VERSION 5.8 ;
BUSBITCHARS "[]" ;
DIVIDERCHAR "/" ;
UNITS
    DATABASE MICRONS 1000 ;
END UNITS

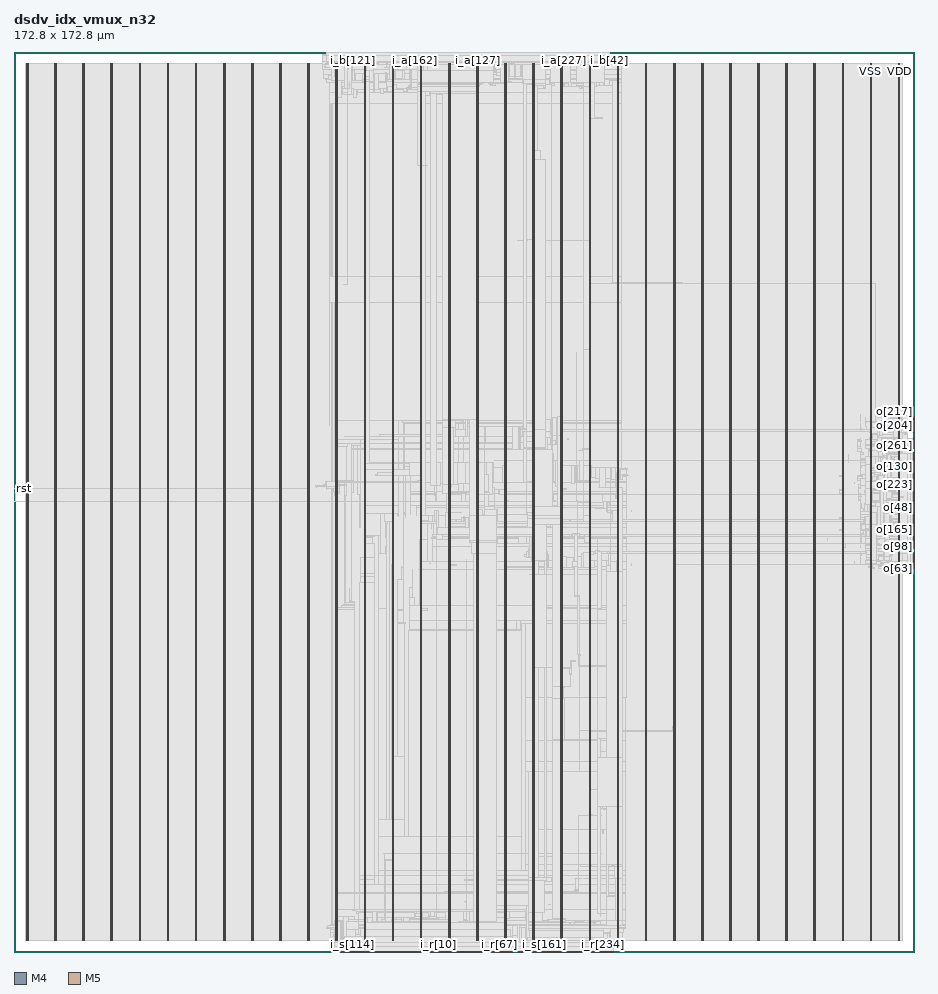
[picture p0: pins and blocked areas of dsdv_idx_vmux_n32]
MACRO dsdv_idx_vmux_n32
  FOREIGN dsdv_idx_vmux_n32 0 0 ;
  CLASS BLOCK ;
  SIZE 172.8 BY 172.8 ;
  PIN ck
    DIRECTION INPUT ;
    USE SIGNAL ;
    PORT
      LAYER M4 ;
        RECT  0 88.944 0.084 88.968 ;
    END
  END ck
  PIN fault
    DIRECTION OUTPUT ;
    USE SIGNAL ;
    PORT
      LAYER M4 ;
        RECT  172.716 86.736 172.8 86.76 ;
    END
  END fault
  PIN i_a[0]
    DIRECTION INPUT ;
    USE SIGNAL ;
    PORT
      LAYER M5 ;
        RECT  79.92 172.716 79.944 172.8 ;
    END
  END i_a[0]
  PIN i_a[100]
    DIRECTION INPUT ;
    USE SIGNAL ;
    PORT
      LAYER M5 ;
        RECT  86.448 172.716 86.472 172.8 ;
    END
  END i_a[100]
  PIN i_a[101]
    DIRECTION INPUT ;
    USE SIGNAL ;
    PORT
      LAYER M5 ;
        RECT  86.544 172.716 86.568 172.8 ;
    END
  END i_a[101]
  PIN i_a[102]
    DIRECTION INPUT ;
    USE SIGNAL ;
    PORT
      LAYER M5 ;
        RECT  86.64 172.716 86.664 172.8 ;
    END
  END i_a[102]
  PIN i_a[103]
    DIRECTION INPUT ;
    USE SIGNAL ;
    PORT
      LAYER M5 ;
        RECT  86.736 172.716 86.76 172.8 ;
    END
  END i_a[103]
  PIN i_a[104]
    DIRECTION INPUT ;
    USE SIGNAL ;
    PORT
      LAYER M5 ;
        RECT  86.832 172.716 86.856 172.8 ;
    END
  END i_a[104]
  PIN i_a[105]
    DIRECTION INPUT ;
    USE SIGNAL ;
    PORT
      LAYER M5 ;
        RECT  86.928 172.716 86.952 172.8 ;
    END
  END i_a[105]
  PIN i_a[106]
    DIRECTION INPUT ;
    USE SIGNAL ;
    PORT
      LAYER M5 ;
        RECT  87.024 172.716 87.048 172.8 ;
    END
  END i_a[106]
  PIN i_a[107]
    DIRECTION INPUT ;
    USE SIGNAL ;
    PORT
      LAYER M5 ;
        RECT  87.12 172.716 87.144 172.8 ;
    END
  END i_a[107]
  PIN i_a[108]
    DIRECTION INPUT ;
    USE SIGNAL ;
    PORT
      LAYER M5 ;
        RECT  87.216 172.716 87.24 172.8 ;
    END
  END i_a[108]
  PIN i_a[109]
    DIRECTION INPUT ;
    USE SIGNAL ;
    PORT
      LAYER M5 ;
        RECT  87.312 172.716 87.336 172.8 ;
    END
  END i_a[109]
  PIN i_a[10]
    DIRECTION INPUT ;
    USE SIGNAL ;
    PORT
      LAYER M5 ;
        RECT  80.88 172.716 80.904 172.8 ;
    END
  END i_a[10]
  PIN i_a[110]
    DIRECTION INPUT ;
    USE SIGNAL ;
    PORT
      LAYER M5 ;
        RECT  87.408 172.716 87.432 172.8 ;
    END
  END i_a[110]
  PIN i_a[111]
    DIRECTION INPUT ;
    USE SIGNAL ;
    PORT
      LAYER M5 ;
        RECT  87.504 172.716 87.528 172.8 ;
    END
  END i_a[111]
  PIN i_a[112]
    DIRECTION INPUT ;
    USE SIGNAL ;
    PORT
      LAYER M5 ;
        RECT  87.6 172.716 87.624 172.8 ;
    END
  END i_a[112]
  PIN i_a[113]
    DIRECTION INPUT ;
    USE SIGNAL ;
    PORT
      LAYER M5 ;
        RECT  87.696 172.716 87.72 172.8 ;
    END
  END i_a[113]
  PIN i_a[114]
    DIRECTION INPUT ;
    USE SIGNAL ;
    PORT
      LAYER M5 ;
        RECT  87.792 172.716 87.816 172.8 ;
    END
  END i_a[114]
  PIN i_a[115]
    DIRECTION INPUT ;
    USE SIGNAL ;
    PORT
      LAYER M5 ;
        RECT  87.888 172.716 87.912 172.8 ;
    END
  END i_a[115]
  PIN i_a[116]
    DIRECTION INPUT ;
    USE SIGNAL ;
    PORT
      LAYER M5 ;
        RECT  87.984 172.716 88.008 172.8 ;
    END
  END i_a[116]
  PIN i_a[117]
    DIRECTION INPUT ;
    USE SIGNAL ;
    PORT
      LAYER M5 ;
        RECT  88.08 172.716 88.104 172.8 ;
    END
  END i_a[117]
  PIN i_a[118]
    DIRECTION INPUT ;
    USE SIGNAL ;
    PORT
      LAYER M5 ;
        RECT  88.176 172.716 88.2 172.8 ;
    END
  END i_a[118]
  PIN i_a[119]
    DIRECTION INPUT ;
    USE SIGNAL ;
    PORT
      LAYER M5 ;
        RECT  88.272 172.716 88.296 172.8 ;
    END
  END i_a[119]
  PIN i_a[11]
    DIRECTION INPUT ;
    USE SIGNAL ;
    PORT
      LAYER M5 ;
        RECT  80.976 172.716 81 172.8 ;
    END
  END i_a[11]
  PIN i_a[120]
    DIRECTION INPUT ;
    USE SIGNAL ;
    PORT
      LAYER M5 ;
        RECT  88.368 172.716 88.392 172.8 ;
    END
  END i_a[120]
  PIN i_a[121]
    DIRECTION INPUT ;
    USE SIGNAL ;
    PORT
      LAYER M5 ;
        RECT  88.464 172.716 88.488 172.8 ;
    END
  END i_a[121]
  PIN i_a[122]
    DIRECTION INPUT ;
    USE SIGNAL ;
    PORT
      LAYER M5 ;
        RECT  88.56 172.716 88.584 172.8 ;
    END
  END i_a[122]
  PIN i_a[123]
    DIRECTION INPUT ;
    USE SIGNAL ;
    PORT
      LAYER M5 ;
        RECT  88.656 172.716 88.68 172.8 ;
    END
  END i_a[123]
  PIN i_a[124]
    DIRECTION INPUT ;
    USE SIGNAL ;
    PORT
      LAYER M5 ;
        RECT  88.752 172.716 88.776 172.8 ;
    END
  END i_a[124]
  PIN i_a[125]
    DIRECTION INPUT ;
    USE SIGNAL ;
    PORT
      LAYER M5 ;
        RECT  88.848 172.716 88.872 172.8 ;
    END
  END i_a[125]
  PIN i_a[126]
    DIRECTION INPUT ;
    USE SIGNAL ;
    PORT
      LAYER M5 ;
        RECT  88.944 172.716 88.968 172.8 ;
    END
  END i_a[126]
  PIN i_a[127]
    DIRECTION INPUT ;
    USE SIGNAL ;
    PORT
      LAYER M5 ;
        RECT  89.04 172.716 89.064 172.8 ;
    END
  END i_a[127]
  PIN i_a[128]
    DIRECTION INPUT ;
    USE SIGNAL ;
    PORT
      LAYER M5 ;
        RECT  89.136 172.716 89.16 172.8 ;
    END
  END i_a[128]
  PIN i_a[129]
    DIRECTION INPUT ;
    USE SIGNAL ;
    PORT
      LAYER M5 ;
        RECT  89.232 172.716 89.256 172.8 ;
    END
  END i_a[129]
  PIN i_a[12]
    DIRECTION INPUT ;
    USE SIGNAL ;
    PORT
      LAYER M5 ;
        RECT  81.072 172.716 81.096 172.8 ;
    END
  END i_a[12]
  PIN i_a[130]
    DIRECTION INPUT ;
    USE SIGNAL ;
    PORT
      LAYER M5 ;
        RECT  89.328 172.716 89.352 172.8 ;
    END
  END i_a[130]
  PIN i_a[131]
    DIRECTION INPUT ;
    USE SIGNAL ;
    PORT
      LAYER M5 ;
        RECT  89.424 172.716 89.448 172.8 ;
    END
  END i_a[131]
  PIN i_a[132]
    DIRECTION INPUT ;
    USE SIGNAL ;
    PORT
      LAYER M5 ;
        RECT  89.52 172.716 89.544 172.8 ;
    END
  END i_a[132]
  PIN i_a[133]
    DIRECTION INPUT ;
    USE SIGNAL ;
    PORT
      LAYER M5 ;
        RECT  89.616 172.716 89.64 172.8 ;
    END
  END i_a[133]
  PIN i_a[134]
    DIRECTION INPUT ;
    USE SIGNAL ;
    PORT
      LAYER M5 ;
        RECT  89.712 172.716 89.736 172.8 ;
    END
  END i_a[134]
  PIN i_a[135]
    DIRECTION INPUT ;
    USE SIGNAL ;
    PORT
      LAYER M5 ;
        RECT  89.808 172.716 89.832 172.8 ;
    END
  END i_a[135]
  PIN i_a[136]
    DIRECTION INPUT ;
    USE SIGNAL ;
    PORT
      LAYER M5 ;
        RECT  89.904 172.716 89.928 172.8 ;
    END
  END i_a[136]
  PIN i_a[137]
    DIRECTION INPUT ;
    USE SIGNAL ;
    PORT
      LAYER M5 ;
        RECT  90 172.716 90.024 172.8 ;
    END
  END i_a[137]
  PIN i_a[138]
    DIRECTION INPUT ;
    USE SIGNAL ;
    PORT
      LAYER M5 ;
        RECT  90.096 172.716 90.12 172.8 ;
    END
  END i_a[138]
  PIN i_a[139]
    DIRECTION INPUT ;
    USE SIGNAL ;
    PORT
      LAYER M5 ;
        RECT  90.192 172.716 90.216 172.8 ;
    END
  END i_a[139]
  PIN i_a[13]
    DIRECTION INPUT ;
    USE SIGNAL ;
    PORT
      LAYER M5 ;
        RECT  81.168 172.716 81.192 172.8 ;
    END
  END i_a[13]
  PIN i_a[140]
    DIRECTION INPUT ;
    USE SIGNAL ;
    PORT
      LAYER M5 ;
        RECT  90.288 172.716 90.312 172.8 ;
    END
  END i_a[140]
  PIN i_a[141]
    DIRECTION INPUT ;
    USE SIGNAL ;
    PORT
      LAYER M5 ;
        RECT  90.384 172.716 90.408 172.8 ;
    END
  END i_a[141]
  PIN i_a[142]
    DIRECTION INPUT ;
    USE SIGNAL ;
    PORT
      LAYER M5 ;
        RECT  90.48 172.716 90.504 172.8 ;
    END
  END i_a[142]
  PIN i_a[143]
    DIRECTION INPUT ;
    USE SIGNAL ;
    PORT
      LAYER M5 ;
        RECT  90.576 172.716 90.6 172.8 ;
    END
  END i_a[143]
  PIN i_a[144]
    DIRECTION INPUT ;
    USE SIGNAL ;
    PORT
      LAYER M5 ;
        RECT  90.672 172.716 90.696 172.8 ;
    END
  END i_a[144]
  PIN i_a[145]
    DIRECTION INPUT ;
    USE SIGNAL ;
    PORT
      LAYER M5 ;
        RECT  90.768 172.716 90.792 172.8 ;
    END
  END i_a[145]
  PIN i_a[146]
    DIRECTION INPUT ;
    USE SIGNAL ;
    PORT
      LAYER M5 ;
        RECT  90.864 172.716 90.888 172.8 ;
    END
  END i_a[146]
  PIN i_a[147]
    DIRECTION INPUT ;
    USE SIGNAL ;
    PORT
      LAYER M5 ;
        RECT  90.96 172.716 90.984 172.8 ;
    END
  END i_a[147]
  PIN i_a[148]
    DIRECTION INPUT ;
    USE SIGNAL ;
    PORT
      LAYER M5 ;
        RECT  91.056 172.716 91.08 172.8 ;
    END
  END i_a[148]
  PIN i_a[149]
    DIRECTION INPUT ;
    USE SIGNAL ;
    PORT
      LAYER M5 ;
        RECT  91.152 172.716 91.176 172.8 ;
    END
  END i_a[149]
  PIN i_a[14]
    DIRECTION INPUT ;
    USE SIGNAL ;
    PORT
      LAYER M5 ;
        RECT  81.264 172.716 81.288 172.8 ;
    END
  END i_a[14]
  PIN i_a[150]
    DIRECTION INPUT ;
    USE SIGNAL ;
    PORT
      LAYER M5 ;
        RECT  91.248 172.716 91.272 172.8 ;
    END
  END i_a[150]
  PIN i_a[151]
    DIRECTION INPUT ;
    USE SIGNAL ;
    PORT
      LAYER M5 ;
        RECT  91.344 172.716 91.368 172.8 ;
    END
  END i_a[151]
  PIN i_a[152]
    DIRECTION INPUT ;
    USE SIGNAL ;
    PORT
      LAYER M5 ;
        RECT  91.44 172.716 91.464 172.8 ;
    END
  END i_a[152]
  PIN i_a[153]
    DIRECTION INPUT ;
    USE SIGNAL ;
    PORT
      LAYER M5 ;
        RECT  91.536 172.716 91.56 172.8 ;
    END
  END i_a[153]
  PIN i_a[154]
    DIRECTION INPUT ;
    USE SIGNAL ;
    PORT
      LAYER M5 ;
        RECT  91.632 172.716 91.656 172.8 ;
    END
  END i_a[154]
  PIN i_a[155]
    DIRECTION INPUT ;
    USE SIGNAL ;
    PORT
      LAYER M5 ;
        RECT  91.728 172.716 91.752 172.8 ;
    END
  END i_a[155]
  PIN i_a[156]
    DIRECTION INPUT ;
    USE SIGNAL ;
    PORT
      LAYER M5 ;
        RECT  91.824 172.716 91.848 172.8 ;
    END
  END i_a[156]
  PIN i_a[157]
    DIRECTION INPUT ;
    USE SIGNAL ;
    PORT
      LAYER M5 ;
        RECT  91.92 172.716 91.944 172.8 ;
    END
  END i_a[157]
  PIN i_a[158]
    DIRECTION INPUT ;
    USE SIGNAL ;
    PORT
      LAYER M5 ;
        RECT  92.016 172.716 92.04 172.8 ;
    END
  END i_a[158]
  PIN i_a[159]
    DIRECTION INPUT ;
    USE SIGNAL ;
    PORT
      LAYER M5 ;
        RECT  92.112 172.716 92.136 172.8 ;
    END
  END i_a[159]
  PIN i_a[15]
    DIRECTION INPUT ;
    USE SIGNAL ;
    PORT
      LAYER M5 ;
        RECT  81.36 172.716 81.384 172.8 ;
    END
  END i_a[15]
  PIN i_a[160]
    DIRECTION INPUT ;
    USE SIGNAL ;
    PORT
      LAYER M5 ;
        RECT  76.848 172.716 76.872 172.8 ;
    END
  END i_a[160]
  PIN i_a[161]
    DIRECTION INPUT ;
    USE SIGNAL ;
    PORT
      LAYER M5 ;
        RECT  76.944 172.716 76.968 172.8 ;
    END
  END i_a[161]
  PIN i_a[162]
    DIRECTION INPUT ;
    USE SIGNAL ;
    PORT
      LAYER M5 ;
        RECT  77.04 172.716 77.064 172.8 ;
    END
  END i_a[162]
  PIN i_a[163]
    DIRECTION INPUT ;
    USE SIGNAL ;
    PORT
      LAYER M5 ;
        RECT  77.136 172.716 77.16 172.8 ;
    END
  END i_a[163]
  PIN i_a[164]
    DIRECTION INPUT ;
    USE SIGNAL ;
    PORT
      LAYER M5 ;
        RECT  77.232 172.716 77.256 172.8 ;
    END
  END i_a[164]
  PIN i_a[165]
    DIRECTION INPUT ;
    USE SIGNAL ;
    PORT
      LAYER M5 ;
        RECT  77.328 172.716 77.352 172.8 ;
    END
  END i_a[165]
  PIN i_a[166]
    DIRECTION INPUT ;
    USE SIGNAL ;
    PORT
      LAYER M5 ;
        RECT  77.424 172.716 77.448 172.8 ;
    END
  END i_a[166]
  PIN i_a[167]
    DIRECTION INPUT ;
    USE SIGNAL ;
    PORT
      LAYER M5 ;
        RECT  77.52 172.716 77.544 172.8 ;
    END
  END i_a[167]
  PIN i_a[168]
    DIRECTION INPUT ;
    USE SIGNAL ;
    PORT
      LAYER M5 ;
        RECT  77.616 172.716 77.64 172.8 ;
    END
  END i_a[168]
  PIN i_a[169]
    DIRECTION INPUT ;
    USE SIGNAL ;
    PORT
      LAYER M5 ;
        RECT  77.712 172.716 77.736 172.8 ;
    END
  END i_a[169]
  PIN i_a[16]
    DIRECTION INPUT ;
    USE SIGNAL ;
    PORT
      LAYER M5 ;
        RECT  81.456 172.716 81.48 172.8 ;
    END
  END i_a[16]
  PIN i_a[170]
    DIRECTION INPUT ;
    USE SIGNAL ;
    PORT
      LAYER M5 ;
        RECT  77.808 172.716 77.832 172.8 ;
    END
  END i_a[170]
  PIN i_a[171]
    DIRECTION INPUT ;
    USE SIGNAL ;
    PORT
      LAYER M5 ;
        RECT  77.904 172.716 77.928 172.8 ;
    END
  END i_a[171]
  PIN i_a[172]
    DIRECTION INPUT ;
    USE SIGNAL ;
    PORT
      LAYER M5 ;
        RECT  78 172.716 78.024 172.8 ;
    END
  END i_a[172]
  PIN i_a[173]
    DIRECTION INPUT ;
    USE SIGNAL ;
    PORT
      LAYER M5 ;
        RECT  78.096 172.716 78.12 172.8 ;
    END
  END i_a[173]
  PIN i_a[174]
    DIRECTION INPUT ;
    USE SIGNAL ;
    PORT
      LAYER M5 ;
        RECT  78.192 172.716 78.216 172.8 ;
    END
  END i_a[174]
  PIN i_a[175]
    DIRECTION INPUT ;
    USE SIGNAL ;
    PORT
      LAYER M5 ;
        RECT  78.288 172.716 78.312 172.8 ;
    END
  END i_a[175]
  PIN i_a[176]
    DIRECTION INPUT ;
    USE SIGNAL ;
    PORT
      LAYER M5 ;
        RECT  78.384 172.716 78.408 172.8 ;
    END
  END i_a[176]
  PIN i_a[177]
    DIRECTION INPUT ;
    USE SIGNAL ;
    PORT
      LAYER M5 ;
        RECT  78.48 172.716 78.504 172.8 ;
    END
  END i_a[177]
  PIN i_a[178]
    DIRECTION INPUT ;
    USE SIGNAL ;
    PORT
      LAYER M5 ;
        RECT  78.576 172.716 78.6 172.8 ;
    END
  END i_a[178]
  PIN i_a[179]
    DIRECTION INPUT ;
    USE SIGNAL ;
    PORT
      LAYER M5 ;
        RECT  78.672 172.716 78.696 172.8 ;
    END
  END i_a[179]
  PIN i_a[17]
    DIRECTION INPUT ;
    USE SIGNAL ;
    PORT
      LAYER M5 ;
        RECT  81.552 172.716 81.576 172.8 ;
    END
  END i_a[17]
  PIN i_a[180]
    DIRECTION INPUT ;
    USE SIGNAL ;
    PORT
      LAYER M5 ;
        RECT  78.768 172.716 78.792 172.8 ;
    END
  END i_a[180]
  PIN i_a[181]
    DIRECTION INPUT ;
    USE SIGNAL ;
    PORT
      LAYER M5 ;
        RECT  78.864 172.716 78.888 172.8 ;
    END
  END i_a[181]
  PIN i_a[182]
    DIRECTION INPUT ;
    USE SIGNAL ;
    PORT
      LAYER M5 ;
        RECT  78.96 172.716 78.984 172.8 ;
    END
  END i_a[182]
  PIN i_a[183]
    DIRECTION INPUT ;
    USE SIGNAL ;
    PORT
      LAYER M5 ;
        RECT  79.056 172.716 79.08 172.8 ;
    END
  END i_a[183]
  PIN i_a[184]
    DIRECTION INPUT ;
    USE SIGNAL ;
    PORT
      LAYER M5 ;
        RECT  79.152 172.716 79.176 172.8 ;
    END
  END i_a[184]
  PIN i_a[185]
    DIRECTION INPUT ;
    USE SIGNAL ;
    PORT
      LAYER M5 ;
        RECT  79.248 172.716 79.272 172.8 ;
    END
  END i_a[185]
  PIN i_a[186]
    DIRECTION INPUT ;
    USE SIGNAL ;
    PORT
      LAYER M5 ;
        RECT  79.344 172.716 79.368 172.8 ;
    END
  END i_a[186]
  PIN i_a[187]
    DIRECTION INPUT ;
    USE SIGNAL ;
    PORT
      LAYER M5 ;
        RECT  79.44 172.716 79.464 172.8 ;
    END
  END i_a[187]
  PIN i_a[188]
    DIRECTION INPUT ;
    USE SIGNAL ;
    PORT
      LAYER M5 ;
        RECT  79.536 172.716 79.56 172.8 ;
    END
  END i_a[188]
  PIN i_a[189]
    DIRECTION INPUT ;
    USE SIGNAL ;
    PORT
      LAYER M5 ;
        RECT  79.632 172.716 79.656 172.8 ;
    END
  END i_a[189]
  PIN i_a[18]
    DIRECTION INPUT ;
    USE SIGNAL ;
    PORT
      LAYER M5 ;
        RECT  81.648 172.716 81.672 172.8 ;
    END
  END i_a[18]
  PIN i_a[190]
    DIRECTION INPUT ;
    USE SIGNAL ;
    PORT
      LAYER M5 ;
        RECT  79.728 172.716 79.752 172.8 ;
    END
  END i_a[190]
  PIN i_a[191]
    DIRECTION INPUT ;
    USE SIGNAL ;
    PORT
      LAYER M5 ;
        RECT  79.824 172.716 79.848 172.8 ;
    END
  END i_a[191]
  PIN i_a[192]
    DIRECTION INPUT ;
    USE SIGNAL ;
    PORT
      LAYER M5 ;
        RECT  82.992 172.716 83.016 172.8 ;
    END
  END i_a[192]
  PIN i_a[193]
    DIRECTION INPUT ;
    USE SIGNAL ;
    PORT
      LAYER M5 ;
        RECT  83.088 172.716 83.112 172.8 ;
    END
  END i_a[193]
  PIN i_a[194]
    DIRECTION INPUT ;
    USE SIGNAL ;
    PORT
      LAYER M5 ;
        RECT  83.184 172.716 83.208 172.8 ;
    END
  END i_a[194]
  PIN i_a[195]
    DIRECTION INPUT ;
    USE SIGNAL ;
    PORT
      LAYER M5 ;
        RECT  83.28 172.716 83.304 172.8 ;
    END
  END i_a[195]
  PIN i_a[196]
    DIRECTION INPUT ;
    USE SIGNAL ;
    PORT
      LAYER M5 ;
        RECT  83.376 172.716 83.4 172.8 ;
    END
  END i_a[196]
  PIN i_a[197]
    DIRECTION INPUT ;
    USE SIGNAL ;
    PORT
      LAYER M5 ;
        RECT  83.472 172.716 83.496 172.8 ;
    END
  END i_a[197]
  PIN i_a[198]
    DIRECTION INPUT ;
    USE SIGNAL ;
    PORT
      LAYER M5 ;
        RECT  83.568 172.716 83.592 172.8 ;
    END
  END i_a[198]
  PIN i_a[199]
    DIRECTION INPUT ;
    USE SIGNAL ;
    PORT
      LAYER M5 ;
        RECT  83.664 172.716 83.688 172.8 ;
    END
  END i_a[199]
  PIN i_a[19]
    DIRECTION INPUT ;
    USE SIGNAL ;
    PORT
      LAYER M5 ;
        RECT  81.744 172.716 81.768 172.8 ;
    END
  END i_a[19]
  PIN i_a[1]
    DIRECTION INPUT ;
    USE SIGNAL ;
    PORT
      LAYER M5 ;
        RECT  80.016 172.716 80.04 172.8 ;
    END
  END i_a[1]
  PIN i_a[200]
    DIRECTION INPUT ;
    USE SIGNAL ;
    PORT
      LAYER M5 ;
        RECT  83.76 172.716 83.784 172.8 ;
    END
  END i_a[200]
  PIN i_a[201]
    DIRECTION INPUT ;
    USE SIGNAL ;
    PORT
      LAYER M5 ;
        RECT  83.856 172.716 83.88 172.8 ;
    END
  END i_a[201]
  PIN i_a[202]
    DIRECTION INPUT ;
    USE SIGNAL ;
    PORT
      LAYER M5 ;
        RECT  83.952 172.716 83.976 172.8 ;
    END
  END i_a[202]
  PIN i_a[203]
    DIRECTION INPUT ;
    USE SIGNAL ;
    PORT
      LAYER M5 ;
        RECT  84.048 172.716 84.072 172.8 ;
    END
  END i_a[203]
  PIN i_a[204]
    DIRECTION INPUT ;
    USE SIGNAL ;
    PORT
      LAYER M5 ;
        RECT  84.144 172.716 84.168 172.8 ;
    END
  END i_a[204]
  PIN i_a[205]
    DIRECTION INPUT ;
    USE SIGNAL ;
    PORT
      LAYER M5 ;
        RECT  84.24 172.716 84.264 172.8 ;
    END
  END i_a[205]
  PIN i_a[206]
    DIRECTION INPUT ;
    USE SIGNAL ;
    PORT
      LAYER M5 ;
        RECT  84.336 172.716 84.36 172.8 ;
    END
  END i_a[206]
  PIN i_a[207]
    DIRECTION INPUT ;
    USE SIGNAL ;
    PORT
      LAYER M5 ;
        RECT  84.432 172.716 84.456 172.8 ;
    END
  END i_a[207]
  PIN i_a[208]
    DIRECTION INPUT ;
    USE SIGNAL ;
    PORT
      LAYER M5 ;
        RECT  84.528 172.716 84.552 172.8 ;
    END
  END i_a[208]
  PIN i_a[209]
    DIRECTION INPUT ;
    USE SIGNAL ;
    PORT
      LAYER M5 ;
        RECT  84.624 172.716 84.648 172.8 ;
    END
  END i_a[209]
  PIN i_a[20]
    DIRECTION INPUT ;
    USE SIGNAL ;
    PORT
      LAYER M5 ;
        RECT  81.84 172.716 81.864 172.8 ;
    END
  END i_a[20]
  PIN i_a[210]
    DIRECTION INPUT ;
    USE SIGNAL ;
    PORT
      LAYER M5 ;
        RECT  84.72 172.716 84.744 172.8 ;
    END
  END i_a[210]
  PIN i_a[211]
    DIRECTION INPUT ;
    USE SIGNAL ;
    PORT
      LAYER M5 ;
        RECT  84.816 172.716 84.84 172.8 ;
    END
  END i_a[211]
  PIN i_a[212]
    DIRECTION INPUT ;
    USE SIGNAL ;
    PORT
      LAYER M5 ;
        RECT  84.912 172.716 84.936 172.8 ;
    END
  END i_a[212]
  PIN i_a[213]
    DIRECTION INPUT ;
    USE SIGNAL ;
    PORT
      LAYER M5 ;
        RECT  85.008 172.716 85.032 172.8 ;
    END
  END i_a[213]
  PIN i_a[214]
    DIRECTION INPUT ;
    USE SIGNAL ;
    PORT
      LAYER M5 ;
        RECT  85.104 172.716 85.128 172.8 ;
    END
  END i_a[214]
  PIN i_a[215]
    DIRECTION INPUT ;
    USE SIGNAL ;
    PORT
      LAYER M5 ;
        RECT  85.2 172.716 85.224 172.8 ;
    END
  END i_a[215]
  PIN i_a[216]
    DIRECTION INPUT ;
    USE SIGNAL ;
    PORT
      LAYER M5 ;
        RECT  85.296 172.716 85.32 172.8 ;
    END
  END i_a[216]
  PIN i_a[217]
    DIRECTION INPUT ;
    USE SIGNAL ;
    PORT
      LAYER M5 ;
        RECT  85.392 172.716 85.416 172.8 ;
    END
  END i_a[217]
  PIN i_a[218]
    DIRECTION INPUT ;
    USE SIGNAL ;
    PORT
      LAYER M5 ;
        RECT  85.488 172.716 85.512 172.8 ;
    END
  END i_a[218]
  PIN i_a[219]
    DIRECTION INPUT ;
    USE SIGNAL ;
    PORT
      LAYER M5 ;
        RECT  85.584 172.716 85.608 172.8 ;
    END
  END i_a[219]
  PIN i_a[21]
    DIRECTION INPUT ;
    USE SIGNAL ;
    PORT
      LAYER M5 ;
        RECT  81.936 172.716 81.96 172.8 ;
    END
  END i_a[21]
  PIN i_a[220]
    DIRECTION INPUT ;
    USE SIGNAL ;
    PORT
      LAYER M5 ;
        RECT  85.68 172.716 85.704 172.8 ;
    END
  END i_a[220]
  PIN i_a[221]
    DIRECTION INPUT ;
    USE SIGNAL ;
    PORT
      LAYER M5 ;
        RECT  85.776 172.716 85.8 172.8 ;
    END
  END i_a[221]
  PIN i_a[222]
    DIRECTION INPUT ;
    USE SIGNAL ;
    PORT
      LAYER M5 ;
        RECT  85.872 172.716 85.896 172.8 ;
    END
  END i_a[222]
  PIN i_a[223]
    DIRECTION INPUT ;
    USE SIGNAL ;
    PORT
      LAYER M5 ;
        RECT  85.968 172.716 85.992 172.8 ;
    END
  END i_a[223]
  PIN i_a[224]
    DIRECTION INPUT ;
    USE SIGNAL ;
    PORT
      LAYER M5 ;
        RECT  105.264 172.716 105.288 172.8 ;
    END
  END i_a[224]
  PIN i_a[225]
    DIRECTION INPUT ;
    USE SIGNAL ;
    PORT
      LAYER M5 ;
        RECT  105.36 172.716 105.384 172.8 ;
    END
  END i_a[225]
  PIN i_a[226]
    DIRECTION INPUT ;
    USE SIGNAL ;
    PORT
      LAYER M5 ;
        RECT  105.456 172.716 105.48 172.8 ;
    END
  END i_a[226]
  PIN i_a[227]
    DIRECTION INPUT ;
    USE SIGNAL ;
    PORT
      LAYER M5 ;
        RECT  105.552 172.716 105.576 172.8 ;
    END
  END i_a[227]
  PIN i_a[228]
    DIRECTION INPUT ;
    USE SIGNAL ;
    PORT
      LAYER M5 ;
        RECT  105.648 172.716 105.672 172.8 ;
    END
  END i_a[228]
  PIN i_a[229]
    DIRECTION INPUT ;
    USE SIGNAL ;
    PORT
      LAYER M5 ;
        RECT  105.744 172.716 105.768 172.8 ;
    END
  END i_a[229]
  PIN i_a[22]
    DIRECTION INPUT ;
    USE SIGNAL ;
    PORT
      LAYER M5 ;
        RECT  82.032 172.716 82.056 172.8 ;
    END
  END i_a[22]
  PIN i_a[230]
    DIRECTION INPUT ;
    USE SIGNAL ;
    PORT
      LAYER M5 ;
        RECT  105.84 172.716 105.864 172.8 ;
    END
  END i_a[230]
  PIN i_a[231]
    DIRECTION INPUT ;
    USE SIGNAL ;
    PORT
      LAYER M5 ;
        RECT  105.936 172.716 105.96 172.8 ;
    END
  END i_a[231]
  PIN i_a[232]
    DIRECTION INPUT ;
    USE SIGNAL ;
    PORT
      LAYER M5 ;
        RECT  106.032 172.716 106.056 172.8 ;
    END
  END i_a[232]
  PIN i_a[233]
    DIRECTION INPUT ;
    USE SIGNAL ;
    PORT
      LAYER M5 ;
        RECT  106.128 172.716 106.152 172.8 ;
    END
  END i_a[233]
  PIN i_a[234]
    DIRECTION INPUT ;
    USE SIGNAL ;
    PORT
      LAYER M5 ;
        RECT  106.224 172.716 106.248 172.8 ;
    END
  END i_a[234]
  PIN i_a[235]
    DIRECTION INPUT ;
    USE SIGNAL ;
    PORT
      LAYER M5 ;
        RECT  106.32 172.716 106.344 172.8 ;
    END
  END i_a[235]
  PIN i_a[236]
    DIRECTION INPUT ;
    USE SIGNAL ;
    PORT
      LAYER M5 ;
        RECT  106.416 172.716 106.44 172.8 ;
    END
  END i_a[236]
  PIN i_a[237]
    DIRECTION INPUT ;
    USE SIGNAL ;
    PORT
      LAYER M5 ;
        RECT  106.512 172.716 106.536 172.8 ;
    END
  END i_a[237]
  PIN i_a[238]
    DIRECTION INPUT ;
    USE SIGNAL ;
    PORT
      LAYER M5 ;
        RECT  106.608 172.716 106.632 172.8 ;
    END
  END i_a[238]
  PIN i_a[239]
    DIRECTION INPUT ;
    USE SIGNAL ;
    PORT
      LAYER M5 ;
        RECT  106.704 172.716 106.728 172.8 ;
    END
  END i_a[239]
  PIN i_a[23]
    DIRECTION INPUT ;
    USE SIGNAL ;
    PORT
      LAYER M5 ;
        RECT  82.128 172.716 82.152 172.8 ;
    END
  END i_a[23]
  PIN i_a[240]
    DIRECTION INPUT ;
    USE SIGNAL ;
    PORT
      LAYER M5 ;
        RECT  106.8 172.716 106.824 172.8 ;
    END
  END i_a[240]
  PIN i_a[241]
    DIRECTION INPUT ;
    USE SIGNAL ;
    PORT
      LAYER M5 ;
        RECT  106.896 172.716 106.92 172.8 ;
    END
  END i_a[241]
  PIN i_a[242]
    DIRECTION INPUT ;
    USE SIGNAL ;
    PORT
      LAYER M5 ;
        RECT  106.992 172.716 107.016 172.8 ;
    END
  END i_a[242]
  PIN i_a[243]
    DIRECTION INPUT ;
    USE SIGNAL ;
    PORT
      LAYER M5 ;
        RECT  107.088 172.716 107.112 172.8 ;
    END
  END i_a[243]
  PIN i_a[244]
    DIRECTION INPUT ;
    USE SIGNAL ;
    PORT
      LAYER M5 ;
        RECT  107.184 172.716 107.208 172.8 ;
    END
  END i_a[244]
  PIN i_a[245]
    DIRECTION INPUT ;
    USE SIGNAL ;
    PORT
      LAYER M5 ;
        RECT  107.28 172.716 107.304 172.8 ;
    END
  END i_a[245]
  PIN i_a[246]
    DIRECTION INPUT ;
    USE SIGNAL ;
    PORT
      LAYER M5 ;
        RECT  107.376 172.716 107.4 172.8 ;
    END
  END i_a[246]
  PIN i_a[247]
    DIRECTION INPUT ;
    USE SIGNAL ;
    PORT
      LAYER M5 ;
        RECT  107.472 172.716 107.496 172.8 ;
    END
  END i_a[247]
  PIN i_a[248]
    DIRECTION INPUT ;
    USE SIGNAL ;
    PORT
      LAYER M5 ;
        RECT  107.568 172.716 107.592 172.8 ;
    END
  END i_a[248]
  PIN i_a[249]
    DIRECTION INPUT ;
    USE SIGNAL ;
    PORT
      LAYER M5 ;
        RECT  107.664 172.716 107.688 172.8 ;
    END
  END i_a[249]
  PIN i_a[24]
    DIRECTION INPUT ;
    USE SIGNAL ;
    PORT
      LAYER M5 ;
        RECT  82.224 172.716 82.248 172.8 ;
    END
  END i_a[24]
  PIN i_a[250]
    DIRECTION INPUT ;
    USE SIGNAL ;
    PORT
      LAYER M5 ;
        RECT  107.76 172.716 107.784 172.8 ;
    END
  END i_a[250]
  PIN i_a[251]
    DIRECTION INPUT ;
    USE SIGNAL ;
    PORT
      LAYER M5 ;
        RECT  107.856 172.716 107.88 172.8 ;
    END
  END i_a[251]
  PIN i_a[252]
    DIRECTION INPUT ;
    USE SIGNAL ;
    PORT
      LAYER M5 ;
        RECT  107.952 172.716 107.976 172.8 ;
    END
  END i_a[252]
  PIN i_a[253]
    DIRECTION INPUT ;
    USE SIGNAL ;
    PORT
      LAYER M5 ;
        RECT  108.048 172.716 108.072 172.8 ;
    END
  END i_a[253]
  PIN i_a[254]
    DIRECTION INPUT ;
    USE SIGNAL ;
    PORT
      LAYER M5 ;
        RECT  108.144 172.716 108.168 172.8 ;
    END
  END i_a[254]
  PIN i_a[255]
    DIRECTION INPUT ;
    USE SIGNAL ;
    PORT
      LAYER M5 ;
        RECT  108.24 172.716 108.264 172.8 ;
    END
  END i_a[255]
  PIN i_a[256]
    DIRECTION INPUT ;
    USE SIGNAL ;
    PORT
      LAYER M5 ;
        RECT  60.72 172.716 60.744 172.8 ;
    END
  END i_a[256]
  PIN i_a[257]
    DIRECTION INPUT ;
    USE SIGNAL ;
    PORT
      LAYER M5 ;
        RECT  60.816 172.716 60.84 172.8 ;
    END
  END i_a[257]
  PIN i_a[258]
    DIRECTION INPUT ;
    USE SIGNAL ;
    PORT
      LAYER M5 ;
        RECT  60.912 172.716 60.936 172.8 ;
    END
  END i_a[258]
  PIN i_a[259]
    DIRECTION INPUT ;
    USE SIGNAL ;
    PORT
      LAYER M5 ;
        RECT  61.008 172.716 61.032 172.8 ;
    END
  END i_a[259]
  PIN i_a[25]
    DIRECTION INPUT ;
    USE SIGNAL ;
    PORT
      LAYER M5 ;
        RECT  82.32 172.716 82.344 172.8 ;
    END
  END i_a[25]
  PIN i_a[260]
    DIRECTION INPUT ;
    USE SIGNAL ;
    PORT
      LAYER M5 ;
        RECT  61.104 172.716 61.128 172.8 ;
    END
  END i_a[260]
  PIN i_a[261]
    DIRECTION INPUT ;
    USE SIGNAL ;
    PORT
      LAYER M5 ;
        RECT  61.2 172.716 61.224 172.8 ;
    END
  END i_a[261]
  PIN i_a[262]
    DIRECTION INPUT ;
    USE SIGNAL ;
    PORT
      LAYER M5 ;
        RECT  61.296 172.716 61.32 172.8 ;
    END
  END i_a[262]
  PIN i_a[263]
    DIRECTION INPUT ;
    USE SIGNAL ;
    PORT
      LAYER M5 ;
        RECT  61.392 172.716 61.416 172.8 ;
    END
  END i_a[263]
  PIN i_a[264]
    DIRECTION INPUT ;
    USE SIGNAL ;
    PORT
      LAYER M5 ;
        RECT  61.488 172.716 61.512 172.8 ;
    END
  END i_a[264]
  PIN i_a[265]
    DIRECTION INPUT ;
    USE SIGNAL ;
    PORT
      LAYER M5 ;
        RECT  61.584 172.716 61.608 172.8 ;
    END
  END i_a[265]
  PIN i_a[266]
    DIRECTION INPUT ;
    USE SIGNAL ;
    PORT
      LAYER M5 ;
        RECT  61.68 172.716 61.704 172.8 ;
    END
  END i_a[266]
  PIN i_a[267]
    DIRECTION INPUT ;
    USE SIGNAL ;
    PORT
      LAYER M5 ;
        RECT  61.776 172.716 61.8 172.8 ;
    END
  END i_a[267]
  PIN i_a[268]
    DIRECTION INPUT ;
    USE SIGNAL ;
    PORT
      LAYER M5 ;
        RECT  61.872 172.716 61.896 172.8 ;
    END
  END i_a[268]
  PIN i_a[269]
    DIRECTION INPUT ;
    USE SIGNAL ;
    PORT
      LAYER M5 ;
        RECT  61.968 172.716 61.992 172.8 ;
    END
  END i_a[269]
  PIN i_a[26]
    DIRECTION INPUT ;
    USE SIGNAL ;
    PORT
      LAYER M5 ;
        RECT  82.416 172.716 82.44 172.8 ;
    END
  END i_a[26]
  PIN i_a[270]
    DIRECTION INPUT ;
    USE SIGNAL ;
    PORT
      LAYER M5 ;
        RECT  62.064 172.716 62.088 172.8 ;
    END
  END i_a[270]
  PIN i_a[271]
    DIRECTION INPUT ;
    USE SIGNAL ;
    PORT
      LAYER M5 ;
        RECT  62.16 172.716 62.184 172.8 ;
    END
  END i_a[271]
  PIN i_a[272]
    DIRECTION INPUT ;
    USE SIGNAL ;
    PORT
      LAYER M5 ;
        RECT  62.256 172.716 62.28 172.8 ;
    END
  END i_a[272]
  PIN i_a[273]
    DIRECTION INPUT ;
    USE SIGNAL ;
    PORT
      LAYER M5 ;
        RECT  62.352 172.716 62.376 172.8 ;
    END
  END i_a[273]
  PIN i_a[274]
    DIRECTION INPUT ;
    USE SIGNAL ;
    PORT
      LAYER M5 ;
        RECT  62.448 172.716 62.472 172.8 ;
    END
  END i_a[274]
  PIN i_a[275]
    DIRECTION INPUT ;
    USE SIGNAL ;
    PORT
      LAYER M5 ;
        RECT  62.544 172.716 62.568 172.8 ;
    END
  END i_a[275]
  PIN i_a[27]
    DIRECTION INPUT ;
    USE SIGNAL ;
    PORT
      LAYER M5 ;
        RECT  82.512 172.716 82.536 172.8 ;
    END
  END i_a[27]
  PIN i_a[28]
    DIRECTION INPUT ;
    USE SIGNAL ;
    PORT
      LAYER M5 ;
        RECT  82.608 172.716 82.632 172.8 ;
    END
  END i_a[28]
  PIN i_a[29]
    DIRECTION INPUT ;
    USE SIGNAL ;
    PORT
      LAYER M5 ;
        RECT  82.704 172.716 82.728 172.8 ;
    END
  END i_a[29]
  PIN i_a[2]
    DIRECTION INPUT ;
    USE SIGNAL ;
    PORT
      LAYER M5 ;
        RECT  80.112 172.716 80.136 172.8 ;
    END
  END i_a[2]
  PIN i_a[30]
    DIRECTION INPUT ;
    USE SIGNAL ;
    PORT
      LAYER M5 ;
        RECT  82.8 172.716 82.824 172.8 ;
    END
  END i_a[30]
  PIN i_a[31]
    DIRECTION INPUT ;
    USE SIGNAL ;
    PORT
      LAYER M5 ;
        RECT  82.896 172.716 82.92 172.8 ;
    END
  END i_a[31]
  PIN i_a[32]
    DIRECTION INPUT ;
    USE SIGNAL ;
    PORT
      LAYER M5 ;
        RECT  108.336 172.716 108.36 172.8 ;
    END
  END i_a[32]
  PIN i_a[33]
    DIRECTION INPUT ;
    USE SIGNAL ;
    PORT
      LAYER M5 ;
        RECT  108.432 172.716 108.456 172.8 ;
    END
  END i_a[33]
  PIN i_a[34]
    DIRECTION INPUT ;
    USE SIGNAL ;
    PORT
      LAYER M5 ;
        RECT  108.528 172.716 108.552 172.8 ;
    END
  END i_a[34]
  PIN i_a[35]
    DIRECTION INPUT ;
    USE SIGNAL ;
    PORT
      LAYER M5 ;
        RECT  108.624 172.716 108.648 172.8 ;
    END
  END i_a[35]
  PIN i_a[36]
    DIRECTION INPUT ;
    USE SIGNAL ;
    PORT
      LAYER M5 ;
        RECT  108.72 172.716 108.744 172.8 ;
    END
  END i_a[36]
  PIN i_a[37]
    DIRECTION INPUT ;
    USE SIGNAL ;
    PORT
      LAYER M5 ;
        RECT  108.816 172.716 108.84 172.8 ;
    END
  END i_a[37]
  PIN i_a[38]
    DIRECTION INPUT ;
    USE SIGNAL ;
    PORT
      LAYER M5 ;
        RECT  108.912 172.716 108.936 172.8 ;
    END
  END i_a[38]
  PIN i_a[39]
    DIRECTION INPUT ;
    USE SIGNAL ;
    PORT
      LAYER M5 ;
        RECT  109.008 172.716 109.032 172.8 ;
    END
  END i_a[39]
  PIN i_a[3]
    DIRECTION INPUT ;
    USE SIGNAL ;
    PORT
      LAYER M5 ;
        RECT  80.208 172.716 80.232 172.8 ;
    END
  END i_a[3]
  PIN i_a[40]
    DIRECTION INPUT ;
    USE SIGNAL ;
    PORT
      LAYER M5 ;
        RECT  109.104 172.716 109.128 172.8 ;
    END
  END i_a[40]
  PIN i_a[41]
    DIRECTION INPUT ;
    USE SIGNAL ;
    PORT
      LAYER M5 ;
        RECT  109.2 172.716 109.224 172.8 ;
    END
  END i_a[41]
  PIN i_a[42]
    DIRECTION INPUT ;
    USE SIGNAL ;
    PORT
      LAYER M5 ;
        RECT  109.296 172.716 109.32 172.8 ;
    END
  END i_a[42]
  PIN i_a[43]
    DIRECTION INPUT ;
    USE SIGNAL ;
    PORT
      LAYER M5 ;
        RECT  109.392 172.716 109.416 172.8 ;
    END
  END i_a[43]
  PIN i_a[44]
    DIRECTION INPUT ;
    USE SIGNAL ;
    PORT
      LAYER M5 ;
        RECT  109.488 172.716 109.512 172.8 ;
    END
  END i_a[44]
  PIN i_a[45]
    DIRECTION INPUT ;
    USE SIGNAL ;
    PORT
      LAYER M5 ;
        RECT  109.584 172.716 109.608 172.8 ;
    END
  END i_a[45]
  PIN i_a[46]
    DIRECTION INPUT ;
    USE SIGNAL ;
    PORT
      LAYER M5 ;
        RECT  109.68 172.716 109.704 172.8 ;
    END
  END i_a[46]
  PIN i_a[47]
    DIRECTION INPUT ;
    USE SIGNAL ;
    PORT
      LAYER M5 ;
        RECT  109.776 172.716 109.8 172.8 ;
    END
  END i_a[47]
  PIN i_a[48]
    DIRECTION INPUT ;
    USE SIGNAL ;
    PORT
      LAYER M5 ;
        RECT  109.872 172.716 109.896 172.8 ;
    END
  END i_a[48]
  PIN i_a[49]
    DIRECTION INPUT ;
    USE SIGNAL ;
    PORT
      LAYER M5 ;
        RECT  109.968 172.716 109.992 172.8 ;
    END
  END i_a[49]
  PIN i_a[4]
    DIRECTION INPUT ;
    USE SIGNAL ;
    PORT
      LAYER M5 ;
        RECT  80.304 172.716 80.328 172.8 ;
    END
  END i_a[4]
  PIN i_a[50]
    DIRECTION INPUT ;
    USE SIGNAL ;
    PORT
      LAYER M5 ;
        RECT  110.064 172.716 110.088 172.8 ;
    END
  END i_a[50]
  PIN i_a[51]
    DIRECTION INPUT ;
    USE SIGNAL ;
    PORT
      LAYER M5 ;
        RECT  110.16 172.716 110.184 172.8 ;
    END
  END i_a[51]
  PIN i_a[52]
    DIRECTION INPUT ;
    USE SIGNAL ;
    PORT
      LAYER M5 ;
        RECT  110.256 172.716 110.28 172.8 ;
    END
  END i_a[52]
  PIN i_a[53]
    DIRECTION INPUT ;
    USE SIGNAL ;
    PORT
      LAYER M5 ;
        RECT  110.352 172.716 110.376 172.8 ;
    END
  END i_a[53]
  PIN i_a[54]
    DIRECTION INPUT ;
    USE SIGNAL ;
    PORT
      LAYER M5 ;
        RECT  110.448 172.716 110.472 172.8 ;
    END
  END i_a[54]
  PIN i_a[55]
    DIRECTION INPUT ;
    USE SIGNAL ;
    PORT
      LAYER M5 ;
        RECT  110.544 172.716 110.568 172.8 ;
    END
  END i_a[55]
  PIN i_a[56]
    DIRECTION INPUT ;
    USE SIGNAL ;
    PORT
      LAYER M5 ;
        RECT  110.64 172.716 110.664 172.8 ;
    END
  END i_a[56]
  PIN i_a[57]
    DIRECTION INPUT ;
    USE SIGNAL ;
    PORT
      LAYER M5 ;
        RECT  110.736 172.716 110.76 172.8 ;
    END
  END i_a[57]
  PIN i_a[58]
    DIRECTION INPUT ;
    USE SIGNAL ;
    PORT
      LAYER M5 ;
        RECT  110.832 172.716 110.856 172.8 ;
    END
  END i_a[58]
  PIN i_a[59]
    DIRECTION INPUT ;
    USE SIGNAL ;
    PORT
      LAYER M5 ;
        RECT  110.928 172.716 110.952 172.8 ;
    END
  END i_a[59]
  PIN i_a[5]
    DIRECTION INPUT ;
    USE SIGNAL ;
    PORT
      LAYER M5 ;
        RECT  80.4 172.716 80.424 172.8 ;
    END
  END i_a[5]
  PIN i_a[60]
    DIRECTION INPUT ;
    USE SIGNAL ;
    PORT
      LAYER M5 ;
        RECT  111.024 172.716 111.048 172.8 ;
    END
  END i_a[60]
  PIN i_a[61]
    DIRECTION INPUT ;
    USE SIGNAL ;
    PORT
      LAYER M5 ;
        RECT  111.12 172.716 111.144 172.8 ;
    END
  END i_a[61]
  PIN i_a[62]
    DIRECTION INPUT ;
    USE SIGNAL ;
    PORT
      LAYER M5 ;
        RECT  111.216 172.716 111.24 172.8 ;
    END
  END i_a[62]
  PIN i_a[63]
    DIRECTION INPUT ;
    USE SIGNAL ;
    PORT
      LAYER M5 ;
        RECT  111.312 172.716 111.336 172.8 ;
    END
  END i_a[63]
  PIN i_a[64]
    DIRECTION INPUT ;
    USE SIGNAL ;
    PORT
      LAYER M5 ;
        RECT  92.208 172.716 92.232 172.8 ;
    END
  END i_a[64]
  PIN i_a[65]
    DIRECTION INPUT ;
    USE SIGNAL ;
    PORT
      LAYER M5 ;
        RECT  92.304 172.716 92.328 172.8 ;
    END
  END i_a[65]
  PIN i_a[66]
    DIRECTION INPUT ;
    USE SIGNAL ;
    PORT
      LAYER M5 ;
        RECT  92.4 172.716 92.424 172.8 ;
    END
  END i_a[66]
  PIN i_a[67]
    DIRECTION INPUT ;
    USE SIGNAL ;
    PORT
      LAYER M5 ;
        RECT  92.496 172.716 92.52 172.8 ;
    END
  END i_a[67]
  PIN i_a[68]
    DIRECTION INPUT ;
    USE SIGNAL ;
    PORT
      LAYER M5 ;
        RECT  92.592 172.716 92.616 172.8 ;
    END
  END i_a[68]
  PIN i_a[69]
    DIRECTION INPUT ;
    USE SIGNAL ;
    PORT
      LAYER M5 ;
        RECT  92.688 172.716 92.712 172.8 ;
    END
  END i_a[69]
  PIN i_a[6]
    DIRECTION INPUT ;
    USE SIGNAL ;
    PORT
      LAYER M5 ;
        RECT  80.496 172.716 80.52 172.8 ;
    END
  END i_a[6]
  PIN i_a[70]
    DIRECTION INPUT ;
    USE SIGNAL ;
    PORT
      LAYER M5 ;
        RECT  92.784 172.716 92.808 172.8 ;
    END
  END i_a[70]
  PIN i_a[71]
    DIRECTION INPUT ;
    USE SIGNAL ;
    PORT
      LAYER M5 ;
        RECT  92.88 172.716 92.904 172.8 ;
    END
  END i_a[71]
  PIN i_a[72]
    DIRECTION INPUT ;
    USE SIGNAL ;
    PORT
      LAYER M5 ;
        RECT  92.976 172.716 93 172.8 ;
    END
  END i_a[72]
  PIN i_a[73]
    DIRECTION INPUT ;
    USE SIGNAL ;
    PORT
      LAYER M5 ;
        RECT  93.072 172.716 93.096 172.8 ;
    END
  END i_a[73]
  PIN i_a[74]
    DIRECTION INPUT ;
    USE SIGNAL ;
    PORT
      LAYER M5 ;
        RECT  93.168 172.716 93.192 172.8 ;
    END
  END i_a[74]
  PIN i_a[75]
    DIRECTION INPUT ;
    USE SIGNAL ;
    PORT
      LAYER M5 ;
        RECT  93.264 172.716 93.288 172.8 ;
    END
  END i_a[75]
  PIN i_a[76]
    DIRECTION INPUT ;
    USE SIGNAL ;
    PORT
      LAYER M5 ;
        RECT  93.36 172.716 93.384 172.8 ;
    END
  END i_a[76]
  PIN i_a[77]
    DIRECTION INPUT ;
    USE SIGNAL ;
    PORT
      LAYER M5 ;
        RECT  93.456 172.716 93.48 172.8 ;
    END
  END i_a[77]
  PIN i_a[78]
    DIRECTION INPUT ;
    USE SIGNAL ;
    PORT
      LAYER M5 ;
        RECT  93.552 172.716 93.576 172.8 ;
    END
  END i_a[78]
  PIN i_a[79]
    DIRECTION INPUT ;
    USE SIGNAL ;
    PORT
      LAYER M5 ;
        RECT  93.648 172.716 93.672 172.8 ;
    END
  END i_a[79]
  PIN i_a[7]
    DIRECTION INPUT ;
    USE SIGNAL ;
    PORT
      LAYER M5 ;
        RECT  80.592 172.716 80.616 172.8 ;
    END
  END i_a[7]
  PIN i_a[80]
    DIRECTION INPUT ;
    USE SIGNAL ;
    PORT
      LAYER M5 ;
        RECT  93.744 172.716 93.768 172.8 ;
    END
  END i_a[80]
  PIN i_a[81]
    DIRECTION INPUT ;
    USE SIGNAL ;
    PORT
      LAYER M5 ;
        RECT  93.84 172.716 93.864 172.8 ;
    END
  END i_a[81]
  PIN i_a[82]
    DIRECTION INPUT ;
    USE SIGNAL ;
    PORT
      LAYER M5 ;
        RECT  93.936 172.716 93.96 172.8 ;
    END
  END i_a[82]
  PIN i_a[83]
    DIRECTION INPUT ;
    USE SIGNAL ;
    PORT
      LAYER M5 ;
        RECT  94.032 172.716 94.056 172.8 ;
    END
  END i_a[83]
  PIN i_a[84]
    DIRECTION INPUT ;
    USE SIGNAL ;
    PORT
      LAYER M5 ;
        RECT  94.128 172.716 94.152 172.8 ;
    END
  END i_a[84]
  PIN i_a[85]
    DIRECTION INPUT ;
    USE SIGNAL ;
    PORT
      LAYER M5 ;
        RECT  94.224 172.716 94.248 172.8 ;
    END
  END i_a[85]
  PIN i_a[86]
    DIRECTION INPUT ;
    USE SIGNAL ;
    PORT
      LAYER M5 ;
        RECT  94.32 172.716 94.344 172.8 ;
    END
  END i_a[86]
  PIN i_a[87]
    DIRECTION INPUT ;
    USE SIGNAL ;
    PORT
      LAYER M5 ;
        RECT  94.416 172.716 94.44 172.8 ;
    END
  END i_a[87]
  PIN i_a[88]
    DIRECTION INPUT ;
    USE SIGNAL ;
    PORT
      LAYER M5 ;
        RECT  94.512 172.716 94.536 172.8 ;
    END
  END i_a[88]
  PIN i_a[89]
    DIRECTION INPUT ;
    USE SIGNAL ;
    PORT
      LAYER M5 ;
        RECT  94.608 172.716 94.632 172.8 ;
    END
  END i_a[89]
  PIN i_a[8]
    DIRECTION INPUT ;
    USE SIGNAL ;
    PORT
      LAYER M5 ;
        RECT  80.688 172.716 80.712 172.8 ;
    END
  END i_a[8]
  PIN i_a[90]
    DIRECTION INPUT ;
    USE SIGNAL ;
    PORT
      LAYER M5 ;
        RECT  94.704 172.716 94.728 172.8 ;
    END
  END i_a[90]
  PIN i_a[91]
    DIRECTION INPUT ;
    USE SIGNAL ;
    PORT
      LAYER M5 ;
        RECT  94.8 172.716 94.824 172.8 ;
    END
  END i_a[91]
  PIN i_a[92]
    DIRECTION INPUT ;
    USE SIGNAL ;
    PORT
      LAYER M5 ;
        RECT  94.896 172.716 94.92 172.8 ;
    END
  END i_a[92]
  PIN i_a[93]
    DIRECTION INPUT ;
    USE SIGNAL ;
    PORT
      LAYER M5 ;
        RECT  94.992 172.716 95.016 172.8 ;
    END
  END i_a[93]
  PIN i_a[94]
    DIRECTION INPUT ;
    USE SIGNAL ;
    PORT
      LAYER M5 ;
        RECT  95.088 172.716 95.112 172.8 ;
    END
  END i_a[94]
  PIN i_a[95]
    DIRECTION INPUT ;
    USE SIGNAL ;
    PORT
      LAYER M5 ;
        RECT  95.184 172.716 95.208 172.8 ;
    END
  END i_a[95]
  PIN i_a[96]
    DIRECTION INPUT ;
    USE SIGNAL ;
    PORT
      LAYER M5 ;
        RECT  86.064 172.716 86.088 172.8 ;
    END
  END i_a[96]
  PIN i_a[97]
    DIRECTION INPUT ;
    USE SIGNAL ;
    PORT
      LAYER M5 ;
        RECT  86.16 172.716 86.184 172.8 ;
    END
  END i_a[97]
  PIN i_a[98]
    DIRECTION INPUT ;
    USE SIGNAL ;
    PORT
      LAYER M5 ;
        RECT  86.256 172.716 86.28 172.8 ;
    END
  END i_a[98]
  PIN i_a[99]
    DIRECTION INPUT ;
    USE SIGNAL ;
    PORT
      LAYER M5 ;
        RECT  86.352 172.716 86.376 172.8 ;
    END
  END i_a[99]
  PIN i_a[9]
    DIRECTION INPUT ;
    USE SIGNAL ;
    PORT
      LAYER M5 ;
        RECT  80.784 172.716 80.808 172.8 ;
    END
  END i_a[9]
  PIN i_b[0]
    DIRECTION INPUT ;
    USE SIGNAL ;
    PORT
      LAYER M5 ;
        RECT  62.64 172.716 62.664 172.8 ;
    END
  END i_b[0]
  PIN i_b[100]
    DIRECTION INPUT ;
    USE SIGNAL ;
    PORT
      LAYER M5 ;
        RECT  98.352 172.716 98.376 172.8 ;
    END
  END i_b[100]
  PIN i_b[101]
    DIRECTION INPUT ;
    USE SIGNAL ;
    PORT
      LAYER M5 ;
        RECT  98.448 172.716 98.472 172.8 ;
    END
  END i_b[101]
  PIN i_b[102]
    DIRECTION INPUT ;
    USE SIGNAL ;
    PORT
      LAYER M5 ;
        RECT  98.544 172.716 98.568 172.8 ;
    END
  END i_b[102]
  PIN i_b[103]
    DIRECTION INPUT ;
    USE SIGNAL ;
    PORT
      LAYER M5 ;
        RECT  98.64 172.716 98.664 172.8 ;
    END
  END i_b[103]
  PIN i_b[104]
    DIRECTION INPUT ;
    USE SIGNAL ;
    PORT
      LAYER M5 ;
        RECT  98.736 172.716 98.76 172.8 ;
    END
  END i_b[104]
  PIN i_b[105]
    DIRECTION INPUT ;
    USE SIGNAL ;
    PORT
      LAYER M5 ;
        RECT  98.832 172.716 98.856 172.8 ;
    END
  END i_b[105]
  PIN i_b[106]
    DIRECTION INPUT ;
    USE SIGNAL ;
    PORT
      LAYER M5 ;
        RECT  98.928 172.716 98.952 172.8 ;
    END
  END i_b[106]
  PIN i_b[107]
    DIRECTION INPUT ;
    USE SIGNAL ;
    PORT
      LAYER M5 ;
        RECT  99.024 172.716 99.048 172.8 ;
    END
  END i_b[107]
  PIN i_b[108]
    DIRECTION INPUT ;
    USE SIGNAL ;
    PORT
      LAYER M5 ;
        RECT  63.792 172.716 63.816 172.8 ;
    END
  END i_b[108]
  PIN i_b[109]
    DIRECTION INPUT ;
    USE SIGNAL ;
    PORT
      LAYER M5 ;
        RECT  63.888 172.716 63.912 172.8 ;
    END
  END i_b[109]
  PIN i_b[10]
    DIRECTION INPUT ;
    USE SIGNAL ;
    PORT
      LAYER M5 ;
        RECT  63.6 172.716 63.624 172.8 ;
    END
  END i_b[10]
  PIN i_b[110]
    DIRECTION INPUT ;
    USE SIGNAL ;
    PORT
      LAYER M5 ;
        RECT  63.984 172.716 64.008 172.8 ;
    END
  END i_b[110]
  PIN i_b[111]
    DIRECTION INPUT ;
    USE SIGNAL ;
    PORT
      LAYER M5 ;
        RECT  64.08 172.716 64.104 172.8 ;
    END
  END i_b[111]
  PIN i_b[112]
    DIRECTION INPUT ;
    USE SIGNAL ;
    PORT
      LAYER M5 ;
        RECT  64.176 172.716 64.2 172.8 ;
    END
  END i_b[112]
  PIN i_b[113]
    DIRECTION INPUT ;
    USE SIGNAL ;
    PORT
      LAYER M5 ;
        RECT  64.272 172.716 64.296 172.8 ;
    END
  END i_b[113]
  PIN i_b[114]
    DIRECTION INPUT ;
    USE SIGNAL ;
    PORT
      LAYER M5 ;
        RECT  64.368 172.716 64.392 172.8 ;
    END
  END i_b[114]
  PIN i_b[115]
    DIRECTION INPUT ;
    USE SIGNAL ;
    PORT
      LAYER M5 ;
        RECT  64.464 172.716 64.488 172.8 ;
    END
  END i_b[115]
  PIN i_b[116]
    DIRECTION INPUT ;
    USE SIGNAL ;
    PORT
      LAYER M5 ;
        RECT  64.56 172.716 64.584 172.8 ;
    END
  END i_b[116]
  PIN i_b[117]
    DIRECTION INPUT ;
    USE SIGNAL ;
    PORT
      LAYER M5 ;
        RECT  64.656 172.716 64.68 172.8 ;
    END
  END i_b[117]
  PIN i_b[118]
    DIRECTION INPUT ;
    USE SIGNAL ;
    PORT
      LAYER M5 ;
        RECT  64.752 172.716 64.776 172.8 ;
    END
  END i_b[118]
  PIN i_b[119]
    DIRECTION INPUT ;
    USE SIGNAL ;
    PORT
      LAYER M5 ;
        RECT  64.848 172.716 64.872 172.8 ;
    END
  END i_b[119]
  PIN i_b[11]
    DIRECTION INPUT ;
    USE SIGNAL ;
    PORT
      LAYER M5 ;
        RECT  63.696 172.716 63.72 172.8 ;
    END
  END i_b[11]
  PIN i_b[120]
    DIRECTION INPUT ;
    USE SIGNAL ;
    PORT
      LAYER M5 ;
        RECT  64.944 172.716 64.968 172.8 ;
    END
  END i_b[120]
  PIN i_b[121]
    DIRECTION INPUT ;
    USE SIGNAL ;
    PORT
      LAYER M5 ;
        RECT  65.04 172.716 65.064 172.8 ;
    END
  END i_b[121]
  PIN i_b[122]
    DIRECTION INPUT ;
    USE SIGNAL ;
    PORT
      LAYER M5 ;
        RECT  65.136 172.716 65.16 172.8 ;
    END
  END i_b[122]
  PIN i_b[123]
    DIRECTION INPUT ;
    USE SIGNAL ;
    PORT
      LAYER M5 ;
        RECT  65.232 172.716 65.256 172.8 ;
    END
  END i_b[123]
  PIN i_b[124]
    DIRECTION INPUT ;
    USE SIGNAL ;
    PORT
      LAYER M5 ;
        RECT  65.328 172.716 65.352 172.8 ;
    END
  END i_b[124]
  PIN i_b[125]
    DIRECTION INPUT ;
    USE SIGNAL ;
    PORT
      LAYER M5 ;
        RECT  65.424 172.716 65.448 172.8 ;
    END
  END i_b[125]
  PIN i_b[126]
    DIRECTION INPUT ;
    USE SIGNAL ;
    PORT
      LAYER M5 ;
        RECT  65.52 172.716 65.544 172.8 ;
    END
  END i_b[126]
  PIN i_b[127]
    DIRECTION INPUT ;
    USE SIGNAL ;
    PORT
      LAYER M5 ;
        RECT  65.616 172.716 65.64 172.8 ;
    END
  END i_b[127]
  PIN i_b[128]
    DIRECTION INPUT ;
    USE SIGNAL ;
    PORT
      LAYER M5 ;
        RECT  65.712 172.716 65.736 172.8 ;
    END
  END i_b[128]
  PIN i_b[129]
    DIRECTION INPUT ;
    USE SIGNAL ;
    PORT
      LAYER M5 ;
        RECT  65.808 172.716 65.832 172.8 ;
    END
  END i_b[129]
  PIN i_b[12]
    DIRECTION INPUT ;
    USE SIGNAL ;
    PORT
      LAYER M5 ;
        RECT  111.408 172.716 111.432 172.8 ;
    END
  END i_b[12]
  PIN i_b[130]
    DIRECTION INPUT ;
    USE SIGNAL ;
    PORT
      LAYER M5 ;
        RECT  65.904 172.716 65.928 172.8 ;
    END
  END i_b[130]
  PIN i_b[131]
    DIRECTION INPUT ;
    USE SIGNAL ;
    PORT
      LAYER M5 ;
        RECT  66 172.716 66.024 172.8 ;
    END
  END i_b[131]
  PIN i_b[132]
    DIRECTION INPUT ;
    USE SIGNAL ;
    PORT
      LAYER M5 ;
        RECT  66.096 172.716 66.12 172.8 ;
    END
  END i_b[132]
  PIN i_b[133]
    DIRECTION INPUT ;
    USE SIGNAL ;
    PORT
      LAYER M5 ;
        RECT  66.192 172.716 66.216 172.8 ;
    END
  END i_b[133]
  PIN i_b[134]
    DIRECTION INPUT ;
    USE SIGNAL ;
    PORT
      LAYER M5 ;
        RECT  66.288 172.716 66.312 172.8 ;
    END
  END i_b[134]
  PIN i_b[135]
    DIRECTION INPUT ;
    USE SIGNAL ;
    PORT
      LAYER M5 ;
        RECT  66.384 172.716 66.408 172.8 ;
    END
  END i_b[135]
  PIN i_b[136]
    DIRECTION INPUT ;
    USE SIGNAL ;
    PORT
      LAYER M5 ;
        RECT  66.48 172.716 66.504 172.8 ;
    END
  END i_b[136]
  PIN i_b[137]
    DIRECTION INPUT ;
    USE SIGNAL ;
    PORT
      LAYER M5 ;
        RECT  66.576 172.716 66.6 172.8 ;
    END
  END i_b[137]
  PIN i_b[138]
    DIRECTION INPUT ;
    USE SIGNAL ;
    PORT
      LAYER M5 ;
        RECT  66.672 172.716 66.696 172.8 ;
    END
  END i_b[138]
  PIN i_b[139]
    DIRECTION INPUT ;
    USE SIGNAL ;
    PORT
      LAYER M5 ;
        RECT  66.768 172.716 66.792 172.8 ;
    END
  END i_b[139]
  PIN i_b[13]
    DIRECTION INPUT ;
    USE SIGNAL ;
    PORT
      LAYER M5 ;
        RECT  111.504 172.716 111.528 172.8 ;
    END
  END i_b[13]
  PIN i_b[140]
    DIRECTION INPUT ;
    USE SIGNAL ;
    PORT
      LAYER M5 ;
        RECT  99.12 172.716 99.144 172.8 ;
    END
  END i_b[140]
  PIN i_b[141]
    DIRECTION INPUT ;
    USE SIGNAL ;
    PORT
      LAYER M5 ;
        RECT  99.216 172.716 99.24 172.8 ;
    END
  END i_b[141]
  PIN i_b[142]
    DIRECTION INPUT ;
    USE SIGNAL ;
    PORT
      LAYER M5 ;
        RECT  99.312 172.716 99.336 172.8 ;
    END
  END i_b[142]
  PIN i_b[143]
    DIRECTION INPUT ;
    USE SIGNAL ;
    PORT
      LAYER M5 ;
        RECT  99.408 172.716 99.432 172.8 ;
    END
  END i_b[143]
  PIN i_b[144]
    DIRECTION INPUT ;
    USE SIGNAL ;
    PORT
      LAYER M5 ;
        RECT  99.504 172.716 99.528 172.8 ;
    END
  END i_b[144]
  PIN i_b[145]
    DIRECTION INPUT ;
    USE SIGNAL ;
    PORT
      LAYER M5 ;
        RECT  99.6 172.716 99.624 172.8 ;
    END
  END i_b[145]
  PIN i_b[146]
    DIRECTION INPUT ;
    USE SIGNAL ;
    PORT
      LAYER M5 ;
        RECT  99.696 172.716 99.72 172.8 ;
    END
  END i_b[146]
  PIN i_b[147]
    DIRECTION INPUT ;
    USE SIGNAL ;
    PORT
      LAYER M5 ;
        RECT  99.792 172.716 99.816 172.8 ;
    END
  END i_b[147]
  PIN i_b[148]
    DIRECTION INPUT ;
    USE SIGNAL ;
    PORT
      LAYER M5 ;
        RECT  99.888 172.716 99.912 172.8 ;
    END
  END i_b[148]
  PIN i_b[149]
    DIRECTION INPUT ;
    USE SIGNAL ;
    PORT
      LAYER M5 ;
        RECT  99.984 172.716 100.008 172.8 ;
    END
  END i_b[149]
  PIN i_b[14]
    DIRECTION INPUT ;
    USE SIGNAL ;
    PORT
      LAYER M5 ;
        RECT  111.6 172.716 111.624 172.8 ;
    END
  END i_b[14]
  PIN i_b[150]
    DIRECTION INPUT ;
    USE SIGNAL ;
    PORT
      LAYER M5 ;
        RECT  100.08 172.716 100.104 172.8 ;
    END
  END i_b[150]
  PIN i_b[151]
    DIRECTION INPUT ;
    USE SIGNAL ;
    PORT
      LAYER M5 ;
        RECT  100.176 172.716 100.2 172.8 ;
    END
  END i_b[151]
  PIN i_b[152]
    DIRECTION INPUT ;
    USE SIGNAL ;
    PORT
      LAYER M5 ;
        RECT  100.272 172.716 100.296 172.8 ;
    END
  END i_b[152]
  PIN i_b[153]
    DIRECTION INPUT ;
    USE SIGNAL ;
    PORT
      LAYER M5 ;
        RECT  100.368 172.716 100.392 172.8 ;
    END
  END i_b[153]
  PIN i_b[154]
    DIRECTION INPUT ;
    USE SIGNAL ;
    PORT
      LAYER M5 ;
        RECT  100.464 172.716 100.488 172.8 ;
    END
  END i_b[154]
  PIN i_b[155]
    DIRECTION INPUT ;
    USE SIGNAL ;
    PORT
      LAYER M5 ;
        RECT  100.56 172.716 100.584 172.8 ;
    END
  END i_b[155]
  PIN i_b[156]
    DIRECTION INPUT ;
    USE SIGNAL ;
    PORT
      LAYER M5 ;
        RECT  100.656 172.716 100.68 172.8 ;
    END
  END i_b[156]
  PIN i_b[157]
    DIRECTION INPUT ;
    USE SIGNAL ;
    PORT
      LAYER M5 ;
        RECT  100.752 172.716 100.776 172.8 ;
    END
  END i_b[157]
  PIN i_b[158]
    DIRECTION INPUT ;
    USE SIGNAL ;
    PORT
      LAYER M5 ;
        RECT  100.848 172.716 100.872 172.8 ;
    END
  END i_b[158]
  PIN i_b[159]
    DIRECTION INPUT ;
    USE SIGNAL ;
    PORT
      LAYER M5 ;
        RECT  100.944 172.716 100.968 172.8 ;
    END
  END i_b[159]
  PIN i_b[15]
    DIRECTION INPUT ;
    USE SIGNAL ;
    PORT
      LAYER M5 ;
        RECT  111.696 172.716 111.72 172.8 ;
    END
  END i_b[15]
  PIN i_b[160]
    DIRECTION INPUT ;
    USE SIGNAL ;
    PORT
      LAYER M5 ;
        RECT  101.04 172.716 101.064 172.8 ;
    END
  END i_b[160]
  PIN i_b[161]
    DIRECTION INPUT ;
    USE SIGNAL ;
    PORT
      LAYER M5 ;
        RECT  101.136 172.716 101.16 172.8 ;
    END
  END i_b[161]
  PIN i_b[162]
    DIRECTION INPUT ;
    USE SIGNAL ;
    PORT
      LAYER M5 ;
        RECT  101.232 172.716 101.256 172.8 ;
    END
  END i_b[162]
  PIN i_b[163]
    DIRECTION INPUT ;
    USE SIGNAL ;
    PORT
      LAYER M5 ;
        RECT  101.328 172.716 101.352 172.8 ;
    END
  END i_b[163]
  PIN i_b[164]
    DIRECTION INPUT ;
    USE SIGNAL ;
    PORT
      LAYER M5 ;
        RECT  101.424 172.716 101.448 172.8 ;
    END
  END i_b[164]
  PIN i_b[165]
    DIRECTION INPUT ;
    USE SIGNAL ;
    PORT
      LAYER M5 ;
        RECT  101.52 172.716 101.544 172.8 ;
    END
  END i_b[165]
  PIN i_b[166]
    DIRECTION INPUT ;
    USE SIGNAL ;
    PORT
      LAYER M5 ;
        RECT  101.616 172.716 101.64 172.8 ;
    END
  END i_b[166]
  PIN i_b[167]
    DIRECTION INPUT ;
    USE SIGNAL ;
    PORT
      LAYER M5 ;
        RECT  101.712 172.716 101.736 172.8 ;
    END
  END i_b[167]
  PIN i_b[168]
    DIRECTION INPUT ;
    USE SIGNAL ;
    PORT
      LAYER M5 ;
        RECT  101.808 172.716 101.832 172.8 ;
    END
  END i_b[168]
  PIN i_b[169]
    DIRECTION INPUT ;
    USE SIGNAL ;
    PORT
      LAYER M5 ;
        RECT  101.904 172.716 101.928 172.8 ;
    END
  END i_b[169]
  PIN i_b[16]
    DIRECTION INPUT ;
    USE SIGNAL ;
    PORT
      LAYER M5 ;
        RECT  111.792 172.716 111.816 172.8 ;
    END
  END i_b[16]
  PIN i_b[170]
    DIRECTION INPUT ;
    USE SIGNAL ;
    PORT
      LAYER M5 ;
        RECT  102 172.716 102.024 172.8 ;
    END
  END i_b[170]
  PIN i_b[171]
    DIRECTION INPUT ;
    USE SIGNAL ;
    PORT
      LAYER M5 ;
        RECT  102.096 172.716 102.12 172.8 ;
    END
  END i_b[171]
  PIN i_b[172]
    DIRECTION INPUT ;
    USE SIGNAL ;
    PORT
      LAYER M5 ;
        RECT  69.936 172.716 69.96 172.8 ;
    END
  END i_b[172]
  PIN i_b[173]
    DIRECTION INPUT ;
    USE SIGNAL ;
    PORT
      LAYER M5 ;
        RECT  70.032 172.716 70.056 172.8 ;
    END
  END i_b[173]
  PIN i_b[174]
    DIRECTION INPUT ;
    USE SIGNAL ;
    PORT
      LAYER M5 ;
        RECT  70.128 172.716 70.152 172.8 ;
    END
  END i_b[174]
  PIN i_b[175]
    DIRECTION INPUT ;
    USE SIGNAL ;
    PORT
      LAYER M5 ;
        RECT  70.224 172.716 70.248 172.8 ;
    END
  END i_b[175]
  PIN i_b[176]
    DIRECTION INPUT ;
    USE SIGNAL ;
    PORT
      LAYER M5 ;
        RECT  70.32 172.716 70.344 172.8 ;
    END
  END i_b[176]
  PIN i_b[177]
    DIRECTION INPUT ;
    USE SIGNAL ;
    PORT
      LAYER M5 ;
        RECT  70.416 172.716 70.44 172.8 ;
    END
  END i_b[177]
  PIN i_b[178]
    DIRECTION INPUT ;
    USE SIGNAL ;
    PORT
      LAYER M5 ;
        RECT  70.512 172.716 70.536 172.8 ;
    END
  END i_b[178]
  PIN i_b[179]
    DIRECTION INPUT ;
    USE SIGNAL ;
    PORT
      LAYER M5 ;
        RECT  70.608 172.716 70.632 172.8 ;
    END
  END i_b[179]
  PIN i_b[17]
    DIRECTION INPUT ;
    USE SIGNAL ;
    PORT
      LAYER M5 ;
        RECT  111.888 172.716 111.912 172.8 ;
    END
  END i_b[17]
  PIN i_b[180]
    DIRECTION INPUT ;
    USE SIGNAL ;
    PORT
      LAYER M5 ;
        RECT  70.704 172.716 70.728 172.8 ;
    END
  END i_b[180]
  PIN i_b[181]
    DIRECTION INPUT ;
    USE SIGNAL ;
    PORT
      LAYER M5 ;
        RECT  70.8 172.716 70.824 172.8 ;
    END
  END i_b[181]
  PIN i_b[182]
    DIRECTION INPUT ;
    USE SIGNAL ;
    PORT
      LAYER M5 ;
        RECT  70.896 172.716 70.92 172.8 ;
    END
  END i_b[182]
  PIN i_b[183]
    DIRECTION INPUT ;
    USE SIGNAL ;
    PORT
      LAYER M5 ;
        RECT  70.992 172.716 71.016 172.8 ;
    END
  END i_b[183]
  PIN i_b[184]
    DIRECTION INPUT ;
    USE SIGNAL ;
    PORT
      LAYER M5 ;
        RECT  71.088 172.716 71.112 172.8 ;
    END
  END i_b[184]
  PIN i_b[185]
    DIRECTION INPUT ;
    USE SIGNAL ;
    PORT
      LAYER M5 ;
        RECT  71.184 172.716 71.208 172.8 ;
    END
  END i_b[185]
  PIN i_b[186]
    DIRECTION INPUT ;
    USE SIGNAL ;
    PORT
      LAYER M5 ;
        RECT  71.28 172.716 71.304 172.8 ;
    END
  END i_b[186]
  PIN i_b[187]
    DIRECTION INPUT ;
    USE SIGNAL ;
    PORT
      LAYER M5 ;
        RECT  71.376 172.716 71.4 172.8 ;
    END
  END i_b[187]
  PIN i_b[188]
    DIRECTION INPUT ;
    USE SIGNAL ;
    PORT
      LAYER M5 ;
        RECT  71.472 172.716 71.496 172.8 ;
    END
  END i_b[188]
  PIN i_b[189]
    DIRECTION INPUT ;
    USE SIGNAL ;
    PORT
      LAYER M5 ;
        RECT  71.568 172.716 71.592 172.8 ;
    END
  END i_b[189]
  PIN i_b[18]
    DIRECTION INPUT ;
    USE SIGNAL ;
    PORT
      LAYER M5 ;
        RECT  111.984 172.716 112.008 172.8 ;
    END
  END i_b[18]
  PIN i_b[190]
    DIRECTION INPUT ;
    USE SIGNAL ;
    PORT
      LAYER M5 ;
        RECT  71.664 172.716 71.688 172.8 ;
    END
  END i_b[190]
  PIN i_b[191]
    DIRECTION INPUT ;
    USE SIGNAL ;
    PORT
      LAYER M5 ;
        RECT  71.76 172.716 71.784 172.8 ;
    END
  END i_b[191]
  PIN i_b[192]
    DIRECTION INPUT ;
    USE SIGNAL ;
    PORT
      LAYER M5 ;
        RECT  71.856 172.716 71.88 172.8 ;
    END
  END i_b[192]
  PIN i_b[193]
    DIRECTION INPUT ;
    USE SIGNAL ;
    PORT
      LAYER M5 ;
        RECT  71.952 172.716 71.976 172.8 ;
    END
  END i_b[193]
  PIN i_b[194]
    DIRECTION INPUT ;
    USE SIGNAL ;
    PORT
      LAYER M5 ;
        RECT  72.048 172.716 72.072 172.8 ;
    END
  END i_b[194]
  PIN i_b[195]
    DIRECTION INPUT ;
    USE SIGNAL ;
    PORT
      LAYER M5 ;
        RECT  72.144 172.716 72.168 172.8 ;
    END
  END i_b[195]
  PIN i_b[196]
    DIRECTION INPUT ;
    USE SIGNAL ;
    PORT
      LAYER M5 ;
        RECT  72.24 172.716 72.264 172.8 ;
    END
  END i_b[196]
  PIN i_b[197]
    DIRECTION INPUT ;
    USE SIGNAL ;
    PORT
      LAYER M5 ;
        RECT  72.336 172.716 72.36 172.8 ;
    END
  END i_b[197]
  PIN i_b[198]
    DIRECTION INPUT ;
    USE SIGNAL ;
    PORT
      LAYER M5 ;
        RECT  72.432 172.716 72.456 172.8 ;
    END
  END i_b[198]
  PIN i_b[199]
    DIRECTION INPUT ;
    USE SIGNAL ;
    PORT
      LAYER M5 ;
        RECT  72.528 172.716 72.552 172.8 ;
    END
  END i_b[199]
  PIN i_b[19]
    DIRECTION INPUT ;
    USE SIGNAL ;
    PORT
      LAYER M5 ;
        RECT  112.08 172.716 112.104 172.8 ;
    END
  END i_b[19]
  PIN i_b[1]
    DIRECTION INPUT ;
    USE SIGNAL ;
    PORT
      LAYER M5 ;
        RECT  62.736 172.716 62.76 172.8 ;
    END
  END i_b[1]
  PIN i_b[200]
    DIRECTION INPUT ;
    USE SIGNAL ;
    PORT
      LAYER M5 ;
        RECT  72.624 172.716 72.648 172.8 ;
    END
  END i_b[200]
  PIN i_b[201]
    DIRECTION INPUT ;
    USE SIGNAL ;
    PORT
      LAYER M5 ;
        RECT  72.72 172.716 72.744 172.8 ;
    END
  END i_b[201]
  PIN i_b[202]
    DIRECTION INPUT ;
    USE SIGNAL ;
    PORT
      LAYER M5 ;
        RECT  72.816 172.716 72.84 172.8 ;
    END
  END i_b[202]
  PIN i_b[203]
    DIRECTION INPUT ;
    USE SIGNAL ;
    PORT
      LAYER M5 ;
        RECT  72.912 172.716 72.936 172.8 ;
    END
  END i_b[203]
  PIN i_b[204]
    DIRECTION INPUT ;
    USE SIGNAL ;
    PORT
      LAYER M5 ;
        RECT  73.008 172.716 73.032 172.8 ;
    END
  END i_b[204]
  PIN i_b[205]
    DIRECTION INPUT ;
    USE SIGNAL ;
    PORT
      LAYER M5 ;
        RECT  73.104 172.716 73.128 172.8 ;
    END
  END i_b[205]
  PIN i_b[206]
    DIRECTION INPUT ;
    USE SIGNAL ;
    PORT
      LAYER M5 ;
        RECT  73.2 172.716 73.224 172.8 ;
    END
  END i_b[206]
  PIN i_b[207]
    DIRECTION INPUT ;
    USE SIGNAL ;
    PORT
      LAYER M5 ;
        RECT  73.296 172.716 73.32 172.8 ;
    END
  END i_b[207]
  PIN i_b[208]
    DIRECTION INPUT ;
    USE SIGNAL ;
    PORT
      LAYER M5 ;
        RECT  73.392 172.716 73.416 172.8 ;
    END
  END i_b[208]
  PIN i_b[209]
    DIRECTION INPUT ;
    USE SIGNAL ;
    PORT
      LAYER M5 ;
        RECT  73.488 172.716 73.512 172.8 ;
    END
  END i_b[209]
  PIN i_b[20]
    DIRECTION INPUT ;
    USE SIGNAL ;
    PORT
      LAYER M5 ;
        RECT  112.176 172.716 112.2 172.8 ;
    END
  END i_b[20]
  PIN i_b[210]
    DIRECTION INPUT ;
    USE SIGNAL ;
    PORT
      LAYER M5 ;
        RECT  73.584 172.716 73.608 172.8 ;
    END
  END i_b[210]
  PIN i_b[211]
    DIRECTION INPUT ;
    USE SIGNAL ;
    PORT
      LAYER M5 ;
        RECT  73.68 172.716 73.704 172.8 ;
    END
  END i_b[211]
  PIN i_b[212]
    DIRECTION INPUT ;
    USE SIGNAL ;
    PORT
      LAYER M5 ;
        RECT  73.776 172.716 73.8 172.8 ;
    END
  END i_b[212]
  PIN i_b[213]
    DIRECTION INPUT ;
    USE SIGNAL ;
    PORT
      LAYER M5 ;
        RECT  73.872 172.716 73.896 172.8 ;
    END
  END i_b[213]
  PIN i_b[214]
    DIRECTION INPUT ;
    USE SIGNAL ;
    PORT
      LAYER M5 ;
        RECT  73.968 172.716 73.992 172.8 ;
    END
  END i_b[214]
  PIN i_b[215]
    DIRECTION INPUT ;
    USE SIGNAL ;
    PORT
      LAYER M5 ;
        RECT  74.064 172.716 74.088 172.8 ;
    END
  END i_b[215]
  PIN i_b[216]
    DIRECTION INPUT ;
    USE SIGNAL ;
    PORT
      LAYER M5 ;
        RECT  74.16 172.716 74.184 172.8 ;
    END
  END i_b[216]
  PIN i_b[217]
    DIRECTION INPUT ;
    USE SIGNAL ;
    PORT
      LAYER M5 ;
        RECT  74.256 172.716 74.28 172.8 ;
    END
  END i_b[217]
  PIN i_b[218]
    DIRECTION INPUT ;
    USE SIGNAL ;
    PORT
      LAYER M5 ;
        RECT  74.352 172.716 74.376 172.8 ;
    END
  END i_b[218]
  PIN i_b[219]
    DIRECTION INPUT ;
    USE SIGNAL ;
    PORT
      LAYER M5 ;
        RECT  74.448 172.716 74.472 172.8 ;
    END
  END i_b[219]
  PIN i_b[21]
    DIRECTION INPUT ;
    USE SIGNAL ;
    PORT
      LAYER M5 ;
        RECT  112.272 172.716 112.296 172.8 ;
    END
  END i_b[21]
  PIN i_b[220]
    DIRECTION INPUT ;
    USE SIGNAL ;
    PORT
      LAYER M5 ;
        RECT  74.544 172.716 74.568 172.8 ;
    END
  END i_b[220]
  PIN i_b[221]
    DIRECTION INPUT ;
    USE SIGNAL ;
    PORT
      LAYER M5 ;
        RECT  74.64 172.716 74.664 172.8 ;
    END
  END i_b[221]
  PIN i_b[222]
    DIRECTION INPUT ;
    USE SIGNAL ;
    PORT
      LAYER M5 ;
        RECT  74.736 172.716 74.76 172.8 ;
    END
  END i_b[222]
  PIN i_b[223]
    DIRECTION INPUT ;
    USE SIGNAL ;
    PORT
      LAYER M5 ;
        RECT  74.832 172.716 74.856 172.8 ;
    END
  END i_b[223]
  PIN i_b[224]
    DIRECTION INPUT ;
    USE SIGNAL ;
    PORT
      LAYER M5 ;
        RECT  74.928 172.716 74.952 172.8 ;
    END
  END i_b[224]
  PIN i_b[225]
    DIRECTION INPUT ;
    USE SIGNAL ;
    PORT
      LAYER M5 ;
        RECT  75.024 172.716 75.048 172.8 ;
    END
  END i_b[225]
  PIN i_b[226]
    DIRECTION INPUT ;
    USE SIGNAL ;
    PORT
      LAYER M5 ;
        RECT  75.12 172.716 75.144 172.8 ;
    END
  END i_b[226]
  PIN i_b[227]
    DIRECTION INPUT ;
    USE SIGNAL ;
    PORT
      LAYER M5 ;
        RECT  75.216 172.716 75.24 172.8 ;
    END
  END i_b[227]
  PIN i_b[228]
    DIRECTION INPUT ;
    USE SIGNAL ;
    PORT
      LAYER M5 ;
        RECT  75.312 172.716 75.336 172.8 ;
    END
  END i_b[228]
  PIN i_b[229]
    DIRECTION INPUT ;
    USE SIGNAL ;
    PORT
      LAYER M5 ;
        RECT  75.408 172.716 75.432 172.8 ;
    END
  END i_b[229]
  PIN i_b[22]
    DIRECTION INPUT ;
    USE SIGNAL ;
    PORT
      LAYER M5 ;
        RECT  112.368 172.716 112.392 172.8 ;
    END
  END i_b[22]
  PIN i_b[230]
    DIRECTION INPUT ;
    USE SIGNAL ;
    PORT
      LAYER M5 ;
        RECT  75.504 172.716 75.528 172.8 ;
    END
  END i_b[230]
  PIN i_b[231]
    DIRECTION INPUT ;
    USE SIGNAL ;
    PORT
      LAYER M5 ;
        RECT  75.6 172.716 75.624 172.8 ;
    END
  END i_b[231]
  PIN i_b[232]
    DIRECTION INPUT ;
    USE SIGNAL ;
    PORT
      LAYER M5 ;
        RECT  75.696 172.716 75.72 172.8 ;
    END
  END i_b[232]
  PIN i_b[233]
    DIRECTION INPUT ;
    USE SIGNAL ;
    PORT
      LAYER M5 ;
        RECT  75.792 172.716 75.816 172.8 ;
    END
  END i_b[233]
  PIN i_b[234]
    DIRECTION INPUT ;
    USE SIGNAL ;
    PORT
      LAYER M5 ;
        RECT  75.888 172.716 75.912 172.8 ;
    END
  END i_b[234]
  PIN i_b[235]
    DIRECTION INPUT ;
    USE SIGNAL ;
    PORT
      LAYER M5 ;
        RECT  75.984 172.716 76.008 172.8 ;
    END
  END i_b[235]
  PIN i_b[236]
    DIRECTION INPUT ;
    USE SIGNAL ;
    PORT
      LAYER M5 ;
        RECT  66.864 172.716 66.888 172.8 ;
    END
  END i_b[236]
  PIN i_b[237]
    DIRECTION INPUT ;
    USE SIGNAL ;
    PORT
      LAYER M5 ;
        RECT  66.96 172.716 66.984 172.8 ;
    END
  END i_b[237]
  PIN i_b[238]
    DIRECTION INPUT ;
    USE SIGNAL ;
    PORT
      LAYER M5 ;
        RECT  67.056 172.716 67.08 172.8 ;
    END
  END i_b[238]
  PIN i_b[239]
    DIRECTION INPUT ;
    USE SIGNAL ;
    PORT
      LAYER M5 ;
        RECT  67.152 172.716 67.176 172.8 ;
    END
  END i_b[239]
  PIN i_b[23]
    DIRECTION INPUT ;
    USE SIGNAL ;
    PORT
      LAYER M5 ;
        RECT  112.464 172.716 112.488 172.8 ;
    END
  END i_b[23]
  PIN i_b[240]
    DIRECTION INPUT ;
    USE SIGNAL ;
    PORT
      LAYER M5 ;
        RECT  67.248 172.716 67.272 172.8 ;
    END
  END i_b[240]
  PIN i_b[241]
    DIRECTION INPUT ;
    USE SIGNAL ;
    PORT
      LAYER M5 ;
        RECT  67.344 172.716 67.368 172.8 ;
    END
  END i_b[241]
  PIN i_b[242]
    DIRECTION INPUT ;
    USE SIGNAL ;
    PORT
      LAYER M5 ;
        RECT  67.44 172.716 67.464 172.8 ;
    END
  END i_b[242]
  PIN i_b[243]
    DIRECTION INPUT ;
    USE SIGNAL ;
    PORT
      LAYER M5 ;
        RECT  67.536 172.716 67.56 172.8 ;
    END
  END i_b[243]
  PIN i_b[244]
    DIRECTION INPUT ;
    USE SIGNAL ;
    PORT
      LAYER M5 ;
        RECT  67.632 172.716 67.656 172.8 ;
    END
  END i_b[244]
  PIN i_b[245]
    DIRECTION INPUT ;
    USE SIGNAL ;
    PORT
      LAYER M5 ;
        RECT  67.728 172.716 67.752 172.8 ;
    END
  END i_b[245]
  PIN i_b[246]
    DIRECTION INPUT ;
    USE SIGNAL ;
    PORT
      LAYER M5 ;
        RECT  67.824 172.716 67.848 172.8 ;
    END
  END i_b[246]
  PIN i_b[247]
    DIRECTION INPUT ;
    USE SIGNAL ;
    PORT
      LAYER M5 ;
        RECT  67.92 172.716 67.944 172.8 ;
    END
  END i_b[247]
  PIN i_b[248]
    DIRECTION INPUT ;
    USE SIGNAL ;
    PORT
      LAYER M5 ;
        RECT  68.016 172.716 68.04 172.8 ;
    END
  END i_b[248]
  PIN i_b[249]
    DIRECTION INPUT ;
    USE SIGNAL ;
    PORT
      LAYER M5 ;
        RECT  68.112 172.716 68.136 172.8 ;
    END
  END i_b[249]
  PIN i_b[24]
    DIRECTION INPUT ;
    USE SIGNAL ;
    PORT
      LAYER M5 ;
        RECT  112.56 172.716 112.584 172.8 ;
    END
  END i_b[24]
  PIN i_b[250]
    DIRECTION INPUT ;
    USE SIGNAL ;
    PORT
      LAYER M5 ;
        RECT  68.208 172.716 68.232 172.8 ;
    END
  END i_b[250]
  PIN i_b[251]
    DIRECTION INPUT ;
    USE SIGNAL ;
    PORT
      LAYER M5 ;
        RECT  68.304 172.716 68.328 172.8 ;
    END
  END i_b[251]
  PIN i_b[252]
    DIRECTION INPUT ;
    USE SIGNAL ;
    PORT
      LAYER M5 ;
        RECT  68.4 172.716 68.424 172.8 ;
    END
  END i_b[252]
  PIN i_b[253]
    DIRECTION INPUT ;
    USE SIGNAL ;
    PORT
      LAYER M5 ;
        RECT  68.496 172.716 68.52 172.8 ;
    END
  END i_b[253]
  PIN i_b[254]
    DIRECTION INPUT ;
    USE SIGNAL ;
    PORT
      LAYER M5 ;
        RECT  68.592 172.716 68.616 172.8 ;
    END
  END i_b[254]
  PIN i_b[255]
    DIRECTION INPUT ;
    USE SIGNAL ;
    PORT
      LAYER M5 ;
        RECT  68.688 172.716 68.712 172.8 ;
    END
  END i_b[255]
  PIN i_b[256]
    DIRECTION INPUT ;
    USE SIGNAL ;
    PORT
      LAYER M5 ;
        RECT  68.784 172.716 68.808 172.8 ;
    END
  END i_b[256]
  PIN i_b[257]
    DIRECTION INPUT ;
    USE SIGNAL ;
    PORT
      LAYER M5 ;
        RECT  68.88 172.716 68.904 172.8 ;
    END
  END i_b[257]
  PIN i_b[258]
    DIRECTION INPUT ;
    USE SIGNAL ;
    PORT
      LAYER M5 ;
        RECT  68.976 172.716 69 172.8 ;
    END
  END i_b[258]
  PIN i_b[259]
    DIRECTION INPUT ;
    USE SIGNAL ;
    PORT
      LAYER M5 ;
        RECT  69.072 172.716 69.096 172.8 ;
    END
  END i_b[259]
  PIN i_b[25]
    DIRECTION INPUT ;
    USE SIGNAL ;
    PORT
      LAYER M5 ;
        RECT  112.656 172.716 112.68 172.8 ;
    END
  END i_b[25]
  PIN i_b[260]
    DIRECTION INPUT ;
    USE SIGNAL ;
    PORT
      LAYER M5 ;
        RECT  69.168 172.716 69.192 172.8 ;
    END
  END i_b[260]
  PIN i_b[261]
    DIRECTION INPUT ;
    USE SIGNAL ;
    PORT
      LAYER M5 ;
        RECT  69.264 172.716 69.288 172.8 ;
    END
  END i_b[261]
  PIN i_b[262]
    DIRECTION INPUT ;
    USE SIGNAL ;
    PORT
      LAYER M5 ;
        RECT  69.36 172.716 69.384 172.8 ;
    END
  END i_b[262]
  PIN i_b[263]
    DIRECTION INPUT ;
    USE SIGNAL ;
    PORT
      LAYER M5 ;
        RECT  69.456 172.716 69.48 172.8 ;
    END
  END i_b[263]
  PIN i_b[264]
    DIRECTION INPUT ;
    USE SIGNAL ;
    PORT
      LAYER M5 ;
        RECT  69.552 172.716 69.576 172.8 ;
    END
  END i_b[264]
  PIN i_b[265]
    DIRECTION INPUT ;
    USE SIGNAL ;
    PORT
      LAYER M5 ;
        RECT  69.648 172.716 69.672 172.8 ;
    END
  END i_b[265]
  PIN i_b[266]
    DIRECTION INPUT ;
    USE SIGNAL ;
    PORT
      LAYER M5 ;
        RECT  69.744 172.716 69.768 172.8 ;
    END
  END i_b[266]
  PIN i_b[267]
    DIRECTION INPUT ;
    USE SIGNAL ;
    PORT
      LAYER M5 ;
        RECT  69.84 172.716 69.864 172.8 ;
    END
  END i_b[267]
  PIN i_b[268]
    DIRECTION INPUT ;
    USE SIGNAL ;
    PORT
      LAYER M5 ;
        RECT  59.952 172.716 59.976 172.8 ;
    END
  END i_b[268]
  PIN i_b[269]
    DIRECTION INPUT ;
    USE SIGNAL ;
    PORT
      LAYER M5 ;
        RECT  60.048 172.716 60.072 172.8 ;
    END
  END i_b[269]
  PIN i_b[26]
    DIRECTION INPUT ;
    USE SIGNAL ;
    PORT
      LAYER M5 ;
        RECT  112.752 172.716 112.776 172.8 ;
    END
  END i_b[26]
  PIN i_b[270]
    DIRECTION INPUT ;
    USE SIGNAL ;
    PORT
      LAYER M5 ;
        RECT  60.144 172.716 60.168 172.8 ;
    END
  END i_b[270]
  PIN i_b[271]
    DIRECTION INPUT ;
    USE SIGNAL ;
    PORT
      LAYER M5 ;
        RECT  60.24 172.716 60.264 172.8 ;
    END
  END i_b[271]
  PIN i_b[272]
    DIRECTION INPUT ;
    USE SIGNAL ;
    PORT
      LAYER M5 ;
        RECT  60.336 172.716 60.36 172.8 ;
    END
  END i_b[272]
  PIN i_b[273]
    DIRECTION INPUT ;
    USE SIGNAL ;
    PORT
      LAYER M5 ;
        RECT  60.432 172.716 60.456 172.8 ;
    END
  END i_b[273]
  PIN i_b[274]
    DIRECTION INPUT ;
    USE SIGNAL ;
    PORT
      LAYER M5 ;
        RECT  60.528 172.716 60.552 172.8 ;
    END
  END i_b[274]
  PIN i_b[275]
    DIRECTION INPUT ;
    USE SIGNAL ;
    PORT
      LAYER M5 ;
        RECT  60.624 172.716 60.648 172.8 ;
    END
  END i_b[275]
  PIN i_b[27]
    DIRECTION INPUT ;
    USE SIGNAL ;
    PORT
      LAYER M5 ;
        RECT  112.848 172.716 112.872 172.8 ;
    END
  END i_b[27]
  PIN i_b[28]
    DIRECTION INPUT ;
    USE SIGNAL ;
    PORT
      LAYER M5 ;
        RECT  112.944 172.716 112.968 172.8 ;
    END
  END i_b[28]
  PIN i_b[29]
    DIRECTION INPUT ;
    USE SIGNAL ;
    PORT
      LAYER M5 ;
        RECT  113.04 172.716 113.064 172.8 ;
    END
  END i_b[29]
  PIN i_b[2]
    DIRECTION INPUT ;
    USE SIGNAL ;
    PORT
      LAYER M5 ;
        RECT  62.832 172.716 62.856 172.8 ;
    END
  END i_b[2]
  PIN i_b[30]
    DIRECTION INPUT ;
    USE SIGNAL ;
    PORT
      LAYER M5 ;
        RECT  113.136 172.716 113.16 172.8 ;
    END
  END i_b[30]
  PIN i_b[31]
    DIRECTION INPUT ;
    USE SIGNAL ;
    PORT
      LAYER M5 ;
        RECT  113.232 172.716 113.256 172.8 ;
    END
  END i_b[31]
  PIN i_b[32]
    DIRECTION INPUT ;
    USE SIGNAL ;
    PORT
      LAYER M5 ;
        RECT  113.328 172.716 113.352 172.8 ;
    END
  END i_b[32]
  PIN i_b[33]
    DIRECTION INPUT ;
    USE SIGNAL ;
    PORT
      LAYER M5 ;
        RECT  113.424 172.716 113.448 172.8 ;
    END
  END i_b[33]
  PIN i_b[34]
    DIRECTION INPUT ;
    USE SIGNAL ;
    PORT
      LAYER M5 ;
        RECT  113.52 172.716 113.544 172.8 ;
    END
  END i_b[34]
  PIN i_b[35]
    DIRECTION INPUT ;
    USE SIGNAL ;
    PORT
      LAYER M5 ;
        RECT  113.616 172.716 113.64 172.8 ;
    END
  END i_b[35]
  PIN i_b[36]
    DIRECTION INPUT ;
    USE SIGNAL ;
    PORT
      LAYER M5 ;
        RECT  113.712 172.716 113.736 172.8 ;
    END
  END i_b[36]
  PIN i_b[37]
    DIRECTION INPUT ;
    USE SIGNAL ;
    PORT
      LAYER M5 ;
        RECT  113.808 172.716 113.832 172.8 ;
    END
  END i_b[37]
  PIN i_b[38]
    DIRECTION INPUT ;
    USE SIGNAL ;
    PORT
      LAYER M5 ;
        RECT  113.904 172.716 113.928 172.8 ;
    END
  END i_b[38]
  PIN i_b[39]
    DIRECTION INPUT ;
    USE SIGNAL ;
    PORT
      LAYER M5 ;
        RECT  114 172.716 114.024 172.8 ;
    END
  END i_b[39]
  PIN i_b[3]
    DIRECTION INPUT ;
    USE SIGNAL ;
    PORT
      LAYER M5 ;
        RECT  62.928 172.716 62.952 172.8 ;
    END
  END i_b[3]
  PIN i_b[40]
    DIRECTION INPUT ;
    USE SIGNAL ;
    PORT
      LAYER M5 ;
        RECT  114.096 172.716 114.12 172.8 ;
    END
  END i_b[40]
  PIN i_b[41]
    DIRECTION INPUT ;
    USE SIGNAL ;
    PORT
      LAYER M5 ;
        RECT  114.192 172.716 114.216 172.8 ;
    END
  END i_b[41]
  PIN i_b[42]
    DIRECTION INPUT ;
    USE SIGNAL ;
    PORT
      LAYER M5 ;
        RECT  114.288 172.716 114.312 172.8 ;
    END
  END i_b[42]
  PIN i_b[43]
    DIRECTION INPUT ;
    USE SIGNAL ;
    PORT
      LAYER M5 ;
        RECT  114.384 172.716 114.408 172.8 ;
    END
  END i_b[43]
  PIN i_b[44]
    DIRECTION INPUT ;
    USE SIGNAL ;
    PORT
      LAYER M5 ;
        RECT  102.192 172.716 102.216 172.8 ;
    END
  END i_b[44]
  PIN i_b[45]
    DIRECTION INPUT ;
    USE SIGNAL ;
    PORT
      LAYER M5 ;
        RECT  102.288 172.716 102.312 172.8 ;
    END
  END i_b[45]
  PIN i_b[46]
    DIRECTION INPUT ;
    USE SIGNAL ;
    PORT
      LAYER M5 ;
        RECT  102.384 172.716 102.408 172.8 ;
    END
  END i_b[46]
  PIN i_b[47]
    DIRECTION INPUT ;
    USE SIGNAL ;
    PORT
      LAYER M5 ;
        RECT  102.48 172.716 102.504 172.8 ;
    END
  END i_b[47]
  PIN i_b[48]
    DIRECTION INPUT ;
    USE SIGNAL ;
    PORT
      LAYER M5 ;
        RECT  102.576 172.716 102.6 172.8 ;
    END
  END i_b[48]
  PIN i_b[49]
    DIRECTION INPUT ;
    USE SIGNAL ;
    PORT
      LAYER M5 ;
        RECT  102.672 172.716 102.696 172.8 ;
    END
  END i_b[49]
  PIN i_b[4]
    DIRECTION INPUT ;
    USE SIGNAL ;
    PORT
      LAYER M5 ;
        RECT  63.024 172.716 63.048 172.8 ;
    END
  END i_b[4]
  PIN i_b[50]
    DIRECTION INPUT ;
    USE SIGNAL ;
    PORT
      LAYER M5 ;
        RECT  102.768 172.716 102.792 172.8 ;
    END
  END i_b[50]
  PIN i_b[51]
    DIRECTION INPUT ;
    USE SIGNAL ;
    PORT
      LAYER M5 ;
        RECT  102.864 172.716 102.888 172.8 ;
    END
  END i_b[51]
  PIN i_b[52]
    DIRECTION INPUT ;
    USE SIGNAL ;
    PORT
      LAYER M5 ;
        RECT  102.96 172.716 102.984 172.8 ;
    END
  END i_b[52]
  PIN i_b[53]
    DIRECTION INPUT ;
    USE SIGNAL ;
    PORT
      LAYER M5 ;
        RECT  103.056 172.716 103.08 172.8 ;
    END
  END i_b[53]
  PIN i_b[54]
    DIRECTION INPUT ;
    USE SIGNAL ;
    PORT
      LAYER M5 ;
        RECT  103.152 172.716 103.176 172.8 ;
    END
  END i_b[54]
  PIN i_b[55]
    DIRECTION INPUT ;
    USE SIGNAL ;
    PORT
      LAYER M5 ;
        RECT  103.248 172.716 103.272 172.8 ;
    END
  END i_b[55]
  PIN i_b[56]
    DIRECTION INPUT ;
    USE SIGNAL ;
    PORT
      LAYER M5 ;
        RECT  103.344 172.716 103.368 172.8 ;
    END
  END i_b[56]
  PIN i_b[57]
    DIRECTION INPUT ;
    USE SIGNAL ;
    PORT
      LAYER M5 ;
        RECT  103.44 172.716 103.464 172.8 ;
    END
  END i_b[57]
  PIN i_b[58]
    DIRECTION INPUT ;
    USE SIGNAL ;
    PORT
      LAYER M5 ;
        RECT  103.536 172.716 103.56 172.8 ;
    END
  END i_b[58]
  PIN i_b[59]
    DIRECTION INPUT ;
    USE SIGNAL ;
    PORT
      LAYER M5 ;
        RECT  103.632 172.716 103.656 172.8 ;
    END
  END i_b[59]
  PIN i_b[5]
    DIRECTION INPUT ;
    USE SIGNAL ;
    PORT
      LAYER M5 ;
        RECT  63.12 172.716 63.144 172.8 ;
    END
  END i_b[5]
  PIN i_b[60]
    DIRECTION INPUT ;
    USE SIGNAL ;
    PORT
      LAYER M5 ;
        RECT  103.728 172.716 103.752 172.8 ;
    END
  END i_b[60]
  PIN i_b[61]
    DIRECTION INPUT ;
    USE SIGNAL ;
    PORT
      LAYER M5 ;
        RECT  103.824 172.716 103.848 172.8 ;
    END
  END i_b[61]
  PIN i_b[62]
    DIRECTION INPUT ;
    USE SIGNAL ;
    PORT
      LAYER M5 ;
        RECT  103.92 172.716 103.944 172.8 ;
    END
  END i_b[62]
  PIN i_b[63]
    DIRECTION INPUT ;
    USE SIGNAL ;
    PORT
      LAYER M5 ;
        RECT  104.016 172.716 104.04 172.8 ;
    END
  END i_b[63]
  PIN i_b[64]
    DIRECTION INPUT ;
    USE SIGNAL ;
    PORT
      LAYER M5 ;
        RECT  104.112 172.716 104.136 172.8 ;
    END
  END i_b[64]
  PIN i_b[65]
    DIRECTION INPUT ;
    USE SIGNAL ;
    PORT
      LAYER M5 ;
        RECT  104.208 172.716 104.232 172.8 ;
    END
  END i_b[65]
  PIN i_b[66]
    DIRECTION INPUT ;
    USE SIGNAL ;
    PORT
      LAYER M5 ;
        RECT  104.304 172.716 104.328 172.8 ;
    END
  END i_b[66]
  PIN i_b[67]
    DIRECTION INPUT ;
    USE SIGNAL ;
    PORT
      LAYER M5 ;
        RECT  104.4 172.716 104.424 172.8 ;
    END
  END i_b[67]
  PIN i_b[68]
    DIRECTION INPUT ;
    USE SIGNAL ;
    PORT
      LAYER M5 ;
        RECT  104.496 172.716 104.52 172.8 ;
    END
  END i_b[68]
  PIN i_b[69]
    DIRECTION INPUT ;
    USE SIGNAL ;
    PORT
      LAYER M5 ;
        RECT  104.592 172.716 104.616 172.8 ;
    END
  END i_b[69]
  PIN i_b[6]
    DIRECTION INPUT ;
    USE SIGNAL ;
    PORT
      LAYER M5 ;
        RECT  63.216 172.716 63.24 172.8 ;
    END
  END i_b[6]
  PIN i_b[70]
    DIRECTION INPUT ;
    USE SIGNAL ;
    PORT
      LAYER M5 ;
        RECT  104.688 172.716 104.712 172.8 ;
    END
  END i_b[70]
  PIN i_b[71]
    DIRECTION INPUT ;
    USE SIGNAL ;
    PORT
      LAYER M5 ;
        RECT  104.784 172.716 104.808 172.8 ;
    END
  END i_b[71]
  PIN i_b[72]
    DIRECTION INPUT ;
    USE SIGNAL ;
    PORT
      LAYER M5 ;
        RECT  104.88 172.716 104.904 172.8 ;
    END
  END i_b[72]
  PIN i_b[73]
    DIRECTION INPUT ;
    USE SIGNAL ;
    PORT
      LAYER M5 ;
        RECT  104.976 172.716 105 172.8 ;
    END
  END i_b[73]
  PIN i_b[74]
    DIRECTION INPUT ;
    USE SIGNAL ;
    PORT
      LAYER M5 ;
        RECT  105.072 172.716 105.096 172.8 ;
    END
  END i_b[74]
  PIN i_b[75]
    DIRECTION INPUT ;
    USE SIGNAL ;
    PORT
      LAYER M5 ;
        RECT  105.168 172.716 105.192 172.8 ;
    END
  END i_b[75]
  PIN i_b[76]
    DIRECTION INPUT ;
    USE SIGNAL ;
    PORT
      LAYER M5 ;
        RECT  96.048 172.716 96.072 172.8 ;
    END
  END i_b[76]
  PIN i_b[77]
    DIRECTION INPUT ;
    USE SIGNAL ;
    PORT
      LAYER M5 ;
        RECT  96.144 172.716 96.168 172.8 ;
    END
  END i_b[77]
  PIN i_b[78]
    DIRECTION INPUT ;
    USE SIGNAL ;
    PORT
      LAYER M5 ;
        RECT  96.24 172.716 96.264 172.8 ;
    END
  END i_b[78]
  PIN i_b[79]
    DIRECTION INPUT ;
    USE SIGNAL ;
    PORT
      LAYER M5 ;
        RECT  96.336 172.716 96.36 172.8 ;
    END
  END i_b[79]
  PIN i_b[7]
    DIRECTION INPUT ;
    USE SIGNAL ;
    PORT
      LAYER M5 ;
        RECT  63.312 172.716 63.336 172.8 ;
    END
  END i_b[7]
  PIN i_b[80]
    DIRECTION INPUT ;
    USE SIGNAL ;
    PORT
      LAYER M5 ;
        RECT  96.432 172.716 96.456 172.8 ;
    END
  END i_b[80]
  PIN i_b[81]
    DIRECTION INPUT ;
    USE SIGNAL ;
    PORT
      LAYER M5 ;
        RECT  96.528 172.716 96.552 172.8 ;
    END
  END i_b[81]
  PIN i_b[82]
    DIRECTION INPUT ;
    USE SIGNAL ;
    PORT
      LAYER M5 ;
        RECT  96.624 172.716 96.648 172.8 ;
    END
  END i_b[82]
  PIN i_b[83]
    DIRECTION INPUT ;
    USE SIGNAL ;
    PORT
      LAYER M5 ;
        RECT  96.72 172.716 96.744 172.8 ;
    END
  END i_b[83]
  PIN i_b[84]
    DIRECTION INPUT ;
    USE SIGNAL ;
    PORT
      LAYER M5 ;
        RECT  96.816 172.716 96.84 172.8 ;
    END
  END i_b[84]
  PIN i_b[85]
    DIRECTION INPUT ;
    USE SIGNAL ;
    PORT
      LAYER M5 ;
        RECT  96.912 172.716 96.936 172.8 ;
    END
  END i_b[85]
  PIN i_b[86]
    DIRECTION INPUT ;
    USE SIGNAL ;
    PORT
      LAYER M5 ;
        RECT  97.008 172.716 97.032 172.8 ;
    END
  END i_b[86]
  PIN i_b[87]
    DIRECTION INPUT ;
    USE SIGNAL ;
    PORT
      LAYER M5 ;
        RECT  97.104 172.716 97.128 172.8 ;
    END
  END i_b[87]
  PIN i_b[88]
    DIRECTION INPUT ;
    USE SIGNAL ;
    PORT
      LAYER M5 ;
        RECT  97.2 172.716 97.224 172.8 ;
    END
  END i_b[88]
  PIN i_b[89]
    DIRECTION INPUT ;
    USE SIGNAL ;
    PORT
      LAYER M5 ;
        RECT  97.296 172.716 97.32 172.8 ;
    END
  END i_b[89]
  PIN i_b[8]
    DIRECTION INPUT ;
    USE SIGNAL ;
    PORT
      LAYER M5 ;
        RECT  63.408 172.716 63.432 172.8 ;
    END
  END i_b[8]
  PIN i_b[90]
    DIRECTION INPUT ;
    USE SIGNAL ;
    PORT
      LAYER M5 ;
        RECT  97.392 172.716 97.416 172.8 ;
    END
  END i_b[90]
  PIN i_b[91]
    DIRECTION INPUT ;
    USE SIGNAL ;
    PORT
      LAYER M5 ;
        RECT  97.488 172.716 97.512 172.8 ;
    END
  END i_b[91]
  PIN i_b[92]
    DIRECTION INPUT ;
    USE SIGNAL ;
    PORT
      LAYER M5 ;
        RECT  97.584 172.716 97.608 172.8 ;
    END
  END i_b[92]
  PIN i_b[93]
    DIRECTION INPUT ;
    USE SIGNAL ;
    PORT
      LAYER M5 ;
        RECT  97.68 172.716 97.704 172.8 ;
    END
  END i_b[93]
  PIN i_b[94]
    DIRECTION INPUT ;
    USE SIGNAL ;
    PORT
      LAYER M5 ;
        RECT  97.776 172.716 97.8 172.8 ;
    END
  END i_b[94]
  PIN i_b[95]
    DIRECTION INPUT ;
    USE SIGNAL ;
    PORT
      LAYER M5 ;
        RECT  97.872 172.716 97.896 172.8 ;
    END
  END i_b[95]
  PIN i_b[96]
    DIRECTION INPUT ;
    USE SIGNAL ;
    PORT
      LAYER M5 ;
        RECT  97.968 172.716 97.992 172.8 ;
    END
  END i_b[96]
  PIN i_b[97]
    DIRECTION INPUT ;
    USE SIGNAL ;
    PORT
      LAYER M5 ;
        RECT  98.064 172.716 98.088 172.8 ;
    END
  END i_b[97]
  PIN i_b[98]
    DIRECTION INPUT ;
    USE SIGNAL ;
    PORT
      LAYER M5 ;
        RECT  98.16 172.716 98.184 172.8 ;
    END
  END i_b[98]
  PIN i_b[99]
    DIRECTION INPUT ;
    USE SIGNAL ;
    PORT
      LAYER M5 ;
        RECT  98.256 172.716 98.28 172.8 ;
    END
  END i_b[99]
  PIN i_b[9]
    DIRECTION INPUT ;
    USE SIGNAL ;
    PORT
      LAYER M5 ;
        RECT  63.504 172.716 63.528 172.8 ;
    END
  END i_b[9]
  PIN i_r[0]
    DIRECTION INPUT ;
    USE SIGNAL ;
    PORT
      LAYER M5 ;
        RECT  80.592 0 80.616 0.084 ;
    END
  END i_r[0]
  PIN i_r[100]
    DIRECTION INPUT ;
    USE SIGNAL ;
    PORT
      LAYER M5 ;
        RECT  84.048 0 84.072 0.084 ;
    END
  END i_r[100]
  PIN i_r[101]
    DIRECTION INPUT ;
    USE SIGNAL ;
    PORT
      LAYER M5 ;
        RECT  84.144 0 84.168 0.084 ;
    END
  END i_r[101]
  PIN i_r[102]
    DIRECTION INPUT ;
    USE SIGNAL ;
    PORT
      LAYER M5 ;
        RECT  84.24 0 84.264 0.084 ;
    END
  END i_r[102]
  PIN i_r[103]
    DIRECTION INPUT ;
    USE SIGNAL ;
    PORT
      LAYER M5 ;
        RECT  84.336 0 84.36 0.084 ;
    END
  END i_r[103]
  PIN i_r[104]
    DIRECTION INPUT ;
    USE SIGNAL ;
    PORT
      LAYER M5 ;
        RECT  84.432 0 84.456 0.084 ;
    END
  END i_r[104]
  PIN i_r[105]
    DIRECTION INPUT ;
    USE SIGNAL ;
    PORT
      LAYER M5 ;
        RECT  84.528 0 84.552 0.084 ;
    END
  END i_r[105]
  PIN i_r[106]
    DIRECTION INPUT ;
    USE SIGNAL ;
    PORT
      LAYER M5 ;
        RECT  84.624 0 84.648 0.084 ;
    END
  END i_r[106]
  PIN i_r[107]
    DIRECTION INPUT ;
    USE SIGNAL ;
    PORT
      LAYER M5 ;
        RECT  84.72 0 84.744 0.084 ;
    END
  END i_r[107]
  PIN i_r[108]
    DIRECTION INPUT ;
    USE SIGNAL ;
    PORT
      LAYER M5 ;
        RECT  84.816 0 84.84 0.084 ;
    END
  END i_r[108]
  PIN i_r[109]
    DIRECTION INPUT ;
    USE SIGNAL ;
    PORT
      LAYER M5 ;
        RECT  84.912 0 84.936 0.084 ;
    END
  END i_r[109]
  PIN i_r[10]
    DIRECTION INPUT ;
    USE SIGNAL ;
    PORT
      LAYER M5 ;
        RECT  81.552 0 81.576 0.084 ;
    END
  END i_r[10]
  PIN i_r[110]
    DIRECTION INPUT ;
    USE SIGNAL ;
    PORT
      LAYER M5 ;
        RECT  85.008 0 85.032 0.084 ;
    END
  END i_r[110]
  PIN i_r[111]
    DIRECTION INPUT ;
    USE SIGNAL ;
    PORT
      LAYER M5 ;
        RECT  85.104 0 85.128 0.084 ;
    END
  END i_r[111]
  PIN i_r[112]
    DIRECTION INPUT ;
    USE SIGNAL ;
    PORT
      LAYER M5 ;
        RECT  85.2 0 85.224 0.084 ;
    END
  END i_r[112]
  PIN i_r[113]
    DIRECTION INPUT ;
    USE SIGNAL ;
    PORT
      LAYER M5 ;
        RECT  85.296 0 85.32 0.084 ;
    END
  END i_r[113]
  PIN i_r[114]
    DIRECTION INPUT ;
    USE SIGNAL ;
    PORT
      LAYER M5 ;
        RECT  85.392 0 85.416 0.084 ;
    END
  END i_r[114]
  PIN i_r[115]
    DIRECTION INPUT ;
    USE SIGNAL ;
    PORT
      LAYER M5 ;
        RECT  85.488 0 85.512 0.084 ;
    END
  END i_r[115]
  PIN i_r[116]
    DIRECTION INPUT ;
    USE SIGNAL ;
    PORT
      LAYER M5 ;
        RECT  85.584 0 85.608 0.084 ;
    END
  END i_r[116]
  PIN i_r[117]
    DIRECTION INPUT ;
    USE SIGNAL ;
    PORT
      LAYER M5 ;
        RECT  85.68 0 85.704 0.084 ;
    END
  END i_r[117]
  PIN i_r[118]
    DIRECTION INPUT ;
    USE SIGNAL ;
    PORT
      LAYER M5 ;
        RECT  85.776 0 85.8 0.084 ;
    END
  END i_r[118]
  PIN i_r[119]
    DIRECTION INPUT ;
    USE SIGNAL ;
    PORT
      LAYER M5 ;
        RECT  85.872 0 85.896 0.084 ;
    END
  END i_r[119]
  PIN i_r[11]
    DIRECTION INPUT ;
    USE SIGNAL ;
    PORT
      LAYER M5 ;
        RECT  81.648 0 81.672 0.084 ;
    END
  END i_r[11]
  PIN i_r[120]
    DIRECTION INPUT ;
    USE SIGNAL ;
    PORT
      LAYER M5 ;
        RECT  85.968 0 85.992 0.084 ;
    END
  END i_r[120]
  PIN i_r[121]
    DIRECTION INPUT ;
    USE SIGNAL ;
    PORT
      LAYER M5 ;
        RECT  86.064 0 86.088 0.084 ;
    END
  END i_r[121]
  PIN i_r[122]
    DIRECTION INPUT ;
    USE SIGNAL ;
    PORT
      LAYER M5 ;
        RECT  86.16 0 86.184 0.084 ;
    END
  END i_r[122]
  PIN i_r[123]
    DIRECTION INPUT ;
    USE SIGNAL ;
    PORT
      LAYER M5 ;
        RECT  86.256 0 86.28 0.084 ;
    END
  END i_r[123]
  PIN i_r[124]
    DIRECTION INPUT ;
    USE SIGNAL ;
    PORT
      LAYER M5 ;
        RECT  86.352 0 86.376 0.084 ;
    END
  END i_r[124]
  PIN i_r[125]
    DIRECTION INPUT ;
    USE SIGNAL ;
    PORT
      LAYER M5 ;
        RECT  86.448 0 86.472 0.084 ;
    END
  END i_r[125]
  PIN i_r[126]
    DIRECTION INPUT ;
    USE SIGNAL ;
    PORT
      LAYER M5 ;
        RECT  86.544 0 86.568 0.084 ;
    END
  END i_r[126]
  PIN i_r[127]
    DIRECTION INPUT ;
    USE SIGNAL ;
    PORT
      LAYER M5 ;
        RECT  86.64 0 86.664 0.084 ;
    END
  END i_r[127]
  PIN i_r[128]
    DIRECTION INPUT ;
    USE SIGNAL ;
    PORT
      LAYER M5 ;
        RECT  89.808 0 89.832 0.084 ;
    END
  END i_r[128]
  PIN i_r[129]
    DIRECTION INPUT ;
    USE SIGNAL ;
    PORT
      LAYER M5 ;
        RECT  89.904 0 89.928 0.084 ;
    END
  END i_r[129]
  PIN i_r[12]
    DIRECTION INPUT ;
    USE SIGNAL ;
    PORT
      LAYER M5 ;
        RECT  81.744 0 81.768 0.084 ;
    END
  END i_r[12]
  PIN i_r[130]
    DIRECTION INPUT ;
    USE SIGNAL ;
    PORT
      LAYER M5 ;
        RECT  90 0 90.024 0.084 ;
    END
  END i_r[130]
  PIN i_r[131]
    DIRECTION INPUT ;
    USE SIGNAL ;
    PORT
      LAYER M5 ;
        RECT  90.096 0 90.12 0.084 ;
    END
  END i_r[131]
  PIN i_r[132]
    DIRECTION INPUT ;
    USE SIGNAL ;
    PORT
      LAYER M5 ;
        RECT  90.192 0 90.216 0.084 ;
    END
  END i_r[132]
  PIN i_r[133]
    DIRECTION INPUT ;
    USE SIGNAL ;
    PORT
      LAYER M5 ;
        RECT  90.288 0 90.312 0.084 ;
    END
  END i_r[133]
  PIN i_r[134]
    DIRECTION INPUT ;
    USE SIGNAL ;
    PORT
      LAYER M5 ;
        RECT  90.384 0 90.408 0.084 ;
    END
  END i_r[134]
  PIN i_r[135]
    DIRECTION INPUT ;
    USE SIGNAL ;
    PORT
      LAYER M5 ;
        RECT  90.48 0 90.504 0.084 ;
    END
  END i_r[135]
  PIN i_r[136]
    DIRECTION INPUT ;
    USE SIGNAL ;
    PORT
      LAYER M5 ;
        RECT  90.576 0 90.6 0.084 ;
    END
  END i_r[136]
  PIN i_r[137]
    DIRECTION INPUT ;
    USE SIGNAL ;
    PORT
      LAYER M5 ;
        RECT  90.672 0 90.696 0.084 ;
    END
  END i_r[137]
  PIN i_r[138]
    DIRECTION INPUT ;
    USE SIGNAL ;
    PORT
      LAYER M5 ;
        RECT  90.768 0 90.792 0.084 ;
    END
  END i_r[138]
  PIN i_r[139]
    DIRECTION INPUT ;
    USE SIGNAL ;
    PORT
      LAYER M5 ;
        RECT  90.864 0 90.888 0.084 ;
    END
  END i_r[139]
  PIN i_r[13]
    DIRECTION INPUT ;
    USE SIGNAL ;
    PORT
      LAYER M5 ;
        RECT  81.84 0 81.864 0.084 ;
    END
  END i_r[13]
  PIN i_r[140]
    DIRECTION INPUT ;
    USE SIGNAL ;
    PORT
      LAYER M5 ;
        RECT  90.96 0 90.984 0.084 ;
    END
  END i_r[140]
  PIN i_r[141]
    DIRECTION INPUT ;
    USE SIGNAL ;
    PORT
      LAYER M5 ;
        RECT  91.056 0 91.08 0.084 ;
    END
  END i_r[141]
  PIN i_r[142]
    DIRECTION INPUT ;
    USE SIGNAL ;
    PORT
      LAYER M5 ;
        RECT  91.152 0 91.176 0.084 ;
    END
  END i_r[142]
  PIN i_r[143]
    DIRECTION INPUT ;
    USE SIGNAL ;
    PORT
      LAYER M5 ;
        RECT  91.248 0 91.272 0.084 ;
    END
  END i_r[143]
  PIN i_r[144]
    DIRECTION INPUT ;
    USE SIGNAL ;
    PORT
      LAYER M5 ;
        RECT  91.344 0 91.368 0.084 ;
    END
  END i_r[144]
  PIN i_r[145]
    DIRECTION INPUT ;
    USE SIGNAL ;
    PORT
      LAYER M5 ;
        RECT  91.44 0 91.464 0.084 ;
    END
  END i_r[145]
  PIN i_r[146]
    DIRECTION INPUT ;
    USE SIGNAL ;
    PORT
      LAYER M5 ;
        RECT  91.536 0 91.56 0.084 ;
    END
  END i_r[146]
  PIN i_r[147]
    DIRECTION INPUT ;
    USE SIGNAL ;
    PORT
      LAYER M5 ;
        RECT  91.632 0 91.656 0.084 ;
    END
  END i_r[147]
  PIN i_r[148]
    DIRECTION INPUT ;
    USE SIGNAL ;
    PORT
      LAYER M5 ;
        RECT  91.728 0 91.752 0.084 ;
    END
  END i_r[148]
  PIN i_r[149]
    DIRECTION INPUT ;
    USE SIGNAL ;
    PORT
      LAYER M5 ;
        RECT  91.824 0 91.848 0.084 ;
    END
  END i_r[149]
  PIN i_r[14]
    DIRECTION INPUT ;
    USE SIGNAL ;
    PORT
      LAYER M5 ;
        RECT  81.936 0 81.96 0.084 ;
    END
  END i_r[14]
  PIN i_r[150]
    DIRECTION INPUT ;
    USE SIGNAL ;
    PORT
      LAYER M5 ;
        RECT  91.92 0 91.944 0.084 ;
    END
  END i_r[150]
  PIN i_r[151]
    DIRECTION INPUT ;
    USE SIGNAL ;
    PORT
      LAYER M5 ;
        RECT  92.016 0 92.04 0.084 ;
    END
  END i_r[151]
  PIN i_r[152]
    DIRECTION INPUT ;
    USE SIGNAL ;
    PORT
      LAYER M5 ;
        RECT  92.112 0 92.136 0.084 ;
    END
  END i_r[152]
  PIN i_r[153]
    DIRECTION INPUT ;
    USE SIGNAL ;
    PORT
      LAYER M5 ;
        RECT  92.208 0 92.232 0.084 ;
    END
  END i_r[153]
  PIN i_r[154]
    DIRECTION INPUT ;
    USE SIGNAL ;
    PORT
      LAYER M5 ;
        RECT  92.304 0 92.328 0.084 ;
    END
  END i_r[154]
  PIN i_r[155]
    DIRECTION INPUT ;
    USE SIGNAL ;
    PORT
      LAYER M5 ;
        RECT  92.4 0 92.424 0.084 ;
    END
  END i_r[155]
  PIN i_r[156]
    DIRECTION INPUT ;
    USE SIGNAL ;
    PORT
      LAYER M5 ;
        RECT  92.496 0 92.52 0.084 ;
    END
  END i_r[156]
  PIN i_r[157]
    DIRECTION INPUT ;
    USE SIGNAL ;
    PORT
      LAYER M5 ;
        RECT  92.592 0 92.616 0.084 ;
    END
  END i_r[157]
  PIN i_r[158]
    DIRECTION INPUT ;
    USE SIGNAL ;
    PORT
      LAYER M5 ;
        RECT  92.688 0 92.712 0.084 ;
    END
  END i_r[158]
  PIN i_r[159]
    DIRECTION INPUT ;
    USE SIGNAL ;
    PORT
      LAYER M5 ;
        RECT  92.784 0 92.808 0.084 ;
    END
  END i_r[159]
  PIN i_r[15]
    DIRECTION INPUT ;
    USE SIGNAL ;
    PORT
      LAYER M5 ;
        RECT  82.032 0 82.056 0.084 ;
    END
  END i_r[15]
  PIN i_r[160]
    DIRECTION INPUT ;
    USE SIGNAL ;
    PORT
      LAYER M5 ;
        RECT  77.52 0 77.544 0.084 ;
    END
  END i_r[160]
  PIN i_r[161]
    DIRECTION INPUT ;
    USE SIGNAL ;
    PORT
      LAYER M5 ;
        RECT  77.616 0 77.64 0.084 ;
    END
  END i_r[161]
  PIN i_r[162]
    DIRECTION INPUT ;
    USE SIGNAL ;
    PORT
      LAYER M5 ;
        RECT  77.712 0 77.736 0.084 ;
    END
  END i_r[162]
  PIN i_r[163]
    DIRECTION INPUT ;
    USE SIGNAL ;
    PORT
      LAYER M5 ;
        RECT  77.808 0 77.832 0.084 ;
    END
  END i_r[163]
  PIN i_r[164]
    DIRECTION INPUT ;
    USE SIGNAL ;
    PORT
      LAYER M5 ;
        RECT  77.904 0 77.928 0.084 ;
    END
  END i_r[164]
  PIN i_r[165]
    DIRECTION INPUT ;
    USE SIGNAL ;
    PORT
      LAYER M5 ;
        RECT  78 0 78.024 0.084 ;
    END
  END i_r[165]
  PIN i_r[166]
    DIRECTION INPUT ;
    USE SIGNAL ;
    PORT
      LAYER M5 ;
        RECT  78.096 0 78.12 0.084 ;
    END
  END i_r[166]
  PIN i_r[167]
    DIRECTION INPUT ;
    USE SIGNAL ;
    PORT
      LAYER M5 ;
        RECT  78.192 0 78.216 0.084 ;
    END
  END i_r[167]
  PIN i_r[168]
    DIRECTION INPUT ;
    USE SIGNAL ;
    PORT
      LAYER M5 ;
        RECT  78.288 0 78.312 0.084 ;
    END
  END i_r[168]
  PIN i_r[169]
    DIRECTION INPUT ;
    USE SIGNAL ;
    PORT
      LAYER M5 ;
        RECT  78.384 0 78.408 0.084 ;
    END
  END i_r[169]
  PIN i_r[16]
    DIRECTION INPUT ;
    USE SIGNAL ;
    PORT
      LAYER M5 ;
        RECT  82.128 0 82.152 0.084 ;
    END
  END i_r[16]
  PIN i_r[170]
    DIRECTION INPUT ;
    USE SIGNAL ;
    PORT
      LAYER M5 ;
        RECT  78.48 0 78.504 0.084 ;
    END
  END i_r[170]
  PIN i_r[171]
    DIRECTION INPUT ;
    USE SIGNAL ;
    PORT
      LAYER M5 ;
        RECT  78.576 0 78.6 0.084 ;
    END
  END i_r[171]
  PIN i_r[172]
    DIRECTION INPUT ;
    USE SIGNAL ;
    PORT
      LAYER M5 ;
        RECT  78.672 0 78.696 0.084 ;
    END
  END i_r[172]
  PIN i_r[173]
    DIRECTION INPUT ;
    USE SIGNAL ;
    PORT
      LAYER M5 ;
        RECT  78.768 0 78.792 0.084 ;
    END
  END i_r[173]
  PIN i_r[174]
    DIRECTION INPUT ;
    USE SIGNAL ;
    PORT
      LAYER M5 ;
        RECT  78.864 0 78.888 0.084 ;
    END
  END i_r[174]
  PIN i_r[175]
    DIRECTION INPUT ;
    USE SIGNAL ;
    PORT
      LAYER M5 ;
        RECT  78.96 0 78.984 0.084 ;
    END
  END i_r[175]
  PIN i_r[176]
    DIRECTION INPUT ;
    USE SIGNAL ;
    PORT
      LAYER M5 ;
        RECT  79.056 0 79.08 0.084 ;
    END
  END i_r[176]
  PIN i_r[177]
    DIRECTION INPUT ;
    USE SIGNAL ;
    PORT
      LAYER M5 ;
        RECT  79.152 0 79.176 0.084 ;
    END
  END i_r[177]
  PIN i_r[178]
    DIRECTION INPUT ;
    USE SIGNAL ;
    PORT
      LAYER M5 ;
        RECT  79.248 0 79.272 0.084 ;
    END
  END i_r[178]
  PIN i_r[179]
    DIRECTION INPUT ;
    USE SIGNAL ;
    PORT
      LAYER M5 ;
        RECT  79.344 0 79.368 0.084 ;
    END
  END i_r[179]
  PIN i_r[17]
    DIRECTION INPUT ;
    USE SIGNAL ;
    PORT
      LAYER M5 ;
        RECT  82.224 0 82.248 0.084 ;
    END
  END i_r[17]
  PIN i_r[180]
    DIRECTION INPUT ;
    USE SIGNAL ;
    PORT
      LAYER M5 ;
        RECT  79.44 0 79.464 0.084 ;
    END
  END i_r[180]
  PIN i_r[181]
    DIRECTION INPUT ;
    USE SIGNAL ;
    PORT
      LAYER M5 ;
        RECT  79.536 0 79.56 0.084 ;
    END
  END i_r[181]
  PIN i_r[182]
    DIRECTION INPUT ;
    USE SIGNAL ;
    PORT
      LAYER M5 ;
        RECT  79.632 0 79.656 0.084 ;
    END
  END i_r[182]
  PIN i_r[183]
    DIRECTION INPUT ;
    USE SIGNAL ;
    PORT
      LAYER M5 ;
        RECT  79.728 0 79.752 0.084 ;
    END
  END i_r[183]
  PIN i_r[184]
    DIRECTION INPUT ;
    USE SIGNAL ;
    PORT
      LAYER M5 ;
        RECT  79.824 0 79.848 0.084 ;
    END
  END i_r[184]
  PIN i_r[185]
    DIRECTION INPUT ;
    USE SIGNAL ;
    PORT
      LAYER M5 ;
        RECT  79.92 0 79.944 0.084 ;
    END
  END i_r[185]
  PIN i_r[186]
    DIRECTION INPUT ;
    USE SIGNAL ;
    PORT
      LAYER M5 ;
        RECT  80.016 0 80.04 0.084 ;
    END
  END i_r[186]
  PIN i_r[187]
    DIRECTION INPUT ;
    USE SIGNAL ;
    PORT
      LAYER M5 ;
        RECT  80.112 0 80.136 0.084 ;
    END
  END i_r[187]
  PIN i_r[188]
    DIRECTION INPUT ;
    USE SIGNAL ;
    PORT
      LAYER M5 ;
        RECT  80.208 0 80.232 0.084 ;
    END
  END i_r[188]
  PIN i_r[189]
    DIRECTION INPUT ;
    USE SIGNAL ;
    PORT
      LAYER M5 ;
        RECT  80.304 0 80.328 0.084 ;
    END
  END i_r[189]
  PIN i_r[18]
    DIRECTION INPUT ;
    USE SIGNAL ;
    PORT
      LAYER M5 ;
        RECT  82.32 0 82.344 0.084 ;
    END
  END i_r[18]
  PIN i_r[190]
    DIRECTION INPUT ;
    USE SIGNAL ;
    PORT
      LAYER M5 ;
        RECT  80.4 0 80.424 0.084 ;
    END
  END i_r[190]
  PIN i_r[191]
    DIRECTION INPUT ;
    USE SIGNAL ;
    PORT
      LAYER M5 ;
        RECT  80.496 0 80.52 0.084 ;
    END
  END i_r[191]
  PIN i_r[192]
    DIRECTION INPUT ;
    USE SIGNAL ;
    PORT
      LAYER M5 ;
        RECT  86.736 0 86.76 0.084 ;
    END
  END i_r[192]
  PIN i_r[193]
    DIRECTION INPUT ;
    USE SIGNAL ;
    PORT
      LAYER M5 ;
        RECT  86.832 0 86.856 0.084 ;
    END
  END i_r[193]
  PIN i_r[194]
    DIRECTION INPUT ;
    USE SIGNAL ;
    PORT
      LAYER M5 ;
        RECT  86.928 0 86.952 0.084 ;
    END
  END i_r[194]
  PIN i_r[195]
    DIRECTION INPUT ;
    USE SIGNAL ;
    PORT
      LAYER M5 ;
        RECT  87.024 0 87.048 0.084 ;
    END
  END i_r[195]
  PIN i_r[196]
    DIRECTION INPUT ;
    USE SIGNAL ;
    PORT
      LAYER M5 ;
        RECT  87.12 0 87.144 0.084 ;
    END
  END i_r[196]
  PIN i_r[197]
    DIRECTION INPUT ;
    USE SIGNAL ;
    PORT
      LAYER M5 ;
        RECT  87.216 0 87.24 0.084 ;
    END
  END i_r[197]
  PIN i_r[198]
    DIRECTION INPUT ;
    USE SIGNAL ;
    PORT
      LAYER M5 ;
        RECT  87.312 0 87.336 0.084 ;
    END
  END i_r[198]
  PIN i_r[199]
    DIRECTION INPUT ;
    USE SIGNAL ;
    PORT
      LAYER M5 ;
        RECT  87.408 0 87.432 0.084 ;
    END
  END i_r[199]
  PIN i_r[19]
    DIRECTION INPUT ;
    USE SIGNAL ;
    PORT
      LAYER M5 ;
        RECT  82.416 0 82.44 0.084 ;
    END
  END i_r[19]
  PIN i_r[1]
    DIRECTION INPUT ;
    USE SIGNAL ;
    PORT
      LAYER M5 ;
        RECT  80.688 0 80.712 0.084 ;
    END
  END i_r[1]
  PIN i_r[200]
    DIRECTION INPUT ;
    USE SIGNAL ;
    PORT
      LAYER M5 ;
        RECT  87.504 0 87.528 0.084 ;
    END
  END i_r[200]
  PIN i_r[201]
    DIRECTION INPUT ;
    USE SIGNAL ;
    PORT
      LAYER M5 ;
        RECT  87.6 0 87.624 0.084 ;
    END
  END i_r[201]
  PIN i_r[202]
    DIRECTION INPUT ;
    USE SIGNAL ;
    PORT
      LAYER M5 ;
        RECT  87.696 0 87.72 0.084 ;
    END
  END i_r[202]
  PIN i_r[203]
    DIRECTION INPUT ;
    USE SIGNAL ;
    PORT
      LAYER M5 ;
        RECT  87.792 0 87.816 0.084 ;
    END
  END i_r[203]
  PIN i_r[204]
    DIRECTION INPUT ;
    USE SIGNAL ;
    PORT
      LAYER M5 ;
        RECT  87.888 0 87.912 0.084 ;
    END
  END i_r[204]
  PIN i_r[205]
    DIRECTION INPUT ;
    USE SIGNAL ;
    PORT
      LAYER M5 ;
        RECT  87.984 0 88.008 0.084 ;
    END
  END i_r[205]
  PIN i_r[206]
    DIRECTION INPUT ;
    USE SIGNAL ;
    PORT
      LAYER M5 ;
        RECT  88.08 0 88.104 0.084 ;
    END
  END i_r[206]
  PIN i_r[207]
    DIRECTION INPUT ;
    USE SIGNAL ;
    PORT
      LAYER M5 ;
        RECT  88.176 0 88.2 0.084 ;
    END
  END i_r[207]
  PIN i_r[208]
    DIRECTION INPUT ;
    USE SIGNAL ;
    PORT
      LAYER M5 ;
        RECT  88.272 0 88.296 0.084 ;
    END
  END i_r[208]
  PIN i_r[209]
    DIRECTION INPUT ;
    USE SIGNAL ;
    PORT
      LAYER M5 ;
        RECT  88.368 0 88.392 0.084 ;
    END
  END i_r[209]
  PIN i_r[20]
    DIRECTION INPUT ;
    USE SIGNAL ;
    PORT
      LAYER M5 ;
        RECT  82.512 0 82.536 0.084 ;
    END
  END i_r[20]
  PIN i_r[210]
    DIRECTION INPUT ;
    USE SIGNAL ;
    PORT
      LAYER M5 ;
        RECT  88.464 0 88.488 0.084 ;
    END
  END i_r[210]
  PIN i_r[211]
    DIRECTION INPUT ;
    USE SIGNAL ;
    PORT
      LAYER M5 ;
        RECT  88.56 0 88.584 0.084 ;
    END
  END i_r[211]
  PIN i_r[212]
    DIRECTION INPUT ;
    USE SIGNAL ;
    PORT
      LAYER M5 ;
        RECT  88.656 0 88.68 0.084 ;
    END
  END i_r[212]
  PIN i_r[213]
    DIRECTION INPUT ;
    USE SIGNAL ;
    PORT
      LAYER M5 ;
        RECT  88.752 0 88.776 0.084 ;
    END
  END i_r[213]
  PIN i_r[214]
    DIRECTION INPUT ;
    USE SIGNAL ;
    PORT
      LAYER M5 ;
        RECT  88.848 0 88.872 0.084 ;
    END
  END i_r[214]
  PIN i_r[215]
    DIRECTION INPUT ;
    USE SIGNAL ;
    PORT
      LAYER M5 ;
        RECT  88.944 0 88.968 0.084 ;
    END
  END i_r[215]
  PIN i_r[216]
    DIRECTION INPUT ;
    USE SIGNAL ;
    PORT
      LAYER M5 ;
        RECT  89.04 0 89.064 0.084 ;
    END
  END i_r[216]
  PIN i_r[217]
    DIRECTION INPUT ;
    USE SIGNAL ;
    PORT
      LAYER M5 ;
        RECT  89.136 0 89.16 0.084 ;
    END
  END i_r[217]
  PIN i_r[218]
    DIRECTION INPUT ;
    USE SIGNAL ;
    PORT
      LAYER M5 ;
        RECT  89.232 0 89.256 0.084 ;
    END
  END i_r[218]
  PIN i_r[219]
    DIRECTION INPUT ;
    USE SIGNAL ;
    PORT
      LAYER M5 ;
        RECT  89.328 0 89.352 0.084 ;
    END
  END i_r[219]
  PIN i_r[21]
    DIRECTION INPUT ;
    USE SIGNAL ;
    PORT
      LAYER M5 ;
        RECT  82.608 0 82.632 0.084 ;
    END
  END i_r[21]
  PIN i_r[220]
    DIRECTION INPUT ;
    USE SIGNAL ;
    PORT
      LAYER M5 ;
        RECT  89.424 0 89.448 0.084 ;
    END
  END i_r[220]
  PIN i_r[221]
    DIRECTION INPUT ;
    USE SIGNAL ;
    PORT
      LAYER M5 ;
        RECT  89.52 0 89.544 0.084 ;
    END
  END i_r[221]
  PIN i_r[222]
    DIRECTION INPUT ;
    USE SIGNAL ;
    PORT
      LAYER M5 ;
        RECT  89.616 0 89.64 0.084 ;
    END
  END i_r[222]
  PIN i_r[223]
    DIRECTION INPUT ;
    USE SIGNAL ;
    PORT
      LAYER M5 ;
        RECT  89.712 0 89.736 0.084 ;
    END
  END i_r[223]
  PIN i_r[224]
    DIRECTION INPUT ;
    USE SIGNAL ;
    PORT
      LAYER M5 ;
        RECT  112.08 0 112.104 0.084 ;
    END
  END i_r[224]
  PIN i_r[225]
    DIRECTION INPUT ;
    USE SIGNAL ;
    PORT
      LAYER M5 ;
        RECT  112.176 0 112.2 0.084 ;
    END
  END i_r[225]
  PIN i_r[226]
    DIRECTION INPUT ;
    USE SIGNAL ;
    PORT
      LAYER M5 ;
        RECT  112.272 0 112.296 0.084 ;
    END
  END i_r[226]
  PIN i_r[227]
    DIRECTION INPUT ;
    USE SIGNAL ;
    PORT
      LAYER M5 ;
        RECT  112.368 0 112.392 0.084 ;
    END
  END i_r[227]
  PIN i_r[228]
    DIRECTION INPUT ;
    USE SIGNAL ;
    PORT
      LAYER M5 ;
        RECT  112.464 0 112.488 0.084 ;
    END
  END i_r[228]
  PIN i_r[229]
    DIRECTION INPUT ;
    USE SIGNAL ;
    PORT
      LAYER M5 ;
        RECT  112.56 0 112.584 0.084 ;
    END
  END i_r[229]
  PIN i_r[22]
    DIRECTION INPUT ;
    USE SIGNAL ;
    PORT
      LAYER M5 ;
        RECT  82.704 0 82.728 0.084 ;
    END
  END i_r[22]
  PIN i_r[230]
    DIRECTION INPUT ;
    USE SIGNAL ;
    PORT
      LAYER M5 ;
        RECT  112.656 0 112.68 0.084 ;
    END
  END i_r[230]
  PIN i_r[231]
    DIRECTION INPUT ;
    USE SIGNAL ;
    PORT
      LAYER M5 ;
        RECT  112.752 0 112.776 0.084 ;
    END
  END i_r[231]
  PIN i_r[232]
    DIRECTION INPUT ;
    USE SIGNAL ;
    PORT
      LAYER M5 ;
        RECT  112.848 0 112.872 0.084 ;
    END
  END i_r[232]
  PIN i_r[233]
    DIRECTION INPUT ;
    USE SIGNAL ;
    PORT
      LAYER M5 ;
        RECT  112.944 0 112.968 0.084 ;
    END
  END i_r[233]
  PIN i_r[234]
    DIRECTION INPUT ;
    USE SIGNAL ;
    PORT
      LAYER M5 ;
        RECT  113.04 0 113.064 0.084 ;
    END
  END i_r[234]
  PIN i_r[235]
    DIRECTION INPUT ;
    USE SIGNAL ;
    PORT
      LAYER M5 ;
        RECT  113.136 0 113.16 0.084 ;
    END
  END i_r[235]
  PIN i_r[236]
    DIRECTION INPUT ;
    USE SIGNAL ;
    PORT
      LAYER M5 ;
        RECT  113.232 0 113.256 0.084 ;
    END
  END i_r[236]
  PIN i_r[237]
    DIRECTION INPUT ;
    USE SIGNAL ;
    PORT
      LAYER M5 ;
        RECT  113.328 0 113.352 0.084 ;
    END
  END i_r[237]
  PIN i_r[238]
    DIRECTION INPUT ;
    USE SIGNAL ;
    PORT
      LAYER M5 ;
        RECT  113.424 0 113.448 0.084 ;
    END
  END i_r[238]
  PIN i_r[239]
    DIRECTION INPUT ;
    USE SIGNAL ;
    PORT
      LAYER M5 ;
        RECT  113.52 0 113.544 0.084 ;
    END
  END i_r[239]
  PIN i_r[23]
    DIRECTION INPUT ;
    USE SIGNAL ;
    PORT
      LAYER M5 ;
        RECT  82.8 0 82.824 0.084 ;
    END
  END i_r[23]
  PIN i_r[240]
    DIRECTION INPUT ;
    USE SIGNAL ;
    PORT
      LAYER M5 ;
        RECT  113.616 0 113.64 0.084 ;
    END
  END i_r[240]
  PIN i_r[241]
    DIRECTION INPUT ;
    USE SIGNAL ;
    PORT
      LAYER M5 ;
        RECT  113.712 0 113.736 0.084 ;
    END
  END i_r[241]
  PIN i_r[242]
    DIRECTION INPUT ;
    USE SIGNAL ;
    PORT
      LAYER M5 ;
        RECT  113.808 0 113.832 0.084 ;
    END
  END i_r[242]
  PIN i_r[243]
    DIRECTION INPUT ;
    USE SIGNAL ;
    PORT
      LAYER M5 ;
        RECT  113.904 0 113.928 0.084 ;
    END
  END i_r[243]
  PIN i_r[244]
    DIRECTION INPUT ;
    USE SIGNAL ;
    PORT
      LAYER M5 ;
        RECT  114 0 114.024 0.084 ;
    END
  END i_r[244]
  PIN i_r[245]
    DIRECTION INPUT ;
    USE SIGNAL ;
    PORT
      LAYER M5 ;
        RECT  114.096 0 114.12 0.084 ;
    END
  END i_r[245]
  PIN i_r[246]
    DIRECTION INPUT ;
    USE SIGNAL ;
    PORT
      LAYER M5 ;
        RECT  114.192 0 114.216 0.084 ;
    END
  END i_r[246]
  PIN i_r[247]
    DIRECTION INPUT ;
    USE SIGNAL ;
    PORT
      LAYER M5 ;
        RECT  114.288 0 114.312 0.084 ;
    END
  END i_r[247]
  PIN i_r[248]
    DIRECTION INPUT ;
    USE SIGNAL ;
    PORT
      LAYER M5 ;
        RECT  114.384 0 114.408 0.084 ;
    END
  END i_r[248]
  PIN i_r[249]
    DIRECTION INPUT ;
    USE SIGNAL ;
    PORT
      LAYER M5 ;
        RECT  114.48 0 114.504 0.084 ;
    END
  END i_r[249]
  PIN i_r[24]
    DIRECTION INPUT ;
    USE SIGNAL ;
    PORT
      LAYER M5 ;
        RECT  82.896 0 82.92 0.084 ;
    END
  END i_r[24]
  PIN i_r[250]
    DIRECTION INPUT ;
    USE SIGNAL ;
    PORT
      LAYER M5 ;
        RECT  114.576 0 114.6 0.084 ;
    END
  END i_r[250]
  PIN i_r[251]
    DIRECTION INPUT ;
    USE SIGNAL ;
    PORT
      LAYER M5 ;
        RECT  114.672 0 114.696 0.084 ;
    END
  END i_r[251]
  PIN i_r[252]
    DIRECTION INPUT ;
    USE SIGNAL ;
    PORT
      LAYER M5 ;
        RECT  114.768 0 114.792 0.084 ;
    END
  END i_r[252]
  PIN i_r[253]
    DIRECTION INPUT ;
    USE SIGNAL ;
    PORT
      LAYER M5 ;
        RECT  114.864 0 114.888 0.084 ;
    END
  END i_r[253]
  PIN i_r[254]
    DIRECTION INPUT ;
    USE SIGNAL ;
    PORT
      LAYER M5 ;
        RECT  114.96 0 114.984 0.084 ;
    END
  END i_r[254]
  PIN i_r[255]
    DIRECTION INPUT ;
    USE SIGNAL ;
    PORT
      LAYER M5 ;
        RECT  115.056 0 115.08 0.084 ;
    END
  END i_r[255]
  PIN i_r[256]
    DIRECTION INPUT ;
    USE SIGNAL ;
    PORT
      LAYER M5 ;
        RECT  61.392 0 61.416 0.084 ;
    END
  END i_r[256]
  PIN i_r[257]
    DIRECTION INPUT ;
    USE SIGNAL ;
    PORT
      LAYER M5 ;
        RECT  61.488 0 61.512 0.084 ;
    END
  END i_r[257]
  PIN i_r[258]
    DIRECTION INPUT ;
    USE SIGNAL ;
    PORT
      LAYER M5 ;
        RECT  61.584 0 61.608 0.084 ;
    END
  END i_r[258]
  PIN i_r[259]
    DIRECTION INPUT ;
    USE SIGNAL ;
    PORT
      LAYER M5 ;
        RECT  61.68 0 61.704 0.084 ;
    END
  END i_r[259]
  PIN i_r[25]
    DIRECTION INPUT ;
    USE SIGNAL ;
    PORT
      LAYER M5 ;
        RECT  82.992 0 83.016 0.084 ;
    END
  END i_r[25]
  PIN i_r[260]
    DIRECTION INPUT ;
    USE SIGNAL ;
    PORT
      LAYER M5 ;
        RECT  61.776 0 61.8 0.084 ;
    END
  END i_r[260]
  PIN i_r[261]
    DIRECTION INPUT ;
    USE SIGNAL ;
    PORT
      LAYER M5 ;
        RECT  61.872 0 61.896 0.084 ;
    END
  END i_r[261]
  PIN i_r[262]
    DIRECTION INPUT ;
    USE SIGNAL ;
    PORT
      LAYER M5 ;
        RECT  61.968 0 61.992 0.084 ;
    END
  END i_r[262]
  PIN i_r[263]
    DIRECTION INPUT ;
    USE SIGNAL ;
    PORT
      LAYER M5 ;
        RECT  62.064 0 62.088 0.084 ;
    END
  END i_r[263]
  PIN i_r[264]
    DIRECTION INPUT ;
    USE SIGNAL ;
    PORT
      LAYER M5 ;
        RECT  62.16 0 62.184 0.084 ;
    END
  END i_r[264]
  PIN i_r[265]
    DIRECTION INPUT ;
    USE SIGNAL ;
    PORT
      LAYER M5 ;
        RECT  62.256 0 62.28 0.084 ;
    END
  END i_r[265]
  PIN i_r[266]
    DIRECTION INPUT ;
    USE SIGNAL ;
    PORT
      LAYER M5 ;
        RECT  62.352 0 62.376 0.084 ;
    END
  END i_r[266]
  PIN i_r[267]
    DIRECTION INPUT ;
    USE SIGNAL ;
    PORT
      LAYER M5 ;
        RECT  62.448 0 62.472 0.084 ;
    END
  END i_r[267]
  PIN i_r[268]
    DIRECTION INPUT ;
    USE SIGNAL ;
    PORT
      LAYER M5 ;
        RECT  62.544 0 62.568 0.084 ;
    END
  END i_r[268]
  PIN i_r[269]
    DIRECTION INPUT ;
    USE SIGNAL ;
    PORT
      LAYER M5 ;
        RECT  62.64 0 62.664 0.084 ;
    END
  END i_r[269]
  PIN i_r[26]
    DIRECTION INPUT ;
    USE SIGNAL ;
    PORT
      LAYER M5 ;
        RECT  83.088 0 83.112 0.084 ;
    END
  END i_r[26]
  PIN i_r[270]
    DIRECTION INPUT ;
    USE SIGNAL ;
    PORT
      LAYER M5 ;
        RECT  62.736 0 62.76 0.084 ;
    END
  END i_r[270]
  PIN i_r[271]
    DIRECTION INPUT ;
    USE SIGNAL ;
    PORT
      LAYER M5 ;
        RECT  62.832 0 62.856 0.084 ;
    END
  END i_r[271]
  PIN i_r[272]
    DIRECTION INPUT ;
    USE SIGNAL ;
    PORT
      LAYER M5 ;
        RECT  62.928 0 62.952 0.084 ;
    END
  END i_r[272]
  PIN i_r[273]
    DIRECTION INPUT ;
    USE SIGNAL ;
    PORT
      LAYER M5 ;
        RECT  63.024 0 63.048 0.084 ;
    END
  END i_r[273]
  PIN i_r[274]
    DIRECTION INPUT ;
    USE SIGNAL ;
    PORT
      LAYER M5 ;
        RECT  63.12 0 63.144 0.084 ;
    END
  END i_r[274]
  PIN i_r[275]
    DIRECTION INPUT ;
    USE SIGNAL ;
    PORT
      LAYER M5 ;
        RECT  63.216 0 63.24 0.084 ;
    END
  END i_r[275]
  PIN i_r[27]
    DIRECTION INPUT ;
    USE SIGNAL ;
    PORT
      LAYER M5 ;
        RECT  83.184 0 83.208 0.084 ;
    END
  END i_r[27]
  PIN i_r[28]
    DIRECTION INPUT ;
    USE SIGNAL ;
    PORT
      LAYER M5 ;
        RECT  83.28 0 83.304 0.084 ;
    END
  END i_r[28]
  PIN i_r[29]
    DIRECTION INPUT ;
    USE SIGNAL ;
    PORT
      LAYER M5 ;
        RECT  83.376 0 83.4 0.084 ;
    END
  END i_r[29]
  PIN i_r[2]
    DIRECTION INPUT ;
    USE SIGNAL ;
    PORT
      LAYER M5 ;
        RECT  80.784 0 80.808 0.084 ;
    END
  END i_r[2]
  PIN i_r[30]
    DIRECTION INPUT ;
    USE SIGNAL ;
    PORT
      LAYER M5 ;
        RECT  83.472 0 83.496 0.084 ;
    END
  END i_r[30]
  PIN i_r[31]
    DIRECTION INPUT ;
    USE SIGNAL ;
    PORT
      LAYER M5 ;
        RECT  83.568 0 83.592 0.084 ;
    END
  END i_r[31]
  PIN i_r[32]
    DIRECTION INPUT ;
    USE SIGNAL ;
    PORT
      LAYER M5 ;
        RECT  109.008 0 109.032 0.084 ;
    END
  END i_r[32]
  PIN i_r[33]
    DIRECTION INPUT ;
    USE SIGNAL ;
    PORT
      LAYER M5 ;
        RECT  109.104 0 109.128 0.084 ;
    END
  END i_r[33]
  PIN i_r[34]
    DIRECTION INPUT ;
    USE SIGNAL ;
    PORT
      LAYER M5 ;
        RECT  109.2 0 109.224 0.084 ;
    END
  END i_r[34]
  PIN i_r[35]
    DIRECTION INPUT ;
    USE SIGNAL ;
    PORT
      LAYER M5 ;
        RECT  109.296 0 109.32 0.084 ;
    END
  END i_r[35]
  PIN i_r[36]
    DIRECTION INPUT ;
    USE SIGNAL ;
    PORT
      LAYER M5 ;
        RECT  109.392 0 109.416 0.084 ;
    END
  END i_r[36]
  PIN i_r[37]
    DIRECTION INPUT ;
    USE SIGNAL ;
    PORT
      LAYER M5 ;
        RECT  109.488 0 109.512 0.084 ;
    END
  END i_r[37]
  PIN i_r[38]
    DIRECTION INPUT ;
    USE SIGNAL ;
    PORT
      LAYER M5 ;
        RECT  109.584 0 109.608 0.084 ;
    END
  END i_r[38]
  PIN i_r[39]
    DIRECTION INPUT ;
    USE SIGNAL ;
    PORT
      LAYER M5 ;
        RECT  109.68 0 109.704 0.084 ;
    END
  END i_r[39]
  PIN i_r[3]
    DIRECTION INPUT ;
    USE SIGNAL ;
    PORT
      LAYER M5 ;
        RECT  80.88 0 80.904 0.084 ;
    END
  END i_r[3]
  PIN i_r[40]
    DIRECTION INPUT ;
    USE SIGNAL ;
    PORT
      LAYER M5 ;
        RECT  109.776 0 109.8 0.084 ;
    END
  END i_r[40]
  PIN i_r[41]
    DIRECTION INPUT ;
    USE SIGNAL ;
    PORT
      LAYER M5 ;
        RECT  109.872 0 109.896 0.084 ;
    END
  END i_r[41]
  PIN i_r[42]
    DIRECTION INPUT ;
    USE SIGNAL ;
    PORT
      LAYER M5 ;
        RECT  109.968 0 109.992 0.084 ;
    END
  END i_r[42]
  PIN i_r[43]
    DIRECTION INPUT ;
    USE SIGNAL ;
    PORT
      LAYER M5 ;
        RECT  110.064 0 110.088 0.084 ;
    END
  END i_r[43]
  PIN i_r[44]
    DIRECTION INPUT ;
    USE SIGNAL ;
    PORT
      LAYER M5 ;
        RECT  110.16 0 110.184 0.084 ;
    END
  END i_r[44]
  PIN i_r[45]
    DIRECTION INPUT ;
    USE SIGNAL ;
    PORT
      LAYER M5 ;
        RECT  110.256 0 110.28 0.084 ;
    END
  END i_r[45]
  PIN i_r[46]
    DIRECTION INPUT ;
    USE SIGNAL ;
    PORT
      LAYER M5 ;
        RECT  110.352 0 110.376 0.084 ;
    END
  END i_r[46]
  PIN i_r[47]
    DIRECTION INPUT ;
    USE SIGNAL ;
    PORT
      LAYER M5 ;
        RECT  110.448 0 110.472 0.084 ;
    END
  END i_r[47]
  PIN i_r[48]
    DIRECTION INPUT ;
    USE SIGNAL ;
    PORT
      LAYER M5 ;
        RECT  110.544 0 110.568 0.084 ;
    END
  END i_r[48]
  PIN i_r[49]
    DIRECTION INPUT ;
    USE SIGNAL ;
    PORT
      LAYER M5 ;
        RECT  110.64 0 110.664 0.084 ;
    END
  END i_r[49]
  PIN i_r[4]
    DIRECTION INPUT ;
    USE SIGNAL ;
    PORT
      LAYER M5 ;
        RECT  80.976 0 81 0.084 ;
    END
  END i_r[4]
  PIN i_r[50]
    DIRECTION INPUT ;
    USE SIGNAL ;
    PORT
      LAYER M5 ;
        RECT  110.736 0 110.76 0.084 ;
    END
  END i_r[50]
  PIN i_r[51]
    DIRECTION INPUT ;
    USE SIGNAL ;
    PORT
      LAYER M5 ;
        RECT  110.832 0 110.856 0.084 ;
    END
  END i_r[51]
  PIN i_r[52]
    DIRECTION INPUT ;
    USE SIGNAL ;
    PORT
      LAYER M5 ;
        RECT  110.928 0 110.952 0.084 ;
    END
  END i_r[52]
  PIN i_r[53]
    DIRECTION INPUT ;
    USE SIGNAL ;
    PORT
      LAYER M5 ;
        RECT  111.024 0 111.048 0.084 ;
    END
  END i_r[53]
  PIN i_r[54]
    DIRECTION INPUT ;
    USE SIGNAL ;
    PORT
      LAYER M5 ;
        RECT  111.12 0 111.144 0.084 ;
    END
  END i_r[54]
  PIN i_r[55]
    DIRECTION INPUT ;
    USE SIGNAL ;
    PORT
      LAYER M5 ;
        RECT  111.216 0 111.24 0.084 ;
    END
  END i_r[55]
  PIN i_r[56]
    DIRECTION INPUT ;
    USE SIGNAL ;
    PORT
      LAYER M5 ;
        RECT  111.312 0 111.336 0.084 ;
    END
  END i_r[56]
  PIN i_r[57]
    DIRECTION INPUT ;
    USE SIGNAL ;
    PORT
      LAYER M5 ;
        RECT  111.408 0 111.432 0.084 ;
    END
  END i_r[57]
  PIN i_r[58]
    DIRECTION INPUT ;
    USE SIGNAL ;
    PORT
      LAYER M5 ;
        RECT  111.504 0 111.528 0.084 ;
    END
  END i_r[58]
  PIN i_r[59]
    DIRECTION INPUT ;
    USE SIGNAL ;
    PORT
      LAYER M5 ;
        RECT  111.6 0 111.624 0.084 ;
    END
  END i_r[59]
  PIN i_r[5]
    DIRECTION INPUT ;
    USE SIGNAL ;
    PORT
      LAYER M5 ;
        RECT  81.072 0 81.096 0.084 ;
    END
  END i_r[5]
  PIN i_r[60]
    DIRECTION INPUT ;
    USE SIGNAL ;
    PORT
      LAYER M5 ;
        RECT  111.696 0 111.72 0.084 ;
    END
  END i_r[60]
  PIN i_r[61]
    DIRECTION INPUT ;
    USE SIGNAL ;
    PORT
      LAYER M5 ;
        RECT  111.792 0 111.816 0.084 ;
    END
  END i_r[61]
  PIN i_r[62]
    DIRECTION INPUT ;
    USE SIGNAL ;
    PORT
      LAYER M5 ;
        RECT  111.888 0 111.912 0.084 ;
    END
  END i_r[62]
  PIN i_r[63]
    DIRECTION INPUT ;
    USE SIGNAL ;
    PORT
      LAYER M5 ;
        RECT  111.984 0 112.008 0.084 ;
    END
  END i_r[63]
  PIN i_r[64]
    DIRECTION INPUT ;
    USE SIGNAL ;
    PORT
      LAYER M5 ;
        RECT  92.88 0 92.904 0.084 ;
    END
  END i_r[64]
  PIN i_r[65]
    DIRECTION INPUT ;
    USE SIGNAL ;
    PORT
      LAYER M5 ;
        RECT  92.976 0 93 0.084 ;
    END
  END i_r[65]
  PIN i_r[66]
    DIRECTION INPUT ;
    USE SIGNAL ;
    PORT
      LAYER M5 ;
        RECT  93.072 0 93.096 0.084 ;
    END
  END i_r[66]
  PIN i_r[67]
    DIRECTION INPUT ;
    USE SIGNAL ;
    PORT
      LAYER M5 ;
        RECT  93.168 0 93.192 0.084 ;
    END
  END i_r[67]
  PIN i_r[68]
    DIRECTION INPUT ;
    USE SIGNAL ;
    PORT
      LAYER M5 ;
        RECT  93.264 0 93.288 0.084 ;
    END
  END i_r[68]
  PIN i_r[69]
    DIRECTION INPUT ;
    USE SIGNAL ;
    PORT
      LAYER M5 ;
        RECT  93.36 0 93.384 0.084 ;
    END
  END i_r[69]
  PIN i_r[6]
    DIRECTION INPUT ;
    USE SIGNAL ;
    PORT
      LAYER M5 ;
        RECT  81.168 0 81.192 0.084 ;
    END
  END i_r[6]
  PIN i_r[70]
    DIRECTION INPUT ;
    USE SIGNAL ;
    PORT
      LAYER M5 ;
        RECT  93.456 0 93.48 0.084 ;
    END
  END i_r[70]
  PIN i_r[71]
    DIRECTION INPUT ;
    USE SIGNAL ;
    PORT
      LAYER M5 ;
        RECT  93.552 0 93.576 0.084 ;
    END
  END i_r[71]
  PIN i_r[72]
    DIRECTION INPUT ;
    USE SIGNAL ;
    PORT
      LAYER M5 ;
        RECT  93.648 0 93.672 0.084 ;
    END
  END i_r[72]
  PIN i_r[73]
    DIRECTION INPUT ;
    USE SIGNAL ;
    PORT
      LAYER M5 ;
        RECT  93.744 0 93.768 0.084 ;
    END
  END i_r[73]
  PIN i_r[74]
    DIRECTION INPUT ;
    USE SIGNAL ;
    PORT
      LAYER M5 ;
        RECT  93.84 0 93.864 0.084 ;
    END
  END i_r[74]
  PIN i_r[75]
    DIRECTION INPUT ;
    USE SIGNAL ;
    PORT
      LAYER M5 ;
        RECT  93.936 0 93.96 0.084 ;
    END
  END i_r[75]
  PIN i_r[76]
    DIRECTION INPUT ;
    USE SIGNAL ;
    PORT
      LAYER M5 ;
        RECT  94.032 0 94.056 0.084 ;
    END
  END i_r[76]
  PIN i_r[77]
    DIRECTION INPUT ;
    USE SIGNAL ;
    PORT
      LAYER M5 ;
        RECT  94.128 0 94.152 0.084 ;
    END
  END i_r[77]
  PIN i_r[78]
    DIRECTION INPUT ;
    USE SIGNAL ;
    PORT
      LAYER M5 ;
        RECT  94.224 0 94.248 0.084 ;
    END
  END i_r[78]
  PIN i_r[79]
    DIRECTION INPUT ;
    USE SIGNAL ;
    PORT
      LAYER M5 ;
        RECT  94.32 0 94.344 0.084 ;
    END
  END i_r[79]
  PIN i_r[7]
    DIRECTION INPUT ;
    USE SIGNAL ;
    PORT
      LAYER M5 ;
        RECT  81.264 0 81.288 0.084 ;
    END
  END i_r[7]
  PIN i_r[80]
    DIRECTION INPUT ;
    USE SIGNAL ;
    PORT
      LAYER M5 ;
        RECT  94.416 0 94.44 0.084 ;
    END
  END i_r[80]
  PIN i_r[81]
    DIRECTION INPUT ;
    USE SIGNAL ;
    PORT
      LAYER M5 ;
        RECT  94.512 0 94.536 0.084 ;
    END
  END i_r[81]
  PIN i_r[82]
    DIRECTION INPUT ;
    USE SIGNAL ;
    PORT
      LAYER M5 ;
        RECT  94.608 0 94.632 0.084 ;
    END
  END i_r[82]
  PIN i_r[83]
    DIRECTION INPUT ;
    USE SIGNAL ;
    PORT
      LAYER M5 ;
        RECT  94.704 0 94.728 0.084 ;
    END
  END i_r[83]
  PIN i_r[84]
    DIRECTION INPUT ;
    USE SIGNAL ;
    PORT
      LAYER M5 ;
        RECT  94.8 0 94.824 0.084 ;
    END
  END i_r[84]
  PIN i_r[85]
    DIRECTION INPUT ;
    USE SIGNAL ;
    PORT
      LAYER M5 ;
        RECT  94.896 0 94.92 0.084 ;
    END
  END i_r[85]
  PIN i_r[86]
    DIRECTION INPUT ;
    USE SIGNAL ;
    PORT
      LAYER M5 ;
        RECT  94.992 0 95.016 0.084 ;
    END
  END i_r[86]
  PIN i_r[87]
    DIRECTION INPUT ;
    USE SIGNAL ;
    PORT
      LAYER M5 ;
        RECT  95.088 0 95.112 0.084 ;
    END
  END i_r[87]
  PIN i_r[88]
    DIRECTION INPUT ;
    USE SIGNAL ;
    PORT
      LAYER M5 ;
        RECT  95.184 0 95.208 0.084 ;
    END
  END i_r[88]
  PIN i_r[89]
    DIRECTION INPUT ;
    USE SIGNAL ;
    PORT
      LAYER M5 ;
        RECT  95.28 0 95.304 0.084 ;
    END
  END i_r[89]
  PIN i_r[8]
    DIRECTION INPUT ;
    USE SIGNAL ;
    PORT
      LAYER M5 ;
        RECT  81.36 0 81.384 0.084 ;
    END
  END i_r[8]
  PIN i_r[90]
    DIRECTION INPUT ;
    USE SIGNAL ;
    PORT
      LAYER M5 ;
        RECT  95.376 0 95.4 0.084 ;
    END
  END i_r[90]
  PIN i_r[91]
    DIRECTION INPUT ;
    USE SIGNAL ;
    PORT
      LAYER M5 ;
        RECT  95.472 0 95.496 0.084 ;
    END
  END i_r[91]
  PIN i_r[92]
    DIRECTION INPUT ;
    USE SIGNAL ;
    PORT
      LAYER M5 ;
        RECT  95.568 0 95.592 0.084 ;
    END
  END i_r[92]
  PIN i_r[93]
    DIRECTION INPUT ;
    USE SIGNAL ;
    PORT
      LAYER M5 ;
        RECT  95.664 0 95.688 0.084 ;
    END
  END i_r[93]
  PIN i_r[94]
    DIRECTION INPUT ;
    USE SIGNAL ;
    PORT
      LAYER M5 ;
        RECT  95.76 0 95.784 0.084 ;
    END
  END i_r[94]
  PIN i_r[95]
    DIRECTION INPUT ;
    USE SIGNAL ;
    PORT
      LAYER M5 ;
        RECT  95.856 0 95.88 0.084 ;
    END
  END i_r[95]
  PIN i_r[96]
    DIRECTION INPUT ;
    USE SIGNAL ;
    PORT
      LAYER M5 ;
        RECT  83.664 0 83.688 0.084 ;
    END
  END i_r[96]
  PIN i_r[97]
    DIRECTION INPUT ;
    USE SIGNAL ;
    PORT
      LAYER M5 ;
        RECT  83.76 0 83.784 0.084 ;
    END
  END i_r[97]
  PIN i_r[98]
    DIRECTION INPUT ;
    USE SIGNAL ;
    PORT
      LAYER M5 ;
        RECT  83.856 0 83.88 0.084 ;
    END
  END i_r[98]
  PIN i_r[99]
    DIRECTION INPUT ;
    USE SIGNAL ;
    PORT
      LAYER M5 ;
        RECT  83.952 0 83.976 0.084 ;
    END
  END i_r[99]
  PIN i_r[9]
    DIRECTION INPUT ;
    USE SIGNAL ;
    PORT
      LAYER M5 ;
        RECT  81.456 0 81.48 0.084 ;
    END
  END i_r[9]
  PIN i_s[0]
    DIRECTION INPUT ;
    USE SIGNAL ;
    PORT
      LAYER M5 ;
        RECT  63.312 0 63.336 0.084 ;
    END
  END i_s[0]
  PIN i_s[100]
    DIRECTION INPUT ;
    USE SIGNAL ;
    PORT
      LAYER M5 ;
        RECT  99.024 0 99.048 0.084 ;
    END
  END i_s[100]
  PIN i_s[101]
    DIRECTION INPUT ;
    USE SIGNAL ;
    PORT
      LAYER M5 ;
        RECT  99.12 0 99.144 0.084 ;
    END
  END i_s[101]
  PIN i_s[102]
    DIRECTION INPUT ;
    USE SIGNAL ;
    PORT
      LAYER M5 ;
        RECT  99.216 0 99.24 0.084 ;
    END
  END i_s[102]
  PIN i_s[103]
    DIRECTION INPUT ;
    USE SIGNAL ;
    PORT
      LAYER M5 ;
        RECT  99.312 0 99.336 0.084 ;
    END
  END i_s[103]
  PIN i_s[104]
    DIRECTION INPUT ;
    USE SIGNAL ;
    PORT
      LAYER M5 ;
        RECT  99.408 0 99.432 0.084 ;
    END
  END i_s[104]
  PIN i_s[105]
    DIRECTION INPUT ;
    USE SIGNAL ;
    PORT
      LAYER M5 ;
        RECT  99.504 0 99.528 0.084 ;
    END
  END i_s[105]
  PIN i_s[106]
    DIRECTION INPUT ;
    USE SIGNAL ;
    PORT
      LAYER M5 ;
        RECT  99.6 0 99.624 0.084 ;
    END
  END i_s[106]
  PIN i_s[107]
    DIRECTION INPUT ;
    USE SIGNAL ;
    PORT
      LAYER M5 ;
        RECT  99.696 0 99.72 0.084 ;
    END
  END i_s[107]
  PIN i_s[108]
    DIRECTION INPUT ;
    USE SIGNAL ;
    PORT
      LAYER M5 ;
        RECT  64.464 0 64.488 0.084 ;
    END
  END i_s[108]
  PIN i_s[109]
    DIRECTION INPUT ;
    USE SIGNAL ;
    PORT
      LAYER M5 ;
        RECT  64.56 0 64.584 0.084 ;
    END
  END i_s[109]
  PIN i_s[10]
    DIRECTION INPUT ;
    USE SIGNAL ;
    PORT
      LAYER M5 ;
        RECT  64.272 0 64.296 0.084 ;
    END
  END i_s[10]
  PIN i_s[110]
    DIRECTION INPUT ;
    USE SIGNAL ;
    PORT
      LAYER M5 ;
        RECT  64.656 0 64.68 0.084 ;
    END
  END i_s[110]
  PIN i_s[111]
    DIRECTION INPUT ;
    USE SIGNAL ;
    PORT
      LAYER M5 ;
        RECT  64.752 0 64.776 0.084 ;
    END
  END i_s[111]
  PIN i_s[112]
    DIRECTION INPUT ;
    USE SIGNAL ;
    PORT
      LAYER M5 ;
        RECT  64.848 0 64.872 0.084 ;
    END
  END i_s[112]
  PIN i_s[113]
    DIRECTION INPUT ;
    USE SIGNAL ;
    PORT
      LAYER M5 ;
        RECT  64.944 0 64.968 0.084 ;
    END
  END i_s[113]
  PIN i_s[114]
    DIRECTION INPUT ;
    USE SIGNAL ;
    PORT
      LAYER M5 ;
        RECT  65.04 0 65.064 0.084 ;
    END
  END i_s[114]
  PIN i_s[115]
    DIRECTION INPUT ;
    USE SIGNAL ;
    PORT
      LAYER M5 ;
        RECT  65.136 0 65.16 0.084 ;
    END
  END i_s[115]
  PIN i_s[116]
    DIRECTION INPUT ;
    USE SIGNAL ;
    PORT
      LAYER M5 ;
        RECT  65.232 0 65.256 0.084 ;
    END
  END i_s[116]
  PIN i_s[117]
    DIRECTION INPUT ;
    USE SIGNAL ;
    PORT
      LAYER M5 ;
        RECT  65.328 0 65.352 0.084 ;
    END
  END i_s[117]
  PIN i_s[118]
    DIRECTION INPUT ;
    USE SIGNAL ;
    PORT
      LAYER M5 ;
        RECT  65.424 0 65.448 0.084 ;
    END
  END i_s[118]
  PIN i_s[119]
    DIRECTION INPUT ;
    USE SIGNAL ;
    PORT
      LAYER M5 ;
        RECT  65.52 0 65.544 0.084 ;
    END
  END i_s[119]
  PIN i_s[11]
    DIRECTION INPUT ;
    USE SIGNAL ;
    PORT
      LAYER M5 ;
        RECT  64.368 0 64.392 0.084 ;
    END
  END i_s[11]
  PIN i_s[120]
    DIRECTION INPUT ;
    USE SIGNAL ;
    PORT
      LAYER M5 ;
        RECT  65.616 0 65.64 0.084 ;
    END
  END i_s[120]
  PIN i_s[121]
    DIRECTION INPUT ;
    USE SIGNAL ;
    PORT
      LAYER M5 ;
        RECT  65.712 0 65.736 0.084 ;
    END
  END i_s[121]
  PIN i_s[122]
    DIRECTION INPUT ;
    USE SIGNAL ;
    PORT
      LAYER M5 ;
        RECT  65.808 0 65.832 0.084 ;
    END
  END i_s[122]
  PIN i_s[123]
    DIRECTION INPUT ;
    USE SIGNAL ;
    PORT
      LAYER M5 ;
        RECT  65.904 0 65.928 0.084 ;
    END
  END i_s[123]
  PIN i_s[124]
    DIRECTION INPUT ;
    USE SIGNAL ;
    PORT
      LAYER M5 ;
        RECT  66 0 66.024 0.084 ;
    END
  END i_s[124]
  PIN i_s[125]
    DIRECTION INPUT ;
    USE SIGNAL ;
    PORT
      LAYER M5 ;
        RECT  66.096 0 66.12 0.084 ;
    END
  END i_s[125]
  PIN i_s[126]
    DIRECTION INPUT ;
    USE SIGNAL ;
    PORT
      LAYER M5 ;
        RECT  66.192 0 66.216 0.084 ;
    END
  END i_s[126]
  PIN i_s[127]
    DIRECTION INPUT ;
    USE SIGNAL ;
    PORT
      LAYER M5 ;
        RECT  66.288 0 66.312 0.084 ;
    END
  END i_s[127]
  PIN i_s[128]
    DIRECTION INPUT ;
    USE SIGNAL ;
    PORT
      LAYER M5 ;
        RECT  66.384 0 66.408 0.084 ;
    END
  END i_s[128]
  PIN i_s[129]
    DIRECTION INPUT ;
    USE SIGNAL ;
    PORT
      LAYER M5 ;
        RECT  66.48 0 66.504 0.084 ;
    END
  END i_s[129]
  PIN i_s[12]
    DIRECTION INPUT ;
    USE SIGNAL ;
    PORT
      LAYER M5 ;
        RECT  67.536 0 67.56 0.084 ;
    END
  END i_s[12]
  PIN i_s[130]
    DIRECTION INPUT ;
    USE SIGNAL ;
    PORT
      LAYER M5 ;
        RECT  66.576 0 66.6 0.084 ;
    END
  END i_s[130]
  PIN i_s[131]
    DIRECTION INPUT ;
    USE SIGNAL ;
    PORT
      LAYER M5 ;
        RECT  66.672 0 66.696 0.084 ;
    END
  END i_s[131]
  PIN i_s[132]
    DIRECTION INPUT ;
    USE SIGNAL ;
    PORT
      LAYER M5 ;
        RECT  66.768 0 66.792 0.084 ;
    END
  END i_s[132]
  PIN i_s[133]
    DIRECTION INPUT ;
    USE SIGNAL ;
    PORT
      LAYER M5 ;
        RECT  66.864 0 66.888 0.084 ;
    END
  END i_s[133]
  PIN i_s[134]
    DIRECTION INPUT ;
    USE SIGNAL ;
    PORT
      LAYER M5 ;
        RECT  66.96 0 66.984 0.084 ;
    END
  END i_s[134]
  PIN i_s[135]
    DIRECTION INPUT ;
    USE SIGNAL ;
    PORT
      LAYER M5 ;
        RECT  67.056 0 67.08 0.084 ;
    END
  END i_s[135]
  PIN i_s[136]
    DIRECTION INPUT ;
    USE SIGNAL ;
    PORT
      LAYER M5 ;
        RECT  67.152 0 67.176 0.084 ;
    END
  END i_s[136]
  PIN i_s[137]
    DIRECTION INPUT ;
    USE SIGNAL ;
    PORT
      LAYER M5 ;
        RECT  67.248 0 67.272 0.084 ;
    END
  END i_s[137]
  PIN i_s[138]
    DIRECTION INPUT ;
    USE SIGNAL ;
    PORT
      LAYER M5 ;
        RECT  67.344 0 67.368 0.084 ;
    END
  END i_s[138]
  PIN i_s[139]
    DIRECTION INPUT ;
    USE SIGNAL ;
    PORT
      LAYER M5 ;
        RECT  67.44 0 67.464 0.084 ;
    END
  END i_s[139]
  PIN i_s[13]
    DIRECTION INPUT ;
    USE SIGNAL ;
    PORT
      LAYER M5 ;
        RECT  67.632 0 67.656 0.084 ;
    END
  END i_s[13]
  PIN i_s[140]
    DIRECTION INPUT ;
    USE SIGNAL ;
    PORT
      LAYER M5 ;
        RECT  99.792 0 99.816 0.084 ;
    END
  END i_s[140]
  PIN i_s[141]
    DIRECTION INPUT ;
    USE SIGNAL ;
    PORT
      LAYER M5 ;
        RECT  99.888 0 99.912 0.084 ;
    END
  END i_s[141]
  PIN i_s[142]
    DIRECTION INPUT ;
    USE SIGNAL ;
    PORT
      LAYER M5 ;
        RECT  99.984 0 100.008 0.084 ;
    END
  END i_s[142]
  PIN i_s[143]
    DIRECTION INPUT ;
    USE SIGNAL ;
    PORT
      LAYER M5 ;
        RECT  100.08 0 100.104 0.084 ;
    END
  END i_s[143]
  PIN i_s[144]
    DIRECTION INPUT ;
    USE SIGNAL ;
    PORT
      LAYER M5 ;
        RECT  100.176 0 100.2 0.084 ;
    END
  END i_s[144]
  PIN i_s[145]
    DIRECTION INPUT ;
    USE SIGNAL ;
    PORT
      LAYER M5 ;
        RECT  100.272 0 100.296 0.084 ;
    END
  END i_s[145]
  PIN i_s[146]
    DIRECTION INPUT ;
    USE SIGNAL ;
    PORT
      LAYER M5 ;
        RECT  100.368 0 100.392 0.084 ;
    END
  END i_s[146]
  PIN i_s[147]
    DIRECTION INPUT ;
    USE SIGNAL ;
    PORT
      LAYER M5 ;
        RECT  100.464 0 100.488 0.084 ;
    END
  END i_s[147]
  PIN i_s[148]
    DIRECTION INPUT ;
    USE SIGNAL ;
    PORT
      LAYER M5 ;
        RECT  100.56 0 100.584 0.084 ;
    END
  END i_s[148]
  PIN i_s[149]
    DIRECTION INPUT ;
    USE SIGNAL ;
    PORT
      LAYER M5 ;
        RECT  100.656 0 100.68 0.084 ;
    END
  END i_s[149]
  PIN i_s[14]
    DIRECTION INPUT ;
    USE SIGNAL ;
    PORT
      LAYER M5 ;
        RECT  67.728 0 67.752 0.084 ;
    END
  END i_s[14]
  PIN i_s[150]
    DIRECTION INPUT ;
    USE SIGNAL ;
    PORT
      LAYER M5 ;
        RECT  100.752 0 100.776 0.084 ;
    END
  END i_s[150]
  PIN i_s[151]
    DIRECTION INPUT ;
    USE SIGNAL ;
    PORT
      LAYER M5 ;
        RECT  100.848 0 100.872 0.084 ;
    END
  END i_s[151]
  PIN i_s[152]
    DIRECTION INPUT ;
    USE SIGNAL ;
    PORT
      LAYER M5 ;
        RECT  100.944 0 100.968 0.084 ;
    END
  END i_s[152]
  PIN i_s[153]
    DIRECTION INPUT ;
    USE SIGNAL ;
    PORT
      LAYER M5 ;
        RECT  101.04 0 101.064 0.084 ;
    END
  END i_s[153]
  PIN i_s[154]
    DIRECTION INPUT ;
    USE SIGNAL ;
    PORT
      LAYER M5 ;
        RECT  101.136 0 101.16 0.084 ;
    END
  END i_s[154]
  PIN i_s[155]
    DIRECTION INPUT ;
    USE SIGNAL ;
    PORT
      LAYER M5 ;
        RECT  101.232 0 101.256 0.084 ;
    END
  END i_s[155]
  PIN i_s[156]
    DIRECTION INPUT ;
    USE SIGNAL ;
    PORT
      LAYER M5 ;
        RECT  101.328 0 101.352 0.084 ;
    END
  END i_s[156]
  PIN i_s[157]
    DIRECTION INPUT ;
    USE SIGNAL ;
    PORT
      LAYER M5 ;
        RECT  101.424 0 101.448 0.084 ;
    END
  END i_s[157]
  PIN i_s[158]
    DIRECTION INPUT ;
    USE SIGNAL ;
    PORT
      LAYER M5 ;
        RECT  101.52 0 101.544 0.084 ;
    END
  END i_s[158]
  PIN i_s[159]
    DIRECTION INPUT ;
    USE SIGNAL ;
    PORT
      LAYER M5 ;
        RECT  101.616 0 101.64 0.084 ;
    END
  END i_s[159]
  PIN i_s[15]
    DIRECTION INPUT ;
    USE SIGNAL ;
    PORT
      LAYER M5 ;
        RECT  67.824 0 67.848 0.084 ;
    END
  END i_s[15]
  PIN i_s[160]
    DIRECTION INPUT ;
    USE SIGNAL ;
    PORT
      LAYER M5 ;
        RECT  101.712 0 101.736 0.084 ;
    END
  END i_s[160]
  PIN i_s[161]
    DIRECTION INPUT ;
    USE SIGNAL ;
    PORT
      LAYER M5 ;
        RECT  101.808 0 101.832 0.084 ;
    END
  END i_s[161]
  PIN i_s[162]
    DIRECTION INPUT ;
    USE SIGNAL ;
    PORT
      LAYER M5 ;
        RECT  101.904 0 101.928 0.084 ;
    END
  END i_s[162]
  PIN i_s[163]
    DIRECTION INPUT ;
    USE SIGNAL ;
    PORT
      LAYER M5 ;
        RECT  102 0 102.024 0.084 ;
    END
  END i_s[163]
  PIN i_s[164]
    DIRECTION INPUT ;
    USE SIGNAL ;
    PORT
      LAYER M5 ;
        RECT  102.096 0 102.12 0.084 ;
    END
  END i_s[164]
  PIN i_s[165]
    DIRECTION INPUT ;
    USE SIGNAL ;
    PORT
      LAYER M5 ;
        RECT  102.192 0 102.216 0.084 ;
    END
  END i_s[165]
  PIN i_s[166]
    DIRECTION INPUT ;
    USE SIGNAL ;
    PORT
      LAYER M5 ;
        RECT  102.288 0 102.312 0.084 ;
    END
  END i_s[166]
  PIN i_s[167]
    DIRECTION INPUT ;
    USE SIGNAL ;
    PORT
      LAYER M5 ;
        RECT  102.384 0 102.408 0.084 ;
    END
  END i_s[167]
  PIN i_s[168]
    DIRECTION INPUT ;
    USE SIGNAL ;
    PORT
      LAYER M5 ;
        RECT  102.48 0 102.504 0.084 ;
    END
  END i_s[168]
  PIN i_s[169]
    DIRECTION INPUT ;
    USE SIGNAL ;
    PORT
      LAYER M5 ;
        RECT  102.576 0 102.6 0.084 ;
    END
  END i_s[169]
  PIN i_s[16]
    DIRECTION INPUT ;
    USE SIGNAL ;
    PORT
      LAYER M5 ;
        RECT  67.92 0 67.944 0.084 ;
    END
  END i_s[16]
  PIN i_s[170]
    DIRECTION INPUT ;
    USE SIGNAL ;
    PORT
      LAYER M5 ;
        RECT  102.672 0 102.696 0.084 ;
    END
  END i_s[170]
  PIN i_s[171]
    DIRECTION INPUT ;
    USE SIGNAL ;
    PORT
      LAYER M5 ;
        RECT  102.768 0 102.792 0.084 ;
    END
  END i_s[171]
  PIN i_s[172]
    DIRECTION INPUT ;
    USE SIGNAL ;
    PORT
      LAYER M5 ;
        RECT  70.608 0 70.632 0.084 ;
    END
  END i_s[172]
  PIN i_s[173]
    DIRECTION INPUT ;
    USE SIGNAL ;
    PORT
      LAYER M5 ;
        RECT  70.704 0 70.728 0.084 ;
    END
  END i_s[173]
  PIN i_s[174]
    DIRECTION INPUT ;
    USE SIGNAL ;
    PORT
      LAYER M5 ;
        RECT  70.8 0 70.824 0.084 ;
    END
  END i_s[174]
  PIN i_s[175]
    DIRECTION INPUT ;
    USE SIGNAL ;
    PORT
      LAYER M5 ;
        RECT  70.896 0 70.92 0.084 ;
    END
  END i_s[175]
  PIN i_s[176]
    DIRECTION INPUT ;
    USE SIGNAL ;
    PORT
      LAYER M5 ;
        RECT  70.992 0 71.016 0.084 ;
    END
  END i_s[176]
  PIN i_s[177]
    DIRECTION INPUT ;
    USE SIGNAL ;
    PORT
      LAYER M5 ;
        RECT  71.088 0 71.112 0.084 ;
    END
  END i_s[177]
  PIN i_s[178]
    DIRECTION INPUT ;
    USE SIGNAL ;
    PORT
      LAYER M5 ;
        RECT  71.184 0 71.208 0.084 ;
    END
  END i_s[178]
  PIN i_s[179]
    DIRECTION INPUT ;
    USE SIGNAL ;
    PORT
      LAYER M5 ;
        RECT  71.28 0 71.304 0.084 ;
    END
  END i_s[179]
  PIN i_s[17]
    DIRECTION INPUT ;
    USE SIGNAL ;
    PORT
      LAYER M5 ;
        RECT  68.016 0 68.04 0.084 ;
    END
  END i_s[17]
  PIN i_s[180]
    DIRECTION INPUT ;
    USE SIGNAL ;
    PORT
      LAYER M5 ;
        RECT  71.376 0 71.4 0.084 ;
    END
  END i_s[180]
  PIN i_s[181]
    DIRECTION INPUT ;
    USE SIGNAL ;
    PORT
      LAYER M5 ;
        RECT  71.472 0 71.496 0.084 ;
    END
  END i_s[181]
  PIN i_s[182]
    DIRECTION INPUT ;
    USE SIGNAL ;
    PORT
      LAYER M5 ;
        RECT  71.568 0 71.592 0.084 ;
    END
  END i_s[182]
  PIN i_s[183]
    DIRECTION INPUT ;
    USE SIGNAL ;
    PORT
      LAYER M5 ;
        RECT  71.664 0 71.688 0.084 ;
    END
  END i_s[183]
  PIN i_s[184]
    DIRECTION INPUT ;
    USE SIGNAL ;
    PORT
      LAYER M5 ;
        RECT  71.76 0 71.784 0.084 ;
    END
  END i_s[184]
  PIN i_s[185]
    DIRECTION INPUT ;
    USE SIGNAL ;
    PORT
      LAYER M5 ;
        RECT  71.856 0 71.88 0.084 ;
    END
  END i_s[185]
  PIN i_s[186]
    DIRECTION INPUT ;
    USE SIGNAL ;
    PORT
      LAYER M5 ;
        RECT  71.952 0 71.976 0.084 ;
    END
  END i_s[186]
  PIN i_s[187]
    DIRECTION INPUT ;
    USE SIGNAL ;
    PORT
      LAYER M5 ;
        RECT  72.048 0 72.072 0.084 ;
    END
  END i_s[187]
  PIN i_s[188]
    DIRECTION INPUT ;
    USE SIGNAL ;
    PORT
      LAYER M5 ;
        RECT  72.144 0 72.168 0.084 ;
    END
  END i_s[188]
  PIN i_s[189]
    DIRECTION INPUT ;
    USE SIGNAL ;
    PORT
      LAYER M5 ;
        RECT  72.24 0 72.264 0.084 ;
    END
  END i_s[189]
  PIN i_s[18]
    DIRECTION INPUT ;
    USE SIGNAL ;
    PORT
      LAYER M5 ;
        RECT  68.112 0 68.136 0.084 ;
    END
  END i_s[18]
  PIN i_s[190]
    DIRECTION INPUT ;
    USE SIGNAL ;
    PORT
      LAYER M5 ;
        RECT  72.336 0 72.36 0.084 ;
    END
  END i_s[190]
  PIN i_s[191]
    DIRECTION INPUT ;
    USE SIGNAL ;
    PORT
      LAYER M5 ;
        RECT  72.432 0 72.456 0.084 ;
    END
  END i_s[191]
  PIN i_s[192]
    DIRECTION INPUT ;
    USE SIGNAL ;
    PORT
      LAYER M5 ;
        RECT  72.528 0 72.552 0.084 ;
    END
  END i_s[192]
  PIN i_s[193]
    DIRECTION INPUT ;
    USE SIGNAL ;
    PORT
      LAYER M5 ;
        RECT  72.624 0 72.648 0.084 ;
    END
  END i_s[193]
  PIN i_s[194]
    DIRECTION INPUT ;
    USE SIGNAL ;
    PORT
      LAYER M5 ;
        RECT  72.72 0 72.744 0.084 ;
    END
  END i_s[194]
  PIN i_s[195]
    DIRECTION INPUT ;
    USE SIGNAL ;
    PORT
      LAYER M5 ;
        RECT  72.816 0 72.84 0.084 ;
    END
  END i_s[195]
  PIN i_s[196]
    DIRECTION INPUT ;
    USE SIGNAL ;
    PORT
      LAYER M5 ;
        RECT  72.912 0 72.936 0.084 ;
    END
  END i_s[196]
  PIN i_s[197]
    DIRECTION INPUT ;
    USE SIGNAL ;
    PORT
      LAYER M5 ;
        RECT  73.008 0 73.032 0.084 ;
    END
  END i_s[197]
  PIN i_s[198]
    DIRECTION INPUT ;
    USE SIGNAL ;
    PORT
      LAYER M5 ;
        RECT  73.104 0 73.128 0.084 ;
    END
  END i_s[198]
  PIN i_s[199]
    DIRECTION INPUT ;
    USE SIGNAL ;
    PORT
      LAYER M5 ;
        RECT  73.2 0 73.224 0.084 ;
    END
  END i_s[199]
  PIN i_s[19]
    DIRECTION INPUT ;
    USE SIGNAL ;
    PORT
      LAYER M5 ;
        RECT  68.208 0 68.232 0.084 ;
    END
  END i_s[19]
  PIN i_s[1]
    DIRECTION INPUT ;
    USE SIGNAL ;
    PORT
      LAYER M5 ;
        RECT  63.408 0 63.432 0.084 ;
    END
  END i_s[1]
  PIN i_s[200]
    DIRECTION INPUT ;
    USE SIGNAL ;
    PORT
      LAYER M5 ;
        RECT  73.296 0 73.32 0.084 ;
    END
  END i_s[200]
  PIN i_s[201]
    DIRECTION INPUT ;
    USE SIGNAL ;
    PORT
      LAYER M5 ;
        RECT  73.392 0 73.416 0.084 ;
    END
  END i_s[201]
  PIN i_s[202]
    DIRECTION INPUT ;
    USE SIGNAL ;
    PORT
      LAYER M5 ;
        RECT  73.488 0 73.512 0.084 ;
    END
  END i_s[202]
  PIN i_s[203]
    DIRECTION INPUT ;
    USE SIGNAL ;
    PORT
      LAYER M5 ;
        RECT  73.584 0 73.608 0.084 ;
    END
  END i_s[203]
  PIN i_s[204]
    DIRECTION INPUT ;
    USE SIGNAL ;
    PORT
      LAYER M5 ;
        RECT  102.864 0 102.888 0.084 ;
    END
  END i_s[204]
  PIN i_s[205]
    DIRECTION INPUT ;
    USE SIGNAL ;
    PORT
      LAYER M5 ;
        RECT  102.96 0 102.984 0.084 ;
    END
  END i_s[205]
  PIN i_s[206]
    DIRECTION INPUT ;
    USE SIGNAL ;
    PORT
      LAYER M5 ;
        RECT  103.056 0 103.08 0.084 ;
    END
  END i_s[206]
  PIN i_s[207]
    DIRECTION INPUT ;
    USE SIGNAL ;
    PORT
      LAYER M5 ;
        RECT  103.152 0 103.176 0.084 ;
    END
  END i_s[207]
  PIN i_s[208]
    DIRECTION INPUT ;
    USE SIGNAL ;
    PORT
      LAYER M5 ;
        RECT  103.248 0 103.272 0.084 ;
    END
  END i_s[208]
  PIN i_s[209]
    DIRECTION INPUT ;
    USE SIGNAL ;
    PORT
      LAYER M5 ;
        RECT  103.344 0 103.368 0.084 ;
    END
  END i_s[209]
  PIN i_s[20]
    DIRECTION INPUT ;
    USE SIGNAL ;
    PORT
      LAYER M5 ;
        RECT  68.304 0 68.328 0.084 ;
    END
  END i_s[20]
  PIN i_s[210]
    DIRECTION INPUT ;
    USE SIGNAL ;
    PORT
      LAYER M5 ;
        RECT  103.44 0 103.464 0.084 ;
    END
  END i_s[210]
  PIN i_s[211]
    DIRECTION INPUT ;
    USE SIGNAL ;
    PORT
      LAYER M5 ;
        RECT  103.536 0 103.56 0.084 ;
    END
  END i_s[211]
  PIN i_s[212]
    DIRECTION INPUT ;
    USE SIGNAL ;
    PORT
      LAYER M5 ;
        RECT  103.632 0 103.656 0.084 ;
    END
  END i_s[212]
  PIN i_s[213]
    DIRECTION INPUT ;
    USE SIGNAL ;
    PORT
      LAYER M5 ;
        RECT  103.728 0 103.752 0.084 ;
    END
  END i_s[213]
  PIN i_s[214]
    DIRECTION INPUT ;
    USE SIGNAL ;
    PORT
      LAYER M5 ;
        RECT  103.824 0 103.848 0.084 ;
    END
  END i_s[214]
  PIN i_s[215]
    DIRECTION INPUT ;
    USE SIGNAL ;
    PORT
      LAYER M5 ;
        RECT  103.92 0 103.944 0.084 ;
    END
  END i_s[215]
  PIN i_s[216]
    DIRECTION INPUT ;
    USE SIGNAL ;
    PORT
      LAYER M5 ;
        RECT  104.016 0 104.04 0.084 ;
    END
  END i_s[216]
  PIN i_s[217]
    DIRECTION INPUT ;
    USE SIGNAL ;
    PORT
      LAYER M5 ;
        RECT  104.112 0 104.136 0.084 ;
    END
  END i_s[217]
  PIN i_s[218]
    DIRECTION INPUT ;
    USE SIGNAL ;
    PORT
      LAYER M5 ;
        RECT  104.208 0 104.232 0.084 ;
    END
  END i_s[218]
  PIN i_s[219]
    DIRECTION INPUT ;
    USE SIGNAL ;
    PORT
      LAYER M5 ;
        RECT  104.304 0 104.328 0.084 ;
    END
  END i_s[219]
  PIN i_s[21]
    DIRECTION INPUT ;
    USE SIGNAL ;
    PORT
      LAYER M5 ;
        RECT  68.4 0 68.424 0.084 ;
    END
  END i_s[21]
  PIN i_s[220]
    DIRECTION INPUT ;
    USE SIGNAL ;
    PORT
      LAYER M5 ;
        RECT  104.4 0 104.424 0.084 ;
    END
  END i_s[220]
  PIN i_s[221]
    DIRECTION INPUT ;
    USE SIGNAL ;
    PORT
      LAYER M5 ;
        RECT  104.496 0 104.52 0.084 ;
    END
  END i_s[221]
  PIN i_s[222]
    DIRECTION INPUT ;
    USE SIGNAL ;
    PORT
      LAYER M5 ;
        RECT  104.592 0 104.616 0.084 ;
    END
  END i_s[222]
  PIN i_s[223]
    DIRECTION INPUT ;
    USE SIGNAL ;
    PORT
      LAYER M5 ;
        RECT  104.688 0 104.712 0.084 ;
    END
  END i_s[223]
  PIN i_s[224]
    DIRECTION INPUT ;
    USE SIGNAL ;
    PORT
      LAYER M5 ;
        RECT  104.784 0 104.808 0.084 ;
    END
  END i_s[224]
  PIN i_s[225]
    DIRECTION INPUT ;
    USE SIGNAL ;
    PORT
      LAYER M5 ;
        RECT  104.88 0 104.904 0.084 ;
    END
  END i_s[225]
  PIN i_s[226]
    DIRECTION INPUT ;
    USE SIGNAL ;
    PORT
      LAYER M5 ;
        RECT  104.976 0 105 0.084 ;
    END
  END i_s[226]
  PIN i_s[227]
    DIRECTION INPUT ;
    USE SIGNAL ;
    PORT
      LAYER M5 ;
        RECT  105.072 0 105.096 0.084 ;
    END
  END i_s[227]
  PIN i_s[228]
    DIRECTION INPUT ;
    USE SIGNAL ;
    PORT
      LAYER M5 ;
        RECT  105.168 0 105.192 0.084 ;
    END
  END i_s[228]
  PIN i_s[229]
    DIRECTION INPUT ;
    USE SIGNAL ;
    PORT
      LAYER M5 ;
        RECT  105.264 0 105.288 0.084 ;
    END
  END i_s[229]
  PIN i_s[22]
    DIRECTION INPUT ;
    USE SIGNAL ;
    PORT
      LAYER M5 ;
        RECT  68.496 0 68.52 0.084 ;
    END
  END i_s[22]
  PIN i_s[230]
    DIRECTION INPUT ;
    USE SIGNAL ;
    PORT
      LAYER M5 ;
        RECT  105.36 0 105.384 0.084 ;
    END
  END i_s[230]
  PIN i_s[231]
    DIRECTION INPUT ;
    USE SIGNAL ;
    PORT
      LAYER M5 ;
        RECT  105.456 0 105.48 0.084 ;
    END
  END i_s[231]
  PIN i_s[232]
    DIRECTION INPUT ;
    USE SIGNAL ;
    PORT
      LAYER M5 ;
        RECT  105.552 0 105.576 0.084 ;
    END
  END i_s[232]
  PIN i_s[233]
    DIRECTION INPUT ;
    USE SIGNAL ;
    PORT
      LAYER M5 ;
        RECT  105.648 0 105.672 0.084 ;
    END
  END i_s[233]
  PIN i_s[234]
    DIRECTION INPUT ;
    USE SIGNAL ;
    PORT
      LAYER M5 ;
        RECT  105.744 0 105.768 0.084 ;
    END
  END i_s[234]
  PIN i_s[235]
    DIRECTION INPUT ;
    USE SIGNAL ;
    PORT
      LAYER M5 ;
        RECT  105.84 0 105.864 0.084 ;
    END
  END i_s[235]
  PIN i_s[236]
    DIRECTION INPUT ;
    USE SIGNAL ;
    PORT
      LAYER M5 ;
        RECT  73.68 0 73.704 0.084 ;
    END
  END i_s[236]
  PIN i_s[237]
    DIRECTION INPUT ;
    USE SIGNAL ;
    PORT
      LAYER M5 ;
        RECT  73.776 0 73.8 0.084 ;
    END
  END i_s[237]
  PIN i_s[238]
    DIRECTION INPUT ;
    USE SIGNAL ;
    PORT
      LAYER M5 ;
        RECT  73.872 0 73.896 0.084 ;
    END
  END i_s[238]
  PIN i_s[239]
    DIRECTION INPUT ;
    USE SIGNAL ;
    PORT
      LAYER M5 ;
        RECT  73.968 0 73.992 0.084 ;
    END
  END i_s[239]
  PIN i_s[23]
    DIRECTION INPUT ;
    USE SIGNAL ;
    PORT
      LAYER M5 ;
        RECT  68.592 0 68.616 0.084 ;
    END
  END i_s[23]
  PIN i_s[240]
    DIRECTION INPUT ;
    USE SIGNAL ;
    PORT
      LAYER M5 ;
        RECT  74.064 0 74.088 0.084 ;
    END
  END i_s[240]
  PIN i_s[241]
    DIRECTION INPUT ;
    USE SIGNAL ;
    PORT
      LAYER M5 ;
        RECT  74.16 0 74.184 0.084 ;
    END
  END i_s[241]
  PIN i_s[242]
    DIRECTION INPUT ;
    USE SIGNAL ;
    PORT
      LAYER M5 ;
        RECT  74.256 0 74.28 0.084 ;
    END
  END i_s[242]
  PIN i_s[243]
    DIRECTION INPUT ;
    USE SIGNAL ;
    PORT
      LAYER M5 ;
        RECT  74.352 0 74.376 0.084 ;
    END
  END i_s[243]
  PIN i_s[244]
    DIRECTION INPUT ;
    USE SIGNAL ;
    PORT
      LAYER M5 ;
        RECT  74.448 0 74.472 0.084 ;
    END
  END i_s[244]
  PIN i_s[245]
    DIRECTION INPUT ;
    USE SIGNAL ;
    PORT
      LAYER M5 ;
        RECT  74.544 0 74.568 0.084 ;
    END
  END i_s[245]
  PIN i_s[246]
    DIRECTION INPUT ;
    USE SIGNAL ;
    PORT
      LAYER M5 ;
        RECT  74.64 0 74.664 0.084 ;
    END
  END i_s[246]
  PIN i_s[247]
    DIRECTION INPUT ;
    USE SIGNAL ;
    PORT
      LAYER M5 ;
        RECT  74.736 0 74.76 0.084 ;
    END
  END i_s[247]
  PIN i_s[248]
    DIRECTION INPUT ;
    USE SIGNAL ;
    PORT
      LAYER M5 ;
        RECT  74.832 0 74.856 0.084 ;
    END
  END i_s[248]
  PIN i_s[249]
    DIRECTION INPUT ;
    USE SIGNAL ;
    PORT
      LAYER M5 ;
        RECT  74.928 0 74.952 0.084 ;
    END
  END i_s[249]
  PIN i_s[24]
    DIRECTION INPUT ;
    USE SIGNAL ;
    PORT
      LAYER M5 ;
        RECT  68.688 0 68.712 0.084 ;
    END
  END i_s[24]
  PIN i_s[250]
    DIRECTION INPUT ;
    USE SIGNAL ;
    PORT
      LAYER M5 ;
        RECT  75.024 0 75.048 0.084 ;
    END
  END i_s[250]
  PIN i_s[251]
    DIRECTION INPUT ;
    USE SIGNAL ;
    PORT
      LAYER M5 ;
        RECT  75.12 0 75.144 0.084 ;
    END
  END i_s[251]
  PIN i_s[252]
    DIRECTION INPUT ;
    USE SIGNAL ;
    PORT
      LAYER M5 ;
        RECT  75.216 0 75.24 0.084 ;
    END
  END i_s[252]
  PIN i_s[253]
    DIRECTION INPUT ;
    USE SIGNAL ;
    PORT
      LAYER M5 ;
        RECT  75.312 0 75.336 0.084 ;
    END
  END i_s[253]
  PIN i_s[254]
    DIRECTION INPUT ;
    USE SIGNAL ;
    PORT
      LAYER M5 ;
        RECT  75.408 0 75.432 0.084 ;
    END
  END i_s[254]
  PIN i_s[255]
    DIRECTION INPUT ;
    USE SIGNAL ;
    PORT
      LAYER M5 ;
        RECT  75.504 0 75.528 0.084 ;
    END
  END i_s[255]
  PIN i_s[256]
    DIRECTION INPUT ;
    USE SIGNAL ;
    PORT
      LAYER M5 ;
        RECT  75.6 0 75.624 0.084 ;
    END
  END i_s[256]
  PIN i_s[257]
    DIRECTION INPUT ;
    USE SIGNAL ;
    PORT
      LAYER M5 ;
        RECT  75.696 0 75.72 0.084 ;
    END
  END i_s[257]
  PIN i_s[258]
    DIRECTION INPUT ;
    USE SIGNAL ;
    PORT
      LAYER M5 ;
        RECT  75.792 0 75.816 0.084 ;
    END
  END i_s[258]
  PIN i_s[259]
    DIRECTION INPUT ;
    USE SIGNAL ;
    PORT
      LAYER M5 ;
        RECT  75.888 0 75.912 0.084 ;
    END
  END i_s[259]
  PIN i_s[25]
    DIRECTION INPUT ;
    USE SIGNAL ;
    PORT
      LAYER M5 ;
        RECT  68.784 0 68.808 0.084 ;
    END
  END i_s[25]
  PIN i_s[260]
    DIRECTION INPUT ;
    USE SIGNAL ;
    PORT
      LAYER M5 ;
        RECT  75.984 0 76.008 0.084 ;
    END
  END i_s[260]
  PIN i_s[261]
    DIRECTION INPUT ;
    USE SIGNAL ;
    PORT
      LAYER M5 ;
        RECT  76.08 0 76.104 0.084 ;
    END
  END i_s[261]
  PIN i_s[262]
    DIRECTION INPUT ;
    USE SIGNAL ;
    PORT
      LAYER M5 ;
        RECT  76.176 0 76.2 0.084 ;
    END
  END i_s[262]
  PIN i_s[263]
    DIRECTION INPUT ;
    USE SIGNAL ;
    PORT
      LAYER M5 ;
        RECT  76.272 0 76.296 0.084 ;
    END
  END i_s[263]
  PIN i_s[264]
    DIRECTION INPUT ;
    USE SIGNAL ;
    PORT
      LAYER M5 ;
        RECT  76.368 0 76.392 0.084 ;
    END
  END i_s[264]
  PIN i_s[265]
    DIRECTION INPUT ;
    USE SIGNAL ;
    PORT
      LAYER M5 ;
        RECT  76.464 0 76.488 0.084 ;
    END
  END i_s[265]
  PIN i_s[266]
    DIRECTION INPUT ;
    USE SIGNAL ;
    PORT
      LAYER M5 ;
        RECT  76.56 0 76.584 0.084 ;
    END
  END i_s[266]
  PIN i_s[267]
    DIRECTION INPUT ;
    USE SIGNAL ;
    PORT
      LAYER M5 ;
        RECT  76.656 0 76.68 0.084 ;
    END
  END i_s[267]
  PIN i_s[268]
    DIRECTION INPUT ;
    USE SIGNAL ;
    PORT
      LAYER M5 ;
        RECT  76.752 0 76.776 0.084 ;
    END
  END i_s[268]
  PIN i_s[269]
    DIRECTION INPUT ;
    USE SIGNAL ;
    PORT
      LAYER M5 ;
        RECT  76.848 0 76.872 0.084 ;
    END
  END i_s[269]
  PIN i_s[26]
    DIRECTION INPUT ;
    USE SIGNAL ;
    PORT
      LAYER M5 ;
        RECT  68.88 0 68.904 0.084 ;
    END
  END i_s[26]
  PIN i_s[270]
    DIRECTION INPUT ;
    USE SIGNAL ;
    PORT
      LAYER M5 ;
        RECT  76.944 0 76.968 0.084 ;
    END
  END i_s[270]
  PIN i_s[271]
    DIRECTION INPUT ;
    USE SIGNAL ;
    PORT
      LAYER M5 ;
        RECT  77.04 0 77.064 0.084 ;
    END
  END i_s[271]
  PIN i_s[272]
    DIRECTION INPUT ;
    USE SIGNAL ;
    PORT
      LAYER M5 ;
        RECT  77.136 0 77.16 0.084 ;
    END
  END i_s[272]
  PIN i_s[273]
    DIRECTION INPUT ;
    USE SIGNAL ;
    PORT
      LAYER M5 ;
        RECT  77.232 0 77.256 0.084 ;
    END
  END i_s[273]
  PIN i_s[274]
    DIRECTION INPUT ;
    USE SIGNAL ;
    PORT
      LAYER M5 ;
        RECT  77.328 0 77.352 0.084 ;
    END
  END i_s[274]
  PIN i_s[275]
    DIRECTION INPUT ;
    USE SIGNAL ;
    PORT
      LAYER M5 ;
        RECT  77.424 0 77.448 0.084 ;
    END
  END i_s[275]
  PIN i_s[27]
    DIRECTION INPUT ;
    USE SIGNAL ;
    PORT
      LAYER M5 ;
        RECT  68.976 0 69 0.084 ;
    END
  END i_s[27]
  PIN i_s[28]
    DIRECTION INPUT ;
    USE SIGNAL ;
    PORT
      LAYER M5 ;
        RECT  69.072 0 69.096 0.084 ;
    END
  END i_s[28]
  PIN i_s[29]
    DIRECTION INPUT ;
    USE SIGNAL ;
    PORT
      LAYER M5 ;
        RECT  69.168 0 69.192 0.084 ;
    END
  END i_s[29]
  PIN i_s[2]
    DIRECTION INPUT ;
    USE SIGNAL ;
    PORT
      LAYER M5 ;
        RECT  63.504 0 63.528 0.084 ;
    END
  END i_s[2]
  PIN i_s[30]
    DIRECTION INPUT ;
    USE SIGNAL ;
    PORT
      LAYER M5 ;
        RECT  69.264 0 69.288 0.084 ;
    END
  END i_s[30]
  PIN i_s[31]
    DIRECTION INPUT ;
    USE SIGNAL ;
    PORT
      LAYER M5 ;
        RECT  69.36 0 69.384 0.084 ;
    END
  END i_s[31]
  PIN i_s[32]
    DIRECTION INPUT ;
    USE SIGNAL ;
    PORT
      LAYER M5 ;
        RECT  69.456 0 69.48 0.084 ;
    END
  END i_s[32]
  PIN i_s[33]
    DIRECTION INPUT ;
    USE SIGNAL ;
    PORT
      LAYER M5 ;
        RECT  69.552 0 69.576 0.084 ;
    END
  END i_s[33]
  PIN i_s[34]
    DIRECTION INPUT ;
    USE SIGNAL ;
    PORT
      LAYER M5 ;
        RECT  69.648 0 69.672 0.084 ;
    END
  END i_s[34]
  PIN i_s[35]
    DIRECTION INPUT ;
    USE SIGNAL ;
    PORT
      LAYER M5 ;
        RECT  69.744 0 69.768 0.084 ;
    END
  END i_s[35]
  PIN i_s[36]
    DIRECTION INPUT ;
    USE SIGNAL ;
    PORT
      LAYER M5 ;
        RECT  69.84 0 69.864 0.084 ;
    END
  END i_s[36]
  PIN i_s[37]
    DIRECTION INPUT ;
    USE SIGNAL ;
    PORT
      LAYER M5 ;
        RECT  69.936 0 69.96 0.084 ;
    END
  END i_s[37]
  PIN i_s[38]
    DIRECTION INPUT ;
    USE SIGNAL ;
    PORT
      LAYER M5 ;
        RECT  70.032 0 70.056 0.084 ;
    END
  END i_s[38]
  PIN i_s[39]
    DIRECTION INPUT ;
    USE SIGNAL ;
    PORT
      LAYER M5 ;
        RECT  70.128 0 70.152 0.084 ;
    END
  END i_s[39]
  PIN i_s[3]
    DIRECTION INPUT ;
    USE SIGNAL ;
    PORT
      LAYER M5 ;
        RECT  63.6 0 63.624 0.084 ;
    END
  END i_s[3]
  PIN i_s[40]
    DIRECTION INPUT ;
    USE SIGNAL ;
    PORT
      LAYER M5 ;
        RECT  70.224 0 70.248 0.084 ;
    END
  END i_s[40]
  PIN i_s[41]
    DIRECTION INPUT ;
    USE SIGNAL ;
    PORT
      LAYER M5 ;
        RECT  70.32 0 70.344 0.084 ;
    END
  END i_s[41]
  PIN i_s[42]
    DIRECTION INPUT ;
    USE SIGNAL ;
    PORT
      LAYER M5 ;
        RECT  70.416 0 70.44 0.084 ;
    END
  END i_s[42]
  PIN i_s[43]
    DIRECTION INPUT ;
    USE SIGNAL ;
    PORT
      LAYER M5 ;
        RECT  70.512 0 70.536 0.084 ;
    END
  END i_s[43]
  PIN i_s[44]
    DIRECTION INPUT ;
    USE SIGNAL ;
    PORT
      LAYER M5 ;
        RECT  105.936 0 105.96 0.084 ;
    END
  END i_s[44]
  PIN i_s[45]
    DIRECTION INPUT ;
    USE SIGNAL ;
    PORT
      LAYER M5 ;
        RECT  106.032 0 106.056 0.084 ;
    END
  END i_s[45]
  PIN i_s[46]
    DIRECTION INPUT ;
    USE SIGNAL ;
    PORT
      LAYER M5 ;
        RECT  106.128 0 106.152 0.084 ;
    END
  END i_s[46]
  PIN i_s[47]
    DIRECTION INPUT ;
    USE SIGNAL ;
    PORT
      LAYER M5 ;
        RECT  106.224 0 106.248 0.084 ;
    END
  END i_s[47]
  PIN i_s[48]
    DIRECTION INPUT ;
    USE SIGNAL ;
    PORT
      LAYER M5 ;
        RECT  106.32 0 106.344 0.084 ;
    END
  END i_s[48]
  PIN i_s[49]
    DIRECTION INPUT ;
    USE SIGNAL ;
    PORT
      LAYER M5 ;
        RECT  106.416 0 106.44 0.084 ;
    END
  END i_s[49]
  PIN i_s[4]
    DIRECTION INPUT ;
    USE SIGNAL ;
    PORT
      LAYER M5 ;
        RECT  63.696 0 63.72 0.084 ;
    END
  END i_s[4]
  PIN i_s[50]
    DIRECTION INPUT ;
    USE SIGNAL ;
    PORT
      LAYER M5 ;
        RECT  106.512 0 106.536 0.084 ;
    END
  END i_s[50]
  PIN i_s[51]
    DIRECTION INPUT ;
    USE SIGNAL ;
    PORT
      LAYER M5 ;
        RECT  106.608 0 106.632 0.084 ;
    END
  END i_s[51]
  PIN i_s[52]
    DIRECTION INPUT ;
    USE SIGNAL ;
    PORT
      LAYER M5 ;
        RECT  106.704 0 106.728 0.084 ;
    END
  END i_s[52]
  PIN i_s[53]
    DIRECTION INPUT ;
    USE SIGNAL ;
    PORT
      LAYER M5 ;
        RECT  106.8 0 106.824 0.084 ;
    END
  END i_s[53]
  PIN i_s[54]
    DIRECTION INPUT ;
    USE SIGNAL ;
    PORT
      LAYER M5 ;
        RECT  106.896 0 106.92 0.084 ;
    END
  END i_s[54]
  PIN i_s[55]
    DIRECTION INPUT ;
    USE SIGNAL ;
    PORT
      LAYER M5 ;
        RECT  106.992 0 107.016 0.084 ;
    END
  END i_s[55]
  PIN i_s[56]
    DIRECTION INPUT ;
    USE SIGNAL ;
    PORT
      LAYER M5 ;
        RECT  107.088 0 107.112 0.084 ;
    END
  END i_s[56]
  PIN i_s[57]
    DIRECTION INPUT ;
    USE SIGNAL ;
    PORT
      LAYER M5 ;
        RECT  107.184 0 107.208 0.084 ;
    END
  END i_s[57]
  PIN i_s[58]
    DIRECTION INPUT ;
    USE SIGNAL ;
    PORT
      LAYER M5 ;
        RECT  107.28 0 107.304 0.084 ;
    END
  END i_s[58]
  PIN i_s[59]
    DIRECTION INPUT ;
    USE SIGNAL ;
    PORT
      LAYER M5 ;
        RECT  107.376 0 107.4 0.084 ;
    END
  END i_s[59]
  PIN i_s[5]
    DIRECTION INPUT ;
    USE SIGNAL ;
    PORT
      LAYER M5 ;
        RECT  63.792 0 63.816 0.084 ;
    END
  END i_s[5]
  PIN i_s[60]
    DIRECTION INPUT ;
    USE SIGNAL ;
    PORT
      LAYER M5 ;
        RECT  107.472 0 107.496 0.084 ;
    END
  END i_s[60]
  PIN i_s[61]
    DIRECTION INPUT ;
    USE SIGNAL ;
    PORT
      LAYER M5 ;
        RECT  107.568 0 107.592 0.084 ;
    END
  END i_s[61]
  PIN i_s[62]
    DIRECTION INPUT ;
    USE SIGNAL ;
    PORT
      LAYER M5 ;
        RECT  107.664 0 107.688 0.084 ;
    END
  END i_s[62]
  PIN i_s[63]
    DIRECTION INPUT ;
    USE SIGNAL ;
    PORT
      LAYER M5 ;
        RECT  107.76 0 107.784 0.084 ;
    END
  END i_s[63]
  PIN i_s[64]
    DIRECTION INPUT ;
    USE SIGNAL ;
    PORT
      LAYER M5 ;
        RECT  107.856 0 107.88 0.084 ;
    END
  END i_s[64]
  PIN i_s[65]
    DIRECTION INPUT ;
    USE SIGNAL ;
    PORT
      LAYER M5 ;
        RECT  107.952 0 107.976 0.084 ;
    END
  END i_s[65]
  PIN i_s[66]
    DIRECTION INPUT ;
    USE SIGNAL ;
    PORT
      LAYER M5 ;
        RECT  108.048 0 108.072 0.084 ;
    END
  END i_s[66]
  PIN i_s[67]
    DIRECTION INPUT ;
    USE SIGNAL ;
    PORT
      LAYER M5 ;
        RECT  108.144 0 108.168 0.084 ;
    END
  END i_s[67]
  PIN i_s[68]
    DIRECTION INPUT ;
    USE SIGNAL ;
    PORT
      LAYER M5 ;
        RECT  108.24 0 108.264 0.084 ;
    END
  END i_s[68]
  PIN i_s[69]
    DIRECTION INPUT ;
    USE SIGNAL ;
    PORT
      LAYER M5 ;
        RECT  108.336 0 108.36 0.084 ;
    END
  END i_s[69]
  PIN i_s[6]
    DIRECTION INPUT ;
    USE SIGNAL ;
    PORT
      LAYER M5 ;
        RECT  63.888 0 63.912 0.084 ;
    END
  END i_s[6]
  PIN i_s[70]
    DIRECTION INPUT ;
    USE SIGNAL ;
    PORT
      LAYER M5 ;
        RECT  108.432 0 108.456 0.084 ;
    END
  END i_s[70]
  PIN i_s[71]
    DIRECTION INPUT ;
    USE SIGNAL ;
    PORT
      LAYER M5 ;
        RECT  108.528 0 108.552 0.084 ;
    END
  END i_s[71]
  PIN i_s[72]
    DIRECTION INPUT ;
    USE SIGNAL ;
    PORT
      LAYER M5 ;
        RECT  108.624 0 108.648 0.084 ;
    END
  END i_s[72]
  PIN i_s[73]
    DIRECTION INPUT ;
    USE SIGNAL ;
    PORT
      LAYER M5 ;
        RECT  108.72 0 108.744 0.084 ;
    END
  END i_s[73]
  PIN i_s[74]
    DIRECTION INPUT ;
    USE SIGNAL ;
    PORT
      LAYER M5 ;
        RECT  108.816 0 108.84 0.084 ;
    END
  END i_s[74]
  PIN i_s[75]
    DIRECTION INPUT ;
    USE SIGNAL ;
    PORT
      LAYER M5 ;
        RECT  108.912 0 108.936 0.084 ;
    END
  END i_s[75]
  PIN i_s[76]
    DIRECTION INPUT ;
    USE SIGNAL ;
    PORT
      LAYER M5 ;
        RECT  96.72 0 96.744 0.084 ;
    END
  END i_s[76]
  PIN i_s[77]
    DIRECTION INPUT ;
    USE SIGNAL ;
    PORT
      LAYER M5 ;
        RECT  96.816 0 96.84 0.084 ;
    END
  END i_s[77]
  PIN i_s[78]
    DIRECTION INPUT ;
    USE SIGNAL ;
    PORT
      LAYER M5 ;
        RECT  96.912 0 96.936 0.084 ;
    END
  END i_s[78]
  PIN i_s[79]
    DIRECTION INPUT ;
    USE SIGNAL ;
    PORT
      LAYER M5 ;
        RECT  97.008 0 97.032 0.084 ;
    END
  END i_s[79]
  PIN i_s[7]
    DIRECTION INPUT ;
    USE SIGNAL ;
    PORT
      LAYER M5 ;
        RECT  63.984 0 64.008 0.084 ;
    END
  END i_s[7]
  PIN i_s[80]
    DIRECTION INPUT ;
    USE SIGNAL ;
    PORT
      LAYER M5 ;
        RECT  97.104 0 97.128 0.084 ;
    END
  END i_s[80]
  PIN i_s[81]
    DIRECTION INPUT ;
    USE SIGNAL ;
    PORT
      LAYER M5 ;
        RECT  97.2 0 97.224 0.084 ;
    END
  END i_s[81]
  PIN i_s[82]
    DIRECTION INPUT ;
    USE SIGNAL ;
    PORT
      LAYER M5 ;
        RECT  97.296 0 97.32 0.084 ;
    END
  END i_s[82]
  PIN i_s[83]
    DIRECTION INPUT ;
    USE SIGNAL ;
    PORT
      LAYER M5 ;
        RECT  97.392 0 97.416 0.084 ;
    END
  END i_s[83]
  PIN i_s[84]
    DIRECTION INPUT ;
    USE SIGNAL ;
    PORT
      LAYER M5 ;
        RECT  97.488 0 97.512 0.084 ;
    END
  END i_s[84]
  PIN i_s[85]
    DIRECTION INPUT ;
    USE SIGNAL ;
    PORT
      LAYER M5 ;
        RECT  97.584 0 97.608 0.084 ;
    END
  END i_s[85]
  PIN i_s[86]
    DIRECTION INPUT ;
    USE SIGNAL ;
    PORT
      LAYER M5 ;
        RECT  97.68 0 97.704 0.084 ;
    END
  END i_s[86]
  PIN i_s[87]
    DIRECTION INPUT ;
    USE SIGNAL ;
    PORT
      LAYER M5 ;
        RECT  97.776 0 97.8 0.084 ;
    END
  END i_s[87]
  PIN i_s[88]
    DIRECTION INPUT ;
    USE SIGNAL ;
    PORT
      LAYER M5 ;
        RECT  97.872 0 97.896 0.084 ;
    END
  END i_s[88]
  PIN i_s[89]
    DIRECTION INPUT ;
    USE SIGNAL ;
    PORT
      LAYER M5 ;
        RECT  97.968 0 97.992 0.084 ;
    END
  END i_s[89]
  PIN i_s[8]
    DIRECTION INPUT ;
    USE SIGNAL ;
    PORT
      LAYER M5 ;
        RECT  64.08 0 64.104 0.084 ;
    END
  END i_s[8]
  PIN i_s[90]
    DIRECTION INPUT ;
    USE SIGNAL ;
    PORT
      LAYER M5 ;
        RECT  98.064 0 98.088 0.084 ;
    END
  END i_s[90]
  PIN i_s[91]
    DIRECTION INPUT ;
    USE SIGNAL ;
    PORT
      LAYER M5 ;
        RECT  98.16 0 98.184 0.084 ;
    END
  END i_s[91]
  PIN i_s[92]
    DIRECTION INPUT ;
    USE SIGNAL ;
    PORT
      LAYER M5 ;
        RECT  98.256 0 98.28 0.084 ;
    END
  END i_s[92]
  PIN i_s[93]
    DIRECTION INPUT ;
    USE SIGNAL ;
    PORT
      LAYER M5 ;
        RECT  98.352 0 98.376 0.084 ;
    END
  END i_s[93]
  PIN i_s[94]
    DIRECTION INPUT ;
    USE SIGNAL ;
    PORT
      LAYER M5 ;
        RECT  98.448 0 98.472 0.084 ;
    END
  END i_s[94]
  PIN i_s[95]
    DIRECTION INPUT ;
    USE SIGNAL ;
    PORT
      LAYER M5 ;
        RECT  98.544 0 98.568 0.084 ;
    END
  END i_s[95]
  PIN i_s[96]
    DIRECTION INPUT ;
    USE SIGNAL ;
    PORT
      LAYER M5 ;
        RECT  98.64 0 98.664 0.084 ;
    END
  END i_s[96]
  PIN i_s[97]
    DIRECTION INPUT ;
    USE SIGNAL ;
    PORT
      LAYER M5 ;
        RECT  98.736 0 98.76 0.084 ;
    END
  END i_s[97]
  PIN i_s[98]
    DIRECTION INPUT ;
    USE SIGNAL ;
    PORT
      LAYER M5 ;
        RECT  98.832 0 98.856 0.084 ;
    END
  END i_s[98]
  PIN i_s[99]
    DIRECTION INPUT ;
    USE SIGNAL ;
    PORT
      LAYER M5 ;
        RECT  98.928 0 98.952 0.084 ;
    END
  END i_s[99]
  PIN i_s[9]
    DIRECTION INPUT ;
    USE SIGNAL ;
    PORT
      LAYER M5 ;
        RECT  64.176 0 64.2 0.084 ;
    END
  END i_s[9]
  PIN o[0]
    DIRECTION OUTPUT ;
    USE SIGNAL ;
    PORT
      LAYER M4 ;
        RECT  172.716 86.832 172.8 86.856 ;
    END
  END o[0]
  PIN o[100]
    DIRECTION OUTPUT ;
    USE SIGNAL ;
    PORT
      LAYER M4 ;
        RECT  172.716 78 172.8 78.024 ;
    END
  END o[100]
  PIN o[101]
    DIRECTION OUTPUT ;
    USE SIGNAL ;
    PORT
      LAYER M4 ;
        RECT  172.716 78.096 172.8 78.12 ;
    END
  END o[101]
  PIN o[102]
    DIRECTION OUTPUT ;
    USE SIGNAL ;
    PORT
      LAYER M4 ;
        RECT  172.716 78.192 172.8 78.216 ;
    END
  END o[102]
  PIN o[103]
    DIRECTION OUTPUT ;
    USE SIGNAL ;
    PORT
      LAYER M4 ;
        RECT  172.716 78.288 172.8 78.312 ;
    END
  END o[103]
  PIN o[104]
    DIRECTION OUTPUT ;
    USE SIGNAL ;
    PORT
      LAYER M4 ;
        RECT  172.716 78.384 172.8 78.408 ;
    END
  END o[104]
  PIN o[105]
    DIRECTION OUTPUT ;
    USE SIGNAL ;
    PORT
      LAYER M4 ;
        RECT  172.716 78.48 172.8 78.504 ;
    END
  END o[105]
  PIN o[106]
    DIRECTION OUTPUT ;
    USE SIGNAL ;
    PORT
      LAYER M4 ;
        RECT  172.716 78.576 172.8 78.6 ;
    END
  END o[106]
  PIN o[107]
    DIRECTION OUTPUT ;
    USE SIGNAL ;
    PORT
      LAYER M4 ;
        RECT  172.716 78.672 172.8 78.696 ;
    END
  END o[107]
  PIN o[108]
    DIRECTION OUTPUT ;
    USE SIGNAL ;
    PORT
      LAYER M4 ;
        RECT  172.716 78.768 172.8 78.792 ;
    END
  END o[108]
  PIN o[109]
    DIRECTION OUTPUT ;
    USE SIGNAL ;
    PORT
      LAYER M4 ;
        RECT  172.716 78.864 172.8 78.888 ;
    END
  END o[109]
  PIN o[10]
    DIRECTION OUTPUT ;
    USE SIGNAL ;
    PORT
      LAYER M4 ;
        RECT  172.716 87.792 172.8 87.816 ;
    END
  END o[10]
  PIN o[110]
    DIRECTION OUTPUT ;
    USE SIGNAL ;
    PORT
      LAYER M4 ;
        RECT  172.716 78.96 172.8 78.984 ;
    END
  END o[110]
  PIN o[111]
    DIRECTION OUTPUT ;
    USE SIGNAL ;
    PORT
      LAYER M4 ;
        RECT  172.716 79.056 172.8 79.08 ;
    END
  END o[111]
  PIN o[112]
    DIRECTION OUTPUT ;
    USE SIGNAL ;
    PORT
      LAYER M4 ;
        RECT  172.716 79.152 172.8 79.176 ;
    END
  END o[112]
  PIN o[113]
    DIRECTION OUTPUT ;
    USE SIGNAL ;
    PORT
      LAYER M4 ;
        RECT  172.716 79.248 172.8 79.272 ;
    END
  END o[113]
  PIN o[114]
    DIRECTION OUTPUT ;
    USE SIGNAL ;
    PORT
      LAYER M4 ;
        RECT  172.716 79.344 172.8 79.368 ;
    END
  END o[114]
  PIN o[115]
    DIRECTION OUTPUT ;
    USE SIGNAL ;
    PORT
      LAYER M4 ;
        RECT  172.716 79.44 172.8 79.464 ;
    END
  END o[115]
  PIN o[116]
    DIRECTION OUTPUT ;
    USE SIGNAL ;
    PORT
      LAYER M4 ;
        RECT  172.716 79.536 172.8 79.56 ;
    END
  END o[116]
  PIN o[117]
    DIRECTION OUTPUT ;
    USE SIGNAL ;
    PORT
      LAYER M4 ;
        RECT  172.716 79.632 172.8 79.656 ;
    END
  END o[117]
  PIN o[118]
    DIRECTION OUTPUT ;
    USE SIGNAL ;
    PORT
      LAYER M4 ;
        RECT  172.716 79.728 172.8 79.752 ;
    END
  END o[118]
  PIN o[119]
    DIRECTION OUTPUT ;
    USE SIGNAL ;
    PORT
      LAYER M4 ;
        RECT  172.716 79.824 172.8 79.848 ;
    END
  END o[119]
  PIN o[11]
    DIRECTION OUTPUT ;
    USE SIGNAL ;
    PORT
      LAYER M4 ;
        RECT  172.716 87.888 172.8 87.912 ;
    END
  END o[11]
  PIN o[120]
    DIRECTION OUTPUT ;
    USE SIGNAL ;
    PORT
      LAYER M4 ;
        RECT  172.716 79.92 172.8 79.944 ;
    END
  END o[120]
  PIN o[121]
    DIRECTION OUTPUT ;
    USE SIGNAL ;
    PORT
      LAYER M4 ;
        RECT  172.716 80.016 172.8 80.04 ;
    END
  END o[121]
  PIN o[122]
    DIRECTION OUTPUT ;
    USE SIGNAL ;
    PORT
      LAYER M4 ;
        RECT  172.716 80.112 172.8 80.136 ;
    END
  END o[122]
  PIN o[123]
    DIRECTION OUTPUT ;
    USE SIGNAL ;
    PORT
      LAYER M4 ;
        RECT  172.716 80.208 172.8 80.232 ;
    END
  END o[123]
  PIN o[124]
    DIRECTION OUTPUT ;
    USE SIGNAL ;
    PORT
      LAYER M4 ;
        RECT  172.716 80.304 172.8 80.328 ;
    END
  END o[124]
  PIN o[125]
    DIRECTION OUTPUT ;
    USE SIGNAL ;
    PORT
      LAYER M4 ;
        RECT  172.716 80.4 172.8 80.424 ;
    END
  END o[125]
  PIN o[126]
    DIRECTION OUTPUT ;
    USE SIGNAL ;
    PORT
      LAYER M4 ;
        RECT  172.716 80.496 172.8 80.52 ;
    END
  END o[126]
  PIN o[127]
    DIRECTION OUTPUT ;
    USE SIGNAL ;
    PORT
      LAYER M4 ;
        RECT  172.716 92.88 172.8 92.904 ;
    END
  END o[127]
  PIN o[128]
    DIRECTION OUTPUT ;
    USE SIGNAL ;
    PORT
      LAYER M4 ;
        RECT  172.716 92.976 172.8 93 ;
    END
  END o[128]
  PIN o[129]
    DIRECTION OUTPUT ;
    USE SIGNAL ;
    PORT
      LAYER M4 ;
        RECT  172.716 93.072 172.8 93.096 ;
    END
  END o[129]
  PIN o[12]
    DIRECTION OUTPUT ;
    USE SIGNAL ;
    PORT
      LAYER M4 ;
        RECT  172.716 87.984 172.8 88.008 ;
    END
  END o[12]
  PIN o[130]
    DIRECTION OUTPUT ;
    USE SIGNAL ;
    PORT
      LAYER M4 ;
        RECT  172.716 93.168 172.8 93.192 ;
    END
  END o[130]
  PIN o[131]
    DIRECTION OUTPUT ;
    USE SIGNAL ;
    PORT
      LAYER M4 ;
        RECT  172.716 93.264 172.8 93.288 ;
    END
  END o[131]
  PIN o[132]
    DIRECTION OUTPUT ;
    USE SIGNAL ;
    PORT
      LAYER M4 ;
        RECT  172.716 93.36 172.8 93.384 ;
    END
  END o[132]
  PIN o[133]
    DIRECTION OUTPUT ;
    USE SIGNAL ;
    PORT
      LAYER M4 ;
        RECT  172.716 93.456 172.8 93.48 ;
    END
  END o[133]
  PIN o[134]
    DIRECTION OUTPUT ;
    USE SIGNAL ;
    PORT
      LAYER M4 ;
        RECT  172.716 93.552 172.8 93.576 ;
    END
  END o[134]
  PIN o[135]
    DIRECTION OUTPUT ;
    USE SIGNAL ;
    PORT
      LAYER M4 ;
        RECT  172.716 93.648 172.8 93.672 ;
    END
  END o[135]
  PIN o[136]
    DIRECTION OUTPUT ;
    USE SIGNAL ;
    PORT
      LAYER M4 ;
        RECT  172.716 93.744 172.8 93.768 ;
    END
  END o[136]
  PIN o[137]
    DIRECTION OUTPUT ;
    USE SIGNAL ;
    PORT
      LAYER M4 ;
        RECT  172.716 93.84 172.8 93.864 ;
    END
  END o[137]
  PIN o[138]
    DIRECTION OUTPUT ;
    USE SIGNAL ;
    PORT
      LAYER M4 ;
        RECT  172.716 93.936 172.8 93.96 ;
    END
  END o[138]
  PIN o[139]
    DIRECTION OUTPUT ;
    USE SIGNAL ;
    PORT
      LAYER M4 ;
        RECT  172.716 94.032 172.8 94.056 ;
    END
  END o[139]
  PIN o[13]
    DIRECTION OUTPUT ;
    USE SIGNAL ;
    PORT
      LAYER M4 ;
        RECT  172.716 88.08 172.8 88.104 ;
    END
  END o[13]
  PIN o[140]
    DIRECTION OUTPUT ;
    USE SIGNAL ;
    PORT
      LAYER M4 ;
        RECT  172.716 94.128 172.8 94.152 ;
    END
  END o[140]
  PIN o[141]
    DIRECTION OUTPUT ;
    USE SIGNAL ;
    PORT
      LAYER M4 ;
        RECT  172.716 94.224 172.8 94.248 ;
    END
  END o[141]
  PIN o[142]
    DIRECTION OUTPUT ;
    USE SIGNAL ;
    PORT
      LAYER M4 ;
        RECT  172.716 94.32 172.8 94.344 ;
    END
  END o[142]
  PIN o[143]
    DIRECTION OUTPUT ;
    USE SIGNAL ;
    PORT
      LAYER M4 ;
        RECT  172.716 94.416 172.8 94.44 ;
    END
  END o[143]
  PIN o[144]
    DIRECTION OUTPUT ;
    USE SIGNAL ;
    PORT
      LAYER M4 ;
        RECT  172.716 94.512 172.8 94.536 ;
    END
  END o[144]
  PIN o[145]
    DIRECTION OUTPUT ;
    USE SIGNAL ;
    PORT
      LAYER M4 ;
        RECT  172.716 94.608 172.8 94.632 ;
    END
  END o[145]
  PIN o[146]
    DIRECTION OUTPUT ;
    USE SIGNAL ;
    PORT
      LAYER M4 ;
        RECT  172.716 94.704 172.8 94.728 ;
    END
  END o[146]
  PIN o[147]
    DIRECTION OUTPUT ;
    USE SIGNAL ;
    PORT
      LAYER M4 ;
        RECT  172.716 94.8 172.8 94.824 ;
    END
  END o[147]
  PIN o[148]
    DIRECTION OUTPUT ;
    USE SIGNAL ;
    PORT
      LAYER M4 ;
        RECT  172.716 94.896 172.8 94.92 ;
    END
  END o[148]
  PIN o[149]
    DIRECTION OUTPUT ;
    USE SIGNAL ;
    PORT
      LAYER M4 ;
        RECT  172.716 94.992 172.8 95.016 ;
    END
  END o[149]
  PIN o[14]
    DIRECTION OUTPUT ;
    USE SIGNAL ;
    PORT
      LAYER M4 ;
        RECT  172.716 88.176 172.8 88.2 ;
    END
  END o[14]
  PIN o[150]
    DIRECTION OUTPUT ;
    USE SIGNAL ;
    PORT
      LAYER M4 ;
        RECT  172.716 95.088 172.8 95.112 ;
    END
  END o[150]
  PIN o[151]
    DIRECTION OUTPUT ;
    USE SIGNAL ;
    PORT
      LAYER M4 ;
        RECT  172.716 95.184 172.8 95.208 ;
    END
  END o[151]
  PIN o[152]
    DIRECTION OUTPUT ;
    USE SIGNAL ;
    PORT
      LAYER M4 ;
        RECT  172.716 95.28 172.8 95.304 ;
    END
  END o[152]
  PIN o[153]
    DIRECTION OUTPUT ;
    USE SIGNAL ;
    PORT
      LAYER M4 ;
        RECT  172.716 95.376 172.8 95.4 ;
    END
  END o[153]
  PIN o[154]
    DIRECTION OUTPUT ;
    USE SIGNAL ;
    PORT
      LAYER M4 ;
        RECT  172.716 95.472 172.8 95.496 ;
    END
  END o[154]
  PIN o[155]
    DIRECTION OUTPUT ;
    USE SIGNAL ;
    PORT
      LAYER M4 ;
        RECT  172.716 95.568 172.8 95.592 ;
    END
  END o[155]
  PIN o[156]
    DIRECTION OUTPUT ;
    USE SIGNAL ;
    PORT
      LAYER M4 ;
        RECT  172.716 95.664 172.8 95.688 ;
    END
  END o[156]
  PIN o[157]
    DIRECTION OUTPUT ;
    USE SIGNAL ;
    PORT
      LAYER M4 ;
        RECT  172.716 95.76 172.8 95.784 ;
    END
  END o[157]
  PIN o[158]
    DIRECTION OUTPUT ;
    USE SIGNAL ;
    PORT
      LAYER M4 ;
        RECT  172.716 95.856 172.8 95.88 ;
    END
  END o[158]
  PIN o[159]
    DIRECTION OUTPUT ;
    USE SIGNAL ;
    PORT
      LAYER M4 ;
        RECT  172.716 80.592 172.8 80.616 ;
    END
  END o[159]
  PIN o[15]
    DIRECTION OUTPUT ;
    USE SIGNAL ;
    PORT
      LAYER M4 ;
        RECT  172.716 88.272 172.8 88.296 ;
    END
  END o[15]
  PIN o[160]
    DIRECTION OUTPUT ;
    USE SIGNAL ;
    PORT
      LAYER M4 ;
        RECT  172.716 80.688 172.8 80.712 ;
    END
  END o[160]
  PIN o[161]
    DIRECTION OUTPUT ;
    USE SIGNAL ;
    PORT
      LAYER M4 ;
        RECT  172.716 80.784 172.8 80.808 ;
    END
  END o[161]
  PIN o[162]
    DIRECTION OUTPUT ;
    USE SIGNAL ;
    PORT
      LAYER M4 ;
        RECT  172.716 80.88 172.8 80.904 ;
    END
  END o[162]
  PIN o[163]
    DIRECTION OUTPUT ;
    USE SIGNAL ;
    PORT
      LAYER M4 ;
        RECT  172.716 80.976 172.8 81 ;
    END
  END o[163]
  PIN o[164]
    DIRECTION OUTPUT ;
    USE SIGNAL ;
    PORT
      LAYER M4 ;
        RECT  172.716 81.072 172.8 81.096 ;
    END
  END o[164]
  PIN o[165]
    DIRECTION OUTPUT ;
    USE SIGNAL ;
    PORT
      LAYER M4 ;
        RECT  172.716 81.168 172.8 81.192 ;
    END
  END o[165]
  PIN o[166]
    DIRECTION OUTPUT ;
    USE SIGNAL ;
    PORT
      LAYER M4 ;
        RECT  172.716 81.264 172.8 81.288 ;
    END
  END o[166]
  PIN o[167]
    DIRECTION OUTPUT ;
    USE SIGNAL ;
    PORT
      LAYER M4 ;
        RECT  172.716 81.36 172.8 81.384 ;
    END
  END o[167]
  PIN o[168]
    DIRECTION OUTPUT ;
    USE SIGNAL ;
    PORT
      LAYER M4 ;
        RECT  172.716 81.456 172.8 81.48 ;
    END
  END o[168]
  PIN o[169]
    DIRECTION OUTPUT ;
    USE SIGNAL ;
    PORT
      LAYER M4 ;
        RECT  172.716 81.552 172.8 81.576 ;
    END
  END o[169]
  PIN o[16]
    DIRECTION OUTPUT ;
    USE SIGNAL ;
    PORT
      LAYER M4 ;
        RECT  172.716 88.368 172.8 88.392 ;
    END
  END o[16]
  PIN o[170]
    DIRECTION OUTPUT ;
    USE SIGNAL ;
    PORT
      LAYER M4 ;
        RECT  172.716 81.648 172.8 81.672 ;
    END
  END o[170]
  PIN o[171]
    DIRECTION OUTPUT ;
    USE SIGNAL ;
    PORT
      LAYER M4 ;
        RECT  172.716 81.744 172.8 81.768 ;
    END
  END o[171]
  PIN o[172]
    DIRECTION OUTPUT ;
    USE SIGNAL ;
    PORT
      LAYER M4 ;
        RECT  172.716 81.84 172.8 81.864 ;
    END
  END o[172]
  PIN o[173]
    DIRECTION OUTPUT ;
    USE SIGNAL ;
    PORT
      LAYER M4 ;
        RECT  172.716 81.936 172.8 81.96 ;
    END
  END o[173]
  PIN o[174]
    DIRECTION OUTPUT ;
    USE SIGNAL ;
    PORT
      LAYER M4 ;
        RECT  172.716 82.032 172.8 82.056 ;
    END
  END o[174]
  PIN o[175]
    DIRECTION OUTPUT ;
    USE SIGNAL ;
    PORT
      LAYER M4 ;
        RECT  172.716 82.128 172.8 82.152 ;
    END
  END o[175]
  PIN o[176]
    DIRECTION OUTPUT ;
    USE SIGNAL ;
    PORT
      LAYER M4 ;
        RECT  172.716 82.224 172.8 82.248 ;
    END
  END o[176]
  PIN o[177]
    DIRECTION OUTPUT ;
    USE SIGNAL ;
    PORT
      LAYER M4 ;
        RECT  172.716 82.32 172.8 82.344 ;
    END
  END o[177]
  PIN o[178]
    DIRECTION OUTPUT ;
    USE SIGNAL ;
    PORT
      LAYER M4 ;
        RECT  172.716 82.416 172.8 82.44 ;
    END
  END o[178]
  PIN o[179]
    DIRECTION OUTPUT ;
    USE SIGNAL ;
    PORT
      LAYER M4 ;
        RECT  172.716 82.512 172.8 82.536 ;
    END
  END o[179]
  PIN o[17]
    DIRECTION OUTPUT ;
    USE SIGNAL ;
    PORT
      LAYER M4 ;
        RECT  172.716 88.464 172.8 88.488 ;
    END
  END o[17]
  PIN o[180]
    DIRECTION OUTPUT ;
    USE SIGNAL ;
    PORT
      LAYER M4 ;
        RECT  172.716 82.608 172.8 82.632 ;
    END
  END o[180]
  PIN o[181]
    DIRECTION OUTPUT ;
    USE SIGNAL ;
    PORT
      LAYER M4 ;
        RECT  172.716 82.704 172.8 82.728 ;
    END
  END o[181]
  PIN o[182]
    DIRECTION OUTPUT ;
    USE SIGNAL ;
    PORT
      LAYER M4 ;
        RECT  172.716 82.8 172.8 82.824 ;
    END
  END o[182]
  PIN o[183]
    DIRECTION OUTPUT ;
    USE SIGNAL ;
    PORT
      LAYER M4 ;
        RECT  172.716 82.896 172.8 82.92 ;
    END
  END o[183]
  PIN o[184]
    DIRECTION OUTPUT ;
    USE SIGNAL ;
    PORT
      LAYER M4 ;
        RECT  172.716 82.992 172.8 83.016 ;
    END
  END o[184]
  PIN o[185]
    DIRECTION OUTPUT ;
    USE SIGNAL ;
    PORT
      LAYER M4 ;
        RECT  172.716 83.088 172.8 83.112 ;
    END
  END o[185]
  PIN o[186]
    DIRECTION OUTPUT ;
    USE SIGNAL ;
    PORT
      LAYER M4 ;
        RECT  172.716 83.184 172.8 83.208 ;
    END
  END o[186]
  PIN o[187]
    DIRECTION OUTPUT ;
    USE SIGNAL ;
    PORT
      LAYER M4 ;
        RECT  172.716 83.28 172.8 83.304 ;
    END
  END o[187]
  PIN o[188]
    DIRECTION OUTPUT ;
    USE SIGNAL ;
    PORT
      LAYER M4 ;
        RECT  172.716 83.376 172.8 83.4 ;
    END
  END o[188]
  PIN o[189]
    DIRECTION OUTPUT ;
    USE SIGNAL ;
    PORT
      LAYER M4 ;
        RECT  172.716 83.472 172.8 83.496 ;
    END
  END o[189]
  PIN o[18]
    DIRECTION OUTPUT ;
    USE SIGNAL ;
    PORT
      LAYER M4 ;
        RECT  172.716 88.56 172.8 88.584 ;
    END
  END o[18]
  PIN o[190]
    DIRECTION OUTPUT ;
    USE SIGNAL ;
    PORT
      LAYER M4 ;
        RECT  172.716 83.568 172.8 83.592 ;
    END
  END o[190]
  PIN o[191]
    DIRECTION OUTPUT ;
    USE SIGNAL ;
    PORT
      LAYER M4 ;
        RECT  172.716 99.792 172.8 99.816 ;
    END
  END o[191]
  PIN o[192]
    DIRECTION OUTPUT ;
    USE SIGNAL ;
    PORT
      LAYER M4 ;
        RECT  172.716 99.888 172.8 99.912 ;
    END
  END o[192]
  PIN o[193]
    DIRECTION OUTPUT ;
    USE SIGNAL ;
    PORT
      LAYER M4 ;
        RECT  172.716 99.984 172.8 100.008 ;
    END
  END o[193]
  PIN o[194]
    DIRECTION OUTPUT ;
    USE SIGNAL ;
    PORT
      LAYER M4 ;
        RECT  172.716 100.08 172.8 100.104 ;
    END
  END o[194]
  PIN o[195]
    DIRECTION OUTPUT ;
    USE SIGNAL ;
    PORT
      LAYER M4 ;
        RECT  172.716 100.176 172.8 100.2 ;
    END
  END o[195]
  PIN o[196]
    DIRECTION OUTPUT ;
    USE SIGNAL ;
    PORT
      LAYER M4 ;
        RECT  172.716 100.272 172.8 100.296 ;
    END
  END o[196]
  PIN o[197]
    DIRECTION OUTPUT ;
    USE SIGNAL ;
    PORT
      LAYER M4 ;
        RECT  172.716 100.368 172.8 100.392 ;
    END
  END o[197]
  PIN o[198]
    DIRECTION OUTPUT ;
    USE SIGNAL ;
    PORT
      LAYER M4 ;
        RECT  172.716 100.464 172.8 100.488 ;
    END
  END o[198]
  PIN o[199]
    DIRECTION OUTPUT ;
    USE SIGNAL ;
    PORT
      LAYER M4 ;
        RECT  172.716 100.56 172.8 100.584 ;
    END
  END o[199]
  PIN o[19]
    DIRECTION OUTPUT ;
    USE SIGNAL ;
    PORT
      LAYER M4 ;
        RECT  172.716 88.656 172.8 88.68 ;
    END
  END o[19]
  PIN o[1]
    DIRECTION OUTPUT ;
    USE SIGNAL ;
    PORT
      LAYER M4 ;
        RECT  172.716 86.928 172.8 86.952 ;
    END
  END o[1]
  PIN o[200]
    DIRECTION OUTPUT ;
    USE SIGNAL ;
    PORT
      LAYER M4 ;
        RECT  172.716 100.656 172.8 100.68 ;
    END
  END o[200]
  PIN o[201]
    DIRECTION OUTPUT ;
    USE SIGNAL ;
    PORT
      LAYER M4 ;
        RECT  172.716 100.752 172.8 100.776 ;
    END
  END o[201]
  PIN o[202]
    DIRECTION OUTPUT ;
    USE SIGNAL ;
    PORT
      LAYER M4 ;
        RECT  172.716 100.848 172.8 100.872 ;
    END
  END o[202]
  PIN o[203]
    DIRECTION OUTPUT ;
    USE SIGNAL ;
    PORT
      LAYER M4 ;
        RECT  172.716 100.944 172.8 100.968 ;
    END
  END o[203]
  PIN o[204]
    DIRECTION OUTPUT ;
    USE SIGNAL ;
    PORT
      LAYER M4 ;
        RECT  172.716 101.04 172.8 101.064 ;
    END
  END o[204]
  PIN o[205]
    DIRECTION OUTPUT ;
    USE SIGNAL ;
    PORT
      LAYER M4 ;
        RECT  172.716 101.136 172.8 101.16 ;
    END
  END o[205]
  PIN o[206]
    DIRECTION OUTPUT ;
    USE SIGNAL ;
    PORT
      LAYER M4 ;
        RECT  172.716 101.232 172.8 101.256 ;
    END
  END o[206]
  PIN o[207]
    DIRECTION OUTPUT ;
    USE SIGNAL ;
    PORT
      LAYER M4 ;
        RECT  172.716 101.328 172.8 101.352 ;
    END
  END o[207]
  PIN o[208]
    DIRECTION OUTPUT ;
    USE SIGNAL ;
    PORT
      LAYER M4 ;
        RECT  172.716 101.424 172.8 101.448 ;
    END
  END o[208]
  PIN o[209]
    DIRECTION OUTPUT ;
    USE SIGNAL ;
    PORT
      LAYER M4 ;
        RECT  172.716 101.52 172.8 101.544 ;
    END
  END o[209]
  PIN o[20]
    DIRECTION OUTPUT ;
    USE SIGNAL ;
    PORT
      LAYER M4 ;
        RECT  172.716 88.752 172.8 88.776 ;
    END
  END o[20]
  PIN o[210]
    DIRECTION OUTPUT ;
    USE SIGNAL ;
    PORT
      LAYER M4 ;
        RECT  172.716 101.616 172.8 101.64 ;
    END
  END o[210]
  PIN o[211]
    DIRECTION OUTPUT ;
    USE SIGNAL ;
    PORT
      LAYER M4 ;
        RECT  172.716 101.712 172.8 101.736 ;
    END
  END o[211]
  PIN o[212]
    DIRECTION OUTPUT ;
    USE SIGNAL ;
    PORT
      LAYER M4 ;
        RECT  172.716 101.808 172.8 101.832 ;
    END
  END o[212]
  PIN o[213]
    DIRECTION OUTPUT ;
    USE SIGNAL ;
    PORT
      LAYER M4 ;
        RECT  172.716 101.904 172.8 101.928 ;
    END
  END o[213]
  PIN o[214]
    DIRECTION OUTPUT ;
    USE SIGNAL ;
    PORT
      LAYER M4 ;
        RECT  172.716 102 172.8 102.024 ;
    END
  END o[214]
  PIN o[215]
    DIRECTION OUTPUT ;
    USE SIGNAL ;
    PORT
      LAYER M4 ;
        RECT  172.716 102.096 172.8 102.12 ;
    END
  END o[215]
  PIN o[216]
    DIRECTION OUTPUT ;
    USE SIGNAL ;
    PORT
      LAYER M4 ;
        RECT  172.716 102.192 172.8 102.216 ;
    END
  END o[216]
  PIN o[217]
    DIRECTION OUTPUT ;
    USE SIGNAL ;
    PORT
      LAYER M4 ;
        RECT  172.716 102.288 172.8 102.312 ;
    END
  END o[217]
  PIN o[218]
    DIRECTION OUTPUT ;
    USE SIGNAL ;
    PORT
      LAYER M4 ;
        RECT  172.716 102.384 172.8 102.408 ;
    END
  END o[218]
  PIN o[219]
    DIRECTION OUTPUT ;
    USE SIGNAL ;
    PORT
      LAYER M4 ;
        RECT  172.716 102.48 172.8 102.504 ;
    END
  END o[219]
  PIN o[21]
    DIRECTION OUTPUT ;
    USE SIGNAL ;
    PORT
      LAYER M4 ;
        RECT  172.716 88.848 172.8 88.872 ;
    END
  END o[21]
  PIN o[220]
    DIRECTION OUTPUT ;
    USE SIGNAL ;
    PORT
      LAYER M4 ;
        RECT  172.716 102.576 172.8 102.6 ;
    END
  END o[220]
  PIN o[221]
    DIRECTION OUTPUT ;
    USE SIGNAL ;
    PORT
      LAYER M4 ;
        RECT  172.716 102.672 172.8 102.696 ;
    END
  END o[221]
  PIN o[222]
    DIRECTION OUTPUT ;
    USE SIGNAL ;
    PORT
      LAYER M4 ;
        RECT  172.716 102.768 172.8 102.792 ;
    END
  END o[222]
  PIN o[223]
    DIRECTION OUTPUT ;
    USE SIGNAL ;
    PORT
      LAYER M4 ;
        RECT  172.716 89.808 172.8 89.832 ;
    END
  END o[223]
  PIN o[224]
    DIRECTION OUTPUT ;
    USE SIGNAL ;
    PORT
      LAYER M4 ;
        RECT  172.716 89.904 172.8 89.928 ;
    END
  END o[224]
  PIN o[225]
    DIRECTION OUTPUT ;
    USE SIGNAL ;
    PORT
      LAYER M4 ;
        RECT  172.716 90 172.8 90.024 ;
    END
  END o[225]
  PIN o[226]
    DIRECTION OUTPUT ;
    USE SIGNAL ;
    PORT
      LAYER M4 ;
        RECT  172.716 90.096 172.8 90.12 ;
    END
  END o[226]
  PIN o[227]
    DIRECTION OUTPUT ;
    USE SIGNAL ;
    PORT
      LAYER M4 ;
        RECT  172.716 90.192 172.8 90.216 ;
    END
  END o[227]
  PIN o[228]
    DIRECTION OUTPUT ;
    USE SIGNAL ;
    PORT
      LAYER M4 ;
        RECT  172.716 90.288 172.8 90.312 ;
    END
  END o[228]
  PIN o[229]
    DIRECTION OUTPUT ;
    USE SIGNAL ;
    PORT
      LAYER M4 ;
        RECT  172.716 90.384 172.8 90.408 ;
    END
  END o[229]
  PIN o[22]
    DIRECTION OUTPUT ;
    USE SIGNAL ;
    PORT
      LAYER M4 ;
        RECT  172.716 88.944 172.8 88.968 ;
    END
  END o[22]
  PIN o[230]
    DIRECTION OUTPUT ;
    USE SIGNAL ;
    PORT
      LAYER M4 ;
        RECT  172.716 90.48 172.8 90.504 ;
    END
  END o[230]
  PIN o[231]
    DIRECTION OUTPUT ;
    USE SIGNAL ;
    PORT
      LAYER M4 ;
        RECT  172.716 90.576 172.8 90.6 ;
    END
  END o[231]
  PIN o[232]
    DIRECTION OUTPUT ;
    USE SIGNAL ;
    PORT
      LAYER M4 ;
        RECT  172.716 90.672 172.8 90.696 ;
    END
  END o[232]
  PIN o[233]
    DIRECTION OUTPUT ;
    USE SIGNAL ;
    PORT
      LAYER M4 ;
        RECT  172.716 90.768 172.8 90.792 ;
    END
  END o[233]
  PIN o[234]
    DIRECTION OUTPUT ;
    USE SIGNAL ;
    PORT
      LAYER M4 ;
        RECT  172.716 90.864 172.8 90.888 ;
    END
  END o[234]
  PIN o[235]
    DIRECTION OUTPUT ;
    USE SIGNAL ;
    PORT
      LAYER M4 ;
        RECT  172.716 90.96 172.8 90.984 ;
    END
  END o[235]
  PIN o[236]
    DIRECTION OUTPUT ;
    USE SIGNAL ;
    PORT
      LAYER M4 ;
        RECT  172.716 91.056 172.8 91.08 ;
    END
  END o[236]
  PIN o[237]
    DIRECTION OUTPUT ;
    USE SIGNAL ;
    PORT
      LAYER M4 ;
        RECT  172.716 91.152 172.8 91.176 ;
    END
  END o[237]
  PIN o[238]
    DIRECTION OUTPUT ;
    USE SIGNAL ;
    PORT
      LAYER M4 ;
        RECT  172.716 91.248 172.8 91.272 ;
    END
  END o[238]
  PIN o[239]
    DIRECTION OUTPUT ;
    USE SIGNAL ;
    PORT
      LAYER M4 ;
        RECT  172.716 91.344 172.8 91.368 ;
    END
  END o[239]
  PIN o[23]
    DIRECTION OUTPUT ;
    USE SIGNAL ;
    PORT
      LAYER M4 ;
        RECT  172.716 89.04 172.8 89.064 ;
    END
  END o[23]
  PIN o[240]
    DIRECTION OUTPUT ;
    USE SIGNAL ;
    PORT
      LAYER M4 ;
        RECT  172.716 91.44 172.8 91.464 ;
    END
  END o[240]
  PIN o[241]
    DIRECTION OUTPUT ;
    USE SIGNAL ;
    PORT
      LAYER M4 ;
        RECT  172.716 91.536 172.8 91.56 ;
    END
  END o[241]
  PIN o[242]
    DIRECTION OUTPUT ;
    USE SIGNAL ;
    PORT
      LAYER M4 ;
        RECT  172.716 91.632 172.8 91.656 ;
    END
  END o[242]
  PIN o[243]
    DIRECTION OUTPUT ;
    USE SIGNAL ;
    PORT
      LAYER M4 ;
        RECT  172.716 91.728 172.8 91.752 ;
    END
  END o[243]
  PIN o[244]
    DIRECTION OUTPUT ;
    USE SIGNAL ;
    PORT
      LAYER M4 ;
        RECT  172.716 91.824 172.8 91.848 ;
    END
  END o[244]
  PIN o[245]
    DIRECTION OUTPUT ;
    USE SIGNAL ;
    PORT
      LAYER M4 ;
        RECT  172.716 91.92 172.8 91.944 ;
    END
  END o[245]
  PIN o[246]
    DIRECTION OUTPUT ;
    USE SIGNAL ;
    PORT
      LAYER M4 ;
        RECT  172.716 92.016 172.8 92.04 ;
    END
  END o[246]
  PIN o[247]
    DIRECTION OUTPUT ;
    USE SIGNAL ;
    PORT
      LAYER M4 ;
        RECT  172.716 92.112 172.8 92.136 ;
    END
  END o[247]
  PIN o[248]
    DIRECTION OUTPUT ;
    USE SIGNAL ;
    PORT
      LAYER M4 ;
        RECT  172.716 92.208 172.8 92.232 ;
    END
  END o[248]
  PIN o[249]
    DIRECTION OUTPUT ;
    USE SIGNAL ;
    PORT
      LAYER M4 ;
        RECT  172.716 92.304 172.8 92.328 ;
    END
  END o[249]
  PIN o[24]
    DIRECTION OUTPUT ;
    USE SIGNAL ;
    PORT
      LAYER M4 ;
        RECT  172.716 89.136 172.8 89.16 ;
    END
  END o[24]
  PIN o[250]
    DIRECTION OUTPUT ;
    USE SIGNAL ;
    PORT
      LAYER M4 ;
        RECT  172.716 92.4 172.8 92.424 ;
    END
  END o[250]
  PIN o[251]
    DIRECTION OUTPUT ;
    USE SIGNAL ;
    PORT
      LAYER M4 ;
        RECT  172.716 92.496 172.8 92.52 ;
    END
  END o[251]
  PIN o[252]
    DIRECTION OUTPUT ;
    USE SIGNAL ;
    PORT
      LAYER M4 ;
        RECT  172.716 92.592 172.8 92.616 ;
    END
  END o[252]
  PIN o[253]
    DIRECTION OUTPUT ;
    USE SIGNAL ;
    PORT
      LAYER M4 ;
        RECT  172.716 92.688 172.8 92.712 ;
    END
  END o[253]
  PIN o[254]
    DIRECTION OUTPUT ;
    USE SIGNAL ;
    PORT
      LAYER M4 ;
        RECT  172.716 92.784 172.8 92.808 ;
    END
  END o[254]
  PIN o[255]
    DIRECTION OUTPUT ;
    USE SIGNAL ;
    PORT
      LAYER M4 ;
        RECT  172.716 96.72 172.8 96.744 ;
    END
  END o[255]
  PIN o[256]
    DIRECTION OUTPUT ;
    USE SIGNAL ;
    PORT
      LAYER M4 ;
        RECT  172.716 96.816 172.8 96.84 ;
    END
  END o[256]
  PIN o[257]
    DIRECTION OUTPUT ;
    USE SIGNAL ;
    PORT
      LAYER M4 ;
        RECT  172.716 96.912 172.8 96.936 ;
    END
  END o[257]
  PIN o[258]
    DIRECTION OUTPUT ;
    USE SIGNAL ;
    PORT
      LAYER M4 ;
        RECT  172.716 97.008 172.8 97.032 ;
    END
  END o[258]
  PIN o[259]
    DIRECTION OUTPUT ;
    USE SIGNAL ;
    PORT
      LAYER M4 ;
        RECT  172.716 97.104 172.8 97.128 ;
    END
  END o[259]
  PIN o[25]
    DIRECTION OUTPUT ;
    USE SIGNAL ;
    PORT
      LAYER M4 ;
        RECT  172.716 89.232 172.8 89.256 ;
    END
  END o[25]
  PIN o[260]
    DIRECTION OUTPUT ;
    USE SIGNAL ;
    PORT
      LAYER M4 ;
        RECT  172.716 97.2 172.8 97.224 ;
    END
  END o[260]
  PIN o[261]
    DIRECTION OUTPUT ;
    USE SIGNAL ;
    PORT
      LAYER M4 ;
        RECT  172.716 97.296 172.8 97.32 ;
    END
  END o[261]
  PIN o[262]
    DIRECTION OUTPUT ;
    USE SIGNAL ;
    PORT
      LAYER M4 ;
        RECT  172.716 97.392 172.8 97.416 ;
    END
  END o[262]
  PIN o[263]
    DIRECTION OUTPUT ;
    USE SIGNAL ;
    PORT
      LAYER M4 ;
        RECT  172.716 97.488 172.8 97.512 ;
    END
  END o[263]
  PIN o[264]
    DIRECTION OUTPUT ;
    USE SIGNAL ;
    PORT
      LAYER M4 ;
        RECT  172.716 97.584 172.8 97.608 ;
    END
  END o[264]
  PIN o[265]
    DIRECTION OUTPUT ;
    USE SIGNAL ;
    PORT
      LAYER M4 ;
        RECT  172.716 97.68 172.8 97.704 ;
    END
  END o[265]
  PIN o[266]
    DIRECTION OUTPUT ;
    USE SIGNAL ;
    PORT
      LAYER M4 ;
        RECT  172.716 97.776 172.8 97.8 ;
    END
  END o[266]
  PIN o[267]
    DIRECTION OUTPUT ;
    USE SIGNAL ;
    PORT
      LAYER M4 ;
        RECT  172.716 97.872 172.8 97.896 ;
    END
  END o[267]
  PIN o[268]
    DIRECTION OUTPUT ;
    USE SIGNAL ;
    PORT
      LAYER M4 ;
        RECT  172.716 97.968 172.8 97.992 ;
    END
  END o[268]
  PIN o[269]
    DIRECTION OUTPUT ;
    USE SIGNAL ;
    PORT
      LAYER M4 ;
        RECT  172.716 98.064 172.8 98.088 ;
    END
  END o[269]
  PIN o[26]
    DIRECTION OUTPUT ;
    USE SIGNAL ;
    PORT
      LAYER M4 ;
        RECT  172.716 89.328 172.8 89.352 ;
    END
  END o[26]
  PIN o[270]
    DIRECTION OUTPUT ;
    USE SIGNAL ;
    PORT
      LAYER M4 ;
        RECT  172.716 98.16 172.8 98.184 ;
    END
  END o[270]
  PIN o[271]
    DIRECTION OUTPUT ;
    USE SIGNAL ;
    PORT
      LAYER M4 ;
        RECT  172.716 98.256 172.8 98.28 ;
    END
  END o[271]
  PIN o[272]
    DIRECTION OUTPUT ;
    USE SIGNAL ;
    PORT
      LAYER M4 ;
        RECT  172.716 98.352 172.8 98.376 ;
    END
  END o[272]
  PIN o[273]
    DIRECTION OUTPUT ;
    USE SIGNAL ;
    PORT
      LAYER M4 ;
        RECT  172.716 98.448 172.8 98.472 ;
    END
  END o[273]
  PIN o[274]
    DIRECTION OUTPUT ;
    USE SIGNAL ;
    PORT
      LAYER M4 ;
        RECT  172.716 98.544 172.8 98.568 ;
    END
  END o[274]
  PIN o[275]
    DIRECTION OUTPUT ;
    USE SIGNAL ;
    PORT
      LAYER M4 ;
        RECT  172.716 98.64 172.8 98.664 ;
    END
  END o[275]
  PIN o[27]
    DIRECTION OUTPUT ;
    USE SIGNAL ;
    PORT
      LAYER M4 ;
        RECT  172.716 89.424 172.8 89.448 ;
    END
  END o[27]
  PIN o[28]
    DIRECTION OUTPUT ;
    USE SIGNAL ;
    PORT
      LAYER M4 ;
        RECT  172.716 89.52 172.8 89.544 ;
    END
  END o[28]
  PIN o[29]
    DIRECTION OUTPUT ;
    USE SIGNAL ;
    PORT
      LAYER M4 ;
        RECT  172.716 89.616 172.8 89.64 ;
    END
  END o[29]
  PIN o[2]
    DIRECTION OUTPUT ;
    USE SIGNAL ;
    PORT
      LAYER M4 ;
        RECT  172.716 87.024 172.8 87.048 ;
    END
  END o[2]
  PIN o[30]
    DIRECTION OUTPUT ;
    USE SIGNAL ;
    PORT
      LAYER M4 ;
        RECT  172.716 89.712 172.8 89.736 ;
    END
  END o[30]
  PIN o[31]
    DIRECTION OUTPUT ;
    USE SIGNAL ;
    PORT
      LAYER M4 ;
        RECT  172.716 83.664 172.8 83.688 ;
    END
  END o[31]
  PIN o[32]
    DIRECTION OUTPUT ;
    USE SIGNAL ;
    PORT
      LAYER M4 ;
        RECT  172.716 83.76 172.8 83.784 ;
    END
  END o[32]
  PIN o[33]
    DIRECTION OUTPUT ;
    USE SIGNAL ;
    PORT
      LAYER M4 ;
        RECT  172.716 83.856 172.8 83.88 ;
    END
  END o[33]
  PIN o[34]
    DIRECTION OUTPUT ;
    USE SIGNAL ;
    PORT
      LAYER M4 ;
        RECT  172.716 83.952 172.8 83.976 ;
    END
  END o[34]
  PIN o[35]
    DIRECTION OUTPUT ;
    USE SIGNAL ;
    PORT
      LAYER M4 ;
        RECT  172.716 84.048 172.8 84.072 ;
    END
  END o[35]
  PIN o[36]
    DIRECTION OUTPUT ;
    USE SIGNAL ;
    PORT
      LAYER M4 ;
        RECT  172.716 84.144 172.8 84.168 ;
    END
  END o[36]
  PIN o[37]
    DIRECTION OUTPUT ;
    USE SIGNAL ;
    PORT
      LAYER M4 ;
        RECT  172.716 84.24 172.8 84.264 ;
    END
  END o[37]
  PIN o[38]
    DIRECTION OUTPUT ;
    USE SIGNAL ;
    PORT
      LAYER M4 ;
        RECT  172.716 84.336 172.8 84.36 ;
    END
  END o[38]
  PIN o[39]
    DIRECTION OUTPUT ;
    USE SIGNAL ;
    PORT
      LAYER M4 ;
        RECT  172.716 84.432 172.8 84.456 ;
    END
  END o[39]
  PIN o[3]
    DIRECTION OUTPUT ;
    USE SIGNAL ;
    PORT
      LAYER M4 ;
        RECT  172.716 87.12 172.8 87.144 ;
    END
  END o[3]
  PIN o[40]
    DIRECTION OUTPUT ;
    USE SIGNAL ;
    PORT
      LAYER M4 ;
        RECT  172.716 84.528 172.8 84.552 ;
    END
  END o[40]
  PIN o[41]
    DIRECTION OUTPUT ;
    USE SIGNAL ;
    PORT
      LAYER M4 ;
        RECT  172.716 84.624 172.8 84.648 ;
    END
  END o[41]
  PIN o[42]
    DIRECTION OUTPUT ;
    USE SIGNAL ;
    PORT
      LAYER M4 ;
        RECT  172.716 84.72 172.8 84.744 ;
    END
  END o[42]
  PIN o[43]
    DIRECTION OUTPUT ;
    USE SIGNAL ;
    PORT
      LAYER M4 ;
        RECT  172.716 84.816 172.8 84.84 ;
    END
  END o[43]
  PIN o[44]
    DIRECTION OUTPUT ;
    USE SIGNAL ;
    PORT
      LAYER M4 ;
        RECT  172.716 84.912 172.8 84.936 ;
    END
  END o[44]
  PIN o[45]
    DIRECTION OUTPUT ;
    USE SIGNAL ;
    PORT
      LAYER M4 ;
        RECT  172.716 85.008 172.8 85.032 ;
    END
  END o[45]
  PIN o[46]
    DIRECTION OUTPUT ;
    USE SIGNAL ;
    PORT
      LAYER M4 ;
        RECT  172.716 85.104 172.8 85.128 ;
    END
  END o[46]
  PIN o[47]
    DIRECTION OUTPUT ;
    USE SIGNAL ;
    PORT
      LAYER M4 ;
        RECT  172.716 85.2 172.8 85.224 ;
    END
  END o[47]
  PIN o[48]
    DIRECTION OUTPUT ;
    USE SIGNAL ;
    PORT
      LAYER M4 ;
        RECT  172.716 85.296 172.8 85.32 ;
    END
  END o[48]
  PIN o[49]
    DIRECTION OUTPUT ;
    USE SIGNAL ;
    PORT
      LAYER M4 ;
        RECT  172.716 85.392 172.8 85.416 ;
    END
  END o[49]
  PIN o[4]
    DIRECTION OUTPUT ;
    USE SIGNAL ;
    PORT
      LAYER M4 ;
        RECT  172.716 87.216 172.8 87.24 ;
    END
  END o[4]
  PIN o[50]
    DIRECTION OUTPUT ;
    USE SIGNAL ;
    PORT
      LAYER M4 ;
        RECT  172.716 85.488 172.8 85.512 ;
    END
  END o[50]
  PIN o[51]
    DIRECTION OUTPUT ;
    USE SIGNAL ;
    PORT
      LAYER M4 ;
        RECT  172.716 85.584 172.8 85.608 ;
    END
  END o[51]
  PIN o[52]
    DIRECTION OUTPUT ;
    USE SIGNAL ;
    PORT
      LAYER M4 ;
        RECT  172.716 85.68 172.8 85.704 ;
    END
  END o[52]
  PIN o[53]
    DIRECTION OUTPUT ;
    USE SIGNAL ;
    PORT
      LAYER M4 ;
        RECT  172.716 85.776 172.8 85.8 ;
    END
  END o[53]
  PIN o[54]
    DIRECTION OUTPUT ;
    USE SIGNAL ;
    PORT
      LAYER M4 ;
        RECT  172.716 85.872 172.8 85.896 ;
    END
  END o[54]
  PIN o[55]
    DIRECTION OUTPUT ;
    USE SIGNAL ;
    PORT
      LAYER M4 ;
        RECT  172.716 85.968 172.8 85.992 ;
    END
  END o[55]
  PIN o[56]
    DIRECTION OUTPUT ;
    USE SIGNAL ;
    PORT
      LAYER M4 ;
        RECT  172.716 86.064 172.8 86.088 ;
    END
  END o[56]
  PIN o[57]
    DIRECTION OUTPUT ;
    USE SIGNAL ;
    PORT
      LAYER M4 ;
        RECT  172.716 86.16 172.8 86.184 ;
    END
  END o[57]
  PIN o[58]
    DIRECTION OUTPUT ;
    USE SIGNAL ;
    PORT
      LAYER M4 ;
        RECT  172.716 86.256 172.8 86.28 ;
    END
  END o[58]
  PIN o[59]
    DIRECTION OUTPUT ;
    USE SIGNAL ;
    PORT
      LAYER M4 ;
        RECT  172.716 86.352 172.8 86.376 ;
    END
  END o[59]
  PIN o[5]
    DIRECTION OUTPUT ;
    USE SIGNAL ;
    PORT
      LAYER M4 ;
        RECT  172.716 87.312 172.8 87.336 ;
    END
  END o[5]
  PIN o[60]
    DIRECTION OUTPUT ;
    USE SIGNAL ;
    PORT
      LAYER M4 ;
        RECT  172.716 86.448 172.8 86.472 ;
    END
  END o[60]
  PIN o[61]
    DIRECTION OUTPUT ;
    USE SIGNAL ;
    PORT
      LAYER M4 ;
        RECT  172.716 86.544 172.8 86.568 ;
    END
  END o[61]
  PIN o[62]
    DIRECTION OUTPUT ;
    USE SIGNAL ;
    PORT
      LAYER M4 ;
        RECT  172.716 86.64 172.8 86.664 ;
    END
  END o[62]
  PIN o[63]
    DIRECTION OUTPUT ;
    USE SIGNAL ;
    PORT
      LAYER M4 ;
        RECT  172.716 73.68 172.8 73.704 ;
    END
  END o[63]
  PIN o[64]
    DIRECTION OUTPUT ;
    USE SIGNAL ;
    PORT
      LAYER M4 ;
        RECT  172.716 73.776 172.8 73.8 ;
    END
  END o[64]
  PIN o[65]
    DIRECTION OUTPUT ;
    USE SIGNAL ;
    PORT
      LAYER M4 ;
        RECT  172.716 73.872 172.8 73.896 ;
    END
  END o[65]
  PIN o[66]
    DIRECTION OUTPUT ;
    USE SIGNAL ;
    PORT
      LAYER M4 ;
        RECT  172.716 73.968 172.8 73.992 ;
    END
  END o[66]
  PIN o[67]
    DIRECTION OUTPUT ;
    USE SIGNAL ;
    PORT
      LAYER M4 ;
        RECT  172.716 74.064 172.8 74.088 ;
    END
  END o[67]
  PIN o[68]
    DIRECTION OUTPUT ;
    USE SIGNAL ;
    PORT
      LAYER M4 ;
        RECT  172.716 74.16 172.8 74.184 ;
    END
  END o[68]
  PIN o[69]
    DIRECTION OUTPUT ;
    USE SIGNAL ;
    PORT
      LAYER M4 ;
        RECT  172.716 74.256 172.8 74.28 ;
    END
  END o[69]
  PIN o[6]
    DIRECTION OUTPUT ;
    USE SIGNAL ;
    PORT
      LAYER M4 ;
        RECT  172.716 87.408 172.8 87.432 ;
    END
  END o[6]
  PIN o[70]
    DIRECTION OUTPUT ;
    USE SIGNAL ;
    PORT
      LAYER M4 ;
        RECT  172.716 74.352 172.8 74.376 ;
    END
  END o[70]
  PIN o[71]
    DIRECTION OUTPUT ;
    USE SIGNAL ;
    PORT
      LAYER M4 ;
        RECT  172.716 74.448 172.8 74.472 ;
    END
  END o[71]
  PIN o[72]
    DIRECTION OUTPUT ;
    USE SIGNAL ;
    PORT
      LAYER M4 ;
        RECT  172.716 74.544 172.8 74.568 ;
    END
  END o[72]
  PIN o[73]
    DIRECTION OUTPUT ;
    USE SIGNAL ;
    PORT
      LAYER M4 ;
        RECT  172.716 74.64 172.8 74.664 ;
    END
  END o[73]
  PIN o[74]
    DIRECTION OUTPUT ;
    USE SIGNAL ;
    PORT
      LAYER M4 ;
        RECT  172.716 74.736 172.8 74.76 ;
    END
  END o[74]
  PIN o[75]
    DIRECTION OUTPUT ;
    USE SIGNAL ;
    PORT
      LAYER M4 ;
        RECT  172.716 74.832 172.8 74.856 ;
    END
  END o[75]
  PIN o[76]
    DIRECTION OUTPUT ;
    USE SIGNAL ;
    PORT
      LAYER M4 ;
        RECT  172.716 74.928 172.8 74.952 ;
    END
  END o[76]
  PIN o[77]
    DIRECTION OUTPUT ;
    USE SIGNAL ;
    PORT
      LAYER M4 ;
        RECT  172.716 75.024 172.8 75.048 ;
    END
  END o[77]
  PIN o[78]
    DIRECTION OUTPUT ;
    USE SIGNAL ;
    PORT
      LAYER M4 ;
        RECT  172.716 75.12 172.8 75.144 ;
    END
  END o[78]
  PIN o[79]
    DIRECTION OUTPUT ;
    USE SIGNAL ;
    PORT
      LAYER M4 ;
        RECT  172.716 75.216 172.8 75.24 ;
    END
  END o[79]
  PIN o[7]
    DIRECTION OUTPUT ;
    USE SIGNAL ;
    PORT
      LAYER M4 ;
        RECT  172.716 87.504 172.8 87.528 ;
    END
  END o[7]
  PIN o[80]
    DIRECTION OUTPUT ;
    USE SIGNAL ;
    PORT
      LAYER M4 ;
        RECT  172.716 75.312 172.8 75.336 ;
    END
  END o[80]
  PIN o[81]
    DIRECTION OUTPUT ;
    USE SIGNAL ;
    PORT
      LAYER M4 ;
        RECT  172.716 75.408 172.8 75.432 ;
    END
  END o[81]
  PIN o[82]
    DIRECTION OUTPUT ;
    USE SIGNAL ;
    PORT
      LAYER M4 ;
        RECT  172.716 75.504 172.8 75.528 ;
    END
  END o[82]
  PIN o[83]
    DIRECTION OUTPUT ;
    USE SIGNAL ;
    PORT
      LAYER M4 ;
        RECT  172.716 75.6 172.8 75.624 ;
    END
  END o[83]
  PIN o[84]
    DIRECTION OUTPUT ;
    USE SIGNAL ;
    PORT
      LAYER M4 ;
        RECT  172.716 75.696 172.8 75.72 ;
    END
  END o[84]
  PIN o[85]
    DIRECTION OUTPUT ;
    USE SIGNAL ;
    PORT
      LAYER M4 ;
        RECT  172.716 75.792 172.8 75.816 ;
    END
  END o[85]
  PIN o[86]
    DIRECTION OUTPUT ;
    USE SIGNAL ;
    PORT
      LAYER M4 ;
        RECT  172.716 75.888 172.8 75.912 ;
    END
  END o[86]
  PIN o[87]
    DIRECTION OUTPUT ;
    USE SIGNAL ;
    PORT
      LAYER M4 ;
        RECT  172.716 75.984 172.8 76.008 ;
    END
  END o[87]
  PIN o[88]
    DIRECTION OUTPUT ;
    USE SIGNAL ;
    PORT
      LAYER M4 ;
        RECT  172.716 76.08 172.8 76.104 ;
    END
  END o[88]
  PIN o[89]
    DIRECTION OUTPUT ;
    USE SIGNAL ;
    PORT
      LAYER M4 ;
        RECT  172.716 76.176 172.8 76.2 ;
    END
  END o[89]
  PIN o[8]
    DIRECTION OUTPUT ;
    USE SIGNAL ;
    PORT
      LAYER M4 ;
        RECT  172.716 87.6 172.8 87.624 ;
    END
  END o[8]
  PIN o[90]
    DIRECTION OUTPUT ;
    USE SIGNAL ;
    PORT
      LAYER M4 ;
        RECT  172.716 76.272 172.8 76.296 ;
    END
  END o[90]
  PIN o[91]
    DIRECTION OUTPUT ;
    USE SIGNAL ;
    PORT
      LAYER M4 ;
        RECT  172.716 76.368 172.8 76.392 ;
    END
  END o[91]
  PIN o[92]
    DIRECTION OUTPUT ;
    USE SIGNAL ;
    PORT
      LAYER M4 ;
        RECT  172.716 76.464 172.8 76.488 ;
    END
  END o[92]
  PIN o[93]
    DIRECTION OUTPUT ;
    USE SIGNAL ;
    PORT
      LAYER M4 ;
        RECT  172.716 76.56 172.8 76.584 ;
    END
  END o[93]
  PIN o[94]
    DIRECTION OUTPUT ;
    USE SIGNAL ;
    PORT
      LAYER M4 ;
        RECT  172.716 76.656 172.8 76.68 ;
    END
  END o[94]
  PIN o[95]
    DIRECTION OUTPUT ;
    USE SIGNAL ;
    PORT
      LAYER M4 ;
        RECT  172.716 77.52 172.8 77.544 ;
    END
  END o[95]
  PIN o[96]
    DIRECTION OUTPUT ;
    USE SIGNAL ;
    PORT
      LAYER M4 ;
        RECT  172.716 77.616 172.8 77.64 ;
    END
  END o[96]
  PIN o[97]
    DIRECTION OUTPUT ;
    USE SIGNAL ;
    PORT
      LAYER M4 ;
        RECT  172.716 77.712 172.8 77.736 ;
    END
  END o[97]
  PIN o[98]
    DIRECTION OUTPUT ;
    USE SIGNAL ;
    PORT
      LAYER M4 ;
        RECT  172.716 77.808 172.8 77.832 ;
    END
  END o[98]
  PIN o[99]
    DIRECTION OUTPUT ;
    USE SIGNAL ;
    PORT
      LAYER M4 ;
        RECT  172.716 77.904 172.8 77.928 ;
    END
  END o[99]
  PIN o[9]
    DIRECTION OUTPUT ;
    USE SIGNAL ;
    PORT
      LAYER M4 ;
        RECT  172.716 87.696 172.8 87.72 ;
    END
  END o[9]
  PIN rst
    DIRECTION INPUT ;
    USE SIGNAL ;
    PORT
      LAYER M4 ;
        RECT  0 89.04 0.084 89.064 ;
    END
  END rst
  PIN VDD
    DIRECTION INOUT ;
    USE POWER ;
    PORT
      LAYER M5 ;
        RECT  169.992 2.151 170.112 170.649 ;
        RECT  164.592 2.151 164.712 170.649 ;
        RECT  159.192 2.151 159.312 170.649 ;
        RECT  153.792 2.151 153.912 170.649 ;
        RECT  148.392 2.151 148.512 170.649 ;
        RECT  142.992 2.151 143.112 170.649 ;
        RECT  137.592 2.151 137.712 170.649 ;
        RECT  132.192 2.151 132.312 170.649 ;
        RECT  126.792 2.151 126.912 170.649 ;
        RECT  121.392 2.151 121.512 170.649 ;
        RECT  115.992 2.151 116.112 170.649 ;
        RECT  110.592 2.151 110.712 170.649 ;
        RECT  105.192 2.151 105.312 170.649 ;
        RECT  99.792 2.151 99.912 170.649 ;
        RECT  94.392 2.151 94.512 170.649 ;
        RECT  88.992 2.151 89.112 170.649 ;
        RECT  83.592 2.151 83.712 170.649 ;
        RECT  78.192 2.151 78.312 170.649 ;
        RECT  72.792 2.151 72.912 170.649 ;
        RECT  67.392 2.151 67.512 170.649 ;
        RECT  61.992 2.151 62.112 170.649 ;
        RECT  56.592 2.151 56.712 170.649 ;
        RECT  51.192 2.151 51.312 170.649 ;
        RECT  45.792 2.151 45.912 170.649 ;
        RECT  40.392 2.151 40.512 170.649 ;
        RECT  34.992 2.151 35.112 170.649 ;
        RECT  29.592 2.151 29.712 170.649 ;
        RECT  24.192 2.151 24.312 170.649 ;
        RECT  18.792 2.151 18.912 170.649 ;
        RECT  13.392 2.151 13.512 170.649 ;
        RECT  7.992 2.151 8.112 170.649 ;
        RECT  2.592 2.151 2.712 170.649 ;
    END
  END VDD
  PIN VSS
    DIRECTION INOUT ;
    USE GROUND ;
    PORT
      LAYER M5 ;
        RECT  169.8 2.137 169.92 170.663 ;
        RECT  164.4 2.137 164.52 170.663 ;
        RECT  159 2.137 159.12 170.663 ;
        RECT  153.6 2.137 153.72 170.663 ;
        RECT  148.2 2.137 148.32 170.663 ;
        RECT  142.8 2.137 142.92 170.663 ;
        RECT  137.4 2.137 137.52 170.663 ;
        RECT  132 2.137 132.12 170.663 ;
        RECT  126.6 2.137 126.72 170.663 ;
        RECT  121.2 2.137 121.32 170.663 ;
        RECT  115.8 2.137 115.92 170.663 ;
        RECT  110.4 2.137 110.52 170.663 ;
        RECT  105 2.137 105.12 170.663 ;
        RECT  99.6 2.137 99.72 170.663 ;
        RECT  94.2 2.137 94.32 170.663 ;
        RECT  88.8 2.137 88.92 170.663 ;
        RECT  83.4 2.137 83.52 170.663 ;
        RECT  78 2.137 78.12 170.663 ;
        RECT  72.6 2.137 72.72 170.663 ;
        RECT  67.2 2.137 67.32 170.663 ;
        RECT  61.8 2.137 61.92 170.663 ;
        RECT  56.4 2.137 56.52 170.663 ;
        RECT  51 2.137 51.12 170.663 ;
        RECT  45.6 2.137 45.72 170.663 ;
        RECT  40.2 2.137 40.32 170.663 ;
        RECT  34.8 2.137 34.92 170.663 ;
        RECT  29.4 2.137 29.52 170.663 ;
        RECT  24 2.137 24.12 170.663 ;
        RECT  18.6 2.137 18.72 170.663 ;
        RECT  13.2 2.137 13.32 170.663 ;
        RECT  7.8 2.137 7.92 170.663 ;
        RECT  2.4 2.137 2.52 170.663 ;
    END
  END VSS
  OBS
    LAYER RVTN ;
     RECT  2.16 2.16 170.64 2.295 ;
     RECT  2.16 2.565 170.64 2.835 ;
     RECT  2.16 3.105 170.64 3.375 ;
     RECT  2.16 3.645 170.64 3.915 ;
     RECT  2.16 4.185 170.64 4.455 ;
     RECT  2.16 4.725 170.64 4.995 ;
     RECT  2.16 5.265 170.64 5.535 ;
     RECT  2.16 5.805 170.64 6.075 ;
     RECT  2.16 6.345 170.64 6.615 ;
     RECT  2.16 6.885 170.64 7.155 ;
     RECT  2.16 7.425 170.64 7.695 ;
     RECT  2.16 7.965 170.64 8.235 ;
     RECT  2.16 8.505 170.64 8.775 ;
     RECT  2.16 9.045 170.64 9.315 ;
     RECT  2.16 9.585 170.64 9.855 ;
     RECT  2.16 10.125 170.64 10.395 ;
     RECT  2.16 10.665 170.64 10.935 ;
     RECT  2.16 11.205 170.64 11.475 ;
     RECT  2.16 11.745 170.64 12.015 ;
     RECT  2.16 12.285 170.64 12.555 ;
     RECT  2.16 12.825 170.64 13.095 ;
     RECT  2.16 13.365 170.64 13.635 ;
     RECT  2.16 13.905 170.64 14.175 ;
     RECT  2.16 14.445 170.64 14.715 ;
     RECT  2.16 14.985 170.64 15.255 ;
     RECT  2.16 15.525 170.64 15.795 ;
     RECT  2.16 16.065 170.64 16.335 ;
     RECT  2.16 16.605 170.64 16.875 ;
     RECT  2.16 17.145 170.64 17.415 ;
     RECT  2.16 17.685 170.64 17.955 ;
     RECT  2.16 18.225 170.64 18.495 ;
     RECT  2.16 18.765 170.64 19.035 ;
     RECT  2.16 19.305 170.64 19.575 ;
     RECT  2.16 19.845 170.64 20.115 ;
     RECT  2.16 20.385 170.64 20.655 ;
     RECT  2.16 20.925 170.64 21.195 ;
     RECT  2.16 21.465 170.64 21.735 ;
     RECT  2.16 22.005 170.64 22.275 ;
     RECT  2.16 22.545 170.64 22.815 ;
     RECT  2.16 23.085 170.64 23.355 ;
     RECT  2.16 23.625 170.64 23.895 ;
     RECT  2.16 24.165 170.64 24.435 ;
     RECT  2.16 24.705 170.64 24.975 ;
     RECT  2.16 25.245 170.64 25.515 ;
     RECT  2.16 25.785 170.64 26.055 ;
     RECT  2.16 26.325 170.64 26.595 ;
     RECT  2.16 26.865 170.64 27.135 ;
     RECT  2.16 27.405 170.64 27.675 ;
     RECT  2.16 27.945 170.64 28.215 ;
     RECT  2.16 28.485 170.64 28.755 ;
     RECT  2.16 29.025 170.64 29.295 ;
     RECT  2.16 29.565 170.64 29.835 ;
     RECT  2.16 30.105 170.64 30.375 ;
     RECT  2.16 30.645 170.64 30.915 ;
     RECT  2.16 31.185 170.64 31.455 ;
     RECT  2.16 31.725 170.64 31.995 ;
     RECT  2.16 32.265 170.64 32.535 ;
     RECT  2.16 32.805 170.64 33.075 ;
     RECT  2.16 33.345 170.64 33.615 ;
     RECT  2.16 33.885 170.64 34.155 ;
     RECT  2.16 34.425 170.64 34.695 ;
     RECT  2.16 34.965 170.64 35.235 ;
     RECT  2.16 35.505 170.64 35.775 ;
     RECT  2.16 36.045 170.64 36.315 ;
     RECT  2.16 36.585 170.64 36.855 ;
     RECT  2.16 37.125 170.64 37.395 ;
     RECT  2.16 37.665 170.64 37.935 ;
     RECT  2.16 38.205 170.64 38.475 ;
     RECT  2.16 38.745 170.64 39.015 ;
     RECT  2.16 39.285 170.64 39.555 ;
     RECT  2.16 39.825 170.64 40.095 ;
     RECT  2.16 40.365 170.64 40.635 ;
     RECT  2.16 40.905 170.64 41.175 ;
     RECT  2.16 41.445 170.64 41.715 ;
     RECT  2.16 41.985 170.64 42.255 ;
     RECT  2.16 42.525 170.64 42.795 ;
     RECT  2.16 43.065 170.64 43.335 ;
     RECT  2.16 43.605 170.64 43.875 ;
     RECT  2.16 44.145 170.64 44.415 ;
     RECT  2.16 44.685 170.64 44.955 ;
     RECT  2.16 45.225 170.64 45.495 ;
     RECT  2.16 45.765 170.64 46.035 ;
     RECT  2.16 46.305 170.64 46.575 ;
     RECT  2.16 46.845 170.64 47.115 ;
     RECT  2.16 47.385 170.64 47.655 ;
     RECT  2.16 47.925 170.64 48.195 ;
     RECT  2.16 48.465 170.64 48.735 ;
     RECT  2.16 49.005 170.64 49.275 ;
     RECT  2.16 49.545 170.64 49.815 ;
     RECT  2.16 50.085 170.64 50.355 ;
     RECT  2.16 50.625 170.64 50.895 ;
     RECT  2.16 51.165 170.64 51.435 ;
     RECT  2.16 51.705 170.64 51.975 ;
     RECT  2.16 52.245 170.64 52.515 ;
     RECT  2.16 52.785 170.64 53.055 ;
     RECT  2.16 53.325 170.64 53.595 ;
     RECT  2.16 53.865 170.64 54.135 ;
     RECT  2.16 54.405 170.64 54.675 ;
     RECT  2.16 54.945 170.64 55.215 ;
     RECT  2.16 55.485 170.64 55.755 ;
     RECT  2.16 56.025 170.64 56.295 ;
     RECT  2.16 56.565 170.64 56.835 ;
     RECT  2.16 57.105 170.64 57.375 ;
     RECT  2.16 57.645 170.64 57.915 ;
     RECT  2.16 58.185 170.64 58.455 ;
     RECT  2.16 58.725 170.64 58.995 ;
     RECT  2.16 59.265 170.64 59.535 ;
     RECT  2.16 59.805 170.64 60.075 ;
     RECT  2.16 60.345 170.64 60.615 ;
     RECT  2.16 60.885 170.64 61.155 ;
     RECT  2.16 61.425 170.64 61.695 ;
     RECT  2.16 61.965 170.64 62.235 ;
     RECT  2.16 62.505 170.64 62.775 ;
     RECT  2.16 63.045 170.64 63.315 ;
     RECT  2.16 63.585 170.64 63.855 ;
     RECT  2.16 64.125 170.64 64.395 ;
     RECT  2.16 64.665 170.64 64.935 ;
     RECT  2.16 65.205 170.64 65.475 ;
     RECT  2.16 65.745 170.64 66.015 ;
     RECT  2.16 66.285 170.64 66.555 ;
     RECT  2.16 66.825 170.64 67.095 ;
     RECT  2.16 67.365 170.64 67.635 ;
     RECT  2.16 67.905 170.64 68.175 ;
     RECT  2.16 68.445 170.64 68.715 ;
     RECT  2.16 68.985 170.64 69.255 ;
     RECT  2.16 69.525 170.64 69.795 ;
     RECT  2.16 70.065 170.64 70.335 ;
     RECT  2.16 70.605 170.64 70.875 ;
     RECT  2.16 71.145 170.64 71.415 ;
     RECT  2.16 71.685 170.64 71.955 ;
     RECT  2.16 72.225 170.64 72.495 ;
     RECT  2.16 72.765 170.64 73.035 ;
     RECT  2.16 73.305 170.64 73.575 ;
     RECT  2.16 73.845 170.64 74.115 ;
     RECT  2.16 74.385 170.64 74.655 ;
     RECT  2.16 74.925 170.64 75.195 ;
     RECT  2.16 75.465 170.64 75.735 ;
     RECT  2.16 76.005 170.64 76.275 ;
     RECT  2.16 76.545 170.64 76.815 ;
     RECT  2.16 77.085 170.64 77.355 ;
     RECT  2.16 77.625 170.64 77.895 ;
     RECT  2.16 78.165 170.64 78.435 ;
     RECT  2.16 78.705 170.64 78.975 ;
     RECT  2.16 79.245 170.64 79.515 ;
     RECT  2.16 79.785 170.64 80.055 ;
     RECT  2.16 80.325 170.64 80.595 ;
     RECT  2.16 80.865 170.64 81.135 ;
     RECT  2.16 81.405 170.64 81.675 ;
     RECT  2.16 81.945 170.64 82.215 ;
     RECT  2.16 82.485 170.64 82.755 ;
     RECT  2.16 83.025 170.64 83.295 ;
     RECT  2.16 83.565 170.64 83.835 ;
     RECT  2.16 84.105 170.64 84.375 ;
     RECT  2.16 84.645 170.64 84.915 ;
     RECT  2.16 85.185 170.64 85.455 ;
     RECT  2.16 85.725 170.64 85.995 ;
     RECT  2.16 86.265 170.64 86.535 ;
     RECT  2.16 86.805 170.64 87.075 ;
     RECT  2.16 87.345 170.64 87.615 ;
     RECT  2.16 87.885 170.64 88.155 ;
     RECT  2.16 88.425 170.64 88.695 ;
     RECT  2.16 88.965 170.64 89.235 ;
     RECT  2.16 89.505 170.64 89.775 ;
     RECT  2.16 90.045 170.64 90.315 ;
     RECT  2.16 90.585 170.64 90.855 ;
     RECT  2.16 91.125 170.64 91.395 ;
     RECT  2.16 91.665 170.64 91.935 ;
     RECT  2.16 92.205 170.64 92.475 ;
     RECT  2.16 92.745 170.64 93.015 ;
     RECT  2.16 93.285 170.64 93.555 ;
     RECT  2.16 93.825 170.64 94.095 ;
     RECT  2.16 94.365 170.64 94.635 ;
     RECT  2.16 94.905 170.64 95.175 ;
     RECT  2.16 95.445 170.64 95.715 ;
     RECT  2.16 95.985 170.64 96.255 ;
     RECT  2.16 96.525 170.64 96.795 ;
     RECT  2.16 97.065 170.64 97.335 ;
     RECT  2.16 97.605 170.64 97.875 ;
     RECT  2.16 98.145 170.64 98.415 ;
     RECT  2.16 98.685 170.64 98.955 ;
     RECT  2.16 99.225 170.64 99.495 ;
     RECT  2.16 99.765 170.64 100.035 ;
     RECT  2.16 100.305 170.64 100.575 ;
     RECT  2.16 100.845 170.64 101.115 ;
     RECT  2.16 101.385 170.64 101.655 ;
     RECT  2.16 101.925 170.64 102.195 ;
     RECT  2.16 102.465 170.64 102.735 ;
     RECT  2.16 103.005 170.64 103.275 ;
     RECT  2.16 103.545 170.64 103.815 ;
     RECT  2.16 104.085 170.64 104.355 ;
     RECT  2.16 104.625 170.64 104.895 ;
     RECT  2.16 105.165 170.64 105.435 ;
     RECT  2.16 105.705 170.64 105.975 ;
     RECT  2.16 106.245 170.64 106.515 ;
     RECT  2.16 106.785 170.64 107.055 ;
     RECT  2.16 107.325 170.64 107.595 ;
     RECT  2.16 107.865 170.64 108.135 ;
     RECT  2.16 108.405 170.64 108.675 ;
     RECT  2.16 108.945 170.64 109.215 ;
     RECT  2.16 109.485 170.64 109.755 ;
     RECT  2.16 110.025 170.64 110.295 ;
     RECT  2.16 110.565 170.64 110.835 ;
     RECT  2.16 111.105 170.64 111.375 ;
     RECT  2.16 111.645 170.64 111.915 ;
     RECT  2.16 112.185 170.64 112.455 ;
     RECT  2.16 112.725 170.64 112.995 ;
     RECT  2.16 113.265 170.64 113.535 ;
     RECT  2.16 113.805 170.64 114.075 ;
     RECT  2.16 114.345 170.64 114.615 ;
     RECT  2.16 114.885 170.64 115.155 ;
     RECT  2.16 115.425 170.64 115.695 ;
     RECT  2.16 115.965 170.64 116.235 ;
     RECT  2.16 116.505 170.64 116.775 ;
     RECT  2.16 117.045 170.64 117.315 ;
     RECT  2.16 117.585 170.64 117.855 ;
     RECT  2.16 118.125 170.64 118.395 ;
     RECT  2.16 118.665 170.64 118.935 ;
     RECT  2.16 119.205 170.64 119.475 ;
     RECT  2.16 119.745 170.64 120.015 ;
     RECT  2.16 120.285 170.64 120.555 ;
     RECT  2.16 120.825 170.64 121.095 ;
     RECT  2.16 121.365 170.64 121.635 ;
     RECT  2.16 121.905 170.64 122.175 ;
     RECT  2.16 122.445 170.64 122.715 ;
     RECT  2.16 122.985 170.64 123.255 ;
     RECT  2.16 123.525 170.64 123.795 ;
     RECT  2.16 124.065 170.64 124.335 ;
     RECT  2.16 124.605 170.64 124.875 ;
     RECT  2.16 125.145 170.64 125.415 ;
     RECT  2.16 125.685 170.64 125.955 ;
     RECT  2.16 126.225 170.64 126.495 ;
     RECT  2.16 126.765 170.64 127.035 ;
     RECT  2.16 127.305 170.64 127.575 ;
     RECT  2.16 127.845 170.64 128.115 ;
     RECT  2.16 128.385 170.64 128.655 ;
     RECT  2.16 128.925 170.64 129.195 ;
     RECT  2.16 129.465 170.64 129.735 ;
     RECT  2.16 130.005 170.64 130.275 ;
     RECT  2.16 130.545 170.64 130.815 ;
     RECT  2.16 131.085 170.64 131.355 ;
     RECT  2.16 131.625 170.64 131.895 ;
     RECT  2.16 132.165 170.64 132.435 ;
     RECT  2.16 132.705 170.64 132.975 ;
     RECT  2.16 133.245 170.64 133.515 ;
     RECT  2.16 133.785 170.64 134.055 ;
     RECT  2.16 134.325 170.64 134.595 ;
     RECT  2.16 134.865 170.64 135.135 ;
     RECT  2.16 135.405 170.64 135.675 ;
     RECT  2.16 135.945 170.64 136.215 ;
     RECT  2.16 136.485 170.64 136.755 ;
     RECT  2.16 137.025 170.64 137.295 ;
     RECT  2.16 137.565 170.64 137.835 ;
     RECT  2.16 138.105 170.64 138.375 ;
     RECT  2.16 138.645 170.64 138.915 ;
     RECT  2.16 139.185 170.64 139.455 ;
     RECT  2.16 139.725 170.64 139.995 ;
     RECT  2.16 140.265 170.64 140.535 ;
     RECT  2.16 140.805 170.64 141.075 ;
     RECT  2.16 141.345 170.64 141.615 ;
     RECT  2.16 141.885 170.64 142.155 ;
     RECT  2.16 142.425 170.64 142.695 ;
     RECT  2.16 142.965 170.64 143.235 ;
     RECT  2.16 143.505 170.64 143.775 ;
     RECT  2.16 144.045 170.64 144.315 ;
     RECT  2.16 144.585 170.64 144.855 ;
     RECT  2.16 145.125 170.64 145.395 ;
     RECT  2.16 145.665 170.64 145.935 ;
     RECT  2.16 146.205 170.64 146.475 ;
     RECT  2.16 146.745 170.64 147.015 ;
     RECT  2.16 147.285 170.64 147.555 ;
     RECT  2.16 147.825 170.64 148.095 ;
     RECT  2.16 148.365 170.64 148.635 ;
     RECT  2.16 148.905 170.64 149.175 ;
     RECT  2.16 149.445 170.64 149.715 ;
     RECT  2.16 149.985 170.64 150.255 ;
     RECT  2.16 150.525 170.64 150.795 ;
     RECT  2.16 151.065 170.64 151.335 ;
     RECT  2.16 151.605 170.64 151.875 ;
     RECT  2.16 152.145 170.64 152.415 ;
     RECT  2.16 152.685 170.64 152.955 ;
     RECT  2.16 153.225 170.64 153.495 ;
     RECT  2.16 153.765 170.64 154.035 ;
     RECT  2.16 154.305 170.64 154.575 ;
     RECT  2.16 154.845 170.64 155.115 ;
     RECT  2.16 155.385 170.64 155.655 ;
     RECT  2.16 155.925 170.64 156.195 ;
     RECT  2.16 156.465 170.64 156.735 ;
     RECT  2.16 157.005 170.64 157.275 ;
     RECT  2.16 157.545 170.64 157.815 ;
     RECT  2.16 158.085 170.64 158.355 ;
     RECT  2.16 158.625 170.64 158.895 ;
     RECT  2.16 159.165 170.64 159.435 ;
     RECT  2.16 159.705 170.64 159.975 ;
     RECT  2.16 160.245 170.64 160.515 ;
     RECT  2.16 160.785 170.64 161.055 ;
     RECT  2.16 161.325 170.64 161.595 ;
     RECT  2.16 161.865 170.64 162.135 ;
     RECT  2.16 162.405 170.64 162.675 ;
     RECT  2.16 162.945 170.64 163.215 ;
     RECT  2.16 163.485 170.64 163.755 ;
     RECT  2.16 164.025 170.64 164.295 ;
     RECT  2.16 164.565 170.64 164.835 ;
     RECT  2.16 165.105 170.64 165.375 ;
     RECT  2.16 165.645 170.64 165.915 ;
     RECT  2.16 166.185 170.64 166.455 ;
     RECT  2.16 166.725 170.64 166.995 ;
     RECT  2.16 167.265 170.64 167.535 ;
     RECT  2.16 167.805 170.64 168.075 ;
     RECT  2.16 168.345 170.64 168.615 ;
     RECT  2.16 168.885 170.64 169.155 ;
     RECT  2.16 169.425 170.64 169.695 ;
     RECT  2.16 169.965 170.64 170.235 ;
     RECT  2.16 170.505 170.64 170.64 ;
    LAYER RVTP ;
     RECT  2.16 2.295 170.64 2.565 ;
     RECT  2.16 2.835 170.64 3.105 ;
     RECT  2.16 3.375 170.64 3.645 ;
     RECT  2.16 3.915 170.64 4.185 ;
     RECT  2.16 4.455 170.64 4.725 ;
     RECT  2.16 4.995 170.64 5.265 ;
     RECT  2.16 5.535 170.64 5.805 ;
     RECT  2.16 6.075 170.64 6.345 ;
     RECT  2.16 6.615 170.64 6.885 ;
     RECT  2.16 7.155 170.64 7.425 ;
     RECT  2.16 7.695 170.64 7.965 ;
     RECT  2.16 8.235 170.64 8.505 ;
     RECT  2.16 8.775 170.64 9.045 ;
     RECT  2.16 9.315 170.64 9.585 ;
     RECT  2.16 9.855 170.64 10.125 ;
     RECT  2.16 10.395 170.64 10.665 ;
     RECT  2.16 10.935 170.64 11.205 ;
     RECT  2.16 11.475 170.64 11.745 ;
     RECT  2.16 12.015 170.64 12.285 ;
     RECT  2.16 12.555 170.64 12.825 ;
     RECT  2.16 13.095 170.64 13.365 ;
     RECT  2.16 13.635 170.64 13.905 ;
     RECT  2.16 14.175 170.64 14.445 ;
     RECT  2.16 14.715 170.64 14.985 ;
     RECT  2.16 15.255 170.64 15.525 ;
     RECT  2.16 15.795 170.64 16.065 ;
     RECT  2.16 16.335 170.64 16.605 ;
     RECT  2.16 16.875 170.64 17.145 ;
     RECT  2.16 17.415 170.64 17.685 ;
     RECT  2.16 17.955 170.64 18.225 ;
     RECT  2.16 18.495 170.64 18.765 ;
     RECT  2.16 19.035 170.64 19.305 ;
     RECT  2.16 19.575 170.64 19.845 ;
     RECT  2.16 20.115 170.64 20.385 ;
     RECT  2.16 20.655 170.64 20.925 ;
     RECT  2.16 21.195 170.64 21.465 ;
     RECT  2.16 21.735 170.64 22.005 ;
     RECT  2.16 22.275 170.64 22.545 ;
     RECT  2.16 22.815 170.64 23.085 ;
     RECT  2.16 23.355 170.64 23.625 ;
     RECT  2.16 23.895 170.64 24.165 ;
     RECT  2.16 24.435 170.64 24.705 ;
     RECT  2.16 24.975 170.64 25.245 ;
     RECT  2.16 25.515 170.64 25.785 ;
     RECT  2.16 26.055 170.64 26.325 ;
     RECT  2.16 26.595 170.64 26.865 ;
     RECT  2.16 27.135 170.64 27.405 ;
     RECT  2.16 27.675 170.64 27.945 ;
     RECT  2.16 28.215 170.64 28.485 ;
     RECT  2.16 28.755 170.64 29.025 ;
     RECT  2.16 29.295 170.64 29.565 ;
     RECT  2.16 29.835 170.64 30.105 ;
     RECT  2.16 30.375 170.64 30.645 ;
     RECT  2.16 30.915 170.64 31.185 ;
     RECT  2.16 31.455 170.64 31.725 ;
     RECT  2.16 31.995 170.64 32.265 ;
     RECT  2.16 32.535 170.64 32.805 ;
     RECT  2.16 33.075 170.64 33.345 ;
     RECT  2.16 33.615 170.64 33.885 ;
     RECT  2.16 34.155 170.64 34.425 ;
     RECT  2.16 34.695 170.64 34.965 ;
     RECT  2.16 35.235 170.64 35.505 ;
     RECT  2.16 35.775 170.64 36.045 ;
     RECT  2.16 36.315 170.64 36.585 ;
     RECT  2.16 36.855 170.64 37.125 ;
     RECT  2.16 37.395 170.64 37.665 ;
     RECT  2.16 37.935 170.64 38.205 ;
     RECT  2.16 38.475 170.64 38.745 ;
     RECT  2.16 39.015 170.64 39.285 ;
     RECT  2.16 39.555 170.64 39.825 ;
     RECT  2.16 40.095 170.64 40.365 ;
     RECT  2.16 40.635 170.64 40.905 ;
     RECT  2.16 41.175 170.64 41.445 ;
     RECT  2.16 41.715 170.64 41.985 ;
     RECT  2.16 42.255 170.64 42.525 ;
     RECT  2.16 42.795 170.64 43.065 ;
     RECT  2.16 43.335 170.64 43.605 ;
     RECT  2.16 43.875 170.64 44.145 ;
     RECT  2.16 44.415 170.64 44.685 ;
     RECT  2.16 44.955 170.64 45.225 ;
     RECT  2.16 45.495 170.64 45.765 ;
     RECT  2.16 46.035 170.64 46.305 ;
     RECT  2.16 46.575 170.64 46.845 ;
     RECT  2.16 47.115 170.64 47.385 ;
     RECT  2.16 47.655 170.64 47.925 ;
     RECT  2.16 48.195 170.64 48.465 ;
     RECT  2.16 48.735 170.64 49.005 ;
     RECT  2.16 49.275 170.64 49.545 ;
     RECT  2.16 49.815 170.64 50.085 ;
     RECT  2.16 50.355 170.64 50.625 ;
     RECT  2.16 50.895 170.64 51.165 ;
     RECT  2.16 51.435 170.64 51.705 ;
     RECT  2.16 51.975 170.64 52.245 ;
     RECT  2.16 52.515 170.64 52.785 ;
     RECT  2.16 53.055 170.64 53.325 ;
     RECT  2.16 53.595 170.64 53.865 ;
     RECT  2.16 54.135 170.64 54.405 ;
     RECT  2.16 54.675 170.64 54.945 ;
     RECT  2.16 55.215 170.64 55.485 ;
     RECT  2.16 55.755 170.64 56.025 ;
     RECT  2.16 56.295 170.64 56.565 ;
     RECT  2.16 56.835 170.64 57.105 ;
     RECT  2.16 57.375 170.64 57.645 ;
     RECT  2.16 57.915 170.64 58.185 ;
     RECT  2.16 58.455 170.64 58.725 ;
     RECT  2.16 58.995 170.64 59.265 ;
     RECT  2.16 59.535 170.64 59.805 ;
     RECT  2.16 60.075 170.64 60.345 ;
     RECT  2.16 60.615 170.64 60.885 ;
     RECT  2.16 61.155 170.64 61.425 ;
     RECT  2.16 61.695 170.64 61.965 ;
     RECT  2.16 62.235 170.64 62.505 ;
     RECT  2.16 62.775 170.64 63.045 ;
     RECT  2.16 63.315 170.64 63.585 ;
     RECT  2.16 63.855 170.64 64.125 ;
     RECT  2.16 64.395 170.64 64.665 ;
     RECT  2.16 64.935 170.64 65.205 ;
     RECT  2.16 65.475 170.64 65.745 ;
     RECT  2.16 66.015 170.64 66.285 ;
     RECT  2.16 66.555 170.64 66.825 ;
     RECT  2.16 67.095 170.64 67.365 ;
     RECT  2.16 67.635 170.64 67.905 ;
     RECT  2.16 68.175 170.64 68.445 ;
     RECT  2.16 68.715 170.64 68.985 ;
     RECT  2.16 69.255 170.64 69.525 ;
     RECT  2.16 69.795 170.64 70.065 ;
     RECT  2.16 70.335 170.64 70.605 ;
     RECT  2.16 70.875 170.64 71.145 ;
     RECT  2.16 71.415 170.64 71.685 ;
     RECT  2.16 71.955 170.64 72.225 ;
     RECT  2.16 72.495 170.64 72.765 ;
     RECT  2.16 73.035 170.64 73.305 ;
     RECT  2.16 73.575 170.64 73.845 ;
     RECT  2.16 74.115 170.64 74.385 ;
     RECT  2.16 74.655 170.64 74.925 ;
     RECT  2.16 75.195 170.64 75.465 ;
     RECT  2.16 75.735 170.64 76.005 ;
     RECT  2.16 76.275 170.64 76.545 ;
     RECT  2.16 76.815 170.64 77.085 ;
     RECT  2.16 77.355 170.64 77.625 ;
     RECT  2.16 77.895 170.64 78.165 ;
     RECT  2.16 78.435 170.64 78.705 ;
     RECT  2.16 78.975 170.64 79.245 ;
     RECT  2.16 79.515 170.64 79.785 ;
     RECT  2.16 80.055 170.64 80.325 ;
     RECT  2.16 80.595 170.64 80.865 ;
     RECT  2.16 81.135 170.64 81.405 ;
     RECT  2.16 81.675 170.64 81.945 ;
     RECT  2.16 82.215 170.64 82.485 ;
     RECT  2.16 82.755 170.64 83.025 ;
     RECT  2.16 83.295 170.64 83.565 ;
     RECT  2.16 83.835 170.64 84.105 ;
     RECT  2.16 84.375 170.64 84.645 ;
     RECT  2.16 84.915 170.64 85.185 ;
     RECT  2.16 85.455 170.64 85.725 ;
     RECT  2.16 85.995 170.64 86.265 ;
     RECT  2.16 86.535 170.64 86.805 ;
     RECT  2.16 87.075 170.64 87.345 ;
     RECT  2.16 87.615 170.64 87.885 ;
     RECT  2.16 88.155 170.64 88.425 ;
     RECT  2.16 88.695 170.64 88.965 ;
     RECT  2.16 89.235 170.64 89.505 ;
     RECT  2.16 89.775 170.64 90.045 ;
     RECT  2.16 90.315 170.64 90.585 ;
     RECT  2.16 90.855 170.64 91.125 ;
     RECT  2.16 91.395 170.64 91.665 ;
     RECT  2.16 91.935 170.64 92.205 ;
     RECT  2.16 92.475 170.64 92.745 ;
     RECT  2.16 93.015 170.64 93.285 ;
     RECT  2.16 93.555 170.64 93.825 ;
     RECT  2.16 94.095 170.64 94.365 ;
     RECT  2.16 94.635 170.64 94.905 ;
     RECT  2.16 95.175 170.64 95.445 ;
     RECT  2.16 95.715 170.64 95.985 ;
     RECT  2.16 96.255 170.64 96.525 ;
     RECT  2.16 96.795 170.64 97.065 ;
     RECT  2.16 97.335 170.64 97.605 ;
     RECT  2.16 97.875 170.64 98.145 ;
     RECT  2.16 98.415 170.64 98.685 ;
     RECT  2.16 98.955 170.64 99.225 ;
     RECT  2.16 99.495 170.64 99.765 ;
     RECT  2.16 100.035 170.64 100.305 ;
     RECT  2.16 100.575 170.64 100.845 ;
     RECT  2.16 101.115 170.64 101.385 ;
     RECT  2.16 101.655 170.64 101.925 ;
     RECT  2.16 102.195 170.64 102.465 ;
     RECT  2.16 102.735 170.64 103.005 ;
     RECT  2.16 103.275 170.64 103.545 ;
     RECT  2.16 103.815 170.64 104.085 ;
     RECT  2.16 104.355 170.64 104.625 ;
     RECT  2.16 104.895 170.64 105.165 ;
     RECT  2.16 105.435 170.64 105.705 ;
     RECT  2.16 105.975 170.64 106.245 ;
     RECT  2.16 106.515 170.64 106.785 ;
     RECT  2.16 107.055 170.64 107.325 ;
     RECT  2.16 107.595 170.64 107.865 ;
     RECT  2.16 108.135 170.64 108.405 ;
     RECT  2.16 108.675 170.64 108.945 ;
     RECT  2.16 109.215 170.64 109.485 ;
     RECT  2.16 109.755 170.64 110.025 ;
     RECT  2.16 110.295 170.64 110.565 ;
     RECT  2.16 110.835 170.64 111.105 ;
     RECT  2.16 111.375 170.64 111.645 ;
     RECT  2.16 111.915 170.64 112.185 ;
     RECT  2.16 112.455 170.64 112.725 ;
     RECT  2.16 112.995 170.64 113.265 ;
     RECT  2.16 113.535 170.64 113.805 ;
     RECT  2.16 114.075 170.64 114.345 ;
     RECT  2.16 114.615 170.64 114.885 ;
     RECT  2.16 115.155 170.64 115.425 ;
     RECT  2.16 115.695 170.64 115.965 ;
     RECT  2.16 116.235 170.64 116.505 ;
     RECT  2.16 116.775 170.64 117.045 ;
     RECT  2.16 117.315 170.64 117.585 ;
     RECT  2.16 117.855 170.64 118.125 ;
     RECT  2.16 118.395 170.64 118.665 ;
     RECT  2.16 118.935 170.64 119.205 ;
     RECT  2.16 119.475 170.64 119.745 ;
     RECT  2.16 120.015 170.64 120.285 ;
     RECT  2.16 120.555 170.64 120.825 ;
     RECT  2.16 121.095 170.64 121.365 ;
     RECT  2.16 121.635 170.64 121.905 ;
     RECT  2.16 122.175 170.64 122.445 ;
     RECT  2.16 122.715 170.64 122.985 ;
     RECT  2.16 123.255 170.64 123.525 ;
     RECT  2.16 123.795 170.64 124.065 ;
     RECT  2.16 124.335 170.64 124.605 ;
     RECT  2.16 124.875 170.64 125.145 ;
     RECT  2.16 125.415 170.64 125.685 ;
     RECT  2.16 125.955 170.64 126.225 ;
     RECT  2.16 126.495 170.64 126.765 ;
     RECT  2.16 127.035 170.64 127.305 ;
     RECT  2.16 127.575 170.64 127.845 ;
     RECT  2.16 128.115 170.64 128.385 ;
     RECT  2.16 128.655 170.64 128.925 ;
     RECT  2.16 129.195 170.64 129.465 ;
     RECT  2.16 129.735 170.64 130.005 ;
     RECT  2.16 130.275 170.64 130.545 ;
     RECT  2.16 130.815 170.64 131.085 ;
     RECT  2.16 131.355 170.64 131.625 ;
     RECT  2.16 131.895 170.64 132.165 ;
     RECT  2.16 132.435 170.64 132.705 ;
     RECT  2.16 132.975 170.64 133.245 ;
     RECT  2.16 133.515 170.64 133.785 ;
     RECT  2.16 134.055 170.64 134.325 ;
     RECT  2.16 134.595 170.64 134.865 ;
     RECT  2.16 135.135 170.64 135.405 ;
     RECT  2.16 135.675 170.64 135.945 ;
     RECT  2.16 136.215 170.64 136.485 ;
     RECT  2.16 136.755 170.64 137.025 ;
     RECT  2.16 137.295 170.64 137.565 ;
     RECT  2.16 137.835 170.64 138.105 ;
     RECT  2.16 138.375 170.64 138.645 ;
     RECT  2.16 138.915 170.64 139.185 ;
     RECT  2.16 139.455 170.64 139.725 ;
     RECT  2.16 139.995 170.64 140.265 ;
     RECT  2.16 140.535 170.64 140.805 ;
     RECT  2.16 141.075 170.64 141.345 ;
     RECT  2.16 141.615 170.64 141.885 ;
     RECT  2.16 142.155 170.64 142.425 ;
     RECT  2.16 142.695 170.64 142.965 ;
     RECT  2.16 143.235 170.64 143.505 ;
     RECT  2.16 143.775 170.64 144.045 ;
     RECT  2.16 144.315 170.64 144.585 ;
     RECT  2.16 144.855 170.64 145.125 ;
     RECT  2.16 145.395 170.64 145.665 ;
     RECT  2.16 145.935 170.64 146.205 ;
     RECT  2.16 146.475 170.64 146.745 ;
     RECT  2.16 147.015 170.64 147.285 ;
     RECT  2.16 147.555 170.64 147.825 ;
     RECT  2.16 148.095 170.64 148.365 ;
     RECT  2.16 148.635 170.64 148.905 ;
     RECT  2.16 149.175 170.64 149.445 ;
     RECT  2.16 149.715 170.64 149.985 ;
     RECT  2.16 150.255 170.64 150.525 ;
     RECT  2.16 150.795 170.64 151.065 ;
     RECT  2.16 151.335 170.64 151.605 ;
     RECT  2.16 151.875 170.64 152.145 ;
     RECT  2.16 152.415 170.64 152.685 ;
     RECT  2.16 152.955 170.64 153.225 ;
     RECT  2.16 153.495 170.64 153.765 ;
     RECT  2.16 154.035 170.64 154.305 ;
     RECT  2.16 154.575 170.64 154.845 ;
     RECT  2.16 155.115 170.64 155.385 ;
     RECT  2.16 155.655 170.64 155.925 ;
     RECT  2.16 156.195 170.64 156.465 ;
     RECT  2.16 156.735 170.64 157.005 ;
     RECT  2.16 157.275 170.64 157.545 ;
     RECT  2.16 157.815 170.64 158.085 ;
     RECT  2.16 158.355 170.64 158.625 ;
     RECT  2.16 158.895 170.64 159.165 ;
     RECT  2.16 159.435 170.64 159.705 ;
     RECT  2.16 159.975 170.64 160.245 ;
     RECT  2.16 160.515 170.64 160.785 ;
     RECT  2.16 161.055 170.64 161.325 ;
     RECT  2.16 161.595 170.64 161.865 ;
     RECT  2.16 162.135 170.64 162.405 ;
     RECT  2.16 162.675 170.64 162.945 ;
     RECT  2.16 163.215 170.64 163.485 ;
     RECT  2.16 163.755 170.64 164.025 ;
     RECT  2.16 164.295 170.64 164.565 ;
     RECT  2.16 164.835 170.64 165.105 ;
     RECT  2.16 165.375 170.64 165.645 ;
     RECT  2.16 165.915 170.64 166.185 ;
     RECT  2.16 166.455 170.64 166.725 ;
     RECT  2.16 166.995 170.64 167.265 ;
     RECT  2.16 167.535 170.64 167.805 ;
     RECT  2.16 168.075 170.64 168.345 ;
     RECT  2.16 168.615 170.64 168.885 ;
     RECT  2.16 169.155 170.64 169.425 ;
     RECT  2.16 169.695 170.64 169.965 ;
     RECT  2.16 170.235 170.64 170.505 ;
    LAYER M1 ;
     RECT  2.16 2.151 170.64 170.649 ;
    LAYER M2 ;
     RECT  2.16 2.151 60.871 170.649 ;
     RECT  60.871 2.106 61.231 170.649 ;
     RECT  62.131 1.152 62.231 1.17 ;
     RECT  61.231 2.034 63.455 170.649 ;
     RECT  63.455 2.106 64.823 170.649 ;
     RECT  64.823 2.151 67.567 170.649 ;
     RECT  67.567 2.07 72.103 170.649 ;
     RECT  72.103 2.034 74.695 170.649 ;
     RECT  74.695 1.881 79.115 170.649 ;
     RECT  79.115 1.962 79.187 170.649 ;
     RECT  79.187 2.034 80.599 170.649 ;
     RECT  80.599 1.998 81.635 170.649 ;
     RECT  81.635 2.034 84.919 170.649 ;
     RECT  84.919 1.962 85.379 170.649 ;
     RECT  85.379 2.034 95.639 170.649 ;
     RECT  95.639 2.106 106.591 170.649 ;
     RECT  106.591 2.034 116.195 170.649 ;
     RECT  116.195 2.151 170.64 170.649 ;
     RECT  170.64 73.386 171.563 102.924 ;
     RECT  171.563 73.386 171.599 79.848 ;
     RECT  171.563 99.504 171.599 102.834 ;
     RECT  171.599 73.512 171.635 79.848 ;
     RECT  171.563 89.046 172.103 98.64 ;
     RECT  171.599 99.738 172.103 102.834 ;
     RECT  171.635 74.826 172.139 79.848 ;
     RECT  171.563 80.64 172.139 87.984 ;
     RECT  172.103 89.046 172.139 94.86 ;
     RECT  172.103 95.796 172.139 98.64 ;
     RECT  172.103 99.738 172.139 102.762 ;
     RECT  171.635 73.512 172.175 73.638 ;
     RECT  172.139 74.826 172.175 78.66 ;
     RECT  172.139 79.596 172.175 79.848 ;
     RECT  172.139 80.64 172.175 86.094 ;
     RECT  172.139 89.586 172.175 91.224 ;
     RECT  172.139 95.796 172.175 96.786 ;
     RECT  172.139 99.738 172.175 101.142 ;
     RECT  172.139 101.934 172.175 102.528 ;
     RECT  172.175 73.62 172.211 73.638 ;
     RECT  172.175 75.366 172.211 78.426 ;
     RECT  172.175 79.83 172.211 79.848 ;
     RECT  172.175 80.64 172.211 82.854 ;
     RECT  172.175 84.582 172.211 85.986 ;
     RECT  172.139 92.106 172.247 94.86 ;
     RECT  172.175 95.796 172.607 96.318 ;
     RECT  172.607 95.796 172.643 96.21 ;
     RECT  172.211 75.366 172.679 78.084 ;
     RECT  172.211 80.64 172.679 82.044 ;
     RECT  172.211 85.23 172.679 85.95 ;
     RECT  172.247 93.906 172.679 94.86 ;
     RECT  172.643 95.958 172.679 96.084 ;
     RECT  172.139 97.812 172.679 98.64 ;
     RECT  172.679 75.366 172.715 76.374 ;
     RECT  172.679 77.364 172.715 77.994 ;
     RECT  172.679 80.64 172.715 80.658 ;
     RECT  172.679 81.486 172.715 82.044 ;
     RECT  172.211 82.836 172.715 82.854 ;
     RECT  172.679 85.23 172.715 85.752 ;
     RECT  172.139 87.012 172.715 87.03 ;
     RECT  172.139 87.966 172.715 87.984 ;
     RECT  172.175 89.856 172.715 91.224 ;
     RECT  172.247 92.106 172.715 92.736 ;
     RECT  172.679 93.906 172.715 93.924 ;
     RECT  172.679 94.842 172.715 94.86 ;
     RECT  172.679 96.066 172.715 96.084 ;
     RECT  172.679 97.812 172.715 98.514 ;
     RECT  172.175 101.124 172.715 101.142 ;
     RECT  172.175 101.934 172.715 101.952 ;
    LAYER M3 ;
     RECT  61.488 0.091 61.506 0.139 ;
     RECT  86.58 0.091 86.598 0.139 ;
     RECT  89.172 0.091 89.37 0.221 ;
     RECT  94.788 0.091 94.806 0.317 ;
     RECT  61.2 0.139 61.506 0.571 ;
     RECT  83.268 0.427 83.286 0.571 ;
     RECT  83.268 0.571 83.862 0.605 ;
     RECT  62.604 0.091 62.622 0.667 ;
     RECT  61.2 0.571 61.578 1.003 ;
     RECT  62.46 0.667 62.622 1.003 ;
     RECT  61.2 1.003 62.622 1.099 ;
     RECT  107.316 0.523 107.334 1.099 ;
     RECT  98.136 0.571 98.154 1.147 ;
     RECT  60.84 1.099 62.622 1.723 ;
     RECT  63.576 1.099 63.594 1.723 ;
     RECT  68.328 0.523 68.346 1.723 ;
     RECT  69.588 0.091 69.606 1.723 ;
     RECT  74.736 1.675 74.754 1.723 ;
     RECT  75.6 0.091 75.618 1.723 ;
     RECT  77.292 1.099 77.31 1.723 ;
     RECT  78.696 0.523 78.714 1.723 ;
     RECT  83.844 0.605 83.862 1.723 ;
     RECT  86.58 0.139 86.814 1.723 ;
     RECT  90.468 1.675 90.486 1.723 ;
     RECT  92.52 1.099 92.538 1.723 ;
     RECT  97.452 1.147 98.154 1.723 ;
     RECT  106.128 1.099 106.146 1.723 ;
     RECT  107.316 1.099 107.73 1.723 ;
     RECT  108.792 1.099 108.81 1.723 ;
     RECT  110.304 1.675 110.322 1.723 ;
     RECT  60.84 1.723 75.618 1.771 ;
     RECT  76.5 1.723 78.714 1.771 ;
     RECT  80.532 1.723 80.694 1.771 ;
     RECT  87.696 1.723 88.506 1.771 ;
     RECT  89.46 1.723 95.346 1.771 ;
     RECT  96.264 1.723 100.458 1.771 ;
     RECT  101.664 1.723 103.014 1.771 ;
     RECT  104.076 1.723 104.634 1.771 ;
     RECT  105.372 1.723 114.138 1.771 ;
     RECT  115.524 1.723 115.542 1.771 ;
     RECT  80.28 1.771 80.694 1.819 ;
     RECT  104.076 1.771 114.462 1.819 ;
     RECT  115.524 1.771 116.082 1.819 ;
     RECT  101.304 1.771 103.014 1.867 ;
     RECT  60.84 1.771 78.714 1.876 ;
     RECT  79.56 1.819 80.694 1.876 ;
     RECT  81.972 1.723 82.782 1.963 ;
     RECT  83.556 1.723 83.862 1.963 ;
     RECT  81.972 1.963 83.862 1.993 ;
     RECT  81.612 1.993 83.862 2.011 ;
     RECT  84.636 1.723 86.814 2.011 ;
     RECT  104.076 1.819 116.082 2.029 ;
     RECT  87.696 1.771 100.458 2.101 ;
     RECT  87.624 2.101 100.458 2.191 ;
     RECT  101.268 1.867 103.014 2.191 ;
     RECT  104.076 2.029 116.19 2.191 ;
     RECT  81.612 2.011 86.814 2.251 ;
     RECT  87.624 2.191 116.19 2.251 ;
     RECT  60.84 1.876 80.694 2.299 ;
     RECT  81.504 2.251 116.19 2.299 ;
     RECT  60.84 2.299 116.19 2.371 ;
     RECT  2.415 2.143 2.505 2.413 ;
     RECT  7.815 2.143 7.905 2.413 ;
     RECT  13.215 2.143 13.305 2.413 ;
     RECT  18.615 2.143 18.705 2.413 ;
     RECT  24.015 2.143 24.105 2.413 ;
     RECT  29.415 2.143 29.505 2.413 ;
     RECT  34.815 2.143 34.905 2.413 ;
     RECT  40.215 2.143 40.305 2.413 ;
     RECT  45.615 2.143 45.705 2.413 ;
     RECT  51.015 2.143 51.105 2.413 ;
     RECT  56.415 2.143 56.505 2.413 ;
     RECT  121.215 2.143 121.305 2.413 ;
     RECT  126.615 2.143 126.705 2.413 ;
     RECT  132.015 2.143 132.105 2.413 ;
     RECT  137.415 2.143 137.505 2.413 ;
     RECT  142.815 2.143 142.905 2.413 ;
     RECT  148.215 2.143 148.305 2.413 ;
     RECT  153.615 2.143 153.705 2.413 ;
     RECT  159.015 2.143 159.105 2.413 ;
     RECT  164.415 2.143 164.505 2.413 ;
     RECT  169.815 2.143 169.905 2.413 ;
     RECT  60.84 2.371 116.406 2.461 ;
     RECT  60.696 2.461 116.406 2.641 ;
     RECT  60.696 2.641 116.838 3.721 ;
     RECT  60.696 3.721 116.946 4.531 ;
     RECT  60.696 4.531 117.414 4.555 ;
     RECT  59.976 4.555 117.414 4.685 ;
     RECT  60.12 4.685 117.414 5.099 ;
     RECT  60.804 5.099 117.414 5.189 ;
     RECT  61.452 5.189 117.414 5.369 ;
     RECT  61.56 5.369 117.414 5.999 ;
     RECT  61.815 5.999 117.414 8.159 ;
     RECT  61.815 8.159 65.358 11.245 ;
     RECT  66.276 8.159 117.414 11.245 ;
     RECT  61.815 11.245 117.414 11.399 ;
     RECT  66.276 11.399 117.414 13.055 ;
     RECT  66.276 13.055 69.282 14.009 ;
     RECT  66.312 14.009 69.282 14.611 ;
     RECT  70.056 13.055 117.414 14.611 ;
     RECT  66.312 14.611 117.414 14.711 ;
     RECT  70.056 14.711 117.414 15.719 ;
     RECT  70.056 15.719 97.398 22.235 ;
     RECT  70.056 22.235 74.97 25.349 ;
     RECT  98.244 15.719 117.414 34.591 ;
     RECT  98.208 34.591 117.414 34.637 ;
     RECT  98.244 34.637 117.414 36.581 ;
     RECT  72.54 25.349 74.97 37.625 ;
     RECT  98.244 36.581 116.658 40.603 ;
     RECT  117.396 36.581 117.414 40.603 ;
     RECT  126.615 2.413 126.897 42.421 ;
     RECT  126.324 42.421 126.897 42.461 ;
     RECT  126.396 42.461 126.897 43.169 ;
     RECT  126.504 43.169 126.897 43.325 ;
     RECT  98.244 40.603 117.414 48.811 ;
     RECT  75.708 22.235 97.398 61.727 ;
     RECT  75.924 61.727 97.398 61.889 ;
     RECT  97.236 61.889 97.398 62.041 ;
     RECT  97.236 62.041 97.506 62.977 ;
     RECT  98.244 48.811 117.558 62.977 ;
     RECT  73.656 37.625 74.97 63.085 ;
     RECT  73.656 63.085 75.186 63.239 ;
     RECT  75.924 61.889 96.426 63.661 ;
     RECT  97.236 62.977 117.558 63.661 ;
     RECT  73.656 63.239 74.79 65.563 ;
     RECT  73.656 65.563 74.826 65.669 ;
     RECT  61.815 11.399 65.358 65.821 ;
     RECT  70.056 25.349 71.514 65.983 ;
     RECT  61.815 65.821 65.466 66.119 ;
     RECT  61.815 66.119 65.358 66.209 ;
     RECT  62.856 66.209 65.358 66.479 ;
     RECT  75.924 63.661 117.558 66.479 ;
     RECT  63.18 66.479 65.358 66.749 ;
     RECT  63.396 66.749 65.358 67.019 ;
     RECT  64.476 67.019 65.358 67.289 ;
     RECT  64.476 67.289 64.998 67.361 ;
     RECT  64.476 67.361 64.566 67.559 ;
     RECT  75.924 66.479 76.806 68.099 ;
     RECT  64.476 67.559 64.494 69.863 ;
     RECT  75.924 68.099 76.59 69.899 ;
     RECT  66.312 14.711 69.282 70.979 ;
     RECT  73.656 65.669 74.79 71.609 ;
     RECT  66.492 70.979 69.282 72.059 ;
     RECT  66.6 72.059 69.282 72.599 ;
     RECT  169.815 2.413 170.097 73.309 ;
     RECT  77.868 66.479 117.558 73.345 ;
     RECT  169.74 73.309 170.097 73.381 ;
     RECT  171.576 73.381 171.594 73.471 ;
     RECT  76.572 69.899 76.59 73.499 ;
     RECT  77.724 73.345 117.558 73.499 ;
     RECT  171 73.471 171.594 73.507 ;
     RECT  167.076 73.381 168.246 73.543 ;
     RECT  169.452 73.381 170.097 73.543 ;
     RECT  171 73.507 172.17 73.543 ;
     RECT  166.536 73.543 168.246 73.579 ;
     RECT  166.536 73.579 168.354 73.615 ;
     RECT  169.452 73.543 172.17 73.615 ;
     RECT  164.415 2.413 164.697 73.651 ;
     RECT  166.032 73.615 168.354 73.651 ;
     RECT  169.452 73.615 172.206 73.651 ;
     RECT  118.476 73.579 118.494 73.679 ;
     RECT  164.415 73.651 165.186 73.741 ;
     RECT  164.196 73.741 165.186 73.777 ;
     RECT  74.304 71.609 74.79 73.841 ;
     RECT  164.16 73.777 165.186 73.877 ;
     RECT  166.032 73.651 172.206 73.997 ;
     RECT  74.304 73.841 74.322 74.039 ;
     RECT  164.16 73.877 164.826 74.039 ;
     RECT  166.032 73.997 171.63 74.111 ;
     RECT  166.032 74.111 168.498 74.191 ;
     RECT  72.54 37.625 72.897 74.309 ;
     RECT  118.584 74.191 118.602 74.309 ;
     RECT  169.272 74.111 171.63 74.381 ;
     RECT  165.996 74.191 168.498 74.461 ;
     RECT  118.548 74.425 118.566 74.579 ;
     RECT  162.468 74.461 162.486 74.651 ;
     RECT  163.404 74.587 163.566 74.687 ;
     RECT  163.548 74.687 163.566 74.759 ;
     RECT  165.924 74.461 168.498 74.821 ;
     RECT  171.54 74.381 171.63 74.821 ;
     RECT  162.504 74.695 162.594 74.849 ;
     RECT  164.415 74.039 164.826 74.857 ;
     RECT  163.728 74.857 164.826 74.875 ;
     RECT  165.888 74.821 168.498 74.875 ;
     RECT  77.868 73.499 117.558 74.993 ;
     RECT  169.272 74.381 170.442 74.993 ;
     RECT  161.316 74.551 161.334 75.029 ;
     RECT  169.815 74.993 170.442 75.029 ;
     RECT  163.728 74.875 168.498 75.119 ;
     RECT  162.504 74.849 162.558 75.155 ;
     RECT  171.54 74.821 172.17 75.199 ;
     RECT  171 75.199 172.17 75.245 ;
     RECT  171.54 75.245 172.17 75.307 ;
     RECT  163.728 75.119 165.978 75.389 ;
     RECT  165.888 75.389 165.978 75.497 ;
     RECT  66.6 72.599 69.246 75.659 ;
     RECT  162.504 75.155 162.522 75.703 ;
     RECT  163.728 75.389 164.97 75.775 ;
     RECT  165.924 75.497 165.978 75.901 ;
     RECT  167.04 75.119 167.202 75.901 ;
     RECT  169.815 75.029 170.097 76.009 ;
     RECT  162.468 75.703 162.522 76.045 ;
     RECT  165.924 75.901 167.202 76.073 ;
     RECT  162.468 76.045 162.558 76.081 ;
     RECT  168.156 75.119 168.498 76.081 ;
     RECT  165.924 76.073 166.05 76.199 ;
     RECT  169.776 76.009 170.097 76.199 ;
     RECT  168.156 76.081 168.642 76.271 ;
     RECT  168.228 76.271 168.642 76.307 ;
     RECT  171.54 75.307 172.71 76.307 ;
     RECT  163.692 75.775 164.97 76.315 ;
     RECT  165.924 76.199 166.014 76.315 ;
     RECT  162.468 76.081 162.63 76.343 ;
     RECT  163.692 76.315 166.014 76.349 ;
     RECT  162.468 76.343 162.594 76.379 ;
     RECT  172.044 76.307 172.71 76.379 ;
     RECT  70.056 65.983 71.55 76.469 ;
     RECT  170.964 76.459 170.982 76.505 ;
     RECT  166.86 76.073 167.202 76.541 ;
     RECT  121.215 2.413 121.497 76.603 ;
     RECT  132.015 2.413 132.297 76.603 ;
     RECT  142.815 2.413 143.097 76.603 ;
     RECT  153.615 2.413 153.897 76.603 ;
     RECT  168.444 76.307 168.642 76.621 ;
     RECT  162.468 76.379 162.486 76.637 ;
     RECT  121.104 76.603 121.497 76.649 ;
     RECT  131.904 76.603 132.297 76.649 ;
     RECT  142.704 76.603 143.097 76.649 ;
     RECT  153.504 76.603 153.897 76.649 ;
     RECT  164.415 76.349 166.014 76.649 ;
     RECT  165.528 76.649 166.014 76.739 ;
     RECT  168.444 76.621 168.678 76.981 ;
     RECT  169.815 76.199 170.097 76.981 ;
     RECT  166.896 76.541 167.202 77.017 ;
     RECT  166.896 77.017 167.238 77.053 ;
     RECT  168.444 76.981 170.097 77.125 ;
     RECT  163.548 77.125 163.566 77.161 ;
     RECT  164.415 76.649 164.79 77.161 ;
     RECT  166.896 77.053 167.274 77.359 ;
     RECT  168.228 77.125 170.097 77.359 ;
     RECT  172.044 76.379 172.674 77.359 ;
     RECT  165.996 76.739 166.014 77.431 ;
     RECT  166.896 77.359 170.097 77.431 ;
     RECT  165.996 77.431 170.097 77.515 ;
     RECT  163.548 77.161 164.79 77.521 ;
     RECT  165.528 77.515 170.097 77.521 ;
     RECT  172.044 77.359 172.71 77.611 ;
     RECT  159.015 2.413 159.297 77.629 ;
     RECT  171.54 77.611 172.71 77.701 ;
     RECT  171 77.701 172.71 77.741 ;
     RECT  71.244 76.469 71.55 77.819 ;
     RECT  80.424 74.993 117.558 77.827 ;
     RECT  162.468 77.629 162.486 77.963 ;
     RECT  163.548 77.521 170.097 78.089 ;
     RECT  163.548 78.089 167.382 78.233 ;
     RECT  163.548 78.233 166.23 78.269 ;
     RECT  171.576 77.741 172.71 78.317 ;
     RECT  67.215 75.659 69.246 78.395 ;
     RECT  167.184 78.233 167.382 78.395 ;
     RECT  171.576 78.317 172.674 78.413 ;
     RECT  168.336 78.089 170.097 78.439 ;
     RECT  164.415 78.269 166.23 78.467 ;
     RECT  159.015 77.629 159.678 78.503 ;
     RECT  171.576 78.413 172.242 78.509 ;
     RECT  171.576 78.509 172.206 78.893 ;
     RECT  162.504 78.709 162.522 78.907 ;
     RECT  168.336 78.439 170.37 78.979 ;
     RECT  171.576 78.893 172.17 78.979 ;
     RECT  167.184 78.395 167.346 79.015 ;
     RECT  168.336 78.979 172.17 79.051 ;
     RECT  77.868 74.993 79.362 79.169 ;
     RECT  168.192 79.051 172.17 79.195 ;
     RECT  162.468 78.907 162.522 79.243 ;
     RECT  164.415 78.467 165.87 79.249 ;
     RECT  162.468 79.243 162.63 79.283 ;
     RECT  167.148 79.015 167.346 79.285 ;
     RECT  162.54 79.283 162.63 79.312 ;
     RECT  156.204 78.943 156.222 79.313 ;
     RECT  80.28 77.827 117.558 79.321 ;
     RECT  163.548 78.269 163.566 79.411 ;
     RECT  164.415 79.249 166.23 79.411 ;
     RECT  167.148 79.285 167.418 79.411 ;
     RECT  65.556 79.321 65.574 79.439 ;
     RECT  163.476 79.411 163.566 79.483 ;
     RECT  164.415 79.411 167.418 79.483 ;
     RECT  168.156 79.195 172.17 79.483 ;
     RECT  71.532 77.819 71.55 79.519 ;
     RECT  80.208 79.321 117.558 79.547 ;
     RECT  67.215 78.395 68.814 79.591 ;
     RECT  80.28 79.547 117.558 79.619 ;
     RECT  67.215 79.591 68.922 79.717 ;
     RECT  80.352 79.619 117.558 79.757 ;
     RECT  163.476 79.483 172.17 79.757 ;
     RECT  164.052 79.757 172.17 79.825 ;
     RECT  67.215 79.717 69.246 80.023 ;
     RECT  70.056 76.469 70.434 80.023 ;
     RECT  162.54 79.312 162.666 80.023 ;
     RECT  80.388 79.757 117.558 80.093 ;
     RECT  80.388 80.093 80.406 80.123 ;
     RECT  164.052 79.825 172.206 80.141 ;
     RECT  162.468 80.023 162.666 80.257 ;
     RECT  162.468 80.257 163.026 80.923 ;
     RECT  164.052 80.141 171.63 80.923 ;
     RECT  159.015 78.503 159.297 80.941 ;
     RECT  158.472 80.941 159.297 81.059 ;
     RECT  162.468 80.923 171.63 81.059 ;
     RECT  172.692 80.395 172.71 81.163 ;
     RECT  169.776 81.059 171.63 81.301 ;
     RECT  172.656 81.163 172.71 81.301 ;
     RECT  163.512 81.059 169.002 81.329 ;
     RECT  169.776 81.301 172.71 81.401 ;
     RECT  81.288 80.093 117.558 81.595 ;
     RECT  80.208 81.337 80.226 81.607 ;
     RECT  165.708 81.329 169.002 81.635 ;
     RECT  171.54 81.401 172.71 81.779 ;
     RECT  165.78 81.635 169.002 81.821 ;
     RECT  165.78 81.821 167.418 81.869 ;
     RECT  168.156 81.821 169.002 81.979 ;
     RECT  169.776 81.401 170.514 81.979 ;
     RECT  162.468 81.059 162.63 82.111 ;
     RECT  163.512 81.329 164.898 82.111 ;
     RECT  162.468 82.111 164.898 82.205 ;
     RECT  81.216 81.595 117.558 82.213 ;
     RECT  168.156 81.979 170.514 82.213 ;
     RECT  78.015 79.169 79.362 82.219 ;
     RECT  80.136 81.607 80.226 82.219 ;
     RECT  71.244 79.519 71.55 82.291 ;
     RECT  78.015 82.219 80.226 82.291 ;
     RECT  81.036 82.213 117.558 82.291 ;
     RECT  168.156 82.213 171.018 82.481 ;
     RECT  172.116 81.779 172.71 82.507 ;
     RECT  163.764 82.205 164.898 82.603 ;
     RECT  165.816 81.869 167.418 82.603 ;
     RECT  71.244 82.291 71.802 82.651 ;
     RECT  121.215 76.649 121.497 82.651 ;
     RECT  132.015 76.649 132.297 82.651 ;
     RECT  142.815 76.649 143.097 82.651 ;
     RECT  153.615 76.649 153.897 82.651 ;
     RECT  71.172 82.651 71.802 82.687 ;
     RECT  72.615 74.309 72.897 82.687 ;
     RECT  163.764 82.603 167.418 82.723 ;
     RECT  168.156 82.481 170.442 82.723 ;
     RECT  171.504 82.507 172.71 82.859 ;
     RECT  171.504 82.859 172.206 82.949 ;
     RECT  163.764 82.723 170.442 82.957 ;
     RECT  171.54 82.949 172.206 83.021 ;
     RECT  121.104 82.651 121.497 83.117 ;
     RECT  131.904 82.651 132.297 83.117 ;
     RECT  142.704 82.651 143.097 83.117 ;
     RECT  153.504 82.651 153.897 83.117 ;
     RECT  163.692 82.957 170.442 83.179 ;
     RECT  163.512 83.179 170.442 83.219 ;
     RECT  159.015 81.059 159.297 83.299 ;
     RECT  158.508 83.299 159.297 83.399 ;
     RECT  163.512 83.219 165.402 83.461 ;
     RECT  162.468 82.205 162.594 83.515 ;
     RECT  163.44 83.461 165.402 83.515 ;
     RECT  73.836 83.569 73.854 83.759 ;
     RECT  75.168 83.497 75.186 83.911 ;
     RECT  162.468 83.515 165.402 83.947 ;
     RECT  166.392 83.219 170.442 83.947 ;
     RECT  162.468 83.947 170.442 84.001 ;
     RECT  171.54 83.021 172.17 84.001 ;
     RECT  74.808 83.911 75.186 84.029 ;
     RECT  74.88 84.029 75.186 84.137 ;
     RECT  67.215 80.023 70.434 84.145 ;
     RECT  71.172 82.687 72.897 84.145 ;
     RECT  67.215 84.145 72.897 84.181 ;
     RECT  73.728 83.767 73.746 84.181 ;
     RECT  74.952 84.137 75.186 84.299 ;
     RECT  76.068 84.073 76.086 84.577 ;
     RECT  162.468 84.001 172.17 84.577 ;
     RECT  118.548 84.613 118.566 84.649 ;
     RECT  162.468 84.577 172.206 84.713 ;
     RECT  118.548 84.649 118.638 84.721 ;
     RECT  118.476 84.721 118.638 84.749 ;
     RECT  118.476 84.749 118.494 84.839 ;
     RECT  165.636 84.713 172.206 84.845 ;
     RECT  162.468 84.713 164.862 84.875 ;
     RECT  165.636 84.845 170.442 84.911 ;
     RECT  171.576 84.845 172.206 85.099 ;
     RECT  165.636 84.911 170.097 85.109 ;
     RECT  166.716 85.109 170.097 85.289 ;
     RECT  165.636 85.109 165.654 85.379 ;
     RECT  77.256 83.731 77.274 85.387 ;
     RECT  78.015 82.291 117.558 85.387 ;
     RECT  171.576 85.099 172.71 85.579 ;
     RECT  171.54 85.579 172.71 85.649 ;
     RECT  172.116 85.649 172.71 85.757 ;
     RECT  67.215 84.181 73.746 85.765 ;
     RECT  163.44 84.875 164.862 85.765 ;
     RECT  76.068 84.577 76.122 85.801 ;
     RECT  77.256 85.387 117.558 85.801 ;
     RECT  166.716 85.289 169.038 85.891 ;
     RECT  172.116 85.757 172.674 85.955 ;
     RECT  171 85.891 171.018 85.997 ;
     RECT  162.468 84.875 162.666 86.063 ;
     RECT  166.32 85.891 169.038 86.189 ;
     RECT  167.58 86.189 169.038 86.269 ;
     RECT  169.815 85.289 170.097 86.269 ;
     RECT  163.44 85.765 165.474 86.341 ;
     RECT  166.32 86.189 166.77 86.341 ;
     RECT  76.068 85.801 117.558 86.459 ;
     RECT  170.964 86.059 170.982 86.539 ;
     RECT  163.44 86.341 166.77 86.575 ;
     RECT  162.468 86.063 162.558 86.611 ;
     RECT  167.58 86.269 170.097 86.635 ;
     RECT  170.892 86.539 170.982 86.635 ;
     RECT  162.144 86.611 162.558 86.809 ;
     RECT  167.58 86.635 170.982 86.827 ;
     RECT  172.116 85.955 172.206 86.827 ;
     RECT  167.58 86.827 172.206 86.923 ;
     RECT  163.404 86.575 166.77 87.149 ;
     RECT  163.44 87.149 166.77 87.241 ;
     RECT  167.58 86.923 172.71 87.241 ;
     RECT  162.144 86.809 162.594 87.421 ;
     RECT  162.144 87.421 162.63 87.539 ;
     RECT  63.396 67.019 63.702 87.583 ;
     RECT  61.815 66.209 62.097 87.655 ;
     RECT  76.068 86.459 85.878 87.781 ;
     RECT  163.44 87.241 172.71 87.809 ;
     RECT  66.42 81.571 66.438 87.853 ;
     RECT  76.068 87.781 85.914 87.961 ;
     RECT  86.652 86.459 117.558 87.961 ;
     RECT  172.692 87.809 172.71 87.989 ;
     RECT  163.44 87.809 171.594 88.013 ;
     RECT  61.524 87.655 62.097 88.051 ;
     RECT  162.144 87.539 162.522 88.115 ;
     RECT  159.015 83.399 159.297 88.123 ;
     RECT  163.44 88.013 171.558 88.195 ;
     RECT  64.728 79.591 64.746 88.231 ;
     RECT  76.068 87.961 117.558 88.349 ;
     RECT  61.524 88.051 62.55 88.465 ;
     RECT  163.296 88.195 171.558 88.589 ;
     RECT  163.296 88.589 170.097 88.619 ;
     RECT  170.964 88.589 171.558 88.691 ;
     RECT  158.508 88.123 159.297 88.699 ;
     RECT  163.8 88.619 170.097 88.799 ;
     RECT  171 88.691 171.558 88.843 ;
     RECT  158.472 88.699 159.297 88.889 ;
     RECT  168.192 88.799 170.097 88.889 ;
     RECT  61.308 88.465 62.55 88.897 ;
     RECT  162.144 88.115 162.162 89.005 ;
     RECT  2.415 2.413 2.697 89.032 ;
     RECT  13.215 2.413 13.497 89.032 ;
     RECT  24.015 2.413 24.297 89.032 ;
     RECT  34.815 2.413 35.097 89.032 ;
     RECT  45.615 2.413 45.897 89.032 ;
     RECT  56.415 2.413 56.697 89.035 ;
     RECT  60.012 88.891 60.03 89.041 ;
     RECT  60.84 88.897 62.55 89.041 ;
     RECT  2.304 89.032 2.697 89.069 ;
     RECT  13.104 89.032 13.497 89.069 ;
     RECT  23.904 89.032 24.297 89.069 ;
     RECT  34.704 89.032 35.097 89.069 ;
     RECT  45.504 89.032 45.897 89.069 ;
     RECT  171 88.843 172.134 89.131 ;
     RECT  162.144 89.005 162.558 89.167 ;
     RECT  56.304 89.035 56.697 89.195 ;
     RECT  171 89.131 172.53 89.227 ;
     RECT  58.068 89.275 58.086 89.311 ;
     RECT  58.068 89.311 58.77 89.401 ;
     RECT  60.012 89.041 62.55 89.401 ;
     RECT  58.068 89.401 62.55 89.437 ;
     RECT  57.924 89.437 62.55 89.465 ;
     RECT  163.8 88.799 167.382 89.473 ;
     RECT  57.924 89.465 58.482 89.501 ;
     RECT  163.548 89.473 167.382 89.501 ;
     RECT  171 89.227 172.71 89.515 ;
     RECT  168.372 88.889 170.097 89.545 ;
     RECT  170.964 89.515 172.71 89.545 ;
     RECT  59.472 89.465 62.55 89.581 ;
     RECT  63.396 87.583 63.918 89.581 ;
     RECT  164.376 89.501 167.382 89.671 ;
     RECT  168.372 89.545 172.71 89.671 ;
     RECT  59.472 89.581 63.918 89.699 ;
     RECT  59.472 89.699 60.426 89.735 ;
     RECT  162.144 89.167 162.594 89.771 ;
     RECT  163.548 89.501 163.638 89.803 ;
     RECT  162.144 89.771 162.486 89.807 ;
     RECT  61.236 89.699 62.586 89.843 ;
     RECT  163.404 89.803 163.638 89.843 ;
     RECT  164.376 89.671 172.71 89.879 ;
     RECT  163.548 89.843 163.638 90.029 ;
     RECT  170.964 89.879 172.71 90.029 ;
     RECT  76.068 88.349 85.302 90.121 ;
     RECT  86.328 88.349 117.558 90.121 ;
     RECT  59.868 89.735 60.426 90.239 ;
     RECT  161.316 89.941 161.334 90.239 ;
     RECT  59.868 90.239 59.886 90.269 ;
     RECT  63.396 89.699 63.918 90.391 ;
     RECT  64.728 88.231 65.214 90.391 ;
     RECT  164.376 89.879 170.097 90.391 ;
     RECT  76.068 90.121 117.558 90.419 ;
     RECT  163.728 90.391 170.097 90.419 ;
     RECT  61.452 89.843 62.586 90.481 ;
     RECT  63.396 90.391 65.214 90.481 ;
     RECT  61.452 90.481 65.214 90.509 ;
     RECT  163.728 90.419 166.05 90.509 ;
     RECT  162.468 89.807 162.486 90.553 ;
     RECT  170.964 90.029 171.558 90.605 ;
     RECT  161.892 90.553 162.486 90.931 ;
     RECT  171.504 90.605 171.558 91.129 ;
     RECT  167.004 90.419 170.097 91.201 ;
     RECT  167.004 91.201 170.406 91.327 ;
     RECT  171.504 91.129 171.594 91.327 ;
     RECT  86.328 90.419 117.558 91.363 ;
     RECT  159.015 88.889 159.297 91.363 ;
     RECT  161.892 90.931 162.882 91.363 ;
     RECT  163.728 90.509 164.79 91.363 ;
     RECT  167.004 91.327 171.594 91.373 ;
     RECT  86.328 91.363 117.63 91.399 ;
     RECT  167.004 91.373 170.406 91.463 ;
     RECT  161.892 91.363 164.79 91.471 ;
     RECT  165.564 90.509 166.05 91.471 ;
     RECT  167.004 91.463 170.154 91.471 ;
     RECT  86.328 91.399 117.918 91.499 ;
     RECT  158.472 91.363 159.297 91.499 ;
     RECT  161.892 91.471 166.05 91.499 ;
     RECT  166.968 91.471 170.154 91.499 ;
     RECT  163.404 91.499 166.05 91.561 ;
     RECT  166.968 91.499 170.097 91.561 ;
     RECT  163.404 91.561 170.097 91.589 ;
     RECT  86.328 91.499 117.846 91.598 ;
     RECT  171.504 91.373 171.594 91.627 ;
     RECT  172.692 90.029 172.71 91.627 ;
     RECT  162.468 91.499 162.666 91.697 ;
     RECT  164.415 91.589 170.097 91.697 ;
     RECT  162.468 91.697 162.63 91.733 ;
     RECT  86.328 91.598 117.81 91.769 ;
     RECT  162.468 91.733 162.558 91.769 ;
     RECT  75.168 84.299 75.186 91.903 ;
     RECT  76.068 90.419 85.302 91.903 ;
     RECT  75.168 91.903 85.302 91.939 ;
     RECT  164.415 91.697 168.426 92.129 ;
     RECT  171.504 91.627 172.71 92.395 ;
     RECT  164.415 92.129 167.31 92.435 ;
     RECT  86.328 91.769 117.63 92.551 ;
     RECT  168.048 92.129 168.426 92.551 ;
     RECT  67.215 85.765 73.782 92.683 ;
     RECT  86.328 92.551 117.882 92.741 ;
     RECT  170.964 92.395 172.71 92.741 ;
     RECT  86.328 92.741 117.414 92.777 ;
     RECT  170.964 92.741 172.242 92.813 ;
     RECT  168.048 92.551 168.462 92.821 ;
     RECT  169.2 91.697 170.097 92.821 ;
     RECT  163.404 91.589 163.602 92.875 ;
     RECT  164.415 92.435 167.238 92.875 ;
     RECT  117.396 92.777 117.414 92.939 ;
     RECT  162.468 91.769 162.486 93.019 ;
     RECT  168.048 92.821 170.097 93.019 ;
     RECT  162.468 93.019 162.63 93.119 ;
     RECT  168.048 93.019 170.442 93.197 ;
     RECT  162.576 93.119 162.63 93.209 ;
     RECT  74.916 91.939 85.302 93.217 ;
     RECT  163.404 92.875 167.238 93.281 ;
     RECT  167.112 93.281 167.238 93.307 ;
     RECT  168.048 93.197 170.37 93.307 ;
     RECT  162.612 93.209 162.63 93.361 ;
     RECT  163.404 93.281 165.978 93.361 ;
     RECT  167.112 93.307 170.37 93.389 ;
     RECT  171.54 92.813 172.242 93.739 ;
     RECT  171.54 93.739 172.71 94.018 ;
     RECT  167.112 93.389 170.097 94.019 ;
     RECT  162.612 93.361 165.978 94.063 ;
     RECT  171.504 94.018 172.71 94.171 ;
     RECT  167.112 94.019 169.038 94.261 ;
     RECT  171 94.171 172.71 94.349 ;
     RECT  169.815 94.019 170.097 94.405 ;
     RECT  162.468 94.063 166.158 94.595 ;
     RECT  162.576 94.595 166.158 94.637 ;
     RECT  167.004 94.261 169.038 94.637 ;
     RECT  165.888 94.637 166.158 94.651 ;
     RECT  167.004 94.637 167.202 94.651 ;
     RECT  162.576 94.637 165.114 94.703 ;
     RECT  168.192 94.637 169.038 94.739 ;
     RECT  171.54 94.349 172.71 94.829 ;
     RECT  165.888 94.651 167.202 95.099 ;
     RECT  171.576 94.829 172.71 95.117 ;
     RECT  168.264 94.739 169.038 95.131 ;
     RECT  169.815 94.405 170.19 95.131 ;
     RECT  163.548 94.703 165.114 95.165 ;
     RECT  164.16 95.165 165.114 95.171 ;
     RECT  162.576 94.703 162.594 95.449 ;
     RECT  168.264 95.131 170.19 95.449 ;
     RECT  160.164 93.991 160.182 95.513 ;
     RECT  166.788 95.099 167.202 95.521 ;
     RECT  172.044 95.117 172.71 95.639 ;
     RECT  166.788 95.521 167.382 95.647 ;
     RECT  168.264 95.449 170.406 95.647 ;
     RECT  166.788 95.647 170.442 95.693 ;
     RECT  166.788 95.693 170.406 95.819 ;
     RECT  162.576 95.449 163.026 95.909 ;
     RECT  169.128 95.819 170.406 95.909 ;
     RECT  172.116 95.639 172.71 95.909 ;
     RECT  162.576 95.909 162.666 96.061 ;
     RECT  165.888 95.099 166.05 96.061 ;
     RECT  169.596 95.909 170.406 96.089 ;
     RECT  172.584 95.909 172.71 96.089 ;
     RECT  162.504 96.061 162.666 96.151 ;
     RECT  165.708 96.061 166.05 96.151 ;
     RECT  166.788 95.819 168.174 96.151 ;
     RECT  169.668 96.089 170.406 96.179 ;
     RECT  164.16 95.171 164.697 96.187 ;
     RECT  172.584 96.089 172.638 96.215 ;
     RECT  165.708 96.151 168.174 96.251 ;
     RECT  165.708 96.251 166.05 96.283 ;
     RECT  172.584 96.215 172.602 96.323 ;
     RECT  164.124 96.187 164.697 96.331 ;
     RECT  165.564 96.283 166.05 96.331 ;
     RECT  164.124 96.331 166.05 96.449 ;
     RECT  169.815 96.179 170.406 96.601 ;
     RECT  171.576 96.565 171.594 96.601 ;
     RECT  161.892 96.151 162.666 96.629 ;
     RECT  164.124 96.449 164.754 96.727 ;
     RECT  169.815 96.601 171.594 96.763 ;
     RECT  168.804 96.763 168.822 96.863 ;
     RECT  169.815 96.763 172.17 96.941 ;
     RECT  165.564 96.449 166.05 97.003 ;
     RECT  166.788 96.251 168.066 97.003 ;
     RECT  169.815 96.941 172.134 97.037 ;
     RECT  61.452 90.509 63.918 97.069 ;
     RECT  161.892 96.629 162.522 97.133 ;
     RECT  163.548 96.727 164.754 97.267 ;
     RECT  165.564 97.003 168.066 97.267 ;
     RECT  64.728 90.509 65.214 97.339 ;
     RECT  65.988 87.853 66.438 97.339 ;
     RECT  163.548 97.267 168.066 97.411 ;
     RECT  168.876 96.871 168.894 97.411 ;
     RECT  169.815 97.037 170.478 97.411 ;
     RECT  168.876 97.411 170.478 97.421 ;
     RECT  171.54 97.037 172.134 97.529 ;
     RECT  168.876 97.421 170.442 97.613 ;
     RECT  61.452 97.069 63.954 97.627 ;
     RECT  64.728 97.339 66.438 97.627 ;
     RECT  163.548 97.411 168.138 97.645 ;
     RECT  168.876 97.613 170.097 97.645 ;
     RECT  171.54 97.529 171.558 97.867 ;
     RECT  171.504 97.867 171.558 97.963 ;
     RECT  163.548 97.645 170.097 97.979 ;
     RECT  161.892 97.133 162.486 98.041 ;
     RECT  161.892 98.041 162.63 98.249 ;
     RECT  163.548 97.979 165.618 98.249 ;
     RECT  163.548 98.249 164.79 98.311 ;
     RECT  163.476 98.311 164.79 98.339 ;
     RECT  166.464 97.979 170.097 98.347 ;
     RECT  172.692 97.771 172.71 98.347 ;
     RECT  163.476 98.339 163.566 98.375 ;
     RECT  163.476 98.375 163.494 98.381 ;
     RECT  171.468 97.963 171.558 98.383 ;
     RECT  172.656 98.347 172.71 98.383 ;
     RECT  165.6 98.249 165.618 98.447 ;
     RECT  67.215 92.683 73.89 98.455 ;
     RECT  161.892 98.249 162.558 98.483 ;
     RECT  61.452 97.627 66.438 98.491 ;
     RECT  67.176 98.455 73.89 98.491 ;
     RECT  166.464 98.347 170.262 98.491 ;
     RECT  162.468 98.483 162.558 98.519 ;
     RECT  171.468 98.383 172.71 98.519 ;
     RECT  171.468 98.519 172.674 98.573 ;
     RECT  164.34 98.339 164.79 98.609 ;
     RECT  166.464 98.491 170.334 98.609 ;
     RECT  171.468 98.573 171.558 98.609 ;
     RECT  172.656 98.573 172.674 98.645 ;
     RECT  166.464 98.609 170.097 98.761 ;
     RECT  164.34 98.609 164.754 98.789 ;
     RECT  165.888 98.761 170.097 98.879 ;
     RECT  164.415 98.789 164.754 99.427 ;
     RECT  165.888 98.879 168.786 99.427 ;
     RECT  171.54 98.609 171.558 99.427 ;
     RECT  171 99.427 171.558 99.499 ;
     RECT  164.415 99.427 168.786 99.689 ;
     RECT  171 99.499 171.594 99.733 ;
     RECT  164.415 99.689 166.266 99.769 ;
     RECT  171 99.733 172.17 99.787 ;
     RECT  169.815 98.879 170.097 99.841 ;
     RECT  170.964 99.787 172.17 99.841 ;
     RECT  121.215 83.117 121.497 99.931 ;
     RECT  132.015 83.117 132.297 99.931 ;
     RECT  142.815 83.117 143.097 99.931 ;
     RECT  153.615 83.117 153.897 99.931 ;
     RECT  162.504 99.841 162.522 99.931 ;
     RECT  162.468 99.931 162.522 99.967 ;
     RECT  164.232 99.769 166.266 99.967 ;
     RECT  121.104 99.931 121.497 99.968 ;
     RECT  131.904 99.931 132.297 99.968 ;
     RECT  142.704 99.931 143.097 99.968 ;
     RECT  153.504 99.931 153.897 99.968 ;
     RECT  162.468 99.967 162.558 100.111 ;
     RECT  167.004 99.689 168.786 100.111 ;
     RECT  169.815 99.841 172.17 100.111 ;
     RECT  163.98 99.967 166.266 100.373 ;
     RECT  163.98 100.373 164.697 100.381 ;
     RECT  163.584 100.381 164.697 100.409 ;
     RECT  165.6 100.373 166.266 100.471 ;
     RECT  167.004 100.111 172.17 100.471 ;
     RECT  165.6 100.471 172.17 100.499 ;
     RECT  162.468 100.111 162.594 100.507 ;
     RECT  162.468 100.507 162.63 100.607 ;
     RECT  165.6 100.499 168.858 100.643 ;
     RECT  168.516 100.643 168.858 100.679 ;
     RECT  169.632 100.499 172.17 100.685 ;
     RECT  162.468 100.607 162.594 100.769 ;
     RECT  165.6 100.643 167.742 100.769 ;
     RECT  163.584 100.409 163.674 100.877 ;
     RECT  163.584 100.877 163.602 100.921 ;
     RECT  171.504 100.685 172.17 100.939 ;
     RECT  163.512 100.921 163.602 100.949 ;
     RECT  163.512 100.949 163.53 101.011 ;
     RECT  171.504 100.939 172.71 101.147 ;
     RECT  171.504 101.147 172.17 101.165 ;
     RECT  165.708 100.769 167.742 101.309 ;
     RECT  167.508 101.309 167.742 101.389 ;
     RECT  162.504 100.769 162.594 101.417 ;
     RECT  74.916 93.217 85.374 101.425 ;
     RECT  86.328 92.777 116.658 101.425 ;
     RECT  162.504 101.417 162.522 101.453 ;
     RECT  169.632 100.685 170.442 101.453 ;
     RECT  168.516 100.679 168.75 101.467 ;
     RECT  165.708 101.309 166.554 101.551 ;
     RECT  165.636 101.551 166.554 101.579 ;
     RECT  167.508 101.389 167.778 101.579 ;
     RECT  168.516 101.467 168.858 101.651 ;
     RECT  74.916 101.425 116.658 101.695 ;
     RECT  163.44 101.011 163.53 101.695 ;
     RECT  164.415 100.409 164.697 101.731 ;
     RECT  165.636 101.579 165.726 101.731 ;
     RECT  164.415 101.731 165.726 101.821 ;
     RECT  163.44 101.695 163.602 101.849 ;
     RECT  164.376 101.821 165.726 101.849 ;
     RECT  164.376 101.849 165.654 101.891 ;
     RECT  171.504 101.165 172.134 101.899 ;
     RECT  168.552 101.651 168.858 101.929 ;
     RECT  169.632 101.453 170.406 101.929 ;
     RECT  166.536 101.579 166.554 101.957 ;
     RECT  171.504 101.899 172.71 101.957 ;
     RECT  163.44 101.849 163.494 101.993 ;
     RECT  164.376 101.891 165.114 102.029 ;
     RECT  171.504 101.957 172.17 102.029 ;
     RECT  164.376 102.029 164.898 102.119 ;
     RECT  61.452 98.491 73.89 102.127 ;
     RECT  74.628 101.695 116.658 102.127 ;
     RECT  167.508 101.579 167.562 102.229 ;
     RECT  168.552 101.929 170.406 102.361 ;
     RECT  162.468 101.929 162.486 102.397 ;
     RECT  166.896 102.229 167.562 102.397 ;
     RECT  168.552 102.361 170.442 102.397 ;
     RECT  166.896 102.397 170.442 102.497 ;
     RECT  168.372 102.497 170.442 102.533 ;
     RECT  171.54 102.029 172.17 102.533 ;
     RECT  168.372 102.533 170.097 102.659 ;
     RECT  163.44 101.993 163.458 102.695 ;
     RECT  168.372 102.659 168.57 102.767 ;
     RECT  171.54 102.533 172.134 102.767 ;
     RECT  164.415 102.119 164.898 102.811 ;
     RECT  165.888 102.619 165.906 102.811 ;
     RECT  166.896 102.497 167.382 102.811 ;
     RECT  171.54 102.767 172.098 102.839 ;
     RECT  164.415 102.811 164.97 102.929 ;
     RECT  168.444 102.767 168.57 102.929 ;
     RECT  171.54 102.839 171.558 102.929 ;
     RECT  165.816 102.811 167.382 102.965 ;
     RECT  168.552 102.929 168.57 102.965 ;
     RECT  164.415 102.929 164.754 103.037 ;
     RECT  162.468 102.397 162.558 103.109 ;
     RECT  165.816 102.965 166.698 103.109 ;
     RECT  165.816 103.109 165.834 103.199 ;
     RECT  166.644 103.109 166.662 103.199 ;
     RECT  60.588 101.047 60.606 124.681 ;
     RECT  61.452 102.127 116.658 124.681 ;
     RECT  129.168 128.281 129.186 128.333 ;
     RECT  127.62 128.299 128.25 128.345 ;
     RECT  128.232 128.345 128.25 128.621 ;
     RECT  60.588 124.681 116.658 129.695 ;
     RECT  60.588 129.695 60.822 162.985 ;
     RECT  61.668 129.695 116.658 162.985 ;
     RECT  60.588 162.985 116.658 165.109 ;
     RECT  60.552 165.109 116.658 167.035 ;
     RECT  60.084 167.035 116.658 167.575 ;
     RECT  59.868 167.575 116.658 167.737 ;
     RECT  59.328 167.737 116.658 168.413 ;
     RECT  59.4 168.413 116.658 169.465 ;
     RECT  59.22 169.465 116.658 170.339 ;
     RECT  2.415 89.069 2.697 170.387 ;
     RECT  7.815 2.413 8.097 170.387 ;
     RECT  13.215 89.069 13.497 170.387 ;
     RECT  18.615 2.413 18.897 170.387 ;
     RECT  24.015 89.069 24.297 170.387 ;
     RECT  29.415 2.413 29.697 170.387 ;
     RECT  34.815 89.069 35.097 170.387 ;
     RECT  40.215 2.413 40.497 170.387 ;
     RECT  45.615 89.069 45.897 170.387 ;
     RECT  51.015 2.413 51.297 170.387 ;
     RECT  56.415 89.195 56.697 170.387 ;
     RECT  111.6 170.339 116.658 170.387 ;
     RECT  121.215 99.968 121.497 170.387 ;
     RECT  126.615 43.325 126.897 170.387 ;
     RECT  132.015 99.968 132.297 170.387 ;
     RECT  137.415 2.413 137.697 170.387 ;
     RECT  142.815 99.968 143.097 170.387 ;
     RECT  148.215 2.413 148.497 170.387 ;
     RECT  153.615 99.968 153.897 170.387 ;
     RECT  159.015 91.499 159.297 170.387 ;
     RECT  164.415 103.037 164.697 170.387 ;
     RECT  169.815 102.659 170.097 170.387 ;
     RECT  95.976 170.339 110.862 170.429 ;
     RECT  116.64 170.387 116.658 170.429 ;
     RECT  59.22 170.339 95.238 170.465 ;
     RECT  96.012 170.429 110.862 170.477 ;
     RECT  84.816 170.465 95.238 170.573 ;
     RECT  102.24 170.477 110.862 170.573 ;
     RECT  84.816 170.573 87.426 170.621 ;
     RECT  2.415 170.387 2.505 170.657 ;
     RECT  7.815 170.387 7.905 170.657 ;
     RECT  13.215 170.387 13.305 170.657 ;
     RECT  18.615 170.387 18.705 170.657 ;
     RECT  24.015 170.387 24.105 170.657 ;
     RECT  29.415 170.387 29.505 170.657 ;
     RECT  34.815 170.387 34.905 170.657 ;
     RECT  40.215 170.387 40.305 170.657 ;
     RECT  45.615 170.387 45.705 170.657 ;
     RECT  51.015 170.387 51.105 170.657 ;
     RECT  56.415 170.387 56.505 170.657 ;
     RECT  111.6 170.387 115.905 170.657 ;
     RECT  121.215 170.387 121.305 170.657 ;
     RECT  126.615 170.387 126.705 170.657 ;
     RECT  132.015 170.387 132.105 170.657 ;
     RECT  137.415 170.387 137.505 170.657 ;
     RECT  142.815 170.387 142.905 170.657 ;
     RECT  148.215 170.387 148.305 170.657 ;
     RECT  153.615 170.387 153.705 170.657 ;
     RECT  159.015 170.387 159.105 170.657 ;
     RECT  164.415 170.387 164.505 170.657 ;
     RECT  169.815 170.387 169.905 170.657 ;
     RECT  82.152 170.465 84.078 170.669 ;
     RECT  84.816 170.621 86.598 170.669 ;
     RECT  82.98 170.669 84.078 170.909 ;
     RECT  96.264 170.477 101.466 170.909 ;
     RECT  111.6 170.657 115.29 170.909 ;
     RECT  59.22 170.465 81.342 170.957 ;
     RECT  84.816 170.669 86.346 170.957 ;
     RECT  87.336 170.621 87.426 170.957 ;
     RECT  88.488 170.573 95.094 170.957 ;
     RECT  96.3 170.909 101.466 170.957 ;
     RECT  102.24 170.573 110.646 170.957 ;
     RECT  114.984 170.909 115.29 170.957 ;
     RECT  59.22 170.957 65.862 171.005 ;
     RECT  66.672 170.957 75.978 171.005 ;
     RECT  76.752 170.957 81.342 171.005 ;
     RECT  82.152 170.669 82.17 171.005 ;
     RECT  82.98 170.909 83.214 171.005 ;
     RECT  84.06 170.909 84.078 171.005 ;
     RECT  84.816 170.957 84.834 171.005 ;
     RECT  85.572 170.957 86.346 171.005 ;
     RECT  87.408 170.957 87.426 171.005 ;
     RECT  88.632 170.957 91.386 171.005 ;
     RECT  92.124 170.957 95.094 171.005 ;
     RECT  96.3 170.957 99.522 171.005 ;
     RECT  100.296 170.957 101.466 171.005 ;
     RECT  102.24 170.957 110.574 171.005 ;
     RECT  111.6 170.909 114.246 171.005 ;
     RECT  115.272 170.957 115.29 171.005 ;
     RECT  82.98 171.005 82.998 171.053 ;
     RECT  92.124 171.005 92.286 171.053 ;
     RECT  97.38 171.005 98.082 171.053 ;
     RECT  112.068 171.005 112.842 171.053 ;
     RECT  69.336 171.005 69.354 171.101 ;
     RECT  103.716 171.005 104.202 171.581 ;
     RECT  76.752 171.005 76.842 171.629 ;
     RECT  77.904 171.005 78.606 171.629 ;
     RECT  80.82 171.005 80.838 171.629 ;
     RECT  85.86 171.005 85.878 171.629 ;
     RECT  90.036 171.005 90.054 171.629 ;
     RECT  92.268 171.053 92.286 171.629 ;
     RECT  95.076 171.005 95.094 171.629 ;
     RECT  104.184 171.581 104.202 171.629 ;
     RECT  59.22 171.005 61.074 172.157 ;
     RECT  67.896 171.005 67.95 172.157 ;
     RECT  73.98 171.005 73.998 172.157 ;
     RECT  76.752 171.629 76.77 172.157 ;
     RECT  77.904 171.629 77.922 172.157 ;
     RECT  79.776 171.005 79.794 172.157 ;
     RECT  106.128 171.005 106.578 172.157 ;
     RECT  107.964 171.005 108.702 172.157 ;
     RECT  112.572 171.053 112.842 172.171 ;
     RECT  59.256 172.157 61.074 172.205 ;
     RECT  59.256 172.205 59.274 172.253 ;
     RECT  67.932 172.157 67.95 172.253 ;
     RECT  107.964 172.157 108.306 172.253 ;
     RECT  112.212 172.171 112.842 172.349 ;
     RECT  95.076 172.411 95.094 172.459 ;
     RECT  111.096 172.363 111.114 172.459 ;
     RECT  84.528 172.411 84.546 172.507 ;
     RECT  95.004 172.459 95.094 172.507 ;
     RECT  84.132 172.507 84.546 172.541 ;
     RECT  87.696 172.411 88.038 172.541 ;
     RECT  84.132 172.541 84.15 172.555 ;
     RECT  77.544 172.411 77.562 172.589 ;
     RECT  94.86 172.507 95.094 172.589 ;
     RECT  60.192 172.205 61.074 172.637 ;
     RECT  94.86 172.589 95.022 172.637 ;
     RECT  60.192 172.637 60.21 172.685 ;
     RECT  61.056 172.637 61.074 172.685 ;
     RECT  81.684 172.555 81.702 172.685 ;
     RECT  83.448 172.555 84.15 172.685 ;
     RECT  85.752 172.459 85.77 172.685 ;
     RECT  88.02 172.541 88.038 172.685 ;
     RECT  89.172 172.555 89.19 172.685 ;
     RECT  94.86 172.637 94.878 172.685 ;
     RECT  103.752 172.555 103.77 172.685 ;
     RECT  106.128 172.157 106.146 172.685 ;
     RECT  107.964 172.253 107.982 172.685 ;
     RECT  110.844 172.459 111.114 172.685 ;
     RECT  112.572 172.349 112.842 172.685 ;
    LAYER M4 ;
     RECT  0.06 88.944 0.227 89.064 ;
     RECT  0.181 86.496 2.408 86.52 ;
     RECT  0.227 89.04 2.408 89.064 ;
     RECT  2.408 2.148 2.512 170.652 ;
     RECT  2.512 2.418 2.704 170.382 ;
     RECT  2.704 86.496 7.808 86.52 ;
     RECT  2.704 89.04 7.808 89.064 ;
     RECT  7.808 2.148 7.912 170.652 ;
     RECT  7.912 2.418 8.104 170.382 ;
     RECT  8.104 86.496 13.208 86.52 ;
     RECT  8.104 89.04 13.208 89.064 ;
     RECT  13.208 2.148 13.312 170.652 ;
     RECT  13.312 2.418 13.504 170.382 ;
     RECT  13.504 86.496 18.608 86.52 ;
     RECT  13.504 89.04 18.608 89.064 ;
     RECT  18.608 2.148 18.712 170.652 ;
     RECT  18.712 2.418 18.904 170.382 ;
     RECT  18.904 86.496 24.008 86.52 ;
     RECT  18.904 89.04 24.008 89.064 ;
     RECT  24.008 2.148 24.112 170.652 ;
     RECT  24.112 2.418 24.304 170.382 ;
     RECT  24.304 86.496 29.408 86.52 ;
     RECT  24.304 89.04 29.408 89.064 ;
     RECT  29.408 2.148 29.512 170.652 ;
     RECT  29.512 2.418 29.704 170.382 ;
     RECT  29.704 86.496 34.808 86.52 ;
     RECT  29.704 89.04 34.808 89.064 ;
     RECT  34.808 2.148 34.912 170.652 ;
     RECT  34.912 2.418 35.104 170.382 ;
     RECT  35.104 86.496 40.208 86.52 ;
     RECT  35.104 89.04 40.208 89.064 ;
     RECT  40.208 2.148 40.312 170.652 ;
     RECT  40.312 2.418 40.504 170.382 ;
     RECT  40.504 86.496 45.608 86.52 ;
     RECT  40.504 89.04 45.608 89.064 ;
     RECT  45.608 2.148 45.712 170.652 ;
     RECT  45.712 2.418 45.904 170.382 ;
     RECT  45.904 86.496 51.008 86.52 ;
     RECT  45.904 89.04 51.008 89.064 ;
     RECT  51.008 2.148 51.112 170.652 ;
     RECT  51.112 2.418 51.304 170.382 ;
     RECT  51.304 86.496 56.408 86.52 ;
     RECT  51.304 89.04 56.408 89.064 ;
     RECT  56.408 2.148 56.512 170.652 ;
     RECT  56.512 2.418 56.704 170.382 ;
     RECT  59.209 172.128 59.245 172.152 ;
     RECT  57.913 89.472 59.857 89.496 ;
     RECT  59.605 169.92 59.893 169.944 ;
     RECT  59.857 89.472 59.989 90.264 ;
     RECT  59.245 172.128 60.001 172.248 ;
     RECT  59.989 88.896 60.076 90.264 ;
     RECT  60.001 171.6 60.181 172.248 ;
     RECT  60.073 167.568 60.397 167.592 ;
     RECT  60.181 171.6 60.563 172.68 ;
     RECT  59.965 4.56 60.901 4.584 ;
     RECT  59.893 169.92 60.901 170.616 ;
     RECT  60.397 167.568 60.937 168.312 ;
     RECT  60.901 169.728 60.997 170.616 ;
     RECT  60.901 4.56 61.009 4.728 ;
     RECT  60.937 167.28 61.009 168.36 ;
     RECT  60.997 169.728 61.009 171 ;
     RECT  60.829 1.104 61.189 1.128 ;
     RECT  61.189 0.144 61.297 1.128 ;
     RECT  61.189 2.976 61.333 3 ;
     RECT  61.297 0.144 61.477 1.752 ;
     RECT  61.333 2.976 61.477 3.336 ;
     RECT  61.009 4.32 61.477 4.728 ;
     RECT  61.477 0.096 61.619 1.752 ;
     RECT  60.563 172.608 61.619 172.68 ;
     RECT  61.619 0.144 61.693 1.752 ;
     RECT  61.693 0.144 61.808 1.8 ;
     RECT  61.477 2.784 61.808 4.728 ;
     RECT  61.801 5.76 61.808 5.784 ;
     RECT  56.704 86.496 61.808 86.52 ;
     RECT  60.076 89.472 61.808 90.264 ;
     RECT  61.765 165.312 61.808 165.336 ;
     RECT  61.009 167.28 61.808 171 ;
     RECT  61.621 172.56 61.811 172.584 ;
     RECT  61.808 0.144 62.104 171 ;
     RECT  62.104 0.144 62.593 5.784 ;
     RECT  62.104 164.112 62.819 166.2 ;
     RECT  62.593 0.096 62.963 5.784 ;
     RECT  62.819 164.688 62.993 166.2 ;
     RECT  62.963 0.672 63.059 5.784 ;
     RECT  63.059 1.104 63.241 5.784 ;
     RECT  62.104 6.816 63.241 6.84 ;
     RECT  62.993 165.84 63.421 166.2 ;
     RECT  62.104 167.28 63.421 171 ;
     RECT  62.993 164.688 64.069 164.712 ;
     RECT  63.421 165.84 64.069 171 ;
     RECT  63.349 128.208 64.115 128.232 ;
     RECT  63.241 1.104 64.163 6.84 ;
     RECT  64.163 3.936 64.181 6.84 ;
     RECT  64.181 3.936 64.361 4.584 ;
     RECT  64.163 1.104 64.403 2.904 ;
     RECT  64.069 164.688 64.793 171 ;
     RECT  64.793 167.28 65.009 171 ;
     RECT  64.403 1.728 65.117 2.904 ;
     RECT  64.793 164.688 65.185 165.864 ;
     RECT  65.185 164.112 65.189 165.864 ;
     RECT  65.009 167.28 65.377 169.32 ;
     RECT  64.181 5.664 65.405 6.84 ;
     RECT  64.361 3.936 65.473 4.392 ;
     RECT  65.405 5.664 65.585 6.264 ;
     RECT  64.933 7.968 65.585 7.992 ;
     RECT  65.377 167.28 65.621 168.744 ;
     RECT  65.189 164.112 65.843 165.672 ;
     RECT  65.843 164.688 65.909 165.672 ;
     RECT  65.585 5.664 65.981 6.216 ;
     RECT  65.009 170.448 66.044 171 ;
     RECT  65.473 3.408 66.085 4.392 ;
     RECT  65.833 7.44 66.131 7.704 ;
     RECT  66.044 170.4 66.131 171 ;
     RECT  65.117 1.728 66.409 1.992 ;
     RECT  66.409 1.728 66.469 2.376 ;
     RECT  66.085 3.408 66.469 4.536 ;
     RECT  65.621 167.28 66.901 168.696 ;
     RECT  66.469 1.728 67.208 4.536 ;
     RECT  65.981 5.808 67.208 6.216 ;
     RECT  66.131 7.68 67.208 7.704 ;
     RECT  62.104 86.496 67.208 86.52 ;
     RECT  62.104 90.24 67.208 90.264 ;
     RECT  65.005 96.576 67.208 96.6 ;
     RECT  64.033 97.632 67.208 97.656 ;
     RECT  63.421 98.928 67.208 98.952 ;
     RECT  65.909 165.552 67.208 165.672 ;
     RECT  66.901 167.184 67.208 168.696 ;
     RECT  66.131 170.448 67.208 171 ;
     RECT  67.208 1.728 67.504 171 ;
     RECT  67.504 166.656 67.601 171 ;
     RECT  67.504 1.728 67.853 6.696 ;
     RECT  67.853 3.408 67.889 6.696 ;
     RECT  67.813 172.128 67.921 172.152 ;
     RECT  67.889 3.792 67.925 6.696 ;
     RECT  67.921 172.128 67.925 172.248 ;
     RECT  67.925 172.224 68.051 172.248 ;
     RECT  67.504 164.736 68.069 165.672 ;
     RECT  67.925 3.84 68.893 6.696 ;
     RECT  67.504 7.68 68.893 7.704 ;
     RECT  68.317 0.528 68.915 0.552 ;
     RECT  68.069 165.024 69.001 165.672 ;
     RECT  67.601 167.184 69.001 171 ;
     RECT  69.001 165.024 69.113 171 ;
     RECT  69.113 165.024 69.185 168.744 ;
     RECT  69.113 170.16 69.185 171 ;
     RECT  67.853 1.728 69.325 2.376 ;
     RECT  69.185 170.448 69.325 171 ;
     RECT  69.325 170.448 69.587 171.096 ;
     RECT  69.325 1.728 69.613 2.52 ;
     RECT  68.893 3.84 69.613 7.704 ;
     RECT  69.533 0.096 69.617 0.12 ;
     RECT  69.433 91.584 69.721 91.608 ;
     RECT  69.613 1.728 69.725 7.704 ;
     RECT  69.587 170.448 69.971 171 ;
     RECT  69.185 165.648 70.049 168.744 ;
     RECT  69.971 170.592 70.067 171 ;
     RECT  67.504 98.928 70.261 98.952 ;
     RECT  70.049 165.648 70.405 165.864 ;
     RECT  70.067 170.784 70.561 171 ;
     RECT  70.405 164.784 70.913 165.864 ;
     RECT  69.725 1.728 71.228 6.6 ;
     RECT  69.725 7.68 71.228 7.704 ;
     RECT  70.049 167.184 71.233 168.744 ;
     RECT  71.228 1.728 71.315 7.704 ;
     RECT  71.233 167.184 71.489 168.792 ;
     RECT  71.197 169.824 71.593 169.848 ;
     RECT  70.561 170.832 71.593 171 ;
     RECT  70.913 165.168 71.653 165.864 ;
     RECT  71.489 167.184 71.653 168.744 ;
     RECT  71.941 172.608 72.131 172.632 ;
     RECT  67.504 97.632 72.565 97.656 ;
     RECT  71.315 1.728 72.608 6.696 ;
     RECT  71.315 7.68 72.608 7.704 ;
     RECT  71.269 17.664 72.608 17.688 ;
     RECT  71.029 18.96 72.608 18.984 ;
     RECT  67.504 86.496 72.608 86.52 ;
     RECT  67.504 90.24 72.608 90.264 ;
     RECT  69.721 91.584 72.608 92.136 ;
     RECT  67.504 93.888 72.608 94.056 ;
     RECT  67.504 96.576 72.608 96.6 ;
     RECT  72.565 97.632 72.608 97.848 ;
     RECT  70.261 98.928 72.608 99.432 ;
     RECT  71.653 165.168 72.608 168.744 ;
     RECT  71.593 169.824 72.608 171 ;
     RECT  72.373 0.192 72.659 0.216 ;
     RECT  72.608 1.728 72.904 171 ;
     RECT  72.904 167.568 72.965 171 ;
     RECT  72.965 167.568 73.001 169.368 ;
     RECT  73.001 167.712 73.325 169.368 ;
     RECT  72.904 1.728 73.361 6.696 ;
     RECT  72.904 165.648 73.433 166.488 ;
     RECT  73.237 0.144 73.523 0.168 ;
     RECT  73.969 172.128 74.387 172.152 ;
     RECT  73.325 167.712 74.509 169.272 ;
     RECT  73.361 1.728 74.7 6.6 ;
     RECT  73.433 165.648 74.725 165.72 ;
     RECT  74.7 1.68 74.809 6.6 ;
     RECT  74.653 65.568 74.837 65.592 ;
     RECT  74.509 167.472 74.945 169.272 ;
     RECT  74.725 165.264 75.373 165.72 ;
     RECT  72.965 170.448 75.373 171 ;
     RECT  75.373 165.264 75.593 166.008 ;
     RECT  75.493 0.096 75.629 0.12 ;
     RECT  75.593 165.648 75.733 166.008 ;
     RECT  75.373 169.872 75.827 171 ;
     RECT  72.904 91.584 75.841 92.712 ;
     RECT  72.904 93.888 75.841 94.056 ;
     RECT  75.733 165.648 75.913 166.392 ;
     RECT  74.945 167.472 76.021 168.744 ;
     RECT  75.827 169.872 76.021 169.896 ;
     RECT  76.021 167.472 76.025 169.896 ;
     RECT  75.913 165.648 76.093 166.488 ;
     RECT  76.025 167.472 76.093 169.464 ;
     RECT  76.093 165.648 76.313 169.464 ;
     RECT  75.827 170.928 76.813 171 ;
     RECT  76.741 172.128 76.813 172.152 ;
     RECT  74.809 1.728 76.933 6.6 ;
     RECT  72.904 7.68 76.933 7.704 ;
     RECT  76.813 170.928 77.084 172.152 ;
     RECT  76.933 1.728 77.281 7.704 ;
     RECT  77.084 170.448 77.363 172.152 ;
     RECT  76.313 167.472 77.453 169.464 ;
     RECT  77.363 170.448 77.453 171 ;
     RECT  76.313 165.648 77.461 166.008 ;
     RECT  77.363 172.128 77.489 172.152 ;
     RECT  72.904 90.24 77.533 90.264 ;
     RECT  77.461 165.648 77.597 166.152 ;
     RECT  77.453 167.472 77.597 171 ;
     RECT  77.489 172.128 77.606 172.584 ;
     RECT  77.533 90.24 77.713 90.552 ;
     RECT  77.606 172.128 77.795 172.536 ;
     RECT  77.597 165.648 78.001 171 ;
     RECT  77.281 1.104 78.008 7.704 ;
     RECT  72.904 18.96 78.008 18.984 ;
     RECT  72.904 86.496 78.008 86.52 ;
     RECT  77.713 90.24 78.008 90.6 ;
     RECT  75.841 91.584 78.008 94.056 ;
     RECT  72.904 96.576 78.008 96.6 ;
     RECT  72.904 97.632 78.008 97.848 ;
     RECT  72.904 98.928 78.008 99.432 ;
     RECT  77.461 151.008 78.008 151.032 ;
     RECT  78.001 165.312 78.008 171 ;
     RECT  78.008 1.104 78.304 171 ;
     RECT  78.304 1.104 78.509 7.704 ;
     RECT  77.795 172.128 78.515 172.152 ;
     RECT  78.304 164.496 78.577 171 ;
     RECT  78.509 1.104 78.685 6.696 ;
     RECT  78.577 164.496 78.707 171.624 ;
     RECT  78.685 0.528 78.803 6.696 ;
     RECT  78.304 65.664 79.337 66.024 ;
     RECT  78.304 151.008 79.337 151.032 ;
     RECT  79.337 66 79.481 66.024 ;
     RECT  78.304 82.752 79.549 82.776 ;
     RECT  78.304 83.76 79.549 83.784 ;
     RECT  78.803 1.824 79.669 6.696 ;
     RECT  78.509 7.68 79.669 7.704 ;
     RECT  78.707 164.496 79.805 171 ;
     RECT  79.801 74.544 79.913 74.568 ;
     RECT  79.669 1.824 80.005 7.704 ;
     RECT  78.304 90.24 80.053 94.056 ;
     RECT  79.549 82.752 80.341 83.784 ;
     RECT  79.765 172.128 80.485 172.152 ;
     RECT  80.485 172.128 80.677 172.44 ;
     RECT  80.341 82.656 80.701 83.784 ;
     RECT  80.005 1.728 80.777 7.704 ;
     RECT  79.805 164.592 80.809 171 ;
     RECT  80.677 172.128 80.809 172.632 ;
     RECT  80.821 87.696 80.881 87.72 ;
     RECT  78.304 86.496 80.917 86.52 ;
     RECT  80.881 87.6 80.917 87.72 ;
     RECT  80.341 79.728 81.025 79.752 ;
     RECT  80.701 82.656 81.025 84.744 ;
     RECT  81.025 79.728 81.097 80.088 ;
     RECT  80.809 164.592 81.097 172.632 ;
     RECT  81.097 164.16 81.107 172.632 ;
     RECT  80.917 86.496 81.109 87.72 ;
     RECT  81.107 164.16 81.181 171 ;
     RECT  81.025 82.224 81.205 84.744 ;
     RECT  81.205 81.6 81.425 84.744 ;
     RECT  81.107 172.272 81.629 172.632 ;
     RECT  81.629 172.272 81.713 172.68 ;
     RECT  81.713 172.272 81.827 172.632 ;
     RECT  80.053 89.52 81.929 94.056 ;
     RECT  81.181 164.736 81.971 171 ;
     RECT  81.827 172.368 81.971 172.632 ;
     RECT  81.097 79.296 82.181 80.088 ;
     RECT  81.971 164.736 82.213 165.336 ;
     RECT  82.213 164.64 82.316 165.336 ;
     RECT  80.777 1.728 82.861 6.696 ;
     RECT  80.777 7.68 82.861 7.704 ;
     RECT  81.425 81.6 82.933 83.784 ;
     RECT  81.971 166.416 82.969 171 ;
     RECT  82.969 166.416 83.053 171.048 ;
     RECT  82.316 164.544 83.149 165.336 ;
     RECT  81.929 90.048 83.173 94.056 ;
     RECT  78.304 96.576 83.185 96.6 ;
     RECT  78.304 97.632 83.185 97.848 ;
     RECT  78.304 98.928 83.185 99.432 ;
     RECT  82.537 100.848 83.185 100.872 ;
     RECT  81.109 86.496 83.221 88.344 ;
     RECT  83.173 89.424 83.221 94.056 ;
     RECT  83.221 0.576 83.257 0.6 ;
     RECT  83.257 0.432 83.269 0.6 ;
     RECT  83.149 164.16 83.269 165.336 ;
     RECT  83.053 166.416 83.269 171 ;
     RECT  83.269 0.432 83.341 0.696 ;
     RECT  82.861 1.728 83.408 7.704 ;
     RECT  82.573 11.664 83.408 11.688 ;
     RECT  78.304 18.96 83.408 18.984 ;
     RECT  82.181 79.296 83.408 79.752 ;
     RECT  82.933 81.6 83.408 84.36 ;
     RECT  83.221 86.496 83.408 94.056 ;
     RECT  83.185 96.576 83.408 97.848 ;
     RECT  83.185 98.928 83.408 100.872 ;
     RECT  83.185 129.024 83.408 129.048 ;
     RECT  83.185 131.808 83.408 131.832 ;
     RECT  83.185 145.2 83.408 145.224 ;
     RECT  83.269 164.16 83.408 171 ;
     RECT  81.971 172.608 83.41 172.632 ;
     RECT  83.341 0.576 83.507 0.696 ;
     RECT  83.408 1.728 83.704 171 ;
     RECT  83.704 74.304 83.837 74.712 ;
     RECT  83.41 172.56 83.845 172.68 ;
     RECT  83.704 82.656 83.873 84.36 ;
     RECT  83.845 172.464 83.941 172.68 ;
     RECT  83.507 0.576 83.987 0.6 ;
     RECT  83.704 89.424 84.017 94.056 ;
     RECT  83.941 172.368 84.083 172.68 ;
     RECT  84.083 172.416 84.205 172.68 ;
     RECT  84.205 172.416 84.611 172.632 ;
     RECT  83.704 98.928 84.803 100.68 ;
     RECT  83.873 82.656 84.841 83.064 ;
     RECT  83.837 74.304 84.881 74.328 ;
     RECT  84.841 82.656 84.953 83.112 ;
     RECT  84.017 89.712 85.169 94.056 ;
     RECT  83.704 165.216 85.237 171 ;
     RECT  85.237 164.88 85.381 171 ;
     RECT  84.611 172.512 85.717 172.632 ;
     RECT  85.717 172.464 85.741 172.632 ;
     RECT  85.741 172.464 85.825 172.68 ;
     RECT  85.381 164.736 85.849 171 ;
     RECT  85.825 172.464 85.849 172.632 ;
     RECT  83.873 84.336 85.853 84.36 ;
     RECT  85.849 164.736 85.859 172.632 ;
     RECT  84.953 82.656 85.921 83.064 ;
     RECT  85.381 124.176 85.925 124.2 ;
     RECT  85.525 102 85.957 102.024 ;
     RECT  83.704 151.968 85.961 151.992 ;
     RECT  85.859 164.736 86.041 171.624 ;
     RECT  86.041 164.88 86.099 171.624 ;
     RECT  86.099 164.88 86.177 171 ;
     RECT  83.704 1.728 86.213 7.704 ;
     RECT  85.921 82.656 86.245 83.352 ;
     RECT  85.957 101.76 86.293 102.024 ;
     RECT  86.245 82.656 86.573 83.592 ;
     RECT  86.461 9.648 86.641 9.672 ;
     RECT  83.704 81.6 86.641 81.624 ;
     RECT  86.573 82.656 86.641 83.4 ;
     RECT  85.169 89.952 86.681 94.056 ;
     RECT  84.803 98.928 86.713 100.296 ;
     RECT  86.293 101.76 86.713 102.6 ;
     RECT  83.704 88.08 86.749 88.248 ;
     RECT  86.569 0.096 86.785 0.12 ;
     RECT  86.749 88.08 86.821 88.344 ;
     RECT  85.859 172.608 86.821 172.632 ;
     RECT  86.641 9.552 86.897 9.672 ;
     RECT  86.897 9.648 86.933 9.672 ;
     RECT  86.849 75.264 86.933 75.288 ;
     RECT  86.785 0.096 86.963 0.168 ;
     RECT  86.821 87.936 86.969 88.344 ;
     RECT  86.713 98.928 87.113 102.6 ;
     RECT  86.641 81.6 87.185 83.4 ;
     RECT  87.113 102.288 87.253 102.6 ;
     RECT  86.177 165.312 87.301 171 ;
     RECT  87.185 81.6 87.329 83.352 ;
     RECT  87.253 102.288 87.365 103.272 ;
     RECT  86.213 2.256 87.397 7.704 ;
     RECT  87.445 79.056 87.541 79.08 ;
     RECT  86.821 172.56 87.644 172.632 ;
     RECT  87.644 172.512 87.685 172.632 ;
     RECT  87.541 78.576 87.721 79.08 ;
     RECT  87.721 78.576 87.781 79.32 ;
     RECT  86.681 90.048 87.793 94.056 ;
     RECT  87.685 172.416 87.965 172.632 ;
     RECT  87.965 172.416 88.049 172.68 ;
     RECT  88.049 172.416 88.067 172.632 ;
     RECT  87.781 78.576 88.153 79.56 ;
     RECT  87.793 90 88.213 94.056 ;
     RECT  86.969 87.936 88.441 88.152 ;
     RECT  87.397 1.728 88.808 7.704 ;
     RECT  83.704 11.664 88.808 11.688 ;
     RECT  86.569 13.824 88.808 13.848 ;
     RECT  83.704 18.96 88.808 18.984 ;
     RECT  87.541 74.976 88.808 75 ;
     RECT  87.836 76.512 88.808 76.536 ;
     RECT  88.153 78.48 88.808 79.8 ;
     RECT  87.329 81.6 88.808 83.016 ;
     RECT  83.704 86.496 88.808 86.52 ;
     RECT  88.441 87.936 88.808 88.44 ;
     RECT  88.213 89.52 88.808 94.056 ;
     RECT  83.704 96.576 88.808 96.6 ;
     RECT  83.704 97.632 88.808 97.848 ;
     RECT  87.113 98.928 88.808 100.872 ;
     RECT  87.365 102.576 88.808 103.272 ;
     RECT  87.301 165.888 88.808 171 ;
     RECT  86.963 0.144 89.029 0.168 ;
     RECT  88.808 1.728 89.104 171 ;
     RECT  89.029 0.144 89.117 0.264 ;
     RECT  88.067 172.512 89.117 172.632 ;
     RECT  89.117 172.512 89.201 172.68 ;
     RECT  89.104 11.664 89.219 12.024 ;
     RECT  89.104 61.584 89.245 61.608 ;
     RECT  89.117 0.096 89.315 0.264 ;
     RECT  89.315 0.096 89.381 0.216 ;
     RECT  89.381 0.192 89.411 0.216 ;
     RECT  89.104 166.224 89.417 171 ;
     RECT  89.417 166.656 89.777 171 ;
     RECT  89.201 172.512 89.987 172.632 ;
     RECT  89.104 78.48 89.993 84.936 ;
     RECT  89.777 166.848 90.025 171 ;
     RECT  90.025 166.848 90.035 171.624 ;
     RECT  90.035 166.848 90.065 169.32 ;
     RECT  89.104 71.808 90.101 71.832 ;
     RECT  90.035 170.4 90.131 171.624 ;
     RECT  89.104 98.928 90.241 100.872 ;
     RECT  90.241 98.928 90.325 100.92 ;
     RECT  90.065 166.992 90.389 169.32 ;
     RECT  89.104 1.728 90.457 7.704 ;
     RECT  89.104 97.632 90.493 97.848 ;
     RECT  90.325 98.928 90.493 100.872 ;
     RECT  89.987 172.608 90.563 172.632 ;
     RECT  90.493 97.632 90.605 100.872 ;
     RECT  90.389 166.992 90.605 167.016 ;
     RECT  89.104 87.936 90.673 94.056 ;
     RECT  90.457 1.68 90.707 7.704 ;
     RECT  90.389 168.096 90.749 169.32 ;
     RECT  90.707 1.728 90.893 7.704 ;
     RECT  90.749 168.192 90.893 169.32 ;
     RECT  90.601 57.696 91.001 57.72 ;
     RECT  90.893 168.24 91.001 169.32 ;
     RECT  91.045 166.8 91.213 166.824 ;
     RECT  91.001 168.816 91.237 169.32 ;
     RECT  90.131 170.4 91.237 171 ;
     RECT  90.893 1.728 91.325 5.784 ;
     RECT  91.213 166.56 91.573 166.824 ;
     RECT  91.105 27.888 91.619 27.912 ;
     RECT  90.893 6.816 91.756 7.704 ;
     RECT  90.673 87.792 91.793 94.056 ;
     RECT  91.573 166.416 91.801 166.824 ;
     RECT  91.793 87.792 91.829 89.208 ;
     RECT  91.753 53.52 91.837 53.544 ;
     RECT  89.993 78.48 92.003 84.072 ;
     RECT  92.003 78.48 92.045 80.472 ;
     RECT  91.793 90.24 92.045 94.056 ;
     RECT  92.003 81.6 92.081 84.072 ;
     RECT  91.237 168.816 92.113 171 ;
     RECT  92.045 78.48 92.117 80.328 ;
     RECT  91.669 85.488 92.117 85.512 ;
     RECT  92.117 78.48 92.225 80.088 ;
     RECT  92.113 168.816 92.257 171.048 ;
     RECT  91.829 88.08 92.261 89.208 ;
     RECT  91.325 1.728 92.293 5.736 ;
     RECT  91.801 166.464 92.369 166.824 ;
     RECT  92.257 168.816 92.405 171.624 ;
     RECT  92.293 1.728 92.509 6.552 ;
     RECT  92.509 1.104 92.513 6.552 ;
     RECT  92.405 170.448 92.531 171.624 ;
     RECT  92.081 82.656 92.581 84.072 ;
     RECT  92.405 168.816 92.657 169.32 ;
     RECT  92.657 168.816 92.689 168.84 ;
     RECT  92.581 82.656 92.765 84.984 ;
     RECT  92.531 170.448 92.819 171 ;
     RECT  92.225 78.48 92.873 79.8 ;
     RECT  92.261 88.08 92.941 88.872 ;
     RECT  92.513 1.104 93.107 4.248 ;
     RECT  92.941 87.936 93.121 88.872 ;
     RECT  92.369 166.8 93.445 166.824 ;
     RECT  93.445 166.8 93.733 166.968 ;
     RECT  92.045 90.24 93.769 92.952 ;
     RECT  92.689 168.288 93.769 168.84 ;
     RECT  92.819 170.496 93.841 171 ;
     RECT  93.769 168.24 94.021 168.84 ;
     RECT  93.733 166.8 94.069 167.256 ;
     RECT  94.021 168.24 94.069 169.176 ;
     RECT  92.873 78.48 94.165 78.504 ;
     RECT  93.107 1.728 94.208 4.248 ;
     RECT  92.513 5.28 94.208 6.552 ;
     RECT  91.756 7.68 94.208 7.704 ;
     RECT  89.104 8.976 94.208 9 ;
     RECT  89.219 11.664 94.208 11.688 ;
     RECT  89.104 13.824 94.208 13.848 ;
     RECT  89.104 18.96 94.208 18.984 ;
     RECT  94.165 78.48 94.208 78.696 ;
     RECT  92.873 79.776 94.208 79.8 ;
     RECT  92.081 81.6 94.208 81.624 ;
     RECT  92.765 82.656 94.208 84.072 ;
     RECT  89.104 86.496 94.208 86.52 ;
     RECT  93.121 87.888 94.208 88.872 ;
     RECT  93.769 90.24 94.208 93.336 ;
     RECT  92.257 94.368 94.208 94.392 ;
     RECT  89.104 96.576 94.208 96.6 ;
     RECT  90.605 97.632 94.208 97.848 ;
     RECT  90.605 98.928 94.208 100.872 ;
     RECT  94.069 166.8 94.208 169.176 ;
     RECT  93.841 170.448 94.208 171 ;
     RECT  94.208 1.728 94.504 171 ;
     RECT  94.504 78.48 94.565 78.696 ;
     RECT  94.069 172.608 94.597 172.632 ;
     RECT  94.504 87.792 94.673 87.912 ;
     RECT  94.504 167.04 94.673 171 ;
     RECT  94.597 0.384 94.693 0.408 ;
     RECT  94.693 0.192 94.738 0.408 ;
     RECT  94.738 0.096 94.739 0.408 ;
     RECT  94.739 0.096 94.817 0.312 ;
     RECT  94.565 78.48 94.817 78.6 ;
     RECT  94.597 172.464 94.834 172.632 ;
     RECT  94.817 0.096 94.835 0.216 ;
     RECT  94.504 86.496 94.925 86.664 ;
     RECT  94.834 172.464 94.933 172.68 ;
     RECT  94.673 168.144 95.065 171 ;
     RECT  94.933 172.416 95.065 172.632 ;
     RECT  95.065 168.144 95.066 172.632 ;
     RECT  95.066 168.144 95.123 172.584 ;
     RECT  95.123 171.6 95.149 172.584 ;
     RECT  94.504 6.384 95.177 7.704 ;
     RECT  95.177 6.48 95.213 7.704 ;
     RECT  95.149 171.6 95.219 171.624 ;
     RECT  94.673 167.04 95.429 167.064 ;
     RECT  94.504 1.728 95.645 5.16 ;
     RECT  95.645 2.88 95.717 5.16 ;
     RECT  94.504 96.576 95.749 96.6 ;
     RECT  94.504 97.632 95.749 97.848 ;
     RECT  94.504 98.928 95.749 100.872 ;
     RECT  95.123 168.144 96.073 170.472 ;
     RECT  96.073 167.856 96.133 170.472 ;
     RECT  96.133 167.856 96.371 171 ;
     RECT  95.717 3.12 96.721 5.16 ;
     RECT  95.645 1.728 96.764 1.8 ;
     RECT  96.721 3.12 96.764 5.352 ;
     RECT  94.817 78.48 96.901 78.504 ;
     RECT  95.749 96.576 96.901 100.872 ;
     RECT  96.901 78.48 96.937 78.744 ;
     RECT  94.504 79.776 96.937 79.8 ;
     RECT  96.901 96.528 97.013 100.872 ;
     RECT  96.764 1.728 97.049 5.352 ;
     RECT  97.013 96.576 97.157 100.872 ;
     RECT  96.371 168.144 97.336 171 ;
     RECT  97.336 168.144 97.427 171.048 ;
     RECT  97.049 1.728 97.441 4.632 ;
     RECT  97.427 168.144 97.573 169.896 ;
     RECT  97.573 167.568 97.585 169.896 ;
     RECT  97.157 98.928 97.621 100.872 ;
     RECT  96.685 136.656 97.717 136.68 ;
     RECT  94.504 90.24 97.763 94.392 ;
     RECT  97.585 166.848 97.763 169.896 ;
     RECT  97.763 169.488 97.841 169.896 ;
     RECT  97.621 98.928 97.909 101.064 ;
     RECT  97.945 75.984 98.089 76.008 ;
     RECT  97.909 98.928 98.093 101.4 ;
     RECT  97.717 136.608 98.093 136.68 ;
     RECT  97.427 170.976 98.099 171.048 ;
     RECT  97.441 1.152 98.125 4.632 ;
     RECT  95.213 6.672 98.125 7.704 ;
     RECT  98.125 0.576 98.137 4.632 ;
     RECT  97.157 96.576 98.161 97.848 ;
     RECT  98.137 0.576 98.209 0.6 ;
     RECT  97.763 166.848 98.293 168.168 ;
     RECT  98.089 75.984 98.341 76.296 ;
     RECT  98.245 172.464 98.341 172.488 ;
     RECT  98.137 1.728 98.377 4.632 ;
     RECT  98.125 6.192 98.377 7.704 ;
     RECT  94.504 8.976 98.377 9 ;
     RECT  98.161 96.576 98.377 97.896 ;
     RECT  98.341 172.464 98.387 172.632 ;
     RECT  98.293 166.512 98.453 168.168 ;
     RECT  98.377 1.728 98.485 5.208 ;
     RECT  98.377 6.192 98.485 9 ;
     RECT  98.341 75.984 98.485 76.824 ;
     RECT  96.937 78.48 98.485 79.8 ;
     RECT  98.197 34.608 98.593 34.632 ;
     RECT  98.093 136.656 98.593 136.68 ;
     RECT  98.099 170.976 98.596 171 ;
     RECT  94.504 81.6 98.629 81.624 ;
     RECT  94.504 82.656 98.629 84.072 ;
     RECT  98.593 136.656 98.633 136.776 ;
     RECT  98.593 34.608 98.773 34.728 ;
     RECT  98.485 75.744 98.809 76.824 ;
     RECT  98.809 75.744 98.917 77.448 ;
     RECT  98.485 78.432 98.917 79.8 ;
     RECT  98.485 1.728 98.953 9 ;
     RECT  98.881 72.48 99.097 72.504 ;
     RECT  98.387 172.512 99.155 172.632 ;
     RECT  98.917 75.744 99.313 79.8 ;
     RECT  98.596 170.928 99.397 171 ;
     RECT  99.397 170.88 99.421 171 ;
     RECT  94.504 18.96 99.493 18.984 ;
     RECT  98.953 1.728 99.608 9.096 ;
     RECT  94.504 11.664 99.608 11.688 ;
     RECT  94.504 13.824 99.608 13.848 ;
     RECT  98.341 16.8 99.608 16.824 ;
     RECT  99.493 18.432 99.608 18.984 ;
     RECT  98.881 23.568 99.608 23.592 ;
     RECT  98.773 34.56 99.608 34.728 ;
     RECT  99.097 72.432 99.608 72.504 ;
     RECT  94.504 73.776 99.608 74.04 ;
     RECT  99.313 75.072 99.608 79.8 ;
     RECT  98.629 81.6 99.608 84.408 ;
     RECT  94.925 86.496 99.608 86.52 ;
     RECT  94.673 87.792 99.608 87.816 ;
     RECT  97.763 90.384 99.608 94.392 ;
     RECT  98.377 96.576 99.608 97.944 ;
     RECT  98.093 98.928 99.608 98.952 ;
     RECT  98.093 99.936 99.608 101.4 ;
     RECT  98.633 136.752 99.608 136.776 ;
     RECT  98.453 166.512 99.608 167.64 ;
     RECT  97.841 169.488 99.608 169.512 ;
     RECT  99.421 170.784 99.608 171 ;
     RECT  99.349 0.144 99.731 0.168 ;
     RECT  99.608 1.728 99.904 171 ;
     RECT  99.904 75.936 100.325 77.112 ;
     RECT  99.904 1.728 100.469 10.248 ;
     RECT  99.155 172.608 100.549 172.632 ;
     RECT  99.904 165.84 100.595 168.168 ;
     RECT  100.549 172.512 100.643 172.632 ;
     RECT  100.325 75.936 100.649 77.016 ;
     RECT  99.904 72.432 100.721 74.04 ;
     RECT  100.643 172.512 100.739 172.536 ;
     RECT  100.469 1.776 100.835 10.248 ;
     RECT  100.835 1.776 100.865 8.04 ;
     RECT  100.835 9.744 100.876 10.248 ;
     RECT  100.876 10.224 100.909 10.248 ;
     RECT  99.904 81.408 100.933 83.784 ;
     RECT  99.904 84.96 100.933 86.424 ;
     RECT  99.904 99.936 100.933 102.504 ;
     RECT  100.865 1.776 100.973 7.704 ;
     RECT  100.933 99.936 100.997 103.032 ;
     RECT  100.933 81.408 101.041 86.424 ;
     RECT  101.041 81.408 101.077 86.664 ;
     RECT  100.997 99.936 101.081 103.08 ;
     RECT  99.904 169.488 101.081 171 ;
     RECT  101.041 153.888 101.125 153.912 ;
     RECT  100.649 76.224 101.15 77.016 ;
     RECT  99.904 78.096 101.189 79.8 ;
     RECT  101.077 81.36 101.189 86.664 ;
     RECT  100.973 1.776 101.225 6.6 ;
     RECT  100.973 7.632 101.261 7.704 ;
     RECT  101.189 78.384 101.261 79.8 ;
     RECT  101.261 78.48 101.293 79.8 ;
     RECT  101.293 78.48 101.365 79.896 ;
     RECT  101.189 81.36 101.369 86.616 ;
     RECT  101.324 60.144 101.411 60.168 ;
     RECT  99.904 90.384 101.437 98.856 ;
     RECT  101.369 81.408 101.441 86.616 ;
     RECT  101.225 1.776 101.509 5.832 ;
     RECT  99.904 13.584 101.509 13.848 ;
     RECT  101.441 82.656 101.513 86.616 ;
     RECT  101.081 99.936 101.549 103.032 ;
     RECT  101.365 78.48 101.555 79.992 ;
     RECT  101.365 57.024 101.66 57.048 ;
     RECT  101.66 57.024 101.661 57.096 ;
     RECT  101.605 54.624 101.701 54.648 ;
     RECT  101.509 65.568 101.701 65.592 ;
     RECT  101.081 169.824 101.729 171 ;
     RECT  101.509 1.728 101.747 5.832 ;
     RECT  101.661 57.072 101.747 57.096 ;
     RECT  101.468 60.048 101.747 60.072 ;
     RECT  101.701 65.568 101.747 66.072 ;
     RECT  100.721 72.432 101.747 72.504 ;
     RECT  101.549 99.936 101.765 102.504 ;
     RECT  100.595 165.84 101.797 167.448 ;
     RECT  101.441 81.408 101.801 81.624 ;
     RECT  101.261 7.68 101.843 7.704 ;
     RECT  100.721 73.776 101.941 74.04 ;
     RECT  101.173 75.12 101.941 75.144 ;
     RECT  101.437 90.384 101.945 98.904 ;
     RECT  101.905 152.208 101.989 152.232 ;
     RECT  101.765 99.936 102.053 102.456 ;
     RECT  101.797 165.84 102.125 167.544 ;
     RECT  101.513 84.336 102.161 86.616 ;
     RECT  101.747 1.728 102.341 1.848 ;
     RECT  101.15 76.224 102.373 76.968 ;
     RECT  102.161 84.72 102.377 86.616 ;
     RECT  101.945 90.384 102.377 98.856 ;
     RECT  101.941 73.776 102.409 75.144 ;
     RECT  102.373 76.128 102.409 76.968 ;
     RECT  102.377 86.016 102.409 86.616 ;
     RECT  102.409 73.776 102.413 76.968 ;
     RECT  101.747 2.88 102.469 5.832 ;
     RECT  102.413 73.776 102.485 76.296 ;
     RECT  102.469 2.88 102.517 5.88 ;
     RECT  102.377 84.72 102.557 84.936 ;
     RECT  102.409 86.016 102.589 86.76 ;
     RECT  102.485 73.776 102.593 76.248 ;
     RECT  101.729 170.448 102.611 171 ;
     RECT  102.593 76.224 102.665 76.248 ;
     RECT  102.125 166.512 102.805 167.544 ;
     RECT  102.377 97.536 102.917 98.856 ;
     RECT  102.377 90.384 102.953 96.504 ;
     RECT  102.661 9.072 102.989 9.096 ;
     RECT  102.053 99.936 103.021 102.312 ;
     RECT  102.557 84.816 103.061 84.936 ;
     RECT  102.589 86.016 103.061 86.808 ;
     RECT  101.801 81.6 103.093 81.624 ;
     RECT  101.513 82.656 103.093 83.112 ;
     RECT  102.517 2.88 103.133 6.312 ;
     RECT  103.061 86.496 103.141 86.808 ;
     RECT  99.904 87.792 103.141 87.816 ;
     RECT  101.509 13.584 103.169 14.28 ;
     RECT  103.093 169.872 103.177 169.896 ;
     RECT  103.133 2.88 103.309 5.736 ;
     RECT  102.341 1.728 103.333 1.8 ;
     RECT  103.093 81.456 103.345 83.112 ;
     RECT  103.34 30.288 103.381 30.312 ;
     RECT  103.021 99.168 103.381 102.312 ;
     RECT  103.381 29.616 103.427 30.312 ;
     RECT  103.333 1.248 103.429 1.8 ;
     RECT  101.747 72.48 103.429 72.504 ;
     RECT  102.593 73.776 103.429 75.144 ;
     RECT  99.904 16.8 103.453 16.824 ;
     RECT  99.904 18.432 103.453 18.984 ;
     RECT  101.555 78.48 103.475 79.8 ;
     RECT  103.141 86.496 103.493 87.816 ;
     RECT  103.061 84.864 103.525 84.936 ;
     RECT  102.953 90.384 103.529 95.736 ;
     RECT  103.484 31.248 103.571 31.272 ;
     RECT  102.611 170.928 103.597 171 ;
     RECT  103.429 1.152 103.619 1.8 ;
     RECT  103.345 81.024 103.619 83.112 ;
     RECT  103.529 95.712 103.637 95.736 ;
     RECT  103.333 172.512 103.697 172.536 ;
     RECT  103.597 170.4 103.705 171 ;
     RECT  103.697 172.512 103.705 172.68 ;
     RECT  103.525 84.864 103.715 85.512 ;
     RECT  102.805 166.512 103.724 167.832 ;
     RECT  103.705 170.4 103.781 172.68 ;
     RECT  103.724 166.416 103.811 167.832 ;
     RECT  103.781 170.4 103.811 172.584 ;
     RECT  103.619 1.728 103.909 1.8 ;
     RECT  103.309 2.784 103.909 5.736 ;
     RECT  103.529 90.384 103.957 94.392 ;
     RECT  101.701 54.624 103.993 54.696 ;
     RECT  102.917 97.536 104.029 98.184 ;
     RECT  103.715 84.864 104.033 84.888 ;
     RECT  103.493 86.496 104.033 86.664 ;
     RECT  104.029 97.488 104.173 98.184 ;
     RECT  103.381 99.168 104.173 102.696 ;
     RECT  103.429 72.48 104.245 75.144 ;
     RECT  103.909 1.728 104.293 5.736 ;
     RECT  103.811 170.4 104.293 171.624 ;
     RECT  104.293 1.728 104.317 6.312 ;
     RECT  103.453 16.8 104.341 18.984 ;
     RECT  104.209 50.88 104.353 50.904 ;
     RECT  104.173 97.488 104.389 102.696 ;
     RECT  104.389 96.912 104.425 102.696 ;
     RECT  103.427 29.616 104.444 29.64 ;
     RECT  104.293 169.776 104.531 171.624 ;
     RECT  104.245 72.48 104.533 75.288 ;
     RECT  104.317 1.728 104.629 6.888 ;
     RECT  103.619 81.024 104.677 81.672 ;
     RECT  103.619 82.656 104.677 83.112 ;
     RECT  104.531 169.776 104.677 171 ;
     RECT  104.629 1.728 105.008 7.368 ;
     RECT  99.904 11.664 105.008 11.688 ;
     RECT  103.169 13.584 105.008 13.608 ;
     RECT  104.341 16.032 105.008 18.984 ;
     RECT  99.904 23.568 105.008 23.592 ;
     RECT  104.444 25.44 105.008 25.464 ;
     RECT  104.444 29.088 105.008 29.64 ;
     RECT  99.904 34.608 105.008 34.632 ;
     RECT  104.353 50.832 105.008 50.904 ;
     RECT  103.993 54.432 105.008 54.696 ;
     RECT  101.747 66.048 105.008 66.072 ;
     RECT  104.533 72.48 105.008 75.72 ;
     RECT  103.993 76.944 105.008 76.968 ;
     RECT  103.475 78.48 105.008 78.504 ;
     RECT  103.475 79.776 105.008 79.8 ;
     RECT  104.677 81.024 105.008 83.112 ;
     RECT  104.033 86.496 105.008 86.52 ;
     RECT  103.493 87.792 105.008 87.816 ;
     RECT  103.957 89.472 105.008 94.392 ;
     RECT  104.425 96.912 105.008 102.792 ;
     RECT  99.904 136.656 105.008 136.68 ;
     RECT  103.811 166.992 105.008 167.832 ;
     RECT  104.677 169.344 105.008 171 ;
     RECT  105.008 1.728 105.304 171 ;
     RECT  105.304 88.896 105.329 93.336 ;
     RECT  105.304 48.624 105.443 48.696 ;
     RECT  105.304 1.728 105.481 6.408 ;
     RECT  105.304 169.536 105.481 171 ;
     RECT  105.481 4.512 105.509 6.408 ;
     RECT  105.304 166.128 105.539 168.312 ;
     RECT  105.304 50.832 105.653 51 ;
     RECT  105.443 48.624 105.731 48.648 ;
     RECT  105.539 166.128 105.779 168.168 ;
     RECT  105.509 5.232 105.875 6.408 ;
     RECT  105.481 169.968 105.875 171 ;
     RECT  105.304 73.776 106.013 75.96 ;
     RECT  105.875 169.968 106.049 169.992 ;
     RECT  105.875 170.976 106.069 171 ;
     RECT  105.481 1.728 106.076 3.432 ;
     RECT  105.493 172.608 106.117 172.632 ;
     RECT  105.329 88.896 106.121 88.92 ;
     RECT  106.076 1.104 106.163 3.432 ;
     RECT  106.117 172.608 106.201 172.68 ;
     RECT  106.333 98.496 106.445 98.52 ;
     RECT  106.163 1.728 106.549 3.432 ;
     RECT  106.069 170.976 106.549 171.624 ;
     RECT  105.779 166.128 106.553 167.592 ;
     RECT  105.304 79.776 106.657 79.8 ;
     RECT  105.304 82.656 106.657 83.112 ;
     RECT  106.549 1.728 106.729 3.576 ;
     RECT  106.549 170.976 106.739 172.152 ;
     RECT  106.657 82.608 106.769 83.112 ;
     RECT  105.875 5.232 106.837 5.736 ;
     RECT  106.739 170.976 106.837 171.576 ;
     RECT  105.304 54.432 106.883 54.648 ;
     RECT  106.729 1.728 106.913 3.624 ;
     RECT  105.653 50.976 106.931 51 ;
     RECT  106.597 53.232 106.972 53.256 ;
     RECT  106.553 166.128 106.972 167.016 ;
     RECT  106.837 55.92 107.029 55.944 ;
     RECT  106.883 54.624 107.075 54.648 ;
     RECT  106.657 79.776 107.089 80.088 ;
     RECT  105.329 90.192 107.089 93.336 ;
     RECT  107.009 53.568 107.093 53.592 ;
     RECT  107.089 90.144 107.125 93.336 ;
     RECT  107.089 79.776 107.161 80.136 ;
     RECT  106.837 170.88 107.365 171.576 ;
     RECT  106.013 73.776 107.516 75.816 ;
     RECT  107.365 170.832 107.516 171.576 ;
     RECT  105.304 11.664 107.521 11.688 ;
     RECT  106.837 4.8 107.557 5.736 ;
     RECT  107.516 73.728 107.593 75.816 ;
     RECT  107.516 170.448 107.603 171.576 ;
     RECT  107.029 55.872 107.633 55.944 ;
     RECT  107.557 68.352 107.653 68.376 ;
     RECT  107.125 90.048 107.669 93.336 ;
     RECT  107.603 170.496 107.699 171.576 ;
     RECT  107.305 0.528 107.701 0.552 ;
     RECT  106.913 1.728 107.701 3.576 ;
     RECT  107.593 73.728 107.74 75.864 ;
     RECT  107.633 55.872 107.741 55.896 ;
     RECT  107.669 90.192 107.741 93.336 ;
     RECT  107.521 11.664 107.747 11.976 ;
     RECT  107.701 0.528 107.795 3.576 ;
     RECT  105.304 86.496 107.941 86.52 ;
     RECT  106.972 166.128 107.948 166.68 ;
     RECT  107.699 170.736 107.948 171.576 ;
     RECT  107.948 170.736 107.989 171.624 ;
     RECT  107.909 172.656 107.989 172.68 ;
     RECT  107.989 170.736 107.993 172.68 ;
     RECT  107.917 115.152 108.001 115.176 ;
     RECT  107.017 169.248 108.101 169.272 ;
     RECT  107.948 166.128 108.14 166.776 ;
     RECT  107.941 86.496 108.229 86.616 ;
     RECT  107.795 1.104 108.275 3.576 ;
     RECT  108.133 57.168 108.275 57.192 ;
     RECT  108.229 86.256 108.275 86.616 ;
     RECT  107.741 90.48 108.281 93.336 ;
     RECT  107.993 170.736 108.281 172.632 ;
     RECT  108.281 170.832 108.316 172.632 ;
     RECT  108.284 60.816 108.371 60.84 ;
     RECT  107.653 68.352 108.371 68.52 ;
     RECT  108.316 170.976 108.371 172.632 ;
     RECT  108.275 3.12 108.385 3.576 ;
     RECT  107.557 4.8 108.425 5.832 ;
     RECT  107.747 11.664 108.425 11.784 ;
     RECT  108.425 11.76 108.467 11.784 ;
     RECT  108.428 60.912 108.515 60.936 ;
     RECT  108.371 68.496 108.515 68.52 ;
     RECT  107.161 79.776 108.533 80.28 ;
     RECT  105.304 34.608 108.563 34.632 ;
     RECT  108.517 42.192 108.613 42.216 ;
     RECT  108.281 90.624 108.637 93.336 ;
     RECT  105.304 94.368 108.637 94.392 ;
     RECT  108.14 166.128 108.637 167.016 ;
     RECT  108.565 168.096 108.637 168.12 ;
     RECT  108.613 42.192 108.659 42.552 ;
     RECT  108.601 57.024 108.685 57.048 ;
     RECT  105.304 16.8 108.817 16.824 ;
     RECT  108.637 168.096 108.851 168.168 ;
     RECT  108.371 172.128 108.947 172.632 ;
     RECT  107.701 14.064 108.965 14.088 ;
     RECT  107.74 73.776 108.997 75.864 ;
     RECT  108.637 165.84 108.997 167.016 ;
     RECT  108.637 169.296 109.037 169.32 ;
     RECT  108.275 1.104 109.043 1.896 ;
     RECT  108.313 96.288 109.069 96.312 ;
     RECT  108.997 165.84 109.093 167.064 ;
     RECT  108.385 3.12 109.141 3.672 ;
     RECT  108.425 4.8 109.141 5.784 ;
     RECT  109.093 165.84 109.177 167.112 ;
     RECT  109.177 165.84 109.283 167.592 ;
     RECT  106.769 82.656 109.285 83.112 ;
     RECT  109.141 3.12 109.289 5.784 ;
     RECT  109.069 96.288 109.289 96.744 ;
     RECT  108.637 90.624 109.361 94.392 ;
     RECT  108.997 73.776 109.393 76.584 ;
     RECT  109.289 96.288 109.397 96.6 ;
     RECT  109.285 168.72 109.397 168.744 ;
     RECT  109.043 1.728 109.429 1.896 ;
     RECT  108.533 79.776 109.484 80.088 ;
     RECT  105.304 78.48 109.525 78.504 ;
     RECT  108.371 170.976 109.765 171 ;
     RECT  109.765 170.928 110.204 171 ;
     RECT  109.429 1.728 110.293 2.376 ;
     RECT  110.293 1.68 110.408 2.376 ;
     RECT  109.289 3.648 110.408 5.736 ;
     RECT  109.393 14.112 110.408 14.136 ;
     RECT  108.817 16.368 110.408 16.824 ;
     RECT  105.304 18.96 110.408 18.984 ;
     RECT  105.304 23.568 110.408 23.592 ;
     RECT  108.421 26.256 110.408 26.28 ;
     RECT  105.304 40.608 110.408 40.872 ;
     RECT  108.659 42.528 110.408 42.552 ;
     RECT  108.325 54.912 110.408 54.984 ;
     RECT  105.304 66.048 110.408 66.072 ;
     RECT  105.304 72.48 110.408 72.504 ;
     RECT  109.393 73.776 110.408 76.776 ;
     RECT  109.525 78.48 110.408 78.648 ;
     RECT  109.484 79.68 110.408 80.088 ;
     RECT  109.285 82.656 110.408 83.784 ;
     RECT  108.275 86.256 110.408 86.52 ;
     RECT  105.304 87.792 110.408 87.816 ;
     RECT  109.361 90.624 110.408 93.336 ;
     RECT  109.361 94.368 110.408 94.392 ;
     RECT  109.397 96.576 110.408 96.6 ;
     RECT  105.304 99.936 110.408 100.296 ;
     RECT  109.465 115.68 110.408 115.704 ;
     RECT  109.477 128.4 110.408 128.424 ;
     RECT  105.304 136.656 110.408 136.68 ;
     RECT  109.283 166.224 110.408 167.592 ;
     RECT  110.204 170.448 110.408 171 ;
     RECT  110.293 0.144 110.579 0.168 ;
     RECT  108.947 172.608 110.629 172.632 ;
     RECT  110.408 1.68 110.675 171 ;
     RECT  110.675 1.728 110.704 171 ;
     RECT  110.629 172.416 110.725 172.632 ;
     RECT  110.704 42.432 110.801 42.552 ;
     RECT  110.725 172.32 110.818 172.632 ;
     RECT  110.704 16.368 110.837 16.824 ;
     RECT  110.704 91.056 110.837 93.336 ;
     RECT  110.818 172.32 110.867 172.68 ;
     RECT  110.704 26.208 111.125 26.376 ;
     RECT  110.867 172.368 111.125 172.68 ;
     RECT  110.704 170.64 111.155 171 ;
     RECT  111.125 172.56 111.169 172.68 ;
     RECT  110.704 76.272 111.305 76.92 ;
     RECT  110.704 3.264 111.449 5.784 ;
     RECT  111.449 3.264 111.485 3.672 ;
     RECT  110.704 166.224 111.485 168.024 ;
     RECT  110.704 169.296 111.491 169.32 ;
     RECT  110.704 1.728 111.521 2.28 ;
     RECT  110.704 73.776 111.521 75.144 ;
     RECT  111.521 1.728 111.635 2.184 ;
     RECT  111.449 4.656 111.637 5.784 ;
     RECT  111.485 3.552 111.665 3.672 ;
     RECT  111.305 76.464 111.733 76.92 ;
     RECT  110.837 91.056 111.733 92.952 ;
     RECT  111.485 166.224 111.845 167.688 ;
     RECT  111.733 76.464 112.021 77.016 ;
     RECT  111.155 170.832 112.057 171 ;
     RECT  111.169 172.608 112.157 172.632 ;
     RECT  111.985 169.248 112.165 169.272 ;
     RECT  112.157 172.32 112.165 172.632 ;
     RECT  112.165 172.08 112.307 172.632 ;
     RECT  112.165 89.184 112.345 89.208 ;
     RECT  111.733 91.008 112.345 92.952 ;
     RECT  110.704 14.112 112.453 14.136 ;
     RECT  111.845 166.368 112.453 167.688 ;
     RECT  112.057 170.832 112.453 171.048 ;
     RECT  112.021 76.464 112.493 77.112 ;
     RECT  110.704 65.952 112.549 65.976 ;
     RECT  110.704 72.48 112.549 72.504 ;
     RECT  112.069 7.392 112.556 7.416 ;
     RECT  112.453 170.448 112.556 171.048 ;
     RECT  112.453 14.112 112.565 14.856 ;
     RECT  112.549 72.48 112.595 72.648 ;
     RECT  110.704 40.608 112.597 40.872 ;
     RECT  111.637 4.944 112.601 5.784 ;
     RECT  112.556 6.816 112.643 7.416 ;
     RECT  112.556 170.448 112.643 171.624 ;
     RECT  112.601 4.944 112.645 5.256 ;
     RECT  112.645 4.8 112.709 5.256 ;
     RECT  111.125 26.208 112.709 26.232 ;
     RECT  112.595 72.624 112.739 72.648 ;
     RECT  112.549 65.76 112.789 65.976 ;
     RECT  112.493 76.464 112.835 76.92 ;
     RECT  112.669 36.672 112.837 36.696 ;
     RECT  112.165 168.912 112.849 169.272 ;
     RECT  112.643 170.448 112.853 171 ;
     RECT  110.704 18.96 112.889 18.984 ;
     RECT  111.635 1.728 112.892 1.848 ;
     RECT  112.517 172.656 112.917 172.68 ;
     RECT  112.549 27.552 112.921 27.576 ;
     RECT  112.453 34.992 112.933 35.016 ;
     RECT  112.643 7.344 112.961 7.416 ;
     RECT  110.704 31.152 112.979 31.176 ;
     RECT  110.704 23.568 112.993 23.592 ;
     RECT  112.849 168.72 112.997 169.272 ;
     RECT  112.921 27.552 113.005 27.912 ;
     RECT  110.704 160.128 113.033 160.152 ;
     RECT  112.997 169.056 113.033 169.272 ;
     RECT  110.704 86.256 113.069 87.816 ;
     RECT  111.697 85.248 113.101 85.272 ;
     RECT  113.069 86.256 113.101 86.52 ;
     RECT  112.993 22.8 113.105 23.592 ;
     RECT  113.033 169.056 113.105 169.08 ;
     RECT  113.005 27.552 113.209 27.576 ;
     RECT  112.453 166.368 113.209 167.736 ;
     RECT  112.933 34.08 113.213 35.496 ;
     RECT  113.213 34.8 113.269 35.496 ;
     RECT  112.837 36.672 113.269 37.368 ;
     RECT  112.853 170.736 113.293 171 ;
     RECT  113.269 34.8 113.356 37.368 ;
     RECT  113.209 166.368 113.411 168.024 ;
     RECT  112.993 32.736 113.425 32.76 ;
     RECT  112.709 4.8 113.461 5.16 ;
     RECT  113.209 27.312 113.573 27.576 ;
     RECT  112.345 89.184 113.573 92.952 ;
     RECT  113.425 32.736 113.653 32.808 ;
     RECT  112.961 7.344 113.717 7.368 ;
     RECT  113.653 29.808 113.749 29.832 ;
     RECT  112.597 40.608 113.749 41.064 ;
     RECT  111.521 74.016 113.785 75.144 ;
     RECT  113.101 85.248 113.785 86.52 ;
     RECT  113.785 84.672 113.789 86.52 ;
     RECT  113.653 32.736 113.795 33.432 ;
     RECT  112.669 38.448 113.804 38.472 ;
     RECT  112.789 65.76 113.825 66.12 ;
     RECT  113.795 33.36 113.836 33.432 ;
     RECT  113.461 4.56 113.843 5.16 ;
     RECT  113.789 84.672 113.857 86.28 ;
     RECT  113.356 34.8 113.891 35.496 ;
     RECT  113.804 38.448 113.929 38.568 ;
     RECT  113.836 33.36 113.933 33.384 ;
     RECT  113.857 84.432 113.933 86.28 ;
     RECT  113.825 66.096 113.969 66.12 ;
     RECT  112.835 76.464 113.969 76.824 ;
     RECT  112.892 1.728 114.001 2.28 ;
     RECT  111.665 3.552 114.001 3.576 ;
     RECT  113.749 40.56 114.109 41.064 ;
     RECT  113.843 5.088 114.145 5.16 ;
     RECT  113.785 73.872 114.181 75.144 ;
     RECT  114.145 5.088 114.185 5.256 ;
     RECT  110.801 42.432 114.188 42.456 ;
     RECT  114.109 40.56 114.217 41.16 ;
     RECT  114.188 42.432 114.217 43.032 ;
     RECT  114.217 40.56 114.229 43.032 ;
     RECT  113.933 85.728 114.257 86.28 ;
     RECT  113.411 166.368 114.257 167.592 ;
     RECT  114.229 39.84 114.275 43.032 ;
     RECT  113.969 76.56 114.275 76.824 ;
     RECT  113.293 170.784 114.277 171 ;
     RECT  114.257 85.728 114.293 85.992 ;
     RECT  113.929 38.4 114.325 38.568 ;
     RECT  114.001 1.728 114.401 3.576 ;
     RECT  114.277 170.736 114.437 171 ;
     RECT  114.185 5.136 114.469 5.256 ;
     RECT  114.275 39.84 114.473 42.456 ;
     RECT  113.573 27.312 114.497 27.432 ;
     RECT  113.749 29.808 114.517 29.928 ;
     RECT  113.356 36.816 114.517 37.368 ;
     RECT  114.325 38.4 114.517 38.76 ;
     RECT  113.105 23.568 114.563 23.592 ;
     RECT  114.517 36.816 114.563 38.76 ;
     RECT  113.573 91.008 114.577 92.952 ;
     RECT  114.517 29.04 114.581 29.928 ;
     RECT  114.181 72.96 114.581 75.144 ;
     RECT  110.704 54.912 114.613 54.984 ;
     RECT  114.581 29.04 114.621 29.832 ;
     RECT  113.933 84.432 114.649 84.696 ;
     RECT  114.613 54.72 114.653 54.984 ;
     RECT  114.469 5.136 114.661 5.736 ;
     RECT  114.497 26.736 114.661 27.432 ;
     RECT  114.621 29.04 114.661 29.784 ;
     RECT  114.577 90.816 114.685 92.952 ;
     RECT  110.837 16.512 114.707 16.824 ;
     RECT  114.661 26.544 114.707 27.432 ;
     RECT  114.661 28.992 114.707 29.784 ;
     RECT  114.661 5.136 114.748 5.976 ;
     RECT  114.707 26.544 114.748 26.712 ;
     RECT  114.437 170.784 114.761 171 ;
     RECT  110.704 128.304 114.805 128.328 ;
     RECT  113.891 35.328 114.812 35.496 ;
     RECT  114.473 39.84 114.833 39.864 ;
     RECT  110.704 82.656 114.973 83.112 ;
     RECT  114.649 84.144 114.973 84.696 ;
     RECT  114.563 37.92 115.045 38.76 ;
     RECT  115.045 45.504 115.081 45.528 ;
     RECT  114.812 35.328 115.297 35.592 ;
     RECT  114.563 36.816 115.297 36.888 ;
     RECT  114.761 170.928 115.301 171 ;
     RECT  114.401 1.728 115.369 2.28 ;
     RECT  114.401 3.552 115.369 3.576 ;
     RECT  114.473 41.136 115.381 42.456 ;
     RECT  114.685 90.768 115.405 92.952 ;
     RECT  113.069 87.792 115.513 87.816 ;
     RECT  115.369 1.728 115.553 3.576 ;
     RECT  113.573 89.184 115.573 89.208 ;
     RECT  115.405 90.624 115.573 92.952 ;
     RECT  115.513 87.024 115.628 87.816 ;
     RECT  114.581 72.96 115.657 75 ;
     RECT  115.693 50.016 115.801 50.04 ;
     RECT  115.553 1.776 115.808 3.576 ;
     RECT  114.748 5.136 115.808 5.256 ;
     RECT  114.181 10.752 115.808 10.776 ;
     RECT  112.565 14.112 115.808 14.136 ;
     RECT  114.707 16.512 115.808 16.536 ;
     RECT  115.009 19.392 115.808 19.416 ;
     RECT  114.748 26.688 115.808 26.712 ;
     RECT  114.707 28.992 115.808 29.064 ;
     RECT  115.297 35.328 115.808 36.888 ;
     RECT  115.045 37.92 115.808 39 ;
     RECT  115.381 41.136 115.808 42.504 ;
     RECT  115.081 45.024 115.808 45.528 ;
     RECT  115.801 49.872 115.808 50.04 ;
     RECT  114.653 54.72 115.808 54.936 ;
     RECT  115.657 72.96 115.808 75.24 ;
     RECT  114.275 76.608 115.808 76.824 ;
     RECT  110.704 78.48 115.808 78.504 ;
     RECT  110.704 79.776 115.808 80.088 ;
     RECT  114.973 82.656 115.808 84.696 ;
     RECT  115.628 87.024 115.808 87.864 ;
     RECT  115.573 89.184 115.808 92.952 ;
     RECT  110.704 94.368 115.808 94.392 ;
     RECT  110.704 99.936 115.808 100.296 ;
     RECT  114.805 128.304 115.808 128.616 ;
     RECT  114.257 166.368 115.808 167.256 ;
     RECT  115.808 1.776 115.912 170.652 ;
     RECT  115.912 1.776 116.093 170.382 ;
     RECT  116.093 2.418 116.104 170.382 ;
     RECT  116.104 90.768 116.201 92.808 ;
     RECT  116.104 36.528 116.243 36.648 ;
     RECT  116.104 37.968 116.243 39 ;
     RECT  116.104 40.56 116.243 42.504 ;
     RECT  116.104 44.448 116.243 45.528 ;
     RECT  116.104 48.576 116.243 48.696 ;
     RECT  116.104 49.872 116.243 50.376 ;
     RECT  116.104 54.72 116.243 54.936 ;
     RECT  116.243 50.016 116.281 50.376 ;
     RECT  116.243 36.624 116.291 36.648 ;
     RECT  116.243 38.16 116.291 38.712 ;
     RECT  116.243 40.56 116.291 41.16 ;
     RECT  116.243 44.88 116.291 45.528 ;
     RECT  116.243 48.672 116.291 48.696 ;
     RECT  116.281 50.016 116.291 50.28 ;
     RECT  116.104 51.888 116.291 52.44 ;
     RECT  116.243 54.72 116.291 54.744 ;
     RECT  116.201 90.768 116.381 92.76 ;
     RECT  116.104 84.096 116.417 84.696 ;
     RECT  116.381 92.736 116.489 92.76 ;
     RECT  116.104 70.704 116.525 70.728 ;
     RECT  116.104 76.608 116.525 76.92 ;
     RECT  116.417 84.672 116.597 84.696 ;
     RECT  116.104 5.088 116.771 5.112 ;
     RECT  116.104 89.184 116.771 89.208 ;
     RECT  116.104 85.968 116.813 85.992 ;
     RECT  116.381 90.768 116.885 91.704 ;
     RECT  116.885 90.864 116.921 91.704 ;
     RECT  116.243 42.432 121.208 42.504 ;
     RECT  116.525 76.608 121.208 76.824 ;
     RECT  116.104 78.48 121.208 78.504 ;
     RECT  116.104 79.776 121.208 80.088 ;
     RECT  116.104 82.656 121.208 83.112 ;
     RECT  116.104 87.792 121.208 87.816 ;
     RECT  116.104 94.368 121.208 94.392 ;
     RECT  116.104 99.936 121.208 100.296 ;
     RECT  116.104 128.304 121.208 128.616 ;
     RECT  121.208 2.148 121.312 170.652 ;
     RECT  121.312 2.418 121.504 170.382 ;
     RECT  121.504 42.432 126.493 42.504 ;
     RECT  126.493 42.432 126.608 43.32 ;
     RECT  121.504 76.608 126.608 76.824 ;
     RECT  121.504 78.48 126.608 78.504 ;
     RECT  121.504 79.776 126.608 80.088 ;
     RECT  121.504 82.656 126.608 83.112 ;
     RECT  121.504 87.792 126.608 87.816 ;
     RECT  121.504 94.368 126.608 94.392 ;
     RECT  121.504 99.936 126.608 100.296 ;
     RECT  121.504 128.304 126.608 128.616 ;
     RECT  126.608 2.148 126.712 170.652 ;
     RECT  126.712 2.418 126.904 170.382 ;
     RECT  126.904 43.296 127.043 43.32 ;
     RECT  126.904 128.304 128.261 128.616 ;
     RECT  126.904 74.352 132.008 74.376 ;
     RECT  126.904 76.608 132.008 76.824 ;
     RECT  126.904 78.48 132.008 78.504 ;
     RECT  126.904 79.776 132.008 80.088 ;
     RECT  126.904 82.656 132.008 83.112 ;
     RECT  126.904 87.792 132.008 87.816 ;
     RECT  126.904 94.368 132.008 94.392 ;
     RECT  126.904 99.936 132.008 100.296 ;
     RECT  128.261 128.304 132.008 128.328 ;
     RECT  132.008 2.148 132.112 170.652 ;
     RECT  132.112 2.418 132.304 170.382 ;
     RECT  132.304 74.352 137.408 74.376 ;
     RECT  132.304 76.608 137.408 76.824 ;
     RECT  132.304 78.48 137.408 78.504 ;
     RECT  132.304 79.776 137.408 80.088 ;
     RECT  132.304 82.656 137.408 83.112 ;
     RECT  132.304 87.792 137.408 87.816 ;
     RECT  132.304 94.368 137.408 94.392 ;
     RECT  132.304 99.936 137.408 100.296 ;
     RECT  132.304 128.304 137.408 128.328 ;
     RECT  137.408 2.148 137.512 170.652 ;
     RECT  137.512 2.418 137.704 170.382 ;
     RECT  137.704 74.352 142.808 74.376 ;
     RECT  137.704 76.608 142.808 76.824 ;
     RECT  137.704 78.48 142.808 78.504 ;
     RECT  137.704 79.776 142.808 80.088 ;
     RECT  137.704 82.656 142.808 83.112 ;
     RECT  137.704 87.792 142.808 87.816 ;
     RECT  137.704 94.368 142.808 94.392 ;
     RECT  137.704 99.936 142.808 100.296 ;
     RECT  137.704 128.304 142.808 128.328 ;
     RECT  142.808 2.148 142.912 170.652 ;
     RECT  142.912 2.418 143.104 170.382 ;
     RECT  143.104 74.352 148.208 74.376 ;
     RECT  143.104 76.608 148.208 76.824 ;
     RECT  143.104 78.48 148.208 78.504 ;
     RECT  143.104 79.776 148.208 80.088 ;
     RECT  143.104 82.656 148.208 83.112 ;
     RECT  143.104 87.792 148.208 87.816 ;
     RECT  143.104 94.368 148.208 94.392 ;
     RECT  143.104 99.936 148.208 100.296 ;
     RECT  143.104 128.304 148.208 128.328 ;
     RECT  148.208 2.148 148.312 170.652 ;
     RECT  148.312 2.418 148.504 170.382 ;
     RECT  148.504 74.352 153.608 74.376 ;
     RECT  148.504 76.608 153.608 76.824 ;
     RECT  148.504 78.48 153.608 78.504 ;
     RECT  148.504 79.776 153.608 80.088 ;
     RECT  148.504 82.656 153.608 83.112 ;
     RECT  148.504 87.792 153.608 87.816 ;
     RECT  148.504 94.368 153.608 94.392 ;
     RECT  148.504 99.936 153.608 100.296 ;
     RECT  148.504 128.304 153.608 128.328 ;
     RECT  153.608 2.148 153.712 170.652 ;
     RECT  153.712 2.418 153.904 170.382 ;
     RECT  153.904 74.352 159.008 74.376 ;
     RECT  153.904 76.608 159.008 76.824 ;
     RECT  153.904 78.48 159.008 78.504 ;
     RECT  153.904 79.776 159.008 80.088 ;
     RECT  153.904 82.656 159.008 83.112 ;
     RECT  153.904 87.792 159.008 87.816 ;
     RECT  153.904 94.368 159.008 94.392 ;
     RECT  153.904 99.936 159.008 100.296 ;
     RECT  153.904 128.304 159.008 128.328 ;
     RECT  159.008 2.148 159.112 170.652 ;
     RECT  159.112 2.418 159.304 170.382 ;
     RECT  159.304 76.608 162.457 76.824 ;
     RECT  159.304 78.48 162.457 78.504 ;
     RECT  159.304 79.776 162.457 80.088 ;
     RECT  159.304 87.792 162.457 87.816 ;
     RECT  162.457 84.672 162.493 84.696 ;
     RECT  159.304 99.936 162.497 100.296 ;
     RECT  162.457 78.48 162.641 80.088 ;
     RECT  162.457 91.728 162.853 91.752 ;
     RECT  159.304 82.656 163.105 83.112 ;
     RECT  162.493 84.672 163.177 85.224 ;
     RECT  163.105 82.176 163.285 83.112 ;
     RECT  163.285 82.176 163.357 83.544 ;
     RECT  163.177 84.624 163.368 85.224 ;
     RECT  159.304 74.352 163.393 74.376 ;
     RECT  162.457 87.792 163.393 87.912 ;
     RECT  162.493 89.52 163.393 89.544 ;
     RECT  163.393 92.88 163.429 92.904 ;
     RECT  159.304 94.368 163.429 94.392 ;
     RECT  163.393 74.352 163.465 74.616 ;
     RECT  163.357 82.176 163.501 83.592 ;
     RECT  163.465 74.352 163.525 74.664 ;
     RECT  162.457 76.512 163.537 76.824 ;
     RECT  162.641 79.776 163.537 80.088 ;
     RECT  163.393 89.52 163.537 89.832 ;
     RECT  162.853 90.96 163.537 91.752 ;
     RECT  163.429 92.88 163.537 94.392 ;
     RECT  163.465 98.352 163.537 98.376 ;
     RECT  163.537 76.512 163.681 77.16 ;
     RECT  163.537 79.776 163.717 80.952 ;
     RECT  163.368 84.624 163.825 86.04 ;
     RECT  163.393 87.12 163.825 87.912 ;
     RECT  163.825 84.624 163.861 87.912 ;
     RECT  163.537 89.52 163.861 91.752 ;
     RECT  163.501 82.08 164.257 83.592 ;
     RECT  163.861 84.624 164.257 91.752 ;
     RECT  163.717 79.728 164.329 80.952 ;
     RECT  164.257 82.08 164.329 91.752 ;
     RECT  163.525 74.352 164.408 75.096 ;
     RECT  163.681 76.32 164.408 77.16 ;
     RECT  162.641 78.48 164.408 78.504 ;
     RECT  164.329 79.728 164.408 91.752 ;
     RECT  163.537 92.88 164.408 95.16 ;
     RECT  164.329 96.288 164.408 96.312 ;
     RECT  163.537 97.536 164.408 98.376 ;
     RECT  162.497 100.032 164.408 100.296 ;
     RECT  163.465 101.856 164.408 101.88 ;
     RECT  159.304 128.304 164.408 128.328 ;
     RECT  164.408 2.148 164.512 170.652 ;
     RECT  164.512 2.418 164.704 170.382 ;
     RECT  164.704 86.784 164.765 90.264 ;
     RECT  164.704 76.32 165.197 80.904 ;
     RECT  164.704 91.344 165.305 91.8 ;
     RECT  164.704 93.12 165.341 95.16 ;
     RECT  165.197 76.32 165.347 80.52 ;
     RECT  164.704 128.304 165.443 128.328 ;
     RECT  165.347 76.32 165.587 78.648 ;
     RECT  164.704 96.288 165.593 97.032 ;
     RECT  164.704 98.064 165.629 98.376 ;
     RECT  165.587 78.096 165.737 78.648 ;
     RECT  164.704 81.984 165.769 85.512 ;
     RECT  164.704 99.648 165.829 100.728 ;
     RECT  164.704 101.76 165.875 101.88 ;
     RECT  164.765 88.992 165.877 90.264 ;
     RECT  165.305 91.344 165.877 91.752 ;
     RECT  165.737 78.096 165.881 78.504 ;
     RECT  165.341 93.216 165.917 95.16 ;
     RECT  165.877 88.992 165.989 91.752 ;
     RECT  165.593 96.336 166.093 97.032 ;
     RECT  164.765 86.784 166.201 87.96 ;
     RECT  165.989 88.992 166.201 90.36 ;
     RECT  165.829 99.12 166.241 100.728 ;
     RECT  165.769 81.792 166.309 85.512 ;
     RECT  166.201 86.784 166.309 90.36 ;
     RECT  165.917 93.216 166.421 95.016 ;
     RECT  165.989 91.536 166.453 91.752 ;
     RECT  164.704 74.352 166.457 74.904 ;
     RECT  166.457 74.352 166.529 74.664 ;
     RECT  166.093 96.336 166.529 97.608 ;
     RECT  165.881 78.096 166.709 78.12 ;
     RECT  166.241 99.12 166.745 100.296 ;
     RECT  165.347 79.776 166.885 80.52 ;
     RECT  166.309 81.792 166.885 90.36 ;
     RECT  165.587 76.32 166.925 76.824 ;
     RECT  165.877 102.624 166.993 102.648 ;
     RECT  166.529 74.64 166.997 74.664 ;
     RECT  166.885 79.776 166.997 90.36 ;
     RECT  166.997 86.688 167.027 90.36 ;
     RECT  167.027 89.424 167.033 90.36 ;
     RECT  166.993 102.24 167.033 102.648 ;
     RECT  166.925 76.32 167.173 76.344 ;
     RECT  166.997 79.776 167.173 85.512 ;
     RECT  167.033 90.336 167.173 90.36 ;
     RECT  166.453 91.536 167.173 92.664 ;
     RECT  167.173 75.936 167.213 76.344 ;
     RECT  167.173 79.2 167.213 85.512 ;
     RECT  166.529 97.584 167.245 97.608 ;
     RECT  166.745 100.032 167.357 100.296 ;
     RECT  167.245 97.584 167.501 98.52 ;
     RECT  166.421 94.176 167.557 95.016 ;
     RECT  166.529 96.336 167.557 96.36 ;
     RECT  167.557 94.176 167.603 96.36 ;
     RECT  167.027 86.688 167.609 88.344 ;
     RECT  167.173 90.336 167.645 92.664 ;
     RECT  167.645 91.152 167.677 92.664 ;
     RECT  167.603 94.176 167.677 95.448 ;
     RECT  167.501 97.584 167.897 98.424 ;
     RECT  167.357 100.272 167.965 100.296 ;
     RECT  167.213 79.2 168.185 84.264 ;
     RECT  167.677 91.152 168.293 95.448 ;
     RECT  168.185 80.064 168.325 84.264 ;
     RECT  167.213 85.488 168.325 85.512 ;
     RECT  167.897 98.4 168.401 98.424 ;
     RECT  167.609 87.072 168.437 88.344 ;
     RECT  167.213 75.936 168.473 75.96 ;
     RECT  168.325 80.064 168.473 85.512 ;
     RECT  167.965 100.272 168.524 100.632 ;
     RECT  168.293 91.152 168.545 95.16 ;
     RECT  168.524 100.272 168.565 100.872 ;
     RECT  167.033 102.24 168.565 102.264 ;
     RECT  168.473 80.064 168.581 83.208 ;
     RECT  168.565 100.272 168.581 102.264 ;
     RECT  168.581 100.272 168.611 101.976 ;
     RECT  168.581 80.064 168.653 82.008 ;
     RECT  168.611 100.272 168.653 100.296 ;
     RECT  168.545 94.032 168.689 95.16 ;
     RECT  168.361 78.432 168.721 78.456 ;
     RECT  168.437 87.312 168.761 88.344 ;
     RECT  168.761 88.32 169.297 88.344 ;
     RECT  168.361 89.52 169.297 90.12 ;
     RECT  168.721 78.192 169.333 78.456 ;
     RECT  167.569 74.88 169.729 74.904 ;
     RECT  169.729 74.64 169.808 74.904 ;
     RECT  169.333 77.664 169.808 78.456 ;
     RECT  168.653 80.592 169.808 82.008 ;
     RECT  168.581 82.992 169.808 83.208 ;
     RECT  168.473 84.24 169.808 85.512 ;
     RECT  168.761 87.312 169.808 87.336 ;
     RECT  169.297 88.32 169.808 90.12 ;
     RECT  168.545 91.2 169.808 92.712 ;
     RECT  168.689 94.032 169.808 94.056 ;
     RECT  168.689 95.136 169.808 95.16 ;
     RECT  168.611 101.472 169.808 101.976 ;
     RECT  169.808 2.148 169.912 170.652 ;
     RECT  169.912 2.418 170.104 170.382 ;
     RECT  170.104 99.792 170.417 101.976 ;
     RECT  170.104 96.72 171.457 97.608 ;
     RECT  170.104 77.712 171.493 93.192 ;
     RECT  170.104 94.32 171.493 95.688 ;
     RECT  170.417 99.792 171.493 101.448 ;
     RECT  170.104 73.776 171.529 75.24 ;
     RECT  170.104 76.464 171.529 76.488 ;
     RECT  171.493 77.712 171.529 95.688 ;
     RECT  171.457 96.72 171.529 98.28 ;
     RECT  171.493 99.792 171.529 101.832 ;
     RECT  171.529 73.776 171.565 76.488 ;
     RECT  171.565 73.68 172.033 76.488 ;
     RECT  171.529 77.616 172.033 95.688 ;
     RECT  172.033 73.68 172.573 95.688 ;
     RECT  171.529 96.72 172.573 98.664 ;
     RECT  172.573 73.68 172.764 98.664 ;
     RECT  171.529 99.792 172.764 102.792 ;
    LAYER M5 ;
     RECT  61.392 0.016 115.08 1.139 ;
     RECT  61.488 1.139 115.08 1.763 ;
     RECT  61.8 1.763 115.08 1.811 ;
     RECT  63.216 1.811 95.688 1.859 ;
     RECT  63.312 1.859 95.688 1.907 ;
     RECT  96.816 1.811 115.08 2.137 ;
     RECT  2.4 2.137 2.52 2.151 ;
     RECT  7.8 2.137 7.92 2.151 ;
     RECT  13.2 2.137 13.32 2.151 ;
     RECT  18.6 2.137 18.72 2.151 ;
     RECT  24 2.137 24.12 2.151 ;
     RECT  29.4 2.137 29.52 2.151 ;
     RECT  34.8 2.137 34.92 2.151 ;
     RECT  40.2 2.137 40.32 2.151 ;
     RECT  45.6 2.137 45.72 2.151 ;
     RECT  51 2.137 51.12 2.151 ;
     RECT  56.4 2.137 56.52 2.151 ;
     RECT  96.816 2.137 115.92 2.151 ;
     RECT  121.2 2.137 121.32 2.151 ;
     RECT  126.6 2.137 126.72 2.151 ;
     RECT  132 2.137 132.12 2.151 ;
     RECT  137.4 2.137 137.52 2.151 ;
     RECT  142.8 2.137 142.92 2.151 ;
     RECT  148.2 2.137 148.32 2.151 ;
     RECT  153.6 2.137 153.72 2.151 ;
     RECT  159 2.137 159.12 2.151 ;
     RECT  164.4 2.137 164.52 2.151 ;
     RECT  169.8 2.137 169.92 2.151 ;
     RECT  96.816 2.151 116.112 2.291 ;
     RECT  98.64 2.291 113.256 2.867 ;
     RECT  63.408 1.907 95.688 2.915 ;
     RECT  98.928 2.867 113.256 4.213 ;
     RECT  67.2 2.915 95.352 4.259 ;
     RECT  63.744 2.915 65.64 4.357 ;
     RECT  98.784 4.213 113.256 4.549 ;
     RECT  114.48 2.291 116.112 4.549 ;
     RECT  98.784 4.549 116.112 5.077 ;
     RECT  98.784 5.077 116.76 5.171 ;
     RECT  98.784 5.171 112.68 5.219 ;
     RECT  107.568 5.219 111.624 5.267 ;
     RECT  112.656 5.219 112.68 5.267 ;
     RECT  67.2 4.259 94.512 5.747 ;
     RECT  98.784 5.219 106.584 5.747 ;
     RECT  107.568 5.267 111.336 5.747 ;
     RECT  68.592 5.747 83.712 5.795 ;
     RECT  85.392 5.747 92.616 5.795 ;
     RECT  107.568 5.747 108.648 5.795 ;
     RECT  110.4 5.747 111.336 5.795 ;
     RECT  63.744 4.357 66.12 5.843 ;
     RECT  68.688 5.795 69.384 5.843 ;
     RECT  75.6 5.795 83.712 5.843 ;
     RECT  85.968 5.795 92.616 5.843 ;
     RECT  107.568 5.795 108.36 5.843 ;
     RECT  86.256 5.843 87.24 5.891 ;
     RECT  98.784 5.747 105.864 5.891 ;
     RECT  113.808 5.171 116.76 5.987 ;
     RECT  86.256 5.891 87.096 6.083 ;
     RECT  86.544 6.083 86.904 6.275 ;
     RECT  64.272 5.843 66.12 6.323 ;
     RECT  70.464 5.795 71.304 6.323 ;
     RECT  72.48 5.795 74.376 6.323 ;
     RECT  75.888 5.843 83.712 6.323 ;
     RECT  102.528 5.891 105.864 6.323 ;
     RECT  74.352 6.323 74.376 6.371 ;
     RECT  75.984 6.323 81.48 6.371 ;
     RECT  76.752 6.371 78.456 6.419 ;
     RECT  103.344 6.323 105.864 6.419 ;
     RECT  76.848 6.419 78.456 6.467 ;
     RECT  76.944 6.467 78.456 6.803 ;
     RECT  79.68 6.371 81.048 6.851 ;
     RECT  79.68 6.851 79.704 7.091 ;
     RECT  112.608 6.805 112.632 7.381 ;
     RECT  77.136 6.803 78.456 7.427 ;
     RECT  66.096 6.323 66.12 7.475 ;
     RECT  78 7.427 78.456 7.475 ;
     RECT  98.784 5.891 101.544 7.669 ;
     RECT  113.808 5.987 113.832 10.741 ;
     RECT  108.432 11.749 108.456 11.941 ;
     RECT  98.784 7.669 101.832 13.813 ;
     RECT  107.712 11.941 108.456 14.099 ;
     RECT  115.392 5.987 116.76 14.101 ;
     RECT  98.784 13.813 102.264 14.291 ;
     RECT  115.344 14.101 116.76 16.501 ;
     RECT  113.808 10.741 114.216 16.789 ;
     RECT  115.2 16.501 116.76 16.789 ;
     RECT  71.04 6.323 71.304 17.699 ;
     RECT  71.04 17.699 71.064 18.995 ;
     RECT  108.432 14.099 108.456 26.291 ;
     RECT  112.08 7.381 112.632 27.877 ;
     RECT  113.808 16.789 116.76 27.877 ;
     RECT  98.784 14.291 100.728 34.595 ;
     RECT  112.08 27.877 116.76 37.379 ;
     RECT  103.344 6.419 105.312 40.597 ;
     RECT  103.344 40.597 105.432 40.837 ;
     RECT  112.08 37.379 112.632 41.075 ;
     RECT  108.528 34.597 108.552 42.181 ;
     RECT  108.528 42.181 108.648 42.227 ;
     RECT  126.6 2.151 126.912 43.285 ;
     RECT  103.344 40.837 105.72 48.659 ;
     RECT  103.344 48.659 105.528 51.011 ;
     RECT  106.896 50.965 106.92 53.221 ;
     RECT  106.608 53.221 106.92 53.557 ;
     RECT  106.608 53.557 107.064 54.467 ;
     RECT  99.504 34.595 100.728 54.613 ;
     RECT  101.808 14.291 102.264 54.613 ;
     RECT  108.624 42.227 108.648 54.901 ;
     RECT  106.848 54.467 107.064 55.907 ;
     RECT  106.848 55.907 106.872 55.955 ;
     RECT  108.336 54.901 108.648 57.059 ;
     RECT  108.336 57.059 108.504 57.157 ;
     RECT  112.08 41.075 112.104 65.749 ;
     RECT  112.08 65.749 112.584 65.941 ;
     RECT  108.24 57.157 108.504 68.341 ;
     RECT  107.568 68.341 108.504 68.531 ;
     RECT  99.504 54.613 102.264 72.515 ;
     RECT  113.808 37.379 116.76 73.139 ;
     RECT  107.568 68.531 108.264 74.053 ;
     RECT  113.808 73.139 114.504 74.147 ;
     RECT  164.4 2.151 164.712 74.341 ;
     RECT  126.6 43.285 127.032 74.387 ;
     RECT  164.4 74.341 165.576 74.629 ;
     RECT  107.232 74.053 108.264 74.963 ;
     RECT  163.536 74.629 165.576 75.107 ;
     RECT  99.504 72.515 100.728 75.109 ;
     RECT  101.808 72.515 102.264 75.109 ;
     RECT  86.88 6.275 86.904 75.299 ;
     RECT  88.224 5.843 92.616 76.501 ;
     RECT  114.24 74.147 114.504 76.595 ;
     RECT  112.08 65.941 112.824 76.931 ;
     RECT  87.888 76.501 92.616 78.565 ;
     RECT  110.4 5.795 110.712 78.565 ;
     RECT  109.68 78.565 110.712 78.613 ;
     RECT  87.552 78.565 92.616 79.045 ;
     RECT  109.536 78.613 110.712 79.715 ;
     RECT  109.68 79.715 110.712 79.859 ;
     RECT  112.08 76.931 112.104 79.859 ;
     RECT  107.568 74.963 108.264 80.147 ;
     RECT  99.504 75.109 102.264 82.021 ;
     RECT  103.344 51.011 105.312 82.021 ;
     RECT  164.4 75.107 165.576 82.165 ;
     RECT  99.504 82.021 105.312 83.221 ;
     RECT  78 7.475 78.312 83.749 ;
     RECT  87.456 79.045 92.616 83.843 ;
     RECT  98.64 83.221 105.312 83.843 ;
     RECT  83.4 6.323 83.712 84.325 ;
     RECT  164.4 82.165 165.672 84.467 ;
     RECT  81.024 6.851 81.048 84.611 ;
     RECT  90.288 83.843 92.616 84.995 ;
     RECT  90.288 84.995 92.328 85.523 ;
     RECT  99.504 83.843 105.312 85.523 ;
     RECT  164.4 84.467 164.712 86.005 ;
     RECT  108.24 80.147 108.264 86.581 ;
     RECT  107.952 86.581 108.264 86.627 ;
     RECT  169.8 2.151 170.112 87.301 ;
     RECT  169.8 87.301 170.856 87.443 ;
     RECT  90.288 85.523 91.176 87.829 ;
     RECT  115.8 73.139 116.76 87.829 ;
     RECT  82.944 84.325 83.712 88.117 ;
     RECT  90.288 87.829 91.224 88.307 ;
     RECT  80.832 87.685 80.856 88.309 ;
     RECT  92.304 85.523 92.328 88.403 ;
     RECT  90.288 88.307 91.176 88.451 ;
     RECT  0.192 86.485 0.216 88.979 ;
     RECT  163.44 86.005 164.712 88.981 ;
     RECT  115.68 87.829 116.76 89.219 ;
     RECT  80.832 88.309 81.144 89.509 ;
     RECT  82.272 88.117 83.712 89.701 ;
     RECT  115.68 89.219 116.112 89.749 ;
     RECT  60 88.885 60.024 89.843 ;
     RECT  98.304 84.037 98.328 90.229 ;
     RECT  163.44 88.981 165.336 90.275 ;
     RECT  114.48 76.595 114.504 91.235 ;
     RECT  166.992 89.269 167.016 91.525 ;
     RECT  166.704 91.525 167.016 91.571 ;
     RECT  90.288 88.451 91.032 91.763 ;
     RECT  115.584 89.749 116.112 91.763 ;
     RECT  115.68 91.763 116.112 92.147 ;
     RECT  163.44 90.275 164.712 93.539 ;
     RECT  67.2 5.747 67.512 93.877 ;
     RECT  172.608 94.597 172.632 94.787 ;
     RECT  166.704 91.571 166.728 95.413 ;
     RECT  166.704 95.413 167.592 96.325 ;
     RECT  165.84 96.325 167.592 96.371 ;
     RECT  99.504 85.523 103.368 96.563 ;
     RECT  97.728 90.229 98.328 96.661 ;
     RECT  99.504 96.563 101.976 96.661 ;
     RECT  97.728 96.661 101.976 96.899 ;
     RECT  167.424 97.573 167.448 98.099 ;
     RECT  104.4 85.523 105.312 99.203 ;
     RECT  103.104 96.563 103.368 99.779 ;
     RECT  97.728 96.899 98.328 99.973 ;
     RECT  99.504 96.899 101.976 100.355 ;
     RECT  97.584 99.973 98.328 100.405 ;
     RECT  97.488 100.405 98.328 100.595 ;
     RECT  82.272 89.701 84.456 100.645 ;
     RECT  90.288 91.763 90.312 100.931 ;
     RECT  168.576 100.837 168.6 101.507 ;
     RECT  164.4 93.539 164.712 101.749 ;
     RECT  165.84 96.371 165.864 101.749 ;
     RECT  164.4 101.749 165.864 101.795 ;
     RECT  82.272 100.645 84.792 101.989 ;
     RECT  85.968 101.749 85.992 101.989 ;
     RECT  82.272 101.989 85.992 102.277 ;
     RECT  82.272 102.277 86.424 102.325 ;
     RECT  87.456 83.843 89.112 102.325 ;
     RECT  107.952 86.627 107.976 115.187 ;
     RECT  109.296 83.749 109.32 115.669 ;
     RECT  110.4 79.859 110.712 115.669 ;
     RECT  164.4 101.795 165.432 128.339 ;
     RECT  115.8 92.147 116.112 128.581 ;
     RECT  109.296 115.669 110.712 136.691 ;
     RECT  78 83.749 78.936 150.997 ;
     RECT  99.6 100.355 101.976 152.243 ;
     RECT  99.6 152.243 101.112 153.923 ;
     RECT  110.4 136.691 110.712 160.117 ;
     RECT  61.8 1.811 62.112 164.101 ;
     RECT  80.064 89.509 81.144 164.773 ;
     RECT  82.272 102.325 89.112 164.773 ;
     RECT  77.472 150.997 78.936 165.301 ;
     RECT  80.064 164.773 89.112 165.301 ;
     RECT  65.808 164.101 65.832 165.587 ;
     RECT  64.08 128.197 64.104 165.781 ;
     RECT  109.296 136.691 109.32 165.829 ;
     RECT  101.616 165.877 101.64 165.925 ;
     RECT  101.616 165.925 101.928 165.973 ;
     RECT  71.52 165.157 71.544 166.213 ;
     RECT  72.6 6.323 72.912 166.213 ;
     RECT  77.472 165.301 89.112 166.213 ;
     RECT  109.248 165.829 109.32 166.213 ;
     RECT  99.6 153.923 100.584 166.405 ;
     RECT  101.616 165.973 102.024 166.405 ;
     RECT  103.104 99.779 103.176 166.405 ;
     RECT  108.816 166.213 109.32 166.453 ;
     RECT  64.08 165.781 64.44 166.499 ;
     RECT  77.472 166.213 89.208 166.645 ;
     RECT  108.048 166.453 109.32 166.741 ;
     RECT  91.584 166.405 91.752 166.789 ;
     RECT  94.2 5.747 94.512 166.789 ;
     RECT  103.104 166.405 103.8 166.789 ;
     RECT  105 99.203 105.312 166.789 ;
     RECT  106.416 166.405 106.44 166.789 ;
     RECT  77.472 166.645 89.544 166.837 ;
     RECT  97.728 100.595 98.328 166.837 ;
     RECT  99.6 166.405 102.024 166.837 ;
     RECT  108 166.741 109.32 166.885 ;
     RECT  110.4 160.117 111.48 166.885 ;
     RECT  77.472 166.837 89.928 166.933 ;
     RECT  77.472 166.933 89.976 166.981 ;
     RECT  91.056 166.789 92.136 166.981 ;
     RECT  105 166.789 106.44 166.981 ;
     RECT  108 166.885 112.2 166.981 ;
     RECT  113.376 166.405 113.4 166.981 ;
     RECT  93.36 166.789 94.512 167.029 ;
     RECT  103.056 166.789 103.8 167.029 ;
     RECT  105 166.981 106.92 167.029 ;
     RECT  108 166.981 113.4 167.029 ;
     RECT  67.2 93.877 68.28 167.173 ;
     RECT  64.416 166.499 64.44 167.219 ;
     RECT  71.52 166.213 72.912 167.219 ;
     RECT  114.816 128.581 116.112 167.267 ;
     RECT  61.8 164.101 62.808 167.315 ;
     RECT  71.664 167.219 72.912 167.459 ;
     RECT  66.912 167.173 68.28 167.555 ;
     RECT  97.728 166.837 102.024 167.557 ;
     RECT  71.808 167.459 72.912 167.603 ;
     RECT  61.8 167.315 62.112 167.845 ;
     RECT  61.68 167.845 62.112 168.085 ;
     RECT  67.2 167.555 68.28 168.133 ;
     RECT  67.2 168.133 68.328 169.237 ;
     RECT  65.328 167.269 65.352 169.331 ;
     RECT  67.2 169.237 69.048 169.331 ;
     RECT  77.472 166.981 92.136 169.331 ;
     RECT  61.584 168.085 62.112 169.621 ;
     RECT  61.536 169.621 62.112 169.717 ;
     RECT  67.2 169.331 67.512 170.341 ;
     RECT  60.912 169.717 62.112 170.389 ;
     RECT  64.176 169.477 64.2 170.437 ;
     RECT  66.096 170.389 66.12 170.437 ;
     RECT  67.2 170.341 67.752 170.437 ;
     RECT  69.024 169.331 69.048 170.437 ;
     RECT  72.096 167.603 72.912 170.437 ;
     RECT  77.472 169.331 78.312 170.437 ;
     RECT  79.44 169.331 92.136 170.437 ;
     RECT  93.36 167.029 95.016 170.437 ;
     RECT  96.336 167.845 96.36 170.437 ;
     RECT  97.584 167.557 102.024 170.437 ;
     RECT  103.056 167.029 106.92 170.437 ;
     RECT  108 167.029 113.448 170.437 ;
     RECT  60.048 170.389 62.112 170.533 ;
     RECT  63.216 170.437 67.752 170.533 ;
     RECT  69.024 170.437 69.96 170.581 ;
     RECT  2.4 2.151 2.712 170.649 ;
     RECT  7.8 2.151 8.112 170.649 ;
     RECT  13.2 2.151 13.512 170.649 ;
     RECT  18.6 2.151 18.912 170.649 ;
     RECT  24 2.151 24.312 170.649 ;
     RECT  29.4 2.151 29.712 170.649 ;
     RECT  34.8 2.151 35.112 170.649 ;
     RECT  40.2 2.151 40.512 170.649 ;
     RECT  45.6 2.151 45.912 170.649 ;
     RECT  51 2.151 51.312 170.649 ;
     RECT  56.4 2.151 56.712 170.649 ;
     RECT  115.8 167.267 116.112 170.649 ;
     RECT  121.2 2.151 121.512 170.649 ;
     RECT  126.6 74.387 126.912 170.649 ;
     RECT  132 2.151 132.312 170.649 ;
     RECT  137.4 2.151 137.712 170.649 ;
     RECT  142.8 2.151 143.112 170.649 ;
     RECT  148.2 2.151 148.512 170.649 ;
     RECT  153.6 2.151 153.912 170.649 ;
     RECT  159 2.151 159.312 170.649 ;
     RECT  164.4 128.339 164.712 170.649 ;
     RECT  169.8 87.443 170.112 170.649 ;
     RECT  2.4 170.649 2.52 170.663 ;
     RECT  7.8 170.649 7.92 170.663 ;
     RECT  13.2 170.649 13.32 170.663 ;
     RECT  18.6 170.649 18.72 170.663 ;
     RECT  24 170.649 24.12 170.663 ;
     RECT  29.4 170.649 29.52 170.663 ;
     RECT  34.8 170.649 34.92 170.663 ;
     RECT  40.2 170.649 40.32 170.663 ;
     RECT  45.6 170.649 45.72 170.663 ;
     RECT  51 170.649 51.12 170.663 ;
     RECT  56.4 170.649 56.52 170.663 ;
     RECT  115.8 170.649 115.92 170.663 ;
     RECT  121.2 170.649 121.32 170.663 ;
     RECT  126.6 170.649 126.72 170.663 ;
     RECT  132 170.649 132.12 170.663 ;
     RECT  137.4 170.649 137.52 170.663 ;
     RECT  142.8 170.649 142.92 170.663 ;
     RECT  148.2 170.649 148.32 170.663 ;
     RECT  153.6 170.649 153.72 170.663 ;
     RECT  159 170.649 159.12 170.663 ;
     RECT  164.4 170.649 164.52 170.663 ;
     RECT  169.8 170.649 169.92 170.663 ;
     RECT  60.048 170.533 67.752 170.725 ;
     RECT  69.024 170.581 70.056 170.725 ;
     RECT  77.136 170.437 95.016 170.725 ;
     RECT  96.048 170.437 113.448 170.725 ;
     RECT  60.048 170.725 70.056 170.773 ;
     RECT  60.048 170.773 70.536 170.821 ;
     RECT  71.664 170.437 75.816 170.821 ;
     RECT  60.048 170.821 75.816 170.917 ;
     RECT  60.048 170.917 76.008 170.965 ;
     RECT  77.136 170.725 114.312 170.965 ;
     RECT  60.048 170.965 114.408 172.117 ;
     RECT  59.952 172.117 114.408 172.752 ;
  END
END dsdv_idx_vmux_n32
END LIBRARY
